VERSION 5.8 ;
BUSBITCHARS "[]" ;
DIVIDERCHAR "/" ;
UNITS
    DATABASE MICRONS 1000 ;
END UNITS

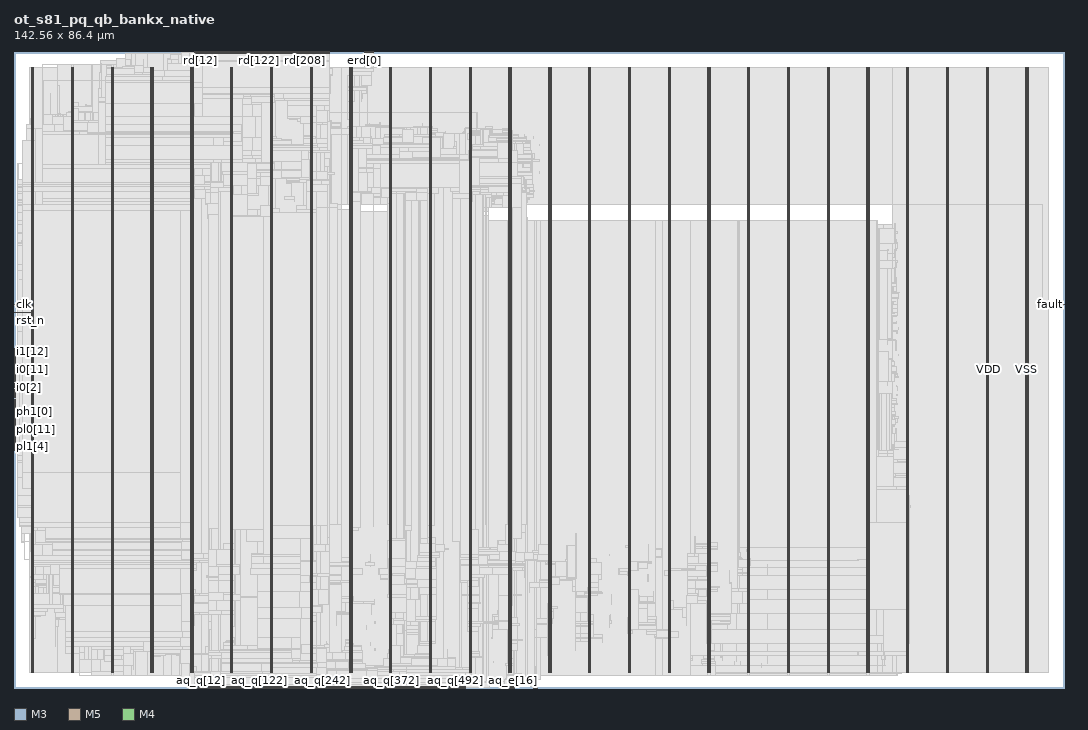
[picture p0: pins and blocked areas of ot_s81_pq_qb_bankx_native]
MACRO ot_s81_pq_qb_bankx_native
  FOREIGN ot_s81_pq_qb_bankx_native 0 0 ;
  CLASS BLOCK ;
  SIZE 142.56 BY 86.4 ;
  PIN aq_e[0]
    DIRECTION INPUT ;
    USE SIGNAL ;
    PORT
      LAYER M3 ;
        RECT  66.528 0 66.546 0.144 ;
    END
  END aq_e[0]
  PIN aq_e[10]
    DIRECTION INPUT ;
    USE SIGNAL ;
    PORT
      LAYER M3 ;
        RECT  67.248 0 67.266 0.144 ;
    END
  END aq_e[10]
  PIN aq_e[11]
    DIRECTION INPUT ;
    USE SIGNAL ;
    PORT
      LAYER M5 ;
        RECT  67.296 0 67.32 0.192 ;
    END
  END aq_e[11]
  PIN aq_e[12]
    DIRECTION INPUT ;
    USE SIGNAL ;
    PORT
      LAYER M3 ;
        RECT  67.392 0 67.41 0.144 ;
    END
  END aq_e[12]
  PIN aq_e[13]
    DIRECTION INPUT ;
    USE SIGNAL ;
    PORT
      LAYER M5 ;
        RECT  67.44 0 67.464 0.192 ;
    END
  END aq_e[13]
  PIN aq_e[14]
    DIRECTION INPUT ;
    USE SIGNAL ;
    PORT
      LAYER M3 ;
        RECT  67.536 0 67.554 0.144 ;
    END
  END aq_e[14]
  PIN aq_e[15]
    DIRECTION INPUT ;
    USE SIGNAL ;
    PORT
      LAYER M5 ;
        RECT  67.584 0 67.608 0.192 ;
    END
  END aq_e[15]
  PIN aq_e[16]
    DIRECTION INPUT ;
    USE SIGNAL ;
    PORT
      LAYER M3 ;
        RECT  67.68 0 67.698 0.144 ;
    END
  END aq_e[16]
  PIN aq_e[17]
    DIRECTION INPUT ;
    USE SIGNAL ;
    PORT
      LAYER M5 ;
        RECT  67.728 0 67.752 0.192 ;
    END
  END aq_e[17]
  PIN aq_e[18]
    DIRECTION INPUT ;
    USE SIGNAL ;
    PORT
      LAYER M3 ;
        RECT  67.824 0 67.842 0.144 ;
    END
  END aq_e[18]
  PIN aq_e[19]
    DIRECTION INPUT ;
    USE SIGNAL ;
    PORT
      LAYER M5 ;
        RECT  67.872 0 67.896 0.192 ;
    END
  END aq_e[19]
  PIN aq_e[1]
    DIRECTION INPUT ;
    USE SIGNAL ;
    PORT
      LAYER M5 ;
        RECT  66.576 0 66.6 0.192 ;
    END
  END aq_e[1]
  PIN aq_e[2]
    DIRECTION INPUT ;
    USE SIGNAL ;
    PORT
      LAYER M3 ;
        RECT  66.672 0 66.69 0.144 ;
    END
  END aq_e[2]
  PIN aq_e[3]
    DIRECTION INPUT ;
    USE SIGNAL ;
    PORT
      LAYER M5 ;
        RECT  66.72 0 66.744 0.192 ;
    END
  END aq_e[3]
  PIN aq_e[4]
    DIRECTION INPUT ;
    USE SIGNAL ;
    PORT
      LAYER M3 ;
        RECT  66.816 0 66.834 0.144 ;
    END
  END aq_e[4]
  PIN aq_e[5]
    DIRECTION INPUT ;
    USE SIGNAL ;
    PORT
      LAYER M5 ;
        RECT  66.864 0 66.888 0.192 ;
    END
  END aq_e[5]
  PIN aq_e[6]
    DIRECTION INPUT ;
    USE SIGNAL ;
    PORT
      LAYER M3 ;
        RECT  66.96 0 66.978 0.144 ;
    END
  END aq_e[6]
  PIN aq_e[7]
    DIRECTION INPUT ;
    USE SIGNAL ;
    PORT
      LAYER M5 ;
        RECT  67.008 0 67.032 0.192 ;
    END
  END aq_e[7]
  PIN aq_e[8]
    DIRECTION INPUT ;
    USE SIGNAL ;
    PORT
      LAYER M3 ;
        RECT  67.104 0 67.122 0.144 ;
    END
  END aq_e[8]
  PIN aq_e[9]
    DIRECTION INPUT ;
    USE SIGNAL ;
    PORT
      LAYER M5 ;
        RECT  67.152 0 67.176 0.192 ;
    END
  END aq_e[9]
  PIN aq_p[0]
    DIRECTION INPUT ;
    USE SIGNAL ;
    PORT
      LAYER M3 ;
        RECT  70.488 0 70.506 0.144 ;
    END
  END aq_p[0]
  PIN aq_p[1]
    DIRECTION INPUT ;
    USE SIGNAL ;
    PORT
      LAYER M5 ;
        RECT  70.512 0 70.536 0.192 ;
    END
  END aq_p[1]
  PIN aq_p[2]
    DIRECTION INPUT ;
    USE SIGNAL ;
    PORT
      LAYER M3 ;
        RECT  70.632 0 70.65 0.144 ;
    END
  END aq_p[2]
  PIN aq_p[3]
    DIRECTION INPUT ;
    USE SIGNAL ;
    PORT
      LAYER M5 ;
        RECT  70.656 0 70.68 0.192 ;
    END
  END aq_p[3]
  PIN aq_p[4]
    DIRECTION INPUT ;
    USE SIGNAL ;
    PORT
      LAYER M3 ;
        RECT  70.776 0 70.794 0.144 ;
    END
  END aq_p[4]
  PIN aq_p[5]
    DIRECTION INPUT ;
    USE SIGNAL ;
    PORT
      LAYER M5 ;
        RECT  70.8 0 70.824 0.192 ;
    END
  END aq_p[5]
  PIN aq_p[6]
    DIRECTION INPUT ;
    USE SIGNAL ;
    PORT
      LAYER M3 ;
        RECT  70.92 0 70.938 0.144 ;
    END
  END aq_p[6]
  PIN aq_p[7]
    DIRECTION INPUT ;
    USE SIGNAL ;
    PORT
      LAYER M5 ;
        RECT  70.944 0 70.968 0.192 ;
    END
  END aq_p[7]
  PIN aq_p[8]
    DIRECTION INPUT ;
    USE SIGNAL ;
    PORT
      LAYER M3 ;
        RECT  71.064 0 71.082 0.144 ;
    END
  END aq_p[8]
  PIN aq_p[9]
    DIRECTION INPUT ;
    USE SIGNAL ;
    PORT
      LAYER M5 ;
        RECT  71.088 0 71.112 0.192 ;
    END
  END aq_p[9]
  PIN aq_q[0]
    DIRECTION INPUT ;
    USE SIGNAL ;
    PORT
      LAYER M3 ;
        RECT  24.48 0 24.498 0.144 ;
    END
  END aq_q[0]
  PIN aq_q[100]
    DIRECTION INPUT ;
    USE SIGNAL ;
    PORT
      LAYER M3 ;
        RECT  31.68 0 31.698 0.144 ;
    END
  END aq_q[100]
  PIN aq_q[101]
    DIRECTION INPUT ;
    USE SIGNAL ;
    PORT
      LAYER M5 ;
        RECT  31.728 0 31.752 0.192 ;
    END
  END aq_q[101]
  PIN aq_q[102]
    DIRECTION INPUT ;
    USE SIGNAL ;
    PORT
      LAYER M3 ;
        RECT  31.824 0 31.842 0.144 ;
    END
  END aq_q[102]
  PIN aq_q[103]
    DIRECTION INPUT ;
    USE SIGNAL ;
    PORT
      LAYER M5 ;
        RECT  31.872 0 31.896 0.192 ;
    END
  END aq_q[103]
  PIN aq_q[104]
    DIRECTION INPUT ;
    USE SIGNAL ;
    PORT
      LAYER M3 ;
        RECT  31.968 0 31.986 0.144 ;
    END
  END aq_q[104]
  PIN aq_q[105]
    DIRECTION INPUT ;
    USE SIGNAL ;
    PORT
      LAYER M5 ;
        RECT  32.016 0 32.04 0.192 ;
    END
  END aq_q[105]
  PIN aq_q[106]
    DIRECTION INPUT ;
    USE SIGNAL ;
    PORT
      LAYER M3 ;
        RECT  32.112 0 32.13 0.144 ;
    END
  END aq_q[106]
  PIN aq_q[107]
    DIRECTION INPUT ;
    USE SIGNAL ;
    PORT
      LAYER M5 ;
        RECT  32.16 0 32.184 0.192 ;
    END
  END aq_q[107]
  PIN aq_q[108]
    DIRECTION INPUT ;
    USE SIGNAL ;
    PORT
      LAYER M3 ;
        RECT  32.256 0 32.274 0.144 ;
    END
  END aq_q[108]
  PIN aq_q[109]
    DIRECTION INPUT ;
    USE SIGNAL ;
    PORT
      LAYER M5 ;
        RECT  32.304 0 32.328 0.192 ;
    END
  END aq_q[109]
  PIN aq_q[10]
    DIRECTION INPUT ;
    USE SIGNAL ;
    PORT
      LAYER M3 ;
        RECT  25.2 0 25.218 0.144 ;
    END
  END aq_q[10]
  PIN aq_q[110]
    DIRECTION INPUT ;
    USE SIGNAL ;
    PORT
      LAYER M3 ;
        RECT  32.4 0 32.418 0.144 ;
    END
  END aq_q[110]
  PIN aq_q[111]
    DIRECTION INPUT ;
    USE SIGNAL ;
    PORT
      LAYER M5 ;
        RECT  32.448 0 32.472 0.192 ;
    END
  END aq_q[111]
  PIN aq_q[112]
    DIRECTION INPUT ;
    USE SIGNAL ;
    PORT
      LAYER M3 ;
        RECT  32.544 0 32.562 0.144 ;
    END
  END aq_q[112]
  PIN aq_q[113]
    DIRECTION INPUT ;
    USE SIGNAL ;
    PORT
      LAYER M5 ;
        RECT  32.592 0 32.616 0.192 ;
    END
  END aq_q[113]
  PIN aq_q[114]
    DIRECTION INPUT ;
    USE SIGNAL ;
    PORT
      LAYER M3 ;
        RECT  32.688 0 32.706 0.144 ;
    END
  END aq_q[114]
  PIN aq_q[115]
    DIRECTION INPUT ;
    USE SIGNAL ;
    PORT
      LAYER M5 ;
        RECT  32.736 0 32.76 0.192 ;
    END
  END aq_q[115]
  PIN aq_q[116]
    DIRECTION INPUT ;
    USE SIGNAL ;
    PORT
      LAYER M3 ;
        RECT  32.832 0 32.85 0.144 ;
    END
  END aq_q[116]
  PIN aq_q[117]
    DIRECTION INPUT ;
    USE SIGNAL ;
    PORT
      LAYER M5 ;
        RECT  32.88 0 32.904 0.192 ;
    END
  END aq_q[117]
  PIN aq_q[118]
    DIRECTION INPUT ;
    USE SIGNAL ;
    PORT
      LAYER M3 ;
        RECT  32.976 0 32.994 0.144 ;
    END
  END aq_q[118]
  PIN aq_q[119]
    DIRECTION INPUT ;
    USE SIGNAL ;
    PORT
      LAYER M5 ;
        RECT  33.024 0 33.048 0.192 ;
    END
  END aq_q[119]
  PIN aq_q[11]
    DIRECTION INPUT ;
    USE SIGNAL ;
    PORT
      LAYER M5 ;
        RECT  25.248 0 25.272 0.192 ;
    END
  END aq_q[11]
  PIN aq_q[120]
    DIRECTION INPUT ;
    USE SIGNAL ;
    PORT
      LAYER M3 ;
        RECT  33.12 0 33.138 0.144 ;
    END
  END aq_q[120]
  PIN aq_q[121]
    DIRECTION INPUT ;
    USE SIGNAL ;
    PORT
      LAYER M5 ;
        RECT  33.168 0 33.192 0.192 ;
    END
  END aq_q[121]
  PIN aq_q[122]
    DIRECTION INPUT ;
    USE SIGNAL ;
    PORT
      LAYER M3 ;
        RECT  33.264 0 33.282 0.144 ;
    END
  END aq_q[122]
  PIN aq_q[123]
    DIRECTION INPUT ;
    USE SIGNAL ;
    PORT
      LAYER M5 ;
        RECT  33.312 0 33.336 0.192 ;
    END
  END aq_q[123]
  PIN aq_q[124]
    DIRECTION INPUT ;
    USE SIGNAL ;
    PORT
      LAYER M3 ;
        RECT  33.408 0 33.426 0.144 ;
    END
  END aq_q[124]
  PIN aq_q[125]
    DIRECTION INPUT ;
    USE SIGNAL ;
    PORT
      LAYER M5 ;
        RECT  33.456 0 33.48 0.192 ;
    END
  END aq_q[125]
  PIN aq_q[126]
    DIRECTION INPUT ;
    USE SIGNAL ;
    PORT
      LAYER M3 ;
        RECT  33.552 0 33.57 0.144 ;
    END
  END aq_q[126]
  PIN aq_q[127]
    DIRECTION INPUT ;
    USE SIGNAL ;
    PORT
      LAYER M5 ;
        RECT  33.6 0 33.624 0.192 ;
    END
  END aq_q[127]
  PIN aq_q[128]
    DIRECTION INPUT ;
    USE SIGNAL ;
    PORT
      LAYER M3 ;
        RECT  33.696 0 33.714 0.144 ;
    END
  END aq_q[128]
  PIN aq_q[129]
    DIRECTION INPUT ;
    USE SIGNAL ;
    PORT
      LAYER M5 ;
        RECT  33.744 0 33.768 0.192 ;
    END
  END aq_q[129]
  PIN aq_q[12]
    DIRECTION INPUT ;
    USE SIGNAL ;
    PORT
      LAYER M3 ;
        RECT  25.344 0 25.362 0.144 ;
    END
  END aq_q[12]
  PIN aq_q[130]
    DIRECTION INPUT ;
    USE SIGNAL ;
    PORT
      LAYER M3 ;
        RECT  33.84 0 33.858 0.144 ;
    END
  END aq_q[130]
  PIN aq_q[131]
    DIRECTION INPUT ;
    USE SIGNAL ;
    PORT
      LAYER M5 ;
        RECT  33.888 0 33.912 0.192 ;
    END
  END aq_q[131]
  PIN aq_q[132]
    DIRECTION INPUT ;
    USE SIGNAL ;
    PORT
      LAYER M3 ;
        RECT  33.984 0 34.002 0.144 ;
    END
  END aq_q[132]
  PIN aq_q[133]
    DIRECTION INPUT ;
    USE SIGNAL ;
    PORT
      LAYER M5 ;
        RECT  34.032 0 34.056 0.192 ;
    END
  END aq_q[133]
  PIN aq_q[134]
    DIRECTION INPUT ;
    USE SIGNAL ;
    PORT
      LAYER M3 ;
        RECT  34.128 0 34.146 0.144 ;
    END
  END aq_q[134]
  PIN aq_q[135]
    DIRECTION INPUT ;
    USE SIGNAL ;
    PORT
      LAYER M5 ;
        RECT  34.176 0 34.2 0.192 ;
    END
  END aq_q[135]
  PIN aq_q[136]
    DIRECTION INPUT ;
    USE SIGNAL ;
    PORT
      LAYER M3 ;
        RECT  34.272 0 34.29 0.144 ;
    END
  END aq_q[136]
  PIN aq_q[137]
    DIRECTION INPUT ;
    USE SIGNAL ;
    PORT
      LAYER M5 ;
        RECT  34.32 0 34.344 0.192 ;
    END
  END aq_q[137]
  PIN aq_q[138]
    DIRECTION INPUT ;
    USE SIGNAL ;
    PORT
      LAYER M3 ;
        RECT  34.416 0 34.434 0.144 ;
    END
  END aq_q[138]
  PIN aq_q[139]
    DIRECTION INPUT ;
    USE SIGNAL ;
    PORT
      LAYER M5 ;
        RECT  34.464 0 34.488 0.192 ;
    END
  END aq_q[139]
  PIN aq_q[13]
    DIRECTION INPUT ;
    USE SIGNAL ;
    PORT
      LAYER M5 ;
        RECT  25.392 0 25.416 0.192 ;
    END
  END aq_q[13]
  PIN aq_q[140]
    DIRECTION INPUT ;
    USE SIGNAL ;
    PORT
      LAYER M3 ;
        RECT  34.56 0 34.578 0.144 ;
    END
  END aq_q[140]
  PIN aq_q[141]
    DIRECTION INPUT ;
    USE SIGNAL ;
    PORT
      LAYER M5 ;
        RECT  34.608 0 34.632 0.192 ;
    END
  END aq_q[141]
  PIN aq_q[142]
    DIRECTION INPUT ;
    USE SIGNAL ;
    PORT
      LAYER M3 ;
        RECT  34.704 0 34.722 0.144 ;
    END
  END aq_q[142]
  PIN aq_q[143]
    DIRECTION INPUT ;
    USE SIGNAL ;
    PORT
      LAYER M5 ;
        RECT  34.752 0 34.776 0.192 ;
    END
  END aq_q[143]
  PIN aq_q[144]
    DIRECTION INPUT ;
    USE SIGNAL ;
    PORT
      LAYER M3 ;
        RECT  34.848 0 34.866 0.144 ;
    END
  END aq_q[144]
  PIN aq_q[145]
    DIRECTION INPUT ;
    USE SIGNAL ;
    PORT
      LAYER M5 ;
        RECT  34.896 0 34.92 0.192 ;
    END
  END aq_q[145]
  PIN aq_q[146]
    DIRECTION INPUT ;
    USE SIGNAL ;
    PORT
      LAYER M3 ;
        RECT  34.992 0 35.01 0.144 ;
    END
  END aq_q[146]
  PIN aq_q[147]
    DIRECTION INPUT ;
    USE SIGNAL ;
    PORT
      LAYER M5 ;
        RECT  35.04 0 35.064 0.192 ;
    END
  END aq_q[147]
  PIN aq_q[148]
    DIRECTION INPUT ;
    USE SIGNAL ;
    PORT
      LAYER M3 ;
        RECT  35.136 0 35.154 0.144 ;
    END
  END aq_q[148]
  PIN aq_q[149]
    DIRECTION INPUT ;
    USE SIGNAL ;
    PORT
      LAYER M5 ;
        RECT  35.184 0 35.208 0.192 ;
    END
  END aq_q[149]
  PIN aq_q[14]
    DIRECTION INPUT ;
    USE SIGNAL ;
    PORT
      LAYER M3 ;
        RECT  25.488 0 25.506 0.144 ;
    END
  END aq_q[14]
  PIN aq_q[150]
    DIRECTION INPUT ;
    USE SIGNAL ;
    PORT
      LAYER M3 ;
        RECT  35.28 0 35.298 0.144 ;
    END
  END aq_q[150]
  PIN aq_q[151]
    DIRECTION INPUT ;
    USE SIGNAL ;
    PORT
      LAYER M5 ;
        RECT  35.328 0 35.352 0.192 ;
    END
  END aq_q[151]
  PIN aq_q[152]
    DIRECTION INPUT ;
    USE SIGNAL ;
    PORT
      LAYER M3 ;
        RECT  35.424 0 35.442 0.144 ;
    END
  END aq_q[152]
  PIN aq_q[153]
    DIRECTION INPUT ;
    USE SIGNAL ;
    PORT
      LAYER M5 ;
        RECT  35.472 0 35.496 0.192 ;
    END
  END aq_q[153]
  PIN aq_q[154]
    DIRECTION INPUT ;
    USE SIGNAL ;
    PORT
      LAYER M3 ;
        RECT  35.568 0 35.586 0.144 ;
    END
  END aq_q[154]
  PIN aq_q[155]
    DIRECTION INPUT ;
    USE SIGNAL ;
    PORT
      LAYER M5 ;
        RECT  35.616 0 35.64 0.192 ;
    END
  END aq_q[155]
  PIN aq_q[156]
    DIRECTION INPUT ;
    USE SIGNAL ;
    PORT
      LAYER M3 ;
        RECT  35.712 0 35.73 0.144 ;
    END
  END aq_q[156]
  PIN aq_q[157]
    DIRECTION INPUT ;
    USE SIGNAL ;
    PORT
      LAYER M5 ;
        RECT  35.76 0 35.784 0.192 ;
    END
  END aq_q[157]
  PIN aq_q[158]
    DIRECTION INPUT ;
    USE SIGNAL ;
    PORT
      LAYER M3 ;
        RECT  35.856 0 35.874 0.144 ;
    END
  END aq_q[158]
  PIN aq_q[159]
    DIRECTION INPUT ;
    USE SIGNAL ;
    PORT
      LAYER M5 ;
        RECT  35.904 0 35.928 0.192 ;
    END
  END aq_q[159]
  PIN aq_q[15]
    DIRECTION INPUT ;
    USE SIGNAL ;
    PORT
      LAYER M5 ;
        RECT  25.536 0 25.56 0.192 ;
    END
  END aq_q[15]
  PIN aq_q[160]
    DIRECTION INPUT ;
    USE SIGNAL ;
    PORT
      LAYER M3 ;
        RECT  36 0 36.018 0.144 ;
    END
  END aq_q[160]
  PIN aq_q[161]
    DIRECTION INPUT ;
    USE SIGNAL ;
    PORT
      LAYER M5 ;
        RECT  36.048 0 36.072 0.192 ;
    END
  END aq_q[161]
  PIN aq_q[162]
    DIRECTION INPUT ;
    USE SIGNAL ;
    PORT
      LAYER M3 ;
        RECT  36.144 0 36.162 0.144 ;
    END
  END aq_q[162]
  PIN aq_q[163]
    DIRECTION INPUT ;
    USE SIGNAL ;
    PORT
      LAYER M5 ;
        RECT  36.192 0 36.216 0.192 ;
    END
  END aq_q[163]
  PIN aq_q[164]
    DIRECTION INPUT ;
    USE SIGNAL ;
    PORT
      LAYER M3 ;
        RECT  36.288 0 36.306 0.144 ;
    END
  END aq_q[164]
  PIN aq_q[165]
    DIRECTION INPUT ;
    USE SIGNAL ;
    PORT
      LAYER M5 ;
        RECT  36.336 0 36.36 0.192 ;
    END
  END aq_q[165]
  PIN aq_q[166]
    DIRECTION INPUT ;
    USE SIGNAL ;
    PORT
      LAYER M3 ;
        RECT  36.432 0 36.45 0.144 ;
    END
  END aq_q[166]
  PIN aq_q[167]
    DIRECTION INPUT ;
    USE SIGNAL ;
    PORT
      LAYER M5 ;
        RECT  36.48 0 36.504 0.192 ;
    END
  END aq_q[167]
  PIN aq_q[168]
    DIRECTION INPUT ;
    USE SIGNAL ;
    PORT
      LAYER M3 ;
        RECT  36.576 0 36.594 0.144 ;
    END
  END aq_q[168]
  PIN aq_q[169]
    DIRECTION INPUT ;
    USE SIGNAL ;
    PORT
      LAYER M5 ;
        RECT  36.624 0 36.648 0.192 ;
    END
  END aq_q[169]
  PIN aq_q[16]
    DIRECTION INPUT ;
    USE SIGNAL ;
    PORT
      LAYER M3 ;
        RECT  25.632 0 25.65 0.144 ;
    END
  END aq_q[16]
  PIN aq_q[170]
    DIRECTION INPUT ;
    USE SIGNAL ;
    PORT
      LAYER M3 ;
        RECT  36.72 0 36.738 0.144 ;
    END
  END aq_q[170]
  PIN aq_q[171]
    DIRECTION INPUT ;
    USE SIGNAL ;
    PORT
      LAYER M5 ;
        RECT  36.768 0 36.792 0.192 ;
    END
  END aq_q[171]
  PIN aq_q[172]
    DIRECTION INPUT ;
    USE SIGNAL ;
    PORT
      LAYER M3 ;
        RECT  36.864 0 36.882 0.144 ;
    END
  END aq_q[172]
  PIN aq_q[173]
    DIRECTION INPUT ;
    USE SIGNAL ;
    PORT
      LAYER M5 ;
        RECT  36.912 0 36.936 0.192 ;
    END
  END aq_q[173]
  PIN aq_q[174]
    DIRECTION INPUT ;
    USE SIGNAL ;
    PORT
      LAYER M3 ;
        RECT  37.008 0 37.026 0.144 ;
    END
  END aq_q[174]
  PIN aq_q[175]
    DIRECTION INPUT ;
    USE SIGNAL ;
    PORT
      LAYER M5 ;
        RECT  37.056 0 37.08 0.192 ;
    END
  END aq_q[175]
  PIN aq_q[176]
    DIRECTION INPUT ;
    USE SIGNAL ;
    PORT
      LAYER M3 ;
        RECT  37.152 0 37.17 0.144 ;
    END
  END aq_q[176]
  PIN aq_q[177]
    DIRECTION INPUT ;
    USE SIGNAL ;
    PORT
      LAYER M5 ;
        RECT  37.2 0 37.224 0.192 ;
    END
  END aq_q[177]
  PIN aq_q[178]
    DIRECTION INPUT ;
    USE SIGNAL ;
    PORT
      LAYER M3 ;
        RECT  37.296 0 37.314 0.144 ;
    END
  END aq_q[178]
  PIN aq_q[179]
    DIRECTION INPUT ;
    USE SIGNAL ;
    PORT
      LAYER M5 ;
        RECT  37.344 0 37.368 0.192 ;
    END
  END aq_q[179]
  PIN aq_q[17]
    DIRECTION INPUT ;
    USE SIGNAL ;
    PORT
      LAYER M5 ;
        RECT  25.68 0 25.704 0.192 ;
    END
  END aq_q[17]
  PIN aq_q[180]
    DIRECTION INPUT ;
    USE SIGNAL ;
    PORT
      LAYER M3 ;
        RECT  37.44 0 37.458 0.144 ;
    END
  END aq_q[180]
  PIN aq_q[181]
    DIRECTION INPUT ;
    USE SIGNAL ;
    PORT
      LAYER M5 ;
        RECT  37.488 0 37.512 0.192 ;
    END
  END aq_q[181]
  PIN aq_q[182]
    DIRECTION INPUT ;
    USE SIGNAL ;
    PORT
      LAYER M3 ;
        RECT  37.584 0 37.602 0.144 ;
    END
  END aq_q[182]
  PIN aq_q[183]
    DIRECTION INPUT ;
    USE SIGNAL ;
    PORT
      LAYER M5 ;
        RECT  37.632 0 37.656 0.192 ;
    END
  END aq_q[183]
  PIN aq_q[184]
    DIRECTION INPUT ;
    USE SIGNAL ;
    PORT
      LAYER M3 ;
        RECT  37.728 0 37.746 0.144 ;
    END
  END aq_q[184]
  PIN aq_q[185]
    DIRECTION INPUT ;
    USE SIGNAL ;
    PORT
      LAYER M5 ;
        RECT  37.776 0 37.8 0.192 ;
    END
  END aq_q[185]
  PIN aq_q[186]
    DIRECTION INPUT ;
    USE SIGNAL ;
    PORT
      LAYER M3 ;
        RECT  37.872 0 37.89 0.144 ;
    END
  END aq_q[186]
  PIN aq_q[187]
    DIRECTION INPUT ;
    USE SIGNAL ;
    PORT
      LAYER M5 ;
        RECT  37.92 0 37.944 0.192 ;
    END
  END aq_q[187]
  PIN aq_q[188]
    DIRECTION INPUT ;
    USE SIGNAL ;
    PORT
      LAYER M3 ;
        RECT  38.016 0 38.034 0.144 ;
    END
  END aq_q[188]
  PIN aq_q[189]
    DIRECTION INPUT ;
    USE SIGNAL ;
    PORT
      LAYER M5 ;
        RECT  38.064 0 38.088 0.192 ;
    END
  END aq_q[189]
  PIN aq_q[18]
    DIRECTION INPUT ;
    USE SIGNAL ;
    PORT
      LAYER M3 ;
        RECT  25.776 0 25.794 0.144 ;
    END
  END aq_q[18]
  PIN aq_q[190]
    DIRECTION INPUT ;
    USE SIGNAL ;
    PORT
      LAYER M3 ;
        RECT  38.16 0 38.178 0.144 ;
    END
  END aq_q[190]
  PIN aq_q[191]
    DIRECTION INPUT ;
    USE SIGNAL ;
    PORT
      LAYER M5 ;
        RECT  38.208 0 38.232 0.192 ;
    END
  END aq_q[191]
  PIN aq_q[192]
    DIRECTION INPUT ;
    USE SIGNAL ;
    PORT
      LAYER M3 ;
        RECT  38.304 0 38.322 0.144 ;
    END
  END aq_q[192]
  PIN aq_q[193]
    DIRECTION INPUT ;
    USE SIGNAL ;
    PORT
      LAYER M5 ;
        RECT  38.352 0 38.376 0.192 ;
    END
  END aq_q[193]
  PIN aq_q[194]
    DIRECTION INPUT ;
    USE SIGNAL ;
    PORT
      LAYER M3 ;
        RECT  38.448 0 38.466 0.144 ;
    END
  END aq_q[194]
  PIN aq_q[195]
    DIRECTION INPUT ;
    USE SIGNAL ;
    PORT
      LAYER M5 ;
        RECT  38.496 0 38.52 0.192 ;
    END
  END aq_q[195]
  PIN aq_q[196]
    DIRECTION INPUT ;
    USE SIGNAL ;
    PORT
      LAYER M3 ;
        RECT  38.592 0 38.61 0.144 ;
    END
  END aq_q[196]
  PIN aq_q[197]
    DIRECTION INPUT ;
    USE SIGNAL ;
    PORT
      LAYER M5 ;
        RECT  38.64 0 38.664 0.192 ;
    END
  END aq_q[197]
  PIN aq_q[198]
    DIRECTION INPUT ;
    USE SIGNAL ;
    PORT
      LAYER M3 ;
        RECT  38.736 0 38.754 0.144 ;
    END
  END aq_q[198]
  PIN aq_q[199]
    DIRECTION INPUT ;
    USE SIGNAL ;
    PORT
      LAYER M5 ;
        RECT  38.784 0 38.808 0.192 ;
    END
  END aq_q[199]
  PIN aq_q[19]
    DIRECTION INPUT ;
    USE SIGNAL ;
    PORT
      LAYER M5 ;
        RECT  25.824 0 25.848 0.192 ;
    END
  END aq_q[19]
  PIN aq_q[1]
    DIRECTION INPUT ;
    USE SIGNAL ;
    PORT
      LAYER M5 ;
        RECT  24.528 0 24.552 0.192 ;
    END
  END aq_q[1]
  PIN aq_q[200]
    DIRECTION INPUT ;
    USE SIGNAL ;
    PORT
      LAYER M3 ;
        RECT  38.88 0 38.898 0.144 ;
    END
  END aq_q[200]
  PIN aq_q[201]
    DIRECTION INPUT ;
    USE SIGNAL ;
    PORT
      LAYER M5 ;
        RECT  38.928 0 38.952 0.192 ;
    END
  END aq_q[201]
  PIN aq_q[202]
    DIRECTION INPUT ;
    USE SIGNAL ;
    PORT
      LAYER M3 ;
        RECT  39.024 0 39.042 0.144 ;
    END
  END aq_q[202]
  PIN aq_q[203]
    DIRECTION INPUT ;
    USE SIGNAL ;
    PORT
      LAYER M5 ;
        RECT  39.072 0 39.096 0.192 ;
    END
  END aq_q[203]
  PIN aq_q[204]
    DIRECTION INPUT ;
    USE SIGNAL ;
    PORT
      LAYER M3 ;
        RECT  39.168 0 39.186 0.144 ;
    END
  END aq_q[204]
  PIN aq_q[205]
    DIRECTION INPUT ;
    USE SIGNAL ;
    PORT
      LAYER M5 ;
        RECT  39.216 0 39.24 0.192 ;
    END
  END aq_q[205]
  PIN aq_q[206]
    DIRECTION INPUT ;
    USE SIGNAL ;
    PORT
      LAYER M3 ;
        RECT  39.312 0 39.33 0.144 ;
    END
  END aq_q[206]
  PIN aq_q[207]
    DIRECTION INPUT ;
    USE SIGNAL ;
    PORT
      LAYER M5 ;
        RECT  39.36 0 39.384 0.192 ;
    END
  END aq_q[207]
  PIN aq_q[208]
    DIRECTION INPUT ;
    USE SIGNAL ;
    PORT
      LAYER M3 ;
        RECT  39.456 0 39.474 0.144 ;
    END
  END aq_q[208]
  PIN aq_q[209]
    DIRECTION INPUT ;
    USE SIGNAL ;
    PORT
      LAYER M5 ;
        RECT  39.504 0 39.528 0.192 ;
    END
  END aq_q[209]
  PIN aq_q[20]
    DIRECTION INPUT ;
    USE SIGNAL ;
    PORT
      LAYER M3 ;
        RECT  25.92 0 25.938 0.144 ;
    END
  END aq_q[20]
  PIN aq_q[210]
    DIRECTION INPUT ;
    USE SIGNAL ;
    PORT
      LAYER M3 ;
        RECT  39.6 0 39.618 0.144 ;
    END
  END aq_q[210]
  PIN aq_q[211]
    DIRECTION INPUT ;
    USE SIGNAL ;
    PORT
      LAYER M5 ;
        RECT  39.648 0 39.672 0.192 ;
    END
  END aq_q[211]
  PIN aq_q[212]
    DIRECTION INPUT ;
    USE SIGNAL ;
    PORT
      LAYER M3 ;
        RECT  39.744 0 39.762 0.144 ;
    END
  END aq_q[212]
  PIN aq_q[213]
    DIRECTION INPUT ;
    USE SIGNAL ;
    PORT
      LAYER M5 ;
        RECT  39.792 0 39.816 0.192 ;
    END
  END aq_q[213]
  PIN aq_q[214]
    DIRECTION INPUT ;
    USE SIGNAL ;
    PORT
      LAYER M3 ;
        RECT  39.888 0 39.906 0.144 ;
    END
  END aq_q[214]
  PIN aq_q[215]
    DIRECTION INPUT ;
    USE SIGNAL ;
    PORT
      LAYER M5 ;
        RECT  39.936 0 39.96 0.192 ;
    END
  END aq_q[215]
  PIN aq_q[216]
    DIRECTION INPUT ;
    USE SIGNAL ;
    PORT
      LAYER M3 ;
        RECT  40.032 0 40.05 0.144 ;
    END
  END aq_q[216]
  PIN aq_q[217]
    DIRECTION INPUT ;
    USE SIGNAL ;
    PORT
      LAYER M5 ;
        RECT  40.08 0 40.104 0.192 ;
    END
  END aq_q[217]
  PIN aq_q[218]
    DIRECTION INPUT ;
    USE SIGNAL ;
    PORT
      LAYER M3 ;
        RECT  40.176 0 40.194 0.144 ;
    END
  END aq_q[218]
  PIN aq_q[219]
    DIRECTION INPUT ;
    USE SIGNAL ;
    PORT
      LAYER M5 ;
        RECT  40.224 0 40.248 0.192 ;
    END
  END aq_q[219]
  PIN aq_q[21]
    DIRECTION INPUT ;
    USE SIGNAL ;
    PORT
      LAYER M5 ;
        RECT  25.968 0 25.992 0.192 ;
    END
  END aq_q[21]
  PIN aq_q[220]
    DIRECTION INPUT ;
    USE SIGNAL ;
    PORT
      LAYER M3 ;
        RECT  40.32 0 40.338 0.144 ;
    END
  END aq_q[220]
  PIN aq_q[221]
    DIRECTION INPUT ;
    USE SIGNAL ;
    PORT
      LAYER M5 ;
        RECT  40.368 0 40.392 0.192 ;
    END
  END aq_q[221]
  PIN aq_q[222]
    DIRECTION INPUT ;
    USE SIGNAL ;
    PORT
      LAYER M3 ;
        RECT  40.464 0 40.482 0.144 ;
    END
  END aq_q[222]
  PIN aq_q[223]
    DIRECTION INPUT ;
    USE SIGNAL ;
    PORT
      LAYER M5 ;
        RECT  40.512 0 40.536 0.192 ;
    END
  END aq_q[223]
  PIN aq_q[224]
    DIRECTION INPUT ;
    USE SIGNAL ;
    PORT
      LAYER M3 ;
        RECT  40.608 0 40.626 0.144 ;
    END
  END aq_q[224]
  PIN aq_q[225]
    DIRECTION INPUT ;
    USE SIGNAL ;
    PORT
      LAYER M5 ;
        RECT  40.656 0 40.68 0.192 ;
    END
  END aq_q[225]
  PIN aq_q[226]
    DIRECTION INPUT ;
    USE SIGNAL ;
    PORT
      LAYER M3 ;
        RECT  40.752 0 40.77 0.144 ;
    END
  END aq_q[226]
  PIN aq_q[227]
    DIRECTION INPUT ;
    USE SIGNAL ;
    PORT
      LAYER M5 ;
        RECT  40.8 0 40.824 0.192 ;
    END
  END aq_q[227]
  PIN aq_q[228]
    DIRECTION INPUT ;
    USE SIGNAL ;
    PORT
      LAYER M3 ;
        RECT  40.896 0 40.914 0.144 ;
    END
  END aq_q[228]
  PIN aq_q[229]
    DIRECTION INPUT ;
    USE SIGNAL ;
    PORT
      LAYER M5 ;
        RECT  40.944 0 40.968 0.192 ;
    END
  END aq_q[229]
  PIN aq_q[22]
    DIRECTION INPUT ;
    USE SIGNAL ;
    PORT
      LAYER M3 ;
        RECT  26.064 0 26.082 0.144 ;
    END
  END aq_q[22]
  PIN aq_q[230]
    DIRECTION INPUT ;
    USE SIGNAL ;
    PORT
      LAYER M3 ;
        RECT  41.04 0 41.058 0.144 ;
    END
  END aq_q[230]
  PIN aq_q[231]
    DIRECTION INPUT ;
    USE SIGNAL ;
    PORT
      LAYER M5 ;
        RECT  41.088 0 41.112 0.192 ;
    END
  END aq_q[231]
  PIN aq_q[232]
    DIRECTION INPUT ;
    USE SIGNAL ;
    PORT
      LAYER M3 ;
        RECT  41.184 0 41.202 0.144 ;
    END
  END aq_q[232]
  PIN aq_q[233]
    DIRECTION INPUT ;
    USE SIGNAL ;
    PORT
      LAYER M5 ;
        RECT  41.232 0 41.256 0.192 ;
    END
  END aq_q[233]
  PIN aq_q[234]
    DIRECTION INPUT ;
    USE SIGNAL ;
    PORT
      LAYER M3 ;
        RECT  41.328 0 41.346 0.144 ;
    END
  END aq_q[234]
  PIN aq_q[235]
    DIRECTION INPUT ;
    USE SIGNAL ;
    PORT
      LAYER M5 ;
        RECT  41.376 0 41.4 0.192 ;
    END
  END aq_q[235]
  PIN aq_q[236]
    DIRECTION INPUT ;
    USE SIGNAL ;
    PORT
      LAYER M3 ;
        RECT  41.472 0 41.49 0.144 ;
    END
  END aq_q[236]
  PIN aq_q[237]
    DIRECTION INPUT ;
    USE SIGNAL ;
    PORT
      LAYER M5 ;
        RECT  41.52 0 41.544 0.192 ;
    END
  END aq_q[237]
  PIN aq_q[238]
    DIRECTION INPUT ;
    USE SIGNAL ;
    PORT
      LAYER M3 ;
        RECT  41.616 0 41.634 0.144 ;
    END
  END aq_q[238]
  PIN aq_q[239]
    DIRECTION INPUT ;
    USE SIGNAL ;
    PORT
      LAYER M5 ;
        RECT  41.664 0 41.688 0.192 ;
    END
  END aq_q[239]
  PIN aq_q[23]
    DIRECTION INPUT ;
    USE SIGNAL ;
    PORT
      LAYER M5 ;
        RECT  26.112 0 26.136 0.192 ;
    END
  END aq_q[23]
  PIN aq_q[240]
    DIRECTION INPUT ;
    USE SIGNAL ;
    PORT
      LAYER M3 ;
        RECT  41.76 0 41.778 0.144 ;
    END
  END aq_q[240]
  PIN aq_q[241]
    DIRECTION INPUT ;
    USE SIGNAL ;
    PORT
      LAYER M5 ;
        RECT  41.808 0 41.832 0.192 ;
    END
  END aq_q[241]
  PIN aq_q[242]
    DIRECTION INPUT ;
    USE SIGNAL ;
    PORT
      LAYER M3 ;
        RECT  41.904 0 41.922 0.144 ;
    END
  END aq_q[242]
  PIN aq_q[243]
    DIRECTION INPUT ;
    USE SIGNAL ;
    PORT
      LAYER M5 ;
        RECT  41.952 0 41.976 0.192 ;
    END
  END aq_q[243]
  PIN aq_q[244]
    DIRECTION INPUT ;
    USE SIGNAL ;
    PORT
      LAYER M3 ;
        RECT  42.048 0 42.066 0.144 ;
    END
  END aq_q[244]
  PIN aq_q[245]
    DIRECTION INPUT ;
    USE SIGNAL ;
    PORT
      LAYER M5 ;
        RECT  42.096 0 42.12 0.192 ;
    END
  END aq_q[245]
  PIN aq_q[246]
    DIRECTION INPUT ;
    USE SIGNAL ;
    PORT
      LAYER M3 ;
        RECT  42.192 0 42.21 0.144 ;
    END
  END aq_q[246]
  PIN aq_q[247]
    DIRECTION INPUT ;
    USE SIGNAL ;
    PORT
      LAYER M5 ;
        RECT  42.24 0 42.264 0.192 ;
    END
  END aq_q[247]
  PIN aq_q[248]
    DIRECTION INPUT ;
    USE SIGNAL ;
    PORT
      LAYER M3 ;
        RECT  42.336 0 42.354 0.144 ;
    END
  END aq_q[248]
  PIN aq_q[249]
    DIRECTION INPUT ;
    USE SIGNAL ;
    PORT
      LAYER M5 ;
        RECT  42.384 0 42.408 0.192 ;
    END
  END aq_q[249]
  PIN aq_q[24]
    DIRECTION INPUT ;
    USE SIGNAL ;
    PORT
      LAYER M3 ;
        RECT  26.208 0 26.226 0.144 ;
    END
  END aq_q[24]
  PIN aq_q[250]
    DIRECTION INPUT ;
    USE SIGNAL ;
    PORT
      LAYER M3 ;
        RECT  42.48 0 42.498 0.144 ;
    END
  END aq_q[250]
  PIN aq_q[251]
    DIRECTION INPUT ;
    USE SIGNAL ;
    PORT
      LAYER M5 ;
        RECT  42.528 0 42.552 0.192 ;
    END
  END aq_q[251]
  PIN aq_q[252]
    DIRECTION INPUT ;
    USE SIGNAL ;
    PORT
      LAYER M3 ;
        RECT  42.624 0 42.642 0.144 ;
    END
    PORT
      LAYER M3 ;
        RECT  42.588 0.067 42.714 0.103 ;
    END
  END aq_q[252]
  PIN aq_q[253]
    DIRECTION INPUT ;
    USE SIGNAL ;
    PORT
      LAYER M5 ;
        RECT  42.672 0 42.696 0.192 ;
    END
  END aq_q[253]
  PIN aq_q[254]
    DIRECTION INPUT ;
    USE SIGNAL ;
    PORT
      LAYER M3 ;
        RECT  42.768 0 42.786 0.144 ;
    END
  END aq_q[254]
  PIN aq_q[255]
    DIRECTION INPUT ;
    USE SIGNAL ;
    PORT
      LAYER M5 ;
        RECT  42.816 0 42.84 0.192 ;
    END
  END aq_q[255]
  PIN aq_q[256]
    DIRECTION INPUT ;
    USE SIGNAL ;
    PORT
      LAYER M3 ;
        RECT  42.912 0 42.93 0.144 ;
    END
  END aq_q[256]
  PIN aq_q[257]
    DIRECTION INPUT ;
    USE SIGNAL ;
    PORT
      LAYER M5 ;
        RECT  42.96 0 42.984 0.192 ;
    END
  END aq_q[257]
  PIN aq_q[258]
    DIRECTION INPUT ;
    USE SIGNAL ;
    PORT
      LAYER M3 ;
        RECT  43.056 0 43.074 0.144 ;
    END
  END aq_q[258]
  PIN aq_q[259]
    DIRECTION INPUT ;
    USE SIGNAL ;
    PORT
      LAYER M5 ;
        RECT  43.104 0 43.128 0.192 ;
    END
  END aq_q[259]
  PIN aq_q[25]
    DIRECTION INPUT ;
    USE SIGNAL ;
    PORT
      LAYER M5 ;
        RECT  26.256 0 26.28 0.192 ;
    END
  END aq_q[25]
  PIN aq_q[260]
    DIRECTION INPUT ;
    USE SIGNAL ;
    PORT
      LAYER M3 ;
        RECT  43.2 0 43.218 0.144 ;
    END
  END aq_q[260]
  PIN aq_q[261]
    DIRECTION INPUT ;
    USE SIGNAL ;
    PORT
      LAYER M5 ;
        RECT  43.248 0 43.272 0.192 ;
    END
  END aq_q[261]
  PIN aq_q[262]
    DIRECTION INPUT ;
    USE SIGNAL ;
    PORT
      LAYER M3 ;
        RECT  43.344 0 43.362 0.144 ;
    END
  END aq_q[262]
  PIN aq_q[263]
    DIRECTION INPUT ;
    USE SIGNAL ;
    PORT
      LAYER M5 ;
        RECT  43.392 0 43.416 0.192 ;
    END
  END aq_q[263]
  PIN aq_q[264]
    DIRECTION INPUT ;
    USE SIGNAL ;
    PORT
      LAYER M3 ;
        RECT  43.488 0 43.506 0.144 ;
    END
  END aq_q[264]
  PIN aq_q[265]
    DIRECTION INPUT ;
    USE SIGNAL ;
    PORT
      LAYER M5 ;
        RECT  43.536 0 43.56 0.192 ;
    END
  END aq_q[265]
  PIN aq_q[266]
    DIRECTION INPUT ;
    USE SIGNAL ;
    PORT
      LAYER M3 ;
        RECT  43.632 0 43.65 0.144 ;
    END
  END aq_q[266]
  PIN aq_q[267]
    DIRECTION INPUT ;
    USE SIGNAL ;
    PORT
      LAYER M5 ;
        RECT  43.68 0 43.704 0.192 ;
    END
  END aq_q[267]
  PIN aq_q[268]
    DIRECTION INPUT ;
    USE SIGNAL ;
    PORT
      LAYER M3 ;
        RECT  43.776 0 43.794 0.144 ;
    END
  END aq_q[268]
  PIN aq_q[269]
    DIRECTION INPUT ;
    USE SIGNAL ;
    PORT
      LAYER M5 ;
        RECT  43.824 0 43.848 0.192 ;
    END
  END aq_q[269]
  PIN aq_q[26]
    DIRECTION INPUT ;
    USE SIGNAL ;
    PORT
      LAYER M3 ;
        RECT  26.352 0 26.37 0.144 ;
    END
  END aq_q[26]
  PIN aq_q[270]
    DIRECTION INPUT ;
    USE SIGNAL ;
    PORT
      LAYER M3 ;
        RECT  43.92 0 43.938 0.144 ;
    END
  END aq_q[270]
  PIN aq_q[271]
    DIRECTION INPUT ;
    USE SIGNAL ;
    PORT
      LAYER M5 ;
        RECT  43.968 0 43.992 0.192 ;
    END
  END aq_q[271]
  PIN aq_q[272]
    DIRECTION INPUT ;
    USE SIGNAL ;
    PORT
      LAYER M3 ;
        RECT  44.064 0 44.082 0.144 ;
    END
  END aq_q[272]
  PIN aq_q[273]
    DIRECTION INPUT ;
    USE SIGNAL ;
    PORT
      LAYER M5 ;
        RECT  44.112 0 44.136 0.192 ;
    END
  END aq_q[273]
  PIN aq_q[274]
    DIRECTION INPUT ;
    USE SIGNAL ;
    PORT
      LAYER M3 ;
        RECT  44.208 0 44.226 0.144 ;
    END
  END aq_q[274]
  PIN aq_q[275]
    DIRECTION INPUT ;
    USE SIGNAL ;
    PORT
      LAYER M5 ;
        RECT  44.256 0 44.28 0.192 ;
    END
  END aq_q[275]
  PIN aq_q[276]
    DIRECTION INPUT ;
    USE SIGNAL ;
    PORT
      LAYER M3 ;
        RECT  44.352 0 44.37 0.144 ;
    END
  END aq_q[276]
  PIN aq_q[277]
    DIRECTION INPUT ;
    USE SIGNAL ;
    PORT
      LAYER M5 ;
        RECT  44.4 0 44.424 0.192 ;
    END
  END aq_q[277]
  PIN aq_q[278]
    DIRECTION INPUT ;
    USE SIGNAL ;
    PORT
      LAYER M3 ;
        RECT  44.496 0 44.514 0.144 ;
    END
  END aq_q[278]
  PIN aq_q[279]
    DIRECTION INPUT ;
    USE SIGNAL ;
    PORT
      LAYER M5 ;
        RECT  44.544 0 44.568 0.192 ;
    END
  END aq_q[279]
  PIN aq_q[27]
    DIRECTION INPUT ;
    USE SIGNAL ;
    PORT
      LAYER M5 ;
        RECT  26.4 0 26.424 0.192 ;
    END
  END aq_q[27]
  PIN aq_q[280]
    DIRECTION INPUT ;
    USE SIGNAL ;
    PORT
      LAYER M3 ;
        RECT  44.64 0 44.658 0.144 ;
    END
  END aq_q[280]
  PIN aq_q[281]
    DIRECTION INPUT ;
    USE SIGNAL ;
    PORT
      LAYER M5 ;
        RECT  44.688 0 44.712 0.192 ;
    END
  END aq_q[281]
  PIN aq_q[282]
    DIRECTION INPUT ;
    USE SIGNAL ;
    PORT
      LAYER M3 ;
        RECT  44.784 0 44.802 0.144 ;
    END
  END aq_q[282]
  PIN aq_q[283]
    DIRECTION INPUT ;
    USE SIGNAL ;
    PORT
      LAYER M5 ;
        RECT  44.832 0 44.856 0.192 ;
    END
  END aq_q[283]
  PIN aq_q[284]
    DIRECTION INPUT ;
    USE SIGNAL ;
    PORT
      LAYER M3 ;
        RECT  44.928 0 44.946 0.144 ;
    END
  END aq_q[284]
  PIN aq_q[285]
    DIRECTION INPUT ;
    USE SIGNAL ;
    PORT
      LAYER M5 ;
        RECT  44.976 0 45 0.192 ;
    END
  END aq_q[285]
  PIN aq_q[286]
    DIRECTION INPUT ;
    USE SIGNAL ;
    PORT
      LAYER M3 ;
        RECT  45.072 0 45.09 0.144 ;
    END
  END aq_q[286]
  PIN aq_q[287]
    DIRECTION INPUT ;
    USE SIGNAL ;
    PORT
      LAYER M5 ;
        RECT  45.12 0 45.144 0.192 ;
    END
  END aq_q[287]
  PIN aq_q[288]
    DIRECTION INPUT ;
    USE SIGNAL ;
    PORT
      LAYER M3 ;
        RECT  45.216 0 45.234 0.144 ;
    END
  END aq_q[288]
  PIN aq_q[289]
    DIRECTION INPUT ;
    USE SIGNAL ;
    PORT
      LAYER M5 ;
        RECT  45.264 0 45.288 0.192 ;
    END
  END aq_q[289]
  PIN aq_q[28]
    DIRECTION INPUT ;
    USE SIGNAL ;
    PORT
      LAYER M3 ;
        RECT  26.496 0 26.514 0.144 ;
    END
  END aq_q[28]
  PIN aq_q[290]
    DIRECTION INPUT ;
    USE SIGNAL ;
    PORT
      LAYER M3 ;
        RECT  45.36 0 45.378 0.144 ;
    END
  END aq_q[290]
  PIN aq_q[291]
    DIRECTION INPUT ;
    USE SIGNAL ;
    PORT
      LAYER M5 ;
        RECT  45.408 0 45.432 0.192 ;
    END
  END aq_q[291]
  PIN aq_q[292]
    DIRECTION INPUT ;
    USE SIGNAL ;
    PORT
      LAYER M3 ;
        RECT  45.504 0 45.522 0.144 ;
    END
  END aq_q[292]
  PIN aq_q[293]
    DIRECTION INPUT ;
    USE SIGNAL ;
    PORT
      LAYER M5 ;
        RECT  45.552 0 45.576 0.192 ;
    END
  END aq_q[293]
  PIN aq_q[294]
    DIRECTION INPUT ;
    USE SIGNAL ;
    PORT
      LAYER M3 ;
        RECT  45.648 0 45.666 0.144 ;
    END
  END aq_q[294]
  PIN aq_q[295]
    DIRECTION INPUT ;
    USE SIGNAL ;
    PORT
      LAYER M5 ;
        RECT  45.696 0 45.72 0.192 ;
    END
  END aq_q[295]
  PIN aq_q[296]
    DIRECTION INPUT ;
    USE SIGNAL ;
    PORT
      LAYER M3 ;
        RECT  45.792 0 45.81 0.144 ;
    END
  END aq_q[296]
  PIN aq_q[297]
    DIRECTION INPUT ;
    USE SIGNAL ;
    PORT
      LAYER M5 ;
        RECT  45.84 0 45.864 0.192 ;
    END
  END aq_q[297]
  PIN aq_q[298]
    DIRECTION INPUT ;
    USE SIGNAL ;
    PORT
      LAYER M3 ;
        RECT  45.936 0 45.954 0.144 ;
    END
  END aq_q[298]
  PIN aq_q[299]
    DIRECTION INPUT ;
    USE SIGNAL ;
    PORT
      LAYER M5 ;
        RECT  45.984 0 46.008 0.192 ;
    END
  END aq_q[299]
  PIN aq_q[29]
    DIRECTION INPUT ;
    USE SIGNAL ;
    PORT
      LAYER M5 ;
        RECT  26.544 0 26.568 0.192 ;
    END
  END aq_q[29]
  PIN aq_q[2]
    DIRECTION INPUT ;
    USE SIGNAL ;
    PORT
      LAYER M3 ;
        RECT  24.624 0 24.642 0.144 ;
    END
  END aq_q[2]
  PIN aq_q[300]
    DIRECTION INPUT ;
    USE SIGNAL ;
    PORT
      LAYER M3 ;
        RECT  46.08 0 46.098 0.144 ;
    END
  END aq_q[300]
  PIN aq_q[301]
    DIRECTION INPUT ;
    USE SIGNAL ;
    PORT
      LAYER M5 ;
        RECT  46.128 0 46.152 0.192 ;
    END
  END aq_q[301]
  PIN aq_q[302]
    DIRECTION INPUT ;
    USE SIGNAL ;
    PORT
      LAYER M3 ;
        RECT  46.224 0 46.242 0.144 ;
    END
  END aq_q[302]
  PIN aq_q[303]
    DIRECTION INPUT ;
    USE SIGNAL ;
    PORT
      LAYER M5 ;
        RECT  46.272 0 46.296 0.192 ;
    END
  END aq_q[303]
  PIN aq_q[304]
    DIRECTION INPUT ;
    USE SIGNAL ;
    PORT
      LAYER M3 ;
        RECT  46.368 0 46.386 0.144 ;
    END
  END aq_q[304]
  PIN aq_q[305]
    DIRECTION INPUT ;
    USE SIGNAL ;
    PORT
      LAYER M5 ;
        RECT  46.416 0 46.44 0.192 ;
    END
  END aq_q[305]
  PIN aq_q[306]
    DIRECTION INPUT ;
    USE SIGNAL ;
    PORT
      LAYER M3 ;
        RECT  46.512 0 46.53 0.144 ;
    END
  END aq_q[306]
  PIN aq_q[307]
    DIRECTION INPUT ;
    USE SIGNAL ;
    PORT
      LAYER M5 ;
        RECT  46.56 0 46.584 0.192 ;
    END
  END aq_q[307]
  PIN aq_q[308]
    DIRECTION INPUT ;
    USE SIGNAL ;
    PORT
      LAYER M3 ;
        RECT  46.656 0 46.674 0.144 ;
    END
  END aq_q[308]
  PIN aq_q[309]
    DIRECTION INPUT ;
    USE SIGNAL ;
    PORT
      LAYER M5 ;
        RECT  46.704 0 46.728 0.192 ;
    END
  END aq_q[309]
  PIN aq_q[30]
    DIRECTION INPUT ;
    USE SIGNAL ;
    PORT
      LAYER M3 ;
        RECT  26.64 0 26.658 0.144 ;
    END
  END aq_q[30]
  PIN aq_q[310]
    DIRECTION INPUT ;
    USE SIGNAL ;
    PORT
      LAYER M3 ;
        RECT  46.8 0 46.818 0.144 ;
    END
  END aq_q[310]
  PIN aq_q[311]
    DIRECTION INPUT ;
    USE SIGNAL ;
    PORT
      LAYER M5 ;
        RECT  46.848 0 46.872 0.192 ;
    END
  END aq_q[311]
  PIN aq_q[312]
    DIRECTION INPUT ;
    USE SIGNAL ;
    PORT
      LAYER M3 ;
        RECT  46.944 0 46.962 0.144 ;
    END
  END aq_q[312]
  PIN aq_q[313]
    DIRECTION INPUT ;
    USE SIGNAL ;
    PORT
      LAYER M5 ;
        RECT  46.992 0 47.016 0.192 ;
    END
  END aq_q[313]
  PIN aq_q[314]
    DIRECTION INPUT ;
    USE SIGNAL ;
    PORT
      LAYER M3 ;
        RECT  47.088 0 47.106 0.144 ;
    END
  END aq_q[314]
  PIN aq_q[315]
    DIRECTION INPUT ;
    USE SIGNAL ;
    PORT
      LAYER M5 ;
        RECT  47.136 0 47.16 0.192 ;
    END
  END aq_q[315]
  PIN aq_q[316]
    DIRECTION INPUT ;
    USE SIGNAL ;
    PORT
      LAYER M3 ;
        RECT  47.232 0 47.25 0.144 ;
    END
  END aq_q[316]
  PIN aq_q[317]
    DIRECTION INPUT ;
    USE SIGNAL ;
    PORT
      LAYER M5 ;
        RECT  47.28 0 47.304 0.192 ;
    END
  END aq_q[317]
  PIN aq_q[318]
    DIRECTION INPUT ;
    USE SIGNAL ;
    PORT
      LAYER M3 ;
        RECT  47.376 0 47.394 0.144 ;
    END
  END aq_q[318]
  PIN aq_q[319]
    DIRECTION INPUT ;
    USE SIGNAL ;
    PORT
      LAYER M5 ;
        RECT  47.424 0 47.448 0.192 ;
    END
  END aq_q[319]
  PIN aq_q[31]
    DIRECTION INPUT ;
    USE SIGNAL ;
    PORT
      LAYER M5 ;
        RECT  26.688 0 26.712 0.192 ;
    END
  END aq_q[31]
  PIN aq_q[320]
    DIRECTION INPUT ;
    USE SIGNAL ;
    PORT
      LAYER M3 ;
        RECT  47.52 0 47.538 0.144 ;
    END
  END aq_q[320]
  PIN aq_q[321]
    DIRECTION INPUT ;
    USE SIGNAL ;
    PORT
      LAYER M5 ;
        RECT  47.568 0 47.592 0.192 ;
    END
  END aq_q[321]
  PIN aq_q[322]
    DIRECTION INPUT ;
    USE SIGNAL ;
    PORT
      LAYER M3 ;
        RECT  47.664 0 47.682 0.144 ;
    END
  END aq_q[322]
  PIN aq_q[323]
    DIRECTION INPUT ;
    USE SIGNAL ;
    PORT
      LAYER M5 ;
        RECT  47.712 0 47.736 0.192 ;
    END
  END aq_q[323]
  PIN aq_q[324]
    DIRECTION INPUT ;
    USE SIGNAL ;
    PORT
      LAYER M3 ;
        RECT  47.808 0 47.826 0.144 ;
    END
  END aq_q[324]
  PIN aq_q[325]
    DIRECTION INPUT ;
    USE SIGNAL ;
    PORT
      LAYER M5 ;
        RECT  47.856 0 47.88 0.192 ;
    END
  END aq_q[325]
  PIN aq_q[326]
    DIRECTION INPUT ;
    USE SIGNAL ;
    PORT
      LAYER M3 ;
        RECT  47.952 0 47.97 0.144 ;
    END
  END aq_q[326]
  PIN aq_q[327]
    DIRECTION INPUT ;
    USE SIGNAL ;
    PORT
      LAYER M5 ;
        RECT  48 0 48.024 0.192 ;
    END
  END aq_q[327]
  PIN aq_q[328]
    DIRECTION INPUT ;
    USE SIGNAL ;
    PORT
      LAYER M3 ;
        RECT  48.096 0 48.114 0.144 ;
    END
  END aq_q[328]
  PIN aq_q[329]
    DIRECTION INPUT ;
    USE SIGNAL ;
    PORT
      LAYER M5 ;
        RECT  48.144 0 48.168 0.192 ;
    END
  END aq_q[329]
  PIN aq_q[32]
    DIRECTION INPUT ;
    USE SIGNAL ;
    PORT
      LAYER M3 ;
        RECT  26.784 0 26.802 0.144 ;
    END
  END aq_q[32]
  PIN aq_q[330]
    DIRECTION INPUT ;
    USE SIGNAL ;
    PORT
      LAYER M3 ;
        RECT  48.24 0 48.258 0.144 ;
    END
  END aq_q[330]
  PIN aq_q[331]
    DIRECTION INPUT ;
    USE SIGNAL ;
    PORT
      LAYER M5 ;
        RECT  48.288 0 48.312 0.192 ;
    END
  END aq_q[331]
  PIN aq_q[332]
    DIRECTION INPUT ;
    USE SIGNAL ;
    PORT
      LAYER M3 ;
        RECT  48.384 0 48.402 0.144 ;
    END
  END aq_q[332]
  PIN aq_q[333]
    DIRECTION INPUT ;
    USE SIGNAL ;
    PORT
      LAYER M5 ;
        RECT  48.432 0 48.456 0.192 ;
    END
  END aq_q[333]
  PIN aq_q[334]
    DIRECTION INPUT ;
    USE SIGNAL ;
    PORT
      LAYER M3 ;
        RECT  48.528 0 48.546 0.144 ;
    END
  END aq_q[334]
  PIN aq_q[335]
    DIRECTION INPUT ;
    USE SIGNAL ;
    PORT
      LAYER M5 ;
        RECT  48.576 0 48.6 0.192 ;
    END
  END aq_q[335]
  PIN aq_q[336]
    DIRECTION INPUT ;
    USE SIGNAL ;
    PORT
      LAYER M3 ;
        RECT  48.672 0 48.69 0.144 ;
    END
  END aq_q[336]
  PIN aq_q[337]
    DIRECTION INPUT ;
    USE SIGNAL ;
    PORT
      LAYER M5 ;
        RECT  48.72 0 48.744 0.192 ;
    END
  END aq_q[337]
  PIN aq_q[338]
    DIRECTION INPUT ;
    USE SIGNAL ;
    PORT
      LAYER M3 ;
        RECT  48.816 0 48.834 0.144 ;
    END
  END aq_q[338]
  PIN aq_q[339]
    DIRECTION INPUT ;
    USE SIGNAL ;
    PORT
      LAYER M5 ;
        RECT  48.864 0 48.888 0.192 ;
    END
  END aq_q[339]
  PIN aq_q[33]
    DIRECTION INPUT ;
    USE SIGNAL ;
    PORT
      LAYER M5 ;
        RECT  26.832 0 26.856 0.192 ;
    END
  END aq_q[33]
  PIN aq_q[340]
    DIRECTION INPUT ;
    USE SIGNAL ;
    PORT
      LAYER M3 ;
        RECT  48.96 0 48.978 0.144 ;
    END
  END aq_q[340]
  PIN aq_q[341]
    DIRECTION INPUT ;
    USE SIGNAL ;
    PORT
      LAYER M5 ;
        RECT  49.008 0 49.032 0.192 ;
    END
  END aq_q[341]
  PIN aq_q[342]
    DIRECTION INPUT ;
    USE SIGNAL ;
    PORT
      LAYER M3 ;
        RECT  49.104 0 49.122 0.144 ;
    END
  END aq_q[342]
  PIN aq_q[343]
    DIRECTION INPUT ;
    USE SIGNAL ;
    PORT
      LAYER M5 ;
        RECT  49.152 0 49.176 0.192 ;
    END
  END aq_q[343]
  PIN aq_q[344]
    DIRECTION INPUT ;
    USE SIGNAL ;
    PORT
      LAYER M3 ;
        RECT  49.248 0 49.266 0.144 ;
    END
  END aq_q[344]
  PIN aq_q[345]
    DIRECTION INPUT ;
    USE SIGNAL ;
    PORT
      LAYER M5 ;
        RECT  49.296 0 49.32 0.192 ;
    END
  END aq_q[345]
  PIN aq_q[346]
    DIRECTION INPUT ;
    USE SIGNAL ;
    PORT
      LAYER M3 ;
        RECT  49.392 0 49.41 0.144 ;
    END
  END aq_q[346]
  PIN aq_q[347]
    DIRECTION INPUT ;
    USE SIGNAL ;
    PORT
      LAYER M5 ;
        RECT  49.44 0 49.464 0.192 ;
    END
  END aq_q[347]
  PIN aq_q[348]
    DIRECTION INPUT ;
    USE SIGNAL ;
    PORT
      LAYER M3 ;
        RECT  49.536 0 49.554 0.144 ;
    END
  END aq_q[348]
  PIN aq_q[349]
    DIRECTION INPUT ;
    USE SIGNAL ;
    PORT
      LAYER M5 ;
        RECT  49.584 0 49.608 0.192 ;
    END
  END aq_q[349]
  PIN aq_q[34]
    DIRECTION INPUT ;
    USE SIGNAL ;
    PORT
      LAYER M3 ;
        RECT  26.928 0 26.946 0.144 ;
    END
  END aq_q[34]
  PIN aq_q[350]
    DIRECTION INPUT ;
    USE SIGNAL ;
    PORT
      LAYER M3 ;
        RECT  49.68 0 49.698 0.144 ;
    END
  END aq_q[350]
  PIN aq_q[351]
    DIRECTION INPUT ;
    USE SIGNAL ;
    PORT
      LAYER M5 ;
        RECT  49.728 0 49.752 0.192 ;
    END
  END aq_q[351]
  PIN aq_q[352]
    DIRECTION INPUT ;
    USE SIGNAL ;
    PORT
      LAYER M3 ;
        RECT  49.824 0 49.842 0.144 ;
    END
  END aq_q[352]
  PIN aq_q[353]
    DIRECTION INPUT ;
    USE SIGNAL ;
    PORT
      LAYER M5 ;
        RECT  49.872 0 49.896 0.192 ;
    END
  END aq_q[353]
  PIN aq_q[354]
    DIRECTION INPUT ;
    USE SIGNAL ;
    PORT
      LAYER M3 ;
        RECT  49.968 0 49.986 0.144 ;
    END
  END aq_q[354]
  PIN aq_q[355]
    DIRECTION INPUT ;
    USE SIGNAL ;
    PORT
      LAYER M5 ;
        RECT  50.016 0 50.04 0.192 ;
    END
  END aq_q[355]
  PIN aq_q[356]
    DIRECTION INPUT ;
    USE SIGNAL ;
    PORT
      LAYER M3 ;
        RECT  50.112 0 50.13 0.144 ;
    END
  END aq_q[356]
  PIN aq_q[357]
    DIRECTION INPUT ;
    USE SIGNAL ;
    PORT
      LAYER M5 ;
        RECT  50.16 0 50.184 0.192 ;
    END
  END aq_q[357]
  PIN aq_q[358]
    DIRECTION INPUT ;
    USE SIGNAL ;
    PORT
      LAYER M3 ;
        RECT  50.256 0 50.274 0.144 ;
    END
  END aq_q[358]
  PIN aq_q[359]
    DIRECTION INPUT ;
    USE SIGNAL ;
    PORT
      LAYER M5 ;
        RECT  50.304 0 50.328 0.192 ;
    END
  END aq_q[359]
  PIN aq_q[35]
    DIRECTION INPUT ;
    USE SIGNAL ;
    PORT
      LAYER M5 ;
        RECT  26.976 0 27 0.192 ;
    END
  END aq_q[35]
  PIN aq_q[360]
    DIRECTION INPUT ;
    USE SIGNAL ;
    PORT
      LAYER M3 ;
        RECT  50.4 0 50.418 0.144 ;
    END
  END aq_q[360]
  PIN aq_q[361]
    DIRECTION INPUT ;
    USE SIGNAL ;
    PORT
      LAYER M5 ;
        RECT  50.448 0 50.472 0.192 ;
    END
  END aq_q[361]
  PIN aq_q[362]
    DIRECTION INPUT ;
    USE SIGNAL ;
    PORT
      LAYER M3 ;
        RECT  50.544 0 50.562 0.144 ;
    END
  END aq_q[362]
  PIN aq_q[363]
    DIRECTION INPUT ;
    USE SIGNAL ;
    PORT
      LAYER M5 ;
        RECT  50.592 0 50.616 0.192 ;
    END
  END aq_q[363]
  PIN aq_q[364]
    DIRECTION INPUT ;
    USE SIGNAL ;
    PORT
      LAYER M3 ;
        RECT  50.688 0 50.706 0.144 ;
    END
  END aq_q[364]
  PIN aq_q[365]
    DIRECTION INPUT ;
    USE SIGNAL ;
    PORT
      LAYER M5 ;
        RECT  50.736 0 50.76 0.192 ;
    END
  END aq_q[365]
  PIN aq_q[366]
    DIRECTION INPUT ;
    USE SIGNAL ;
    PORT
      LAYER M3 ;
        RECT  50.832 0 50.85 0.144 ;
    END
  END aq_q[366]
  PIN aq_q[367]
    DIRECTION INPUT ;
    USE SIGNAL ;
    PORT
      LAYER M5 ;
        RECT  50.88 0 50.904 0.192 ;
    END
  END aq_q[367]
  PIN aq_q[368]
    DIRECTION INPUT ;
    USE SIGNAL ;
    PORT
      LAYER M3 ;
        RECT  50.976 0 50.994 0.144 ;
    END
  END aq_q[368]
  PIN aq_q[369]
    DIRECTION INPUT ;
    USE SIGNAL ;
    PORT
      LAYER M5 ;
        RECT  51.024 0 51.048 0.192 ;
    END
  END aq_q[369]
  PIN aq_q[36]
    DIRECTION INPUT ;
    USE SIGNAL ;
    PORT
      LAYER M3 ;
        RECT  27.072 0 27.09 0.144 ;
    END
  END aq_q[36]
  PIN aq_q[370]
    DIRECTION INPUT ;
    USE SIGNAL ;
    PORT
      LAYER M3 ;
        RECT  51.12 0 51.138 0.144 ;
    END
  END aq_q[370]
  PIN aq_q[371]
    DIRECTION INPUT ;
    USE SIGNAL ;
    PORT
      LAYER M5 ;
        RECT  51.168 0 51.192 0.192 ;
    END
  END aq_q[371]
  PIN aq_q[372]
    DIRECTION INPUT ;
    USE SIGNAL ;
    PORT
      LAYER M3 ;
        RECT  51.264 0 51.282 0.144 ;
    END
  END aq_q[372]
  PIN aq_q[373]
    DIRECTION INPUT ;
    USE SIGNAL ;
    PORT
      LAYER M5 ;
        RECT  51.312 0 51.336 0.192 ;
    END
  END aq_q[373]
  PIN aq_q[374]
    DIRECTION INPUT ;
    USE SIGNAL ;
    PORT
      LAYER M3 ;
        RECT  51.408 0 51.426 0.144 ;
    END
  END aq_q[374]
  PIN aq_q[375]
    DIRECTION INPUT ;
    USE SIGNAL ;
    PORT
      LAYER M5 ;
        RECT  51.456 0 51.48 0.192 ;
    END
  END aq_q[375]
  PIN aq_q[376]
    DIRECTION INPUT ;
    USE SIGNAL ;
    PORT
      LAYER M3 ;
        RECT  51.552 0 51.57 0.144 ;
    END
  END aq_q[376]
  PIN aq_q[377]
    DIRECTION INPUT ;
    USE SIGNAL ;
    PORT
      LAYER M5 ;
        RECT  51.6 0 51.624 0.192 ;
    END
  END aq_q[377]
  PIN aq_q[378]
    DIRECTION INPUT ;
    USE SIGNAL ;
    PORT
      LAYER M3 ;
        RECT  51.696 0 51.714 0.144 ;
    END
  END aq_q[378]
  PIN aq_q[379]
    DIRECTION INPUT ;
    USE SIGNAL ;
    PORT
      LAYER M5 ;
        RECT  51.744 0 51.768 0.192 ;
    END
  END aq_q[379]
  PIN aq_q[37]
    DIRECTION INPUT ;
    USE SIGNAL ;
    PORT
      LAYER M5 ;
        RECT  27.12 0 27.144 0.192 ;
    END
  END aq_q[37]
  PIN aq_q[380]
    DIRECTION INPUT ;
    USE SIGNAL ;
    PORT
      LAYER M3 ;
        RECT  51.84 0 51.858 0.144 ;
    END
  END aq_q[380]
  PIN aq_q[381]
    DIRECTION INPUT ;
    USE SIGNAL ;
    PORT
      LAYER M5 ;
        RECT  51.888 0 51.912 0.192 ;
    END
  END aq_q[381]
  PIN aq_q[382]
    DIRECTION INPUT ;
    USE SIGNAL ;
    PORT
      LAYER M3 ;
        RECT  51.984 0 52.002 0.144 ;
    END
  END aq_q[382]
  PIN aq_q[383]
    DIRECTION INPUT ;
    USE SIGNAL ;
    PORT
      LAYER M5 ;
        RECT  52.032 0 52.056 0.192 ;
    END
  END aq_q[383]
  PIN aq_q[384]
    DIRECTION INPUT ;
    USE SIGNAL ;
    PORT
      LAYER M3 ;
        RECT  52.128 0 52.146 0.144 ;
    END
  END aq_q[384]
  PIN aq_q[385]
    DIRECTION INPUT ;
    USE SIGNAL ;
    PORT
      LAYER M5 ;
        RECT  52.176 0 52.2 0.192 ;
    END
  END aq_q[385]
  PIN aq_q[386]
    DIRECTION INPUT ;
    USE SIGNAL ;
    PORT
      LAYER M3 ;
        RECT  52.272 0 52.29 0.144 ;
    END
  END aq_q[386]
  PIN aq_q[387]
    DIRECTION INPUT ;
    USE SIGNAL ;
    PORT
      LAYER M5 ;
        RECT  52.32 0 52.344 0.192 ;
    END
  END aq_q[387]
  PIN aq_q[388]
    DIRECTION INPUT ;
    USE SIGNAL ;
    PORT
      LAYER M3 ;
        RECT  52.416 0 52.434 0.144 ;
    END
  END aq_q[388]
  PIN aq_q[389]
    DIRECTION INPUT ;
    USE SIGNAL ;
    PORT
      LAYER M5 ;
        RECT  52.464 0 52.488 0.192 ;
    END
  END aq_q[389]
  PIN aq_q[38]
    DIRECTION INPUT ;
    USE SIGNAL ;
    PORT
      LAYER M3 ;
        RECT  27.216 0 27.234 0.144 ;
    END
  END aq_q[38]
  PIN aq_q[390]
    DIRECTION INPUT ;
    USE SIGNAL ;
    PORT
      LAYER M3 ;
        RECT  52.56 0 52.578 0.144 ;
    END
  END aq_q[390]
  PIN aq_q[391]
    DIRECTION INPUT ;
    USE SIGNAL ;
    PORT
      LAYER M5 ;
        RECT  52.608 0 52.632 0.192 ;
    END
  END aq_q[391]
  PIN aq_q[392]
    DIRECTION INPUT ;
    USE SIGNAL ;
    PORT
      LAYER M3 ;
        RECT  52.704 0 52.722 0.144 ;
    END
  END aq_q[392]
  PIN aq_q[393]
    DIRECTION INPUT ;
    USE SIGNAL ;
    PORT
      LAYER M5 ;
        RECT  52.752 0 52.776 0.192 ;
    END
  END aq_q[393]
  PIN aq_q[394]
    DIRECTION INPUT ;
    USE SIGNAL ;
    PORT
      LAYER M3 ;
        RECT  52.848 0 52.866 0.144 ;
    END
  END aq_q[394]
  PIN aq_q[395]
    DIRECTION INPUT ;
    USE SIGNAL ;
    PORT
      LAYER M5 ;
        RECT  52.896 0 52.92 0.192 ;
    END
  END aq_q[395]
  PIN aq_q[396]
    DIRECTION INPUT ;
    USE SIGNAL ;
    PORT
      LAYER M3 ;
        RECT  52.992 0 53.01 0.144 ;
    END
  END aq_q[396]
  PIN aq_q[397]
    DIRECTION INPUT ;
    USE SIGNAL ;
    PORT
      LAYER M5 ;
        RECT  53.04 0 53.064 0.192 ;
    END
  END aq_q[397]
  PIN aq_q[398]
    DIRECTION INPUT ;
    USE SIGNAL ;
    PORT
      LAYER M3 ;
        RECT  53.136 0 53.154 0.144 ;
    END
  END aq_q[398]
  PIN aq_q[399]
    DIRECTION INPUT ;
    USE SIGNAL ;
    PORT
      LAYER M5 ;
        RECT  53.184 0 53.208 0.192 ;
    END
  END aq_q[399]
  PIN aq_q[39]
    DIRECTION INPUT ;
    USE SIGNAL ;
    PORT
      LAYER M5 ;
        RECT  27.264 0 27.288 0.192 ;
    END
  END aq_q[39]
  PIN aq_q[3]
    DIRECTION INPUT ;
    USE SIGNAL ;
    PORT
      LAYER M5 ;
        RECT  24.672 0 24.696 0.192 ;
    END
  END aq_q[3]
  PIN aq_q[400]
    DIRECTION INPUT ;
    USE SIGNAL ;
    PORT
      LAYER M3 ;
        RECT  53.28 0 53.298 0.144 ;
    END
  END aq_q[400]
  PIN aq_q[401]
    DIRECTION INPUT ;
    USE SIGNAL ;
    PORT
      LAYER M5 ;
        RECT  53.328 0 53.352 0.192 ;
    END
  END aq_q[401]
  PIN aq_q[402]
    DIRECTION INPUT ;
    USE SIGNAL ;
    PORT
      LAYER M3 ;
        RECT  53.424 0 53.442 0.144 ;
    END
  END aq_q[402]
  PIN aq_q[403]
    DIRECTION INPUT ;
    USE SIGNAL ;
    PORT
      LAYER M5 ;
        RECT  53.472 0 53.496 0.192 ;
    END
  END aq_q[403]
  PIN aq_q[404]
    DIRECTION INPUT ;
    USE SIGNAL ;
    PORT
      LAYER M3 ;
        RECT  53.568 0 53.586 0.144 ;
    END
  END aq_q[404]
  PIN aq_q[405]
    DIRECTION INPUT ;
    USE SIGNAL ;
    PORT
      LAYER M5 ;
        RECT  53.616 0 53.64 0.192 ;
    END
  END aq_q[405]
  PIN aq_q[406]
    DIRECTION INPUT ;
    USE SIGNAL ;
    PORT
      LAYER M3 ;
        RECT  53.712 0 53.73 0.144 ;
    END
  END aq_q[406]
  PIN aq_q[407]
    DIRECTION INPUT ;
    USE SIGNAL ;
    PORT
      LAYER M5 ;
        RECT  53.76 0 53.784 0.192 ;
    END
  END aq_q[407]
  PIN aq_q[408]
    DIRECTION INPUT ;
    USE SIGNAL ;
    PORT
      LAYER M3 ;
        RECT  53.856 0 53.874 0.144 ;
    END
  END aq_q[408]
  PIN aq_q[409]
    DIRECTION INPUT ;
    USE SIGNAL ;
    PORT
      LAYER M5 ;
        RECT  53.904 0 53.928 0.192 ;
    END
  END aq_q[409]
  PIN aq_q[40]
    DIRECTION INPUT ;
    USE SIGNAL ;
    PORT
      LAYER M3 ;
        RECT  27.36 0 27.378 0.144 ;
    END
  END aq_q[40]
  PIN aq_q[410]
    DIRECTION INPUT ;
    USE SIGNAL ;
    PORT
      LAYER M3 ;
        RECT  54 0 54.018 0.144 ;
    END
  END aq_q[410]
  PIN aq_q[411]
    DIRECTION INPUT ;
    USE SIGNAL ;
    PORT
      LAYER M5 ;
        RECT  54.048 0 54.072 0.192 ;
    END
  END aq_q[411]
  PIN aq_q[412]
    DIRECTION INPUT ;
    USE SIGNAL ;
    PORT
      LAYER M3 ;
        RECT  54.144 0 54.162 0.144 ;
    END
  END aq_q[412]
  PIN aq_q[413]
    DIRECTION INPUT ;
    USE SIGNAL ;
    PORT
      LAYER M5 ;
        RECT  54.192 0 54.216 0.192 ;
    END
  END aq_q[413]
  PIN aq_q[414]
    DIRECTION INPUT ;
    USE SIGNAL ;
    PORT
      LAYER M3 ;
        RECT  54.288 0 54.306 0.144 ;
    END
  END aq_q[414]
  PIN aq_q[415]
    DIRECTION INPUT ;
    USE SIGNAL ;
    PORT
      LAYER M5 ;
        RECT  54.336 0 54.36 0.192 ;
    END
  END aq_q[415]
  PIN aq_q[416]
    DIRECTION INPUT ;
    USE SIGNAL ;
    PORT
      LAYER M3 ;
        RECT  54.432 0 54.45 0.144 ;
    END
  END aq_q[416]
  PIN aq_q[417]
    DIRECTION INPUT ;
    USE SIGNAL ;
    PORT
      LAYER M5 ;
        RECT  54.48 0 54.504 0.192 ;
    END
  END aq_q[417]
  PIN aq_q[418]
    DIRECTION INPUT ;
    USE SIGNAL ;
    PORT
      LAYER M3 ;
        RECT  54.576 0 54.594 0.144 ;
    END
  END aq_q[418]
  PIN aq_q[419]
    DIRECTION INPUT ;
    USE SIGNAL ;
    PORT
      LAYER M5 ;
        RECT  54.624 0 54.648 0.192 ;
    END
  END aq_q[419]
  PIN aq_q[41]
    DIRECTION INPUT ;
    USE SIGNAL ;
    PORT
      LAYER M5 ;
        RECT  27.408 0 27.432 0.192 ;
    END
  END aq_q[41]
  PIN aq_q[420]
    DIRECTION INPUT ;
    USE SIGNAL ;
    PORT
      LAYER M3 ;
        RECT  54.72 0 54.738 0.144 ;
    END
  END aq_q[420]
  PIN aq_q[421]
    DIRECTION INPUT ;
    USE SIGNAL ;
    PORT
      LAYER M5 ;
        RECT  54.768 0 54.792 0.192 ;
    END
  END aq_q[421]
  PIN aq_q[422]
    DIRECTION INPUT ;
    USE SIGNAL ;
    PORT
      LAYER M3 ;
        RECT  54.864 0 54.882 0.144 ;
    END
  END aq_q[422]
  PIN aq_q[423]
    DIRECTION INPUT ;
    USE SIGNAL ;
    PORT
      LAYER M5 ;
        RECT  54.912 0 54.936 0.192 ;
    END
  END aq_q[423]
  PIN aq_q[424]
    DIRECTION INPUT ;
    USE SIGNAL ;
    PORT
      LAYER M3 ;
        RECT  55.008 0 55.026 0.144 ;
    END
  END aq_q[424]
  PIN aq_q[425]
    DIRECTION INPUT ;
    USE SIGNAL ;
    PORT
      LAYER M5 ;
        RECT  55.056 0 55.08 0.192 ;
    END
  END aq_q[425]
  PIN aq_q[426]
    DIRECTION INPUT ;
    USE SIGNAL ;
    PORT
      LAYER M3 ;
        RECT  55.152 0 55.17 0.144 ;
    END
  END aq_q[426]
  PIN aq_q[427]
    DIRECTION INPUT ;
    USE SIGNAL ;
    PORT
      LAYER M5 ;
        RECT  55.2 0 55.224 0.192 ;
    END
  END aq_q[427]
  PIN aq_q[428]
    DIRECTION INPUT ;
    USE SIGNAL ;
    PORT
      LAYER M3 ;
        RECT  55.296 0 55.314 0.144 ;
    END
  END aq_q[428]
  PIN aq_q[429]
    DIRECTION INPUT ;
    USE SIGNAL ;
    PORT
      LAYER M5 ;
        RECT  55.344 0 55.368 0.192 ;
    END
  END aq_q[429]
  PIN aq_q[42]
    DIRECTION INPUT ;
    USE SIGNAL ;
    PORT
      LAYER M3 ;
        RECT  27.504 0 27.522 0.144 ;
    END
  END aq_q[42]
  PIN aq_q[430]
    DIRECTION INPUT ;
    USE SIGNAL ;
    PORT
      LAYER M3 ;
        RECT  55.44 0 55.458 0.144 ;
    END
  END aq_q[430]
  PIN aq_q[431]
    DIRECTION INPUT ;
    USE SIGNAL ;
    PORT
      LAYER M5 ;
        RECT  55.488 0 55.512 0.192 ;
    END
  END aq_q[431]
  PIN aq_q[432]
    DIRECTION INPUT ;
    USE SIGNAL ;
    PORT
      LAYER M3 ;
        RECT  55.584 0 55.602 0.144 ;
    END
  END aq_q[432]
  PIN aq_q[433]
    DIRECTION INPUT ;
    USE SIGNAL ;
    PORT
      LAYER M5 ;
        RECT  55.632 0 55.656 0.192 ;
    END
  END aq_q[433]
  PIN aq_q[434]
    DIRECTION INPUT ;
    USE SIGNAL ;
    PORT
      LAYER M3 ;
        RECT  55.728 0 55.746 0.144 ;
    END
  END aq_q[434]
  PIN aq_q[435]
    DIRECTION INPUT ;
    USE SIGNAL ;
    PORT
      LAYER M5 ;
        RECT  55.776 0 55.8 0.192 ;
    END
  END aq_q[435]
  PIN aq_q[436]
    DIRECTION INPUT ;
    USE SIGNAL ;
    PORT
      LAYER M3 ;
        RECT  55.872 0 55.89 0.144 ;
    END
  END aq_q[436]
  PIN aq_q[437]
    DIRECTION INPUT ;
    USE SIGNAL ;
    PORT
      LAYER M5 ;
        RECT  55.92 0 55.944 0.192 ;
    END
  END aq_q[437]
  PIN aq_q[438]
    DIRECTION INPUT ;
    USE SIGNAL ;
    PORT
      LAYER M3 ;
        RECT  56.016 0 56.034 0.144 ;
    END
  END aq_q[438]
  PIN aq_q[439]
    DIRECTION INPUT ;
    USE SIGNAL ;
    PORT
      LAYER M5 ;
        RECT  56.064 0 56.088 0.192 ;
    END
  END aq_q[439]
  PIN aq_q[43]
    DIRECTION INPUT ;
    USE SIGNAL ;
    PORT
      LAYER M5 ;
        RECT  27.552 0 27.576 0.192 ;
    END
  END aq_q[43]
  PIN aq_q[440]
    DIRECTION INPUT ;
    USE SIGNAL ;
    PORT
      LAYER M3 ;
        RECT  56.16 0 56.178 0.144 ;
    END
  END aq_q[440]
  PIN aq_q[441]
    DIRECTION INPUT ;
    USE SIGNAL ;
    PORT
      LAYER M5 ;
        RECT  56.208 0 56.232 0.192 ;
    END
  END aq_q[441]
  PIN aq_q[442]
    DIRECTION INPUT ;
    USE SIGNAL ;
    PORT
      LAYER M3 ;
        RECT  56.304 0 56.322 0.144 ;
    END
  END aq_q[442]
  PIN aq_q[443]
    DIRECTION INPUT ;
    USE SIGNAL ;
    PORT
      LAYER M5 ;
        RECT  56.352 0 56.376 0.192 ;
    END
  END aq_q[443]
  PIN aq_q[444]
    DIRECTION INPUT ;
    USE SIGNAL ;
    PORT
      LAYER M3 ;
        RECT  56.448 0 56.466 0.144 ;
    END
  END aq_q[444]
  PIN aq_q[445]
    DIRECTION INPUT ;
    USE SIGNAL ;
    PORT
      LAYER M5 ;
        RECT  56.496 0 56.52 0.192 ;
    END
  END aq_q[445]
  PIN aq_q[446]
    DIRECTION INPUT ;
    USE SIGNAL ;
    PORT
      LAYER M3 ;
        RECT  56.592 0 56.61 0.144 ;
    END
  END aq_q[446]
  PIN aq_q[447]
    DIRECTION INPUT ;
    USE SIGNAL ;
    PORT
      LAYER M5 ;
        RECT  56.64 0 56.664 0.192 ;
    END
  END aq_q[447]
  PIN aq_q[448]
    DIRECTION INPUT ;
    USE SIGNAL ;
    PORT
      LAYER M3 ;
        RECT  56.736 0 56.754 0.144 ;
    END
  END aq_q[448]
  PIN aq_q[449]
    DIRECTION INPUT ;
    USE SIGNAL ;
    PORT
      LAYER M5 ;
        RECT  56.784 0 56.808 0.192 ;
    END
  END aq_q[449]
  PIN aq_q[44]
    DIRECTION INPUT ;
    USE SIGNAL ;
    PORT
      LAYER M3 ;
        RECT  27.648 0 27.666 0.144 ;
    END
  END aq_q[44]
  PIN aq_q[450]
    DIRECTION INPUT ;
    USE SIGNAL ;
    PORT
      LAYER M3 ;
        RECT  56.88 0 56.898 0.144 ;
    END
  END aq_q[450]
  PIN aq_q[451]
    DIRECTION INPUT ;
    USE SIGNAL ;
    PORT
      LAYER M5 ;
        RECT  56.928 0 56.952 0.192 ;
    END
  END aq_q[451]
  PIN aq_q[452]
    DIRECTION INPUT ;
    USE SIGNAL ;
    PORT
      LAYER M3 ;
        RECT  57.024 0 57.042 0.144 ;
    END
  END aq_q[452]
  PIN aq_q[453]
    DIRECTION INPUT ;
    USE SIGNAL ;
    PORT
      LAYER M5 ;
        RECT  57.072 0 57.096 0.192 ;
    END
  END aq_q[453]
  PIN aq_q[454]
    DIRECTION INPUT ;
    USE SIGNAL ;
    PORT
      LAYER M3 ;
        RECT  57.168 0 57.186 0.144 ;
    END
  END aq_q[454]
  PIN aq_q[455]
    DIRECTION INPUT ;
    USE SIGNAL ;
    PORT
      LAYER M5 ;
        RECT  57.216 0 57.24 0.192 ;
    END
  END aq_q[455]
  PIN aq_q[456]
    DIRECTION INPUT ;
    USE SIGNAL ;
    PORT
      LAYER M3 ;
        RECT  57.312 0 57.33 0.144 ;
    END
  END aq_q[456]
  PIN aq_q[457]
    DIRECTION INPUT ;
    USE SIGNAL ;
    PORT
      LAYER M5 ;
        RECT  57.36 0 57.384 0.192 ;
    END
  END aq_q[457]
  PIN aq_q[458]
    DIRECTION INPUT ;
    USE SIGNAL ;
    PORT
      LAYER M3 ;
        RECT  57.456 0 57.474 0.144 ;
    END
  END aq_q[458]
  PIN aq_q[459]
    DIRECTION INPUT ;
    USE SIGNAL ;
    PORT
      LAYER M5 ;
        RECT  57.504 0 57.528 0.192 ;
    END
  END aq_q[459]
  PIN aq_q[45]
    DIRECTION INPUT ;
    USE SIGNAL ;
    PORT
      LAYER M5 ;
        RECT  27.696 0 27.72 0.192 ;
    END
  END aq_q[45]
  PIN aq_q[460]
    DIRECTION INPUT ;
    USE SIGNAL ;
    PORT
      LAYER M3 ;
        RECT  57.6 0 57.618 0.144 ;
    END
  END aq_q[460]
  PIN aq_q[461]
    DIRECTION INPUT ;
    USE SIGNAL ;
    PORT
      LAYER M5 ;
        RECT  57.648 0 57.672 0.192 ;
    END
  END aq_q[461]
  PIN aq_q[462]
    DIRECTION INPUT ;
    USE SIGNAL ;
    PORT
      LAYER M3 ;
        RECT  57.744 0 57.762 0.144 ;
    END
  END aq_q[462]
  PIN aq_q[463]
    DIRECTION INPUT ;
    USE SIGNAL ;
    PORT
      LAYER M5 ;
        RECT  57.792 0 57.816 0.192 ;
    END
  END aq_q[463]
  PIN aq_q[464]
    DIRECTION INPUT ;
    USE SIGNAL ;
    PORT
      LAYER M3 ;
        RECT  57.888 0 57.906 0.144 ;
    END
  END aq_q[464]
  PIN aq_q[465]
    DIRECTION INPUT ;
    USE SIGNAL ;
    PORT
      LAYER M5 ;
        RECT  57.936 0 57.96 0.192 ;
    END
  END aq_q[465]
  PIN aq_q[466]
    DIRECTION INPUT ;
    USE SIGNAL ;
    PORT
      LAYER M3 ;
        RECT  58.032 0 58.05 0.144 ;
    END
  END aq_q[466]
  PIN aq_q[467]
    DIRECTION INPUT ;
    USE SIGNAL ;
    PORT
      LAYER M5 ;
        RECT  58.08 0 58.104 0.192 ;
    END
  END aq_q[467]
  PIN aq_q[468]
    DIRECTION INPUT ;
    USE SIGNAL ;
    PORT
      LAYER M3 ;
        RECT  58.176 0 58.194 0.144 ;
    END
  END aq_q[468]
  PIN aq_q[469]
    DIRECTION INPUT ;
    USE SIGNAL ;
    PORT
      LAYER M5 ;
        RECT  58.224 0 58.248 0.192 ;
    END
  END aq_q[469]
  PIN aq_q[46]
    DIRECTION INPUT ;
    USE SIGNAL ;
    PORT
      LAYER M3 ;
        RECT  27.792 0 27.81 0.144 ;
    END
  END aq_q[46]
  PIN aq_q[470]
    DIRECTION INPUT ;
    USE SIGNAL ;
    PORT
      LAYER M3 ;
        RECT  58.32 0 58.338 0.144 ;
    END
  END aq_q[470]
  PIN aq_q[471]
    DIRECTION INPUT ;
    USE SIGNAL ;
    PORT
      LAYER M5 ;
        RECT  58.368 0 58.392 0.192 ;
    END
  END aq_q[471]
  PIN aq_q[472]
    DIRECTION INPUT ;
    USE SIGNAL ;
    PORT
      LAYER M3 ;
        RECT  58.464 0 58.482 0.144 ;
    END
  END aq_q[472]
  PIN aq_q[473]
    DIRECTION INPUT ;
    USE SIGNAL ;
    PORT
      LAYER M5 ;
        RECT  58.512 0 58.536 0.192 ;
    END
  END aq_q[473]
  PIN aq_q[474]
    DIRECTION INPUT ;
    USE SIGNAL ;
    PORT
      LAYER M3 ;
        RECT  58.608 0 58.626 0.144 ;
    END
  END aq_q[474]
  PIN aq_q[475]
    DIRECTION INPUT ;
    USE SIGNAL ;
    PORT
      LAYER M5 ;
        RECT  58.656 0 58.68 0.192 ;
    END
  END aq_q[475]
  PIN aq_q[476]
    DIRECTION INPUT ;
    USE SIGNAL ;
    PORT
      LAYER M3 ;
        RECT  58.752 0 58.77 0.144 ;
    END
  END aq_q[476]
  PIN aq_q[477]
    DIRECTION INPUT ;
    USE SIGNAL ;
    PORT
      LAYER M5 ;
        RECT  58.8 0 58.824 0.192 ;
    END
  END aq_q[477]
  PIN aq_q[478]
    DIRECTION INPUT ;
    USE SIGNAL ;
    PORT
      LAYER M3 ;
        RECT  58.896 0 58.914 0.144 ;
    END
  END aq_q[478]
  PIN aq_q[479]
    DIRECTION INPUT ;
    USE SIGNAL ;
    PORT
      LAYER M5 ;
        RECT  58.944 0 58.968 0.192 ;
    END
  END aq_q[479]
  PIN aq_q[47]
    DIRECTION INPUT ;
    USE SIGNAL ;
    PORT
      LAYER M5 ;
        RECT  27.84 0 27.864 0.192 ;
    END
  END aq_q[47]
  PIN aq_q[480]
    DIRECTION INPUT ;
    USE SIGNAL ;
    PORT
      LAYER M3 ;
        RECT  59.04 0 59.058 0.144 ;
    END
  END aq_q[480]
  PIN aq_q[481]
    DIRECTION INPUT ;
    USE SIGNAL ;
    PORT
      LAYER M5 ;
        RECT  59.088 0 59.112 0.192 ;
    END
  END aq_q[481]
  PIN aq_q[482]
    DIRECTION INPUT ;
    USE SIGNAL ;
    PORT
      LAYER M3 ;
        RECT  59.184 0 59.202 0.144 ;
    END
  END aq_q[482]
  PIN aq_q[483]
    DIRECTION INPUT ;
    USE SIGNAL ;
    PORT
      LAYER M5 ;
        RECT  59.232 0 59.256 0.192 ;
    END
  END aq_q[483]
  PIN aq_q[484]
    DIRECTION INPUT ;
    USE SIGNAL ;
    PORT
      LAYER M3 ;
        RECT  59.328 0 59.346 0.144 ;
    END
  END aq_q[484]
  PIN aq_q[485]
    DIRECTION INPUT ;
    USE SIGNAL ;
    PORT
      LAYER M5 ;
        RECT  59.376 0 59.4 0.192 ;
    END
  END aq_q[485]
  PIN aq_q[486]
    DIRECTION INPUT ;
    USE SIGNAL ;
    PORT
      LAYER M3 ;
        RECT  59.472 0 59.49 0.144 ;
    END
  END aq_q[486]
  PIN aq_q[487]
    DIRECTION INPUT ;
    USE SIGNAL ;
    PORT
      LAYER M5 ;
        RECT  59.52 0 59.544 0.192 ;
    END
  END aq_q[487]
  PIN aq_q[488]
    DIRECTION INPUT ;
    USE SIGNAL ;
    PORT
      LAYER M3 ;
        RECT  59.616 0 59.634 0.144 ;
    END
  END aq_q[488]
  PIN aq_q[489]
    DIRECTION INPUT ;
    USE SIGNAL ;
    PORT
      LAYER M5 ;
        RECT  59.664 0 59.688 0.192 ;
    END
  END aq_q[489]
  PIN aq_q[48]
    DIRECTION INPUT ;
    USE SIGNAL ;
    PORT
      LAYER M3 ;
        RECT  27.936 0 27.954 0.144 ;
    END
  END aq_q[48]
  PIN aq_q[490]
    DIRECTION INPUT ;
    USE SIGNAL ;
    PORT
      LAYER M3 ;
        RECT  59.76 0 59.778 0.144 ;
    END
  END aq_q[490]
  PIN aq_q[491]
    DIRECTION INPUT ;
    USE SIGNAL ;
    PORT
      LAYER M5 ;
        RECT  59.808 0 59.832 0.192 ;
    END
  END aq_q[491]
  PIN aq_q[492]
    DIRECTION INPUT ;
    USE SIGNAL ;
    PORT
      LAYER M3 ;
        RECT  59.904 0 59.922 0.144 ;
    END
  END aq_q[492]
  PIN aq_q[493]
    DIRECTION INPUT ;
    USE SIGNAL ;
    PORT
      LAYER M5 ;
        RECT  59.952 0 59.976 0.192 ;
    END
  END aq_q[493]
  PIN aq_q[494]
    DIRECTION INPUT ;
    USE SIGNAL ;
    PORT
      LAYER M3 ;
        RECT  60.048 0 60.066 0.144 ;
    END
  END aq_q[494]
  PIN aq_q[495]
    DIRECTION INPUT ;
    USE SIGNAL ;
    PORT
      LAYER M5 ;
        RECT  60.096 0 60.12 0.192 ;
    END
  END aq_q[495]
  PIN aq_q[496]
    DIRECTION INPUT ;
    USE SIGNAL ;
    PORT
      LAYER M3 ;
        RECT  60.192 0 60.21 0.144 ;
    END
  END aq_q[496]
  PIN aq_q[497]
    DIRECTION INPUT ;
    USE SIGNAL ;
    PORT
      LAYER M5 ;
        RECT  60.24 0 60.264 0.192 ;
    END
  END aq_q[497]
  PIN aq_q[498]
    DIRECTION INPUT ;
    USE SIGNAL ;
    PORT
      LAYER M3 ;
        RECT  60.336 0 60.354 0.144 ;
    END
  END aq_q[498]
  PIN aq_q[499]
    DIRECTION INPUT ;
    USE SIGNAL ;
    PORT
      LAYER M5 ;
        RECT  60.384 0 60.408 0.192 ;
    END
  END aq_q[499]
  PIN aq_q[49]
    DIRECTION INPUT ;
    USE SIGNAL ;
    PORT
      LAYER M5 ;
        RECT  27.984 0 28.008 0.192 ;
    END
  END aq_q[49]
  PIN aq_q[4]
    DIRECTION INPUT ;
    USE SIGNAL ;
    PORT
      LAYER M3 ;
        RECT  24.768 0 24.786 0.144 ;
    END
  END aq_q[4]
  PIN aq_q[500]
    DIRECTION INPUT ;
    USE SIGNAL ;
    PORT
      LAYER M3 ;
        RECT  60.48 0 60.498 0.144 ;
    END
  END aq_q[500]
  PIN aq_q[501]
    DIRECTION INPUT ;
    USE SIGNAL ;
    PORT
      LAYER M5 ;
        RECT  60.528 0 60.552 0.192 ;
    END
  END aq_q[501]
  PIN aq_q[502]
    DIRECTION INPUT ;
    USE SIGNAL ;
    PORT
      LAYER M3 ;
        RECT  60.624 0 60.642 0.144 ;
    END
  END aq_q[502]
  PIN aq_q[503]
    DIRECTION INPUT ;
    USE SIGNAL ;
    PORT
      LAYER M5 ;
        RECT  60.672 0 60.696 0.192 ;
    END
  END aq_q[503]
  PIN aq_q[504]
    DIRECTION INPUT ;
    USE SIGNAL ;
    PORT
      LAYER M3 ;
        RECT  60.768 0 60.786 0.144 ;
    END
  END aq_q[504]
  PIN aq_q[505]
    DIRECTION INPUT ;
    USE SIGNAL ;
    PORT
      LAYER M5 ;
        RECT  60.816 0 60.84 0.192 ;
    END
  END aq_q[505]
  PIN aq_q[506]
    DIRECTION INPUT ;
    USE SIGNAL ;
    PORT
      LAYER M3 ;
        RECT  60.912 0 60.93 0.144 ;
    END
  END aq_q[506]
  PIN aq_q[507]
    DIRECTION INPUT ;
    USE SIGNAL ;
    PORT
      LAYER M5 ;
        RECT  60.96 0 60.984 0.192 ;
    END
  END aq_q[507]
  PIN aq_q[508]
    DIRECTION INPUT ;
    USE SIGNAL ;
    PORT
      LAYER M3 ;
        RECT  61.056 0 61.074 0.144 ;
    END
  END aq_q[508]
  PIN aq_q[509]
    DIRECTION INPUT ;
    USE SIGNAL ;
    PORT
      LAYER M5 ;
        RECT  61.104 0 61.128 0.192 ;
    END
  END aq_q[509]
  PIN aq_q[50]
    DIRECTION INPUT ;
    USE SIGNAL ;
    PORT
      LAYER M3 ;
        RECT  28.08 0 28.098 0.144 ;
    END
  END aq_q[50]
  PIN aq_q[510]
    DIRECTION INPUT ;
    USE SIGNAL ;
    PORT
      LAYER M3 ;
        RECT  61.2 0 61.218 0.144 ;
    END
  END aq_q[510]
  PIN aq_q[511]
    DIRECTION INPUT ;
    USE SIGNAL ;
    PORT
      LAYER M5 ;
        RECT  61.248 0 61.272 0.192 ;
    END
  END aq_q[511]
  PIN aq_q[51]
    DIRECTION INPUT ;
    USE SIGNAL ;
    PORT
      LAYER M5 ;
        RECT  28.128 0 28.152 0.192 ;
    END
  END aq_q[51]
  PIN aq_q[52]
    DIRECTION INPUT ;
    USE SIGNAL ;
    PORT
      LAYER M3 ;
        RECT  28.224 0 28.242 0.144 ;
    END
  END aq_q[52]
  PIN aq_q[53]
    DIRECTION INPUT ;
    USE SIGNAL ;
    PORT
      LAYER M5 ;
        RECT  28.272 0 28.296 0.192 ;
    END
  END aq_q[53]
  PIN aq_q[54]
    DIRECTION INPUT ;
    USE SIGNAL ;
    PORT
      LAYER M3 ;
        RECT  28.368 0 28.386 0.144 ;
    END
  END aq_q[54]
  PIN aq_q[55]
    DIRECTION INPUT ;
    USE SIGNAL ;
    PORT
      LAYER M5 ;
        RECT  28.416 0 28.44 0.192 ;
    END
  END aq_q[55]
  PIN aq_q[56]
    DIRECTION INPUT ;
    USE SIGNAL ;
    PORT
      LAYER M3 ;
        RECT  28.512 0 28.53 0.144 ;
    END
  END aq_q[56]
  PIN aq_q[57]
    DIRECTION INPUT ;
    USE SIGNAL ;
    PORT
      LAYER M5 ;
        RECT  28.56 0 28.584 0.192 ;
    END
  END aq_q[57]
  PIN aq_q[58]
    DIRECTION INPUT ;
    USE SIGNAL ;
    PORT
      LAYER M3 ;
        RECT  28.656 0 28.674 0.144 ;
    END
  END aq_q[58]
  PIN aq_q[59]
    DIRECTION INPUT ;
    USE SIGNAL ;
    PORT
      LAYER M5 ;
        RECT  28.704 0 28.728 0.192 ;
    END
  END aq_q[59]
  PIN aq_q[5]
    DIRECTION INPUT ;
    USE SIGNAL ;
    PORT
      LAYER M5 ;
        RECT  24.816 0 24.84 0.192 ;
    END
  END aq_q[5]
  PIN aq_q[60]
    DIRECTION INPUT ;
    USE SIGNAL ;
    PORT
      LAYER M3 ;
        RECT  28.8 0 28.818 0.144 ;
    END
  END aq_q[60]
  PIN aq_q[61]
    DIRECTION INPUT ;
    USE SIGNAL ;
    PORT
      LAYER M5 ;
        RECT  28.848 0 28.872 0.192 ;
    END
  END aq_q[61]
  PIN aq_q[62]
    DIRECTION INPUT ;
    USE SIGNAL ;
    PORT
      LAYER M3 ;
        RECT  28.944 0 28.962 0.144 ;
    END
  END aq_q[62]
  PIN aq_q[63]
    DIRECTION INPUT ;
    USE SIGNAL ;
    PORT
      LAYER M5 ;
        RECT  28.992 0 29.016 0.192 ;
    END
  END aq_q[63]
  PIN aq_q[64]
    DIRECTION INPUT ;
    USE SIGNAL ;
    PORT
      LAYER M3 ;
        RECT  29.088 0 29.106 0.144 ;
    END
  END aq_q[64]
  PIN aq_q[65]
    DIRECTION INPUT ;
    USE SIGNAL ;
    PORT
      LAYER M5 ;
        RECT  29.136 0 29.16 0.192 ;
    END
  END aq_q[65]
  PIN aq_q[66]
    DIRECTION INPUT ;
    USE SIGNAL ;
    PORT
      LAYER M3 ;
        RECT  29.232 0 29.25 0.144 ;
    END
  END aq_q[66]
  PIN aq_q[67]
    DIRECTION INPUT ;
    USE SIGNAL ;
    PORT
      LAYER M5 ;
        RECT  29.28 0 29.304 0.192 ;
    END
  END aq_q[67]
  PIN aq_q[68]
    DIRECTION INPUT ;
    USE SIGNAL ;
    PORT
      LAYER M3 ;
        RECT  29.376 0 29.394 0.144 ;
    END
  END aq_q[68]
  PIN aq_q[69]
    DIRECTION INPUT ;
    USE SIGNAL ;
    PORT
      LAYER M5 ;
        RECT  29.424 0 29.448 0.192 ;
    END
  END aq_q[69]
  PIN aq_q[6]
    DIRECTION INPUT ;
    USE SIGNAL ;
    PORT
      LAYER M3 ;
        RECT  24.912 0 24.93 0.144 ;
    END
  END aq_q[6]
  PIN aq_q[70]
    DIRECTION INPUT ;
    USE SIGNAL ;
    PORT
      LAYER M3 ;
        RECT  29.52 0 29.538 0.144 ;
    END
  END aq_q[70]
  PIN aq_q[71]
    DIRECTION INPUT ;
    USE SIGNAL ;
    PORT
      LAYER M5 ;
        RECT  29.568 0 29.592 0.192 ;
    END
  END aq_q[71]
  PIN aq_q[72]
    DIRECTION INPUT ;
    USE SIGNAL ;
    PORT
      LAYER M3 ;
        RECT  29.664 0 29.682 0.144 ;
    END
  END aq_q[72]
  PIN aq_q[73]
    DIRECTION INPUT ;
    USE SIGNAL ;
    PORT
      LAYER M5 ;
        RECT  29.712 0 29.736 0.192 ;
    END
  END aq_q[73]
  PIN aq_q[74]
    DIRECTION INPUT ;
    USE SIGNAL ;
    PORT
      LAYER M3 ;
        RECT  29.808 0 29.826 0.144 ;
    END
  END aq_q[74]
  PIN aq_q[75]
    DIRECTION INPUT ;
    USE SIGNAL ;
    PORT
      LAYER M5 ;
        RECT  29.856 0 29.88 0.192 ;
    END
  END aq_q[75]
  PIN aq_q[76]
    DIRECTION INPUT ;
    USE SIGNAL ;
    PORT
      LAYER M3 ;
        RECT  29.952 0 29.97 0.144 ;
    END
  END aq_q[76]
  PIN aq_q[77]
    DIRECTION INPUT ;
    USE SIGNAL ;
    PORT
      LAYER M5 ;
        RECT  30 0 30.024 0.192 ;
    END
  END aq_q[77]
  PIN aq_q[78]
    DIRECTION INPUT ;
    USE SIGNAL ;
    PORT
      LAYER M3 ;
        RECT  30.096 0 30.114 0.144 ;
    END
  END aq_q[78]
  PIN aq_q[79]
    DIRECTION INPUT ;
    USE SIGNAL ;
    PORT
      LAYER M5 ;
        RECT  30.144 0 30.168 0.192 ;
    END
  END aq_q[79]
  PIN aq_q[7]
    DIRECTION INPUT ;
    USE SIGNAL ;
    PORT
      LAYER M5 ;
        RECT  24.96 0 24.984 0.192 ;
    END
  END aq_q[7]
  PIN aq_q[80]
    DIRECTION INPUT ;
    USE SIGNAL ;
    PORT
      LAYER M3 ;
        RECT  30.24 0 30.258 0.144 ;
    END
  END aq_q[80]
  PIN aq_q[81]
    DIRECTION INPUT ;
    USE SIGNAL ;
    PORT
      LAYER M5 ;
        RECT  30.288 0 30.312 0.192 ;
    END
  END aq_q[81]
  PIN aq_q[82]
    DIRECTION INPUT ;
    USE SIGNAL ;
    PORT
      LAYER M3 ;
        RECT  30.384 0 30.402 0.144 ;
    END
  END aq_q[82]
  PIN aq_q[83]
    DIRECTION INPUT ;
    USE SIGNAL ;
    PORT
      LAYER M5 ;
        RECT  30.432 0 30.456 0.192 ;
    END
  END aq_q[83]
  PIN aq_q[84]
    DIRECTION INPUT ;
    USE SIGNAL ;
    PORT
      LAYER M3 ;
        RECT  30.528 0 30.546 0.144 ;
    END
  END aq_q[84]
  PIN aq_q[85]
    DIRECTION INPUT ;
    USE SIGNAL ;
    PORT
      LAYER M5 ;
        RECT  30.576 0 30.6 0.192 ;
    END
  END aq_q[85]
  PIN aq_q[86]
    DIRECTION INPUT ;
    USE SIGNAL ;
    PORT
      LAYER M3 ;
        RECT  30.672 0 30.69 0.144 ;
    END
  END aq_q[86]
  PIN aq_q[87]
    DIRECTION INPUT ;
    USE SIGNAL ;
    PORT
      LAYER M5 ;
        RECT  30.72 0 30.744 0.192 ;
    END
  END aq_q[87]
  PIN aq_q[88]
    DIRECTION INPUT ;
    USE SIGNAL ;
    PORT
      LAYER M3 ;
        RECT  30.816 0 30.834 0.144 ;
    END
  END aq_q[88]
  PIN aq_q[89]
    DIRECTION INPUT ;
    USE SIGNAL ;
    PORT
      LAYER M5 ;
        RECT  30.864 0 30.888 0.192 ;
    END
  END aq_q[89]
  PIN aq_q[8]
    DIRECTION INPUT ;
    USE SIGNAL ;
    PORT
      LAYER M3 ;
        RECT  25.056 0 25.074 0.144 ;
    END
  END aq_q[8]
  PIN aq_q[90]
    DIRECTION INPUT ;
    USE SIGNAL ;
    PORT
      LAYER M3 ;
        RECT  30.96 0 30.978 0.144 ;
    END
  END aq_q[90]
  PIN aq_q[91]
    DIRECTION INPUT ;
    USE SIGNAL ;
    PORT
      LAYER M5 ;
        RECT  31.008 0 31.032 0.192 ;
    END
  END aq_q[91]
  PIN aq_q[92]
    DIRECTION INPUT ;
    USE SIGNAL ;
    PORT
      LAYER M3 ;
        RECT  31.104 0 31.122 0.144 ;
    END
  END aq_q[92]
  PIN aq_q[93]
    DIRECTION INPUT ;
    USE SIGNAL ;
    PORT
      LAYER M5 ;
        RECT  31.152 0 31.176 0.192 ;
    END
  END aq_q[93]
  PIN aq_q[94]
    DIRECTION INPUT ;
    USE SIGNAL ;
    PORT
      LAYER M3 ;
        RECT  31.248 0 31.266 0.144 ;
    END
  END aq_q[94]
  PIN aq_q[95]
    DIRECTION INPUT ;
    USE SIGNAL ;
    PORT
      LAYER M5 ;
        RECT  31.296 0 31.32 0.192 ;
    END
  END aq_q[95]
  PIN aq_q[96]
    DIRECTION INPUT ;
    USE SIGNAL ;
    PORT
      LAYER M3 ;
        RECT  31.392 0 31.41 0.144 ;
    END
  END aq_q[96]
  PIN aq_q[97]
    DIRECTION INPUT ;
    USE SIGNAL ;
    PORT
      LAYER M5 ;
        RECT  31.44 0 31.464 0.192 ;
    END
  END aq_q[97]
  PIN aq_q[98]
    DIRECTION INPUT ;
    USE SIGNAL ;
    PORT
      LAYER M3 ;
        RECT  31.536 0 31.554 0.144 ;
    END
  END aq_q[98]
  PIN aq_q[99]
    DIRECTION INPUT ;
    USE SIGNAL ;
    PORT
      LAYER M5 ;
        RECT  31.584 0 31.608 0.192 ;
    END
  END aq_q[99]
  PIN aq_q[9]
    DIRECTION INPUT ;
    USE SIGNAL ;
    PORT
      LAYER M5 ;
        RECT  25.104 0 25.128 0.192 ;
    END
  END aq_q[9]
  PIN clk
    DIRECTION INPUT ;
    USE SIGNAL ;
    PORT
      LAYER M4 ;
        RECT  0 52.032 0.192 52.056 ;
    END
    PORT
      LAYER M4 ;
        RECT  0.156 52.032 0.817 52.056 ;
    END
  END clk
  PIN erd[0]
    DIRECTION OUTPUT ;
    USE SIGNAL ;
    PORT
      LAYER M3 ;
        RECT  47.52 86.256 47.538 86.4 ;
    END
  END erd[0]
  PIN erd[1]
    DIRECTION OUTPUT ;
    USE SIGNAL ;
    PORT
      LAYER M3 ;
        RECT  47.664 86.256 47.682 86.4 ;
    END
  END erd[1]
  PIN erd[2]
    DIRECTION OUTPUT ;
    USE SIGNAL ;
    PORT
      LAYER M3 ;
        RECT  47.808 86.256 47.826 86.4 ;
    END
  END erd[2]
  PIN erd[3]
    DIRECTION OUTPUT ;
    USE SIGNAL ;
    PORT
      LAYER M3 ;
        RECT  47.952 86.256 47.97 86.4 ;
    END
  END erd[3]
  PIN erd[4]
    DIRECTION OUTPUT ;
    USE SIGNAL ;
    PORT
      LAYER M3 ;
        RECT  48.096 86.256 48.114 86.4 ;
    END
  END erd[4]
  PIN erd[5]
    DIRECTION OUTPUT ;
    USE SIGNAL ;
    PORT
      LAYER M3 ;
        RECT  48.24 86.256 48.258 86.4 ;
    END
  END erd[5]
  PIN erd[6]
    DIRECTION OUTPUT ;
    USE SIGNAL ;
    PORT
      LAYER M3 ;
        RECT  48.384 86.256 48.402 86.4 ;
    END
  END erd[6]
  PIN erd[7]
    DIRECTION OUTPUT ;
    USE SIGNAL ;
    PORT
      LAYER M3 ;
        RECT  48.528 86.256 48.546 86.4 ;
    END
  END erd[7]
  PIN erd[8]
    DIRECTION OUTPUT ;
    USE SIGNAL ;
    PORT
      LAYER M3 ;
        RECT  48.672 86.256 48.69 86.4 ;
    END
  END erd[8]
  PIN erd[9]
    DIRECTION OUTPUT ;
    USE SIGNAL ;
    PORT
      LAYER M3 ;
        RECT  48.816 86.256 48.834 86.4 ;
    END
  END erd[9]
  PIN fault
    DIRECTION OUTPUT ;
    USE SIGNAL ;
    PORT
      LAYER M4 ;
        RECT  142.368 52.032 142.56 52.056 ;
    END
    PORT
      LAYER M4 ;
        RECT  141.325 52.032 142.38 52.056 ;
    END
  END fault
  PIN i0[0]
    DIRECTION INPUT ;
    USE SIGNAL ;
    PORT
      LAYER M4 ;
        RECT  0 41.616 0.192 41.64 ;
    END
  END i0[0]
  PIN i0[10]
    DIRECTION INPUT ;
    USE SIGNAL ;
    PORT
      LAYER M4 ;
        RECT  0 43.056 0.192 43.08 ;
    END
  END i0[10]
  PIN i0[11]
    DIRECTION INPUT ;
    USE SIGNAL ;
    PORT
      LAYER M4 ;
        RECT  0 43.2 0.192 43.224 ;
    END
  END i0[11]
  PIN i0[12]
    DIRECTION INPUT ;
    USE SIGNAL ;
    PORT
      LAYER M4 ;
        RECT  0 43.344 0.192 43.368 ;
    END
  END i0[12]
  PIN i0[13]
    DIRECTION INPUT ;
    USE SIGNAL ;
    PORT
      LAYER M4 ;
        RECT  0 43.488 0.192 43.512 ;
    END
  END i0[13]
  PIN i0[14]
    DIRECTION INPUT ;
    USE SIGNAL ;
    PORT
      LAYER M4 ;
        RECT  0 43.632 0.192 43.656 ;
    END
  END i0[14]
  PIN i0[15]
    DIRECTION INPUT ;
    USE SIGNAL ;
    PORT
      LAYER M4 ;
        RECT  0 43.776 0.192 43.8 ;
    END
  END i0[15]
  PIN i0[1]
    DIRECTION INPUT ;
    USE SIGNAL ;
    PORT
      LAYER M4 ;
        RECT  0 41.76 0.192 41.784 ;
    END
  END i0[1]
  PIN i0[2]
    DIRECTION INPUT ;
    USE SIGNAL ;
    PORT
      LAYER M4 ;
        RECT  0 41.904 0.192 41.928 ;
    END
  END i0[2]
  PIN i0[3]
    DIRECTION INPUT ;
    USE SIGNAL ;
    PORT
      LAYER M4 ;
        RECT  0 42.048 0.192 42.072 ;
    END
  END i0[3]
  PIN i0[4]
    DIRECTION INPUT ;
    USE SIGNAL ;
    PORT
      LAYER M4 ;
        RECT  0 42.192 0.192 42.216 ;
    END
  END i0[4]
  PIN i0[5]
    DIRECTION INPUT ;
    USE SIGNAL ;
    PORT
      LAYER M4 ;
        RECT  0 42.336 0.192 42.36 ;
    END
  END i0[5]
  PIN i0[6]
    DIRECTION INPUT ;
    USE SIGNAL ;
    PORT
      LAYER M4 ;
        RECT  0 42.48 0.192 42.504 ;
    END
  END i0[6]
  PIN i0[7]
    DIRECTION INPUT ;
    USE SIGNAL ;
    PORT
      LAYER M4 ;
        RECT  0 42.624 0.192 42.648 ;
    END
  END i0[7]
  PIN i0[8]
    DIRECTION INPUT ;
    USE SIGNAL ;
    PORT
      LAYER M4 ;
        RECT  0 42.768 0.192 42.792 ;
    END
  END i0[8]
  PIN i0[9]
    DIRECTION INPUT ;
    USE SIGNAL ;
    PORT
      LAYER M4 ;
        RECT  0 42.912 0.192 42.936 ;
    END
  END i0[9]
  PIN i1[0]
    DIRECTION INPUT ;
    USE SIGNAL ;
    PORT
      LAYER M4 ;
        RECT  0 43.92 0.192 43.944 ;
    END
  END i1[0]
  PIN i1[10]
    DIRECTION INPUT ;
    USE SIGNAL ;
    PORT
      LAYER M4 ;
        RECT  0 45.36 0.192 45.384 ;
    END
  END i1[10]
  PIN i1[11]
    DIRECTION INPUT ;
    USE SIGNAL ;
    PORT
      LAYER M4 ;
        RECT  0 45.504 0.192 45.528 ;
    END
  END i1[11]
  PIN i1[12]
    DIRECTION INPUT ;
    USE SIGNAL ;
    PORT
      LAYER M4 ;
        RECT  0 45.648 0.192 45.672 ;
    END
  END i1[12]
  PIN i1[13]
    DIRECTION INPUT ;
    USE SIGNAL ;
    PORT
      LAYER M4 ;
        RECT  0 45.792 0.192 45.816 ;
    END
  END i1[13]
  PIN i1[14]
    DIRECTION INPUT ;
    USE SIGNAL ;
    PORT
      LAYER M4 ;
        RECT  0 45.936 0.192 45.96 ;
    END
  END i1[14]
  PIN i1[15]
    DIRECTION INPUT ;
    USE SIGNAL ;
    PORT
      LAYER M4 ;
        RECT  0 46.08 0.192 46.104 ;
    END
  END i1[15]
  PIN i1[1]
    DIRECTION INPUT ;
    USE SIGNAL ;
    PORT
      LAYER M4 ;
        RECT  0 44.064 0.192 44.088 ;
    END
  END i1[1]
  PIN i1[2]
    DIRECTION INPUT ;
    USE SIGNAL ;
    PORT
      LAYER M4 ;
        RECT  0 44.208 0.192 44.232 ;
    END
  END i1[2]
  PIN i1[3]
    DIRECTION INPUT ;
    USE SIGNAL ;
    PORT
      LAYER M4 ;
        RECT  0 44.352 0.192 44.376 ;
    END
  END i1[3]
  PIN i1[4]
    DIRECTION INPUT ;
    USE SIGNAL ;
    PORT
      LAYER M4 ;
        RECT  0 44.496 0.192 44.52 ;
    END
  END i1[4]
  PIN i1[5]
    DIRECTION INPUT ;
    USE SIGNAL ;
    PORT
      LAYER M4 ;
        RECT  0 44.64 0.192 44.664 ;
    END
  END i1[5]
  PIN i1[6]
    DIRECTION INPUT ;
    USE SIGNAL ;
    PORT
      LAYER M4 ;
        RECT  0 44.784 0.192 44.808 ;
    END
  END i1[6]
  PIN i1[7]
    DIRECTION INPUT ;
    USE SIGNAL ;
    PORT
      LAYER M4 ;
        RECT  0 44.928 0.192 44.952 ;
    END
  END i1[7]
  PIN i1[8]
    DIRECTION INPUT ;
    USE SIGNAL ;
    PORT
      LAYER M4 ;
        RECT  0 45.072 0.192 45.096 ;
    END
  END i1[8]
  PIN i1[9]
    DIRECTION INPUT ;
    USE SIGNAL ;
    PORT
      LAYER M4 ;
        RECT  0 45.216 0.192 45.24 ;
    END
  END i1[9]
  PIN ph0[0]
    DIRECTION INPUT ;
    USE SIGNAL ;
    PORT
      LAYER M4 ;
        RECT  0 38.448 0.192 38.472 ;
    END
  END ph0[0]
  PIN ph0[1]
    DIRECTION INPUT ;
    USE SIGNAL ;
    PORT
      LAYER M4 ;
        RECT  0 38.304 0.192 38.328 ;
    END
  END ph0[1]
  PIN ph0[2]
    DIRECTION INPUT ;
    USE SIGNAL ;
    PORT
      LAYER M4 ;
        RECT  0 38.16 0.192 38.184 ;
    END
  END ph0[2]
  PIN ph0[3]
    DIRECTION INPUT ;
    USE SIGNAL ;
    PORT
      LAYER M4 ;
        RECT  0 38.016 0.192 38.04 ;
    END
  END ph0[3]
  PIN ph0[4]
    DIRECTION INPUT ;
    USE SIGNAL ;
    PORT
      LAYER M4 ;
        RECT  0 37.872 0.192 37.896 ;
    END
  END ph0[4]
  PIN ph0[5]
    DIRECTION INPUT ;
    USE SIGNAL ;
    PORT
      LAYER M4 ;
        RECT  0 37.728 0.192 37.752 ;
    END
  END ph0[5]
  PIN ph1[0]
    DIRECTION INPUT ;
    USE SIGNAL ;
    PORT
      LAYER M4 ;
        RECT  0 37.584 0.192 37.608 ;
    END
  END ph1[0]
  PIN ph1[1]
    DIRECTION INPUT ;
    USE SIGNAL ;
    PORT
      LAYER M4 ;
        RECT  0 37.44 0.192 37.464 ;
    END
  END ph1[1]
  PIN ph1[2]
    DIRECTION INPUT ;
    USE SIGNAL ;
    PORT
      LAYER M4 ;
        RECT  0 37.296 0.192 37.32 ;
    END
  END ph1[2]
  PIN ph1[3]
    DIRECTION INPUT ;
    USE SIGNAL ;
    PORT
      LAYER M4 ;
        RECT  0 37.152 0.192 37.176 ;
    END
  END ph1[3]
  PIN ph1[4]
    DIRECTION INPUT ;
    USE SIGNAL ;
    PORT
      LAYER M4 ;
        RECT  0 37.008 0.192 37.032 ;
    END
  END ph1[4]
  PIN ph1[5]
    DIRECTION INPUT ;
    USE SIGNAL ;
    PORT
      LAYER M4 ;
        RECT  0 36.864 0.192 36.888 ;
    END
  END ph1[5]
  PIN pl0[0]
    DIRECTION INPUT ;
    USE SIGNAL ;
    PORT
      LAYER M4 ;
        RECT  0 36.72 0.192 36.744 ;
    END
  END pl0[0]
  PIN pl0[10]
    DIRECTION INPUT ;
    USE SIGNAL ;
    PORT
      LAYER M4 ;
        RECT  0 35.28 0.192 35.304 ;
    END
  END pl0[10]
  PIN pl0[11]
    DIRECTION INPUT ;
    USE SIGNAL ;
    PORT
      LAYER M4 ;
        RECT  0 35.136 0.192 35.16 ;
    END
  END pl0[11]
  PIN pl0[12]
    DIRECTION INPUT ;
    USE SIGNAL ;
    PORT
      LAYER M4 ;
        RECT  0 34.992 0.192 35.016 ;
    END
  END pl0[12]
  PIN pl0[13]
    DIRECTION INPUT ;
    USE SIGNAL ;
    PORT
      LAYER M4 ;
        RECT  0 34.848 0.192 34.872 ;
    END
  END pl0[13]
  PIN pl0[14]
    DIRECTION INPUT ;
    USE SIGNAL ;
    PORT
      LAYER M4 ;
        RECT  0 34.704 0.192 34.728 ;
    END
  END pl0[14]
  PIN pl0[15]
    DIRECTION INPUT ;
    USE SIGNAL ;
    PORT
      LAYER M4 ;
        RECT  0 34.56 0.192 34.584 ;
    END
  END pl0[15]
  PIN pl0[1]
    DIRECTION INPUT ;
    USE SIGNAL ;
    PORT
      LAYER M4 ;
        RECT  0 36.576 0.192 36.6 ;
    END
  END pl0[1]
  PIN pl0[2]
    DIRECTION INPUT ;
    USE SIGNAL ;
    PORT
      LAYER M4 ;
        RECT  0 36.432 0.192 36.456 ;
    END
  END pl0[2]
  PIN pl0[3]
    DIRECTION INPUT ;
    USE SIGNAL ;
    PORT
      LAYER M4 ;
        RECT  0 36.288 0.192 36.312 ;
    END
  END pl0[3]
  PIN pl0[4]
    DIRECTION INPUT ;
    USE SIGNAL ;
    PORT
      LAYER M4 ;
        RECT  0 36.144 0.192 36.168 ;
    END
  END pl0[4]
  PIN pl0[5]
    DIRECTION INPUT ;
    USE SIGNAL ;
    PORT
      LAYER M4 ;
        RECT  0 36 0.192 36.024 ;
    END
  END pl0[5]
  PIN pl0[6]
    DIRECTION INPUT ;
    USE SIGNAL ;
    PORT
      LAYER M4 ;
        RECT  0 35.856 0.192 35.88 ;
    END
  END pl0[6]
  PIN pl0[7]
    DIRECTION INPUT ;
    USE SIGNAL ;
    PORT
      LAYER M4 ;
        RECT  0 35.712 0.192 35.736 ;
    END
  END pl0[7]
  PIN pl0[8]
    DIRECTION INPUT ;
    USE SIGNAL ;
    PORT
      LAYER M4 ;
        RECT  0 35.568 0.192 35.592 ;
    END
  END pl0[8]
  PIN pl0[9]
    DIRECTION INPUT ;
    USE SIGNAL ;
    PORT
      LAYER M4 ;
        RECT  0 35.424 0.192 35.448 ;
    END
  END pl0[9]
  PIN pl1[0]
    DIRECTION INPUT ;
    USE SIGNAL ;
    PORT
      LAYER M4 ;
        RECT  0 34.416 0.192 34.44 ;
    END
  END pl1[0]
  PIN pl1[10]
    DIRECTION INPUT ;
    USE SIGNAL ;
    PORT
      LAYER M4 ;
        RECT  0 32.976 0.192 33 ;
    END
  END pl1[10]
  PIN pl1[11]
    DIRECTION INPUT ;
    USE SIGNAL ;
    PORT
      LAYER M4 ;
        RECT  0 32.832 0.192 32.856 ;
    END
  END pl1[11]
  PIN pl1[12]
    DIRECTION INPUT ;
    USE SIGNAL ;
    PORT
      LAYER M4 ;
        RECT  0 32.688 0.192 32.712 ;
    END
  END pl1[12]
  PIN pl1[13]
    DIRECTION INPUT ;
    USE SIGNAL ;
    PORT
      LAYER M4 ;
        RECT  0 32.544 0.192 32.568 ;
    END
  END pl1[13]
  PIN pl1[14]
    DIRECTION INPUT ;
    USE SIGNAL ;
    PORT
      LAYER M4 ;
        RECT  0 32.4 0.192 32.424 ;
    END
  END pl1[14]
  PIN pl1[15]
    DIRECTION INPUT ;
    USE SIGNAL ;
    PORT
      LAYER M4 ;
        RECT  0 32.256 0.192 32.28 ;
    END
  END pl1[15]
  PIN pl1[1]
    DIRECTION INPUT ;
    USE SIGNAL ;
    PORT
      LAYER M4 ;
        RECT  0 34.272 0.192 34.296 ;
    END
  END pl1[1]
  PIN pl1[2]
    DIRECTION INPUT ;
    USE SIGNAL ;
    PORT
      LAYER M4 ;
        RECT  0 34.128 0.192 34.152 ;
    END
  END pl1[2]
  PIN pl1[3]
    DIRECTION INPUT ;
    USE SIGNAL ;
    PORT
      LAYER M4 ;
        RECT  0 33.984 0.192 34.008 ;
    END
  END pl1[3]
  PIN pl1[4]
    DIRECTION INPUT ;
    USE SIGNAL ;
    PORT
      LAYER M4 ;
        RECT  0 33.84 0.192 33.864 ;
    END
  END pl1[4]
  PIN pl1[5]
    DIRECTION INPUT ;
    USE SIGNAL ;
    PORT
      LAYER M4 ;
        RECT  0 33.696 0.192 33.72 ;
    END
  END pl1[5]
  PIN pl1[6]
    DIRECTION INPUT ;
    USE SIGNAL ;
    PORT
      LAYER M4 ;
        RECT  0 33.552 0.192 33.576 ;
    END
  END pl1[6]
  PIN pl1[7]
    DIRECTION INPUT ;
    USE SIGNAL ;
    PORT
      LAYER M4 ;
        RECT  0 33.408 0.192 33.432 ;
    END
  END pl1[7]
  PIN pl1[8]
    DIRECTION INPUT ;
    USE SIGNAL ;
    PORT
      LAYER M4 ;
        RECT  0 33.264 0.192 33.288 ;
    END
  END pl1[8]
  PIN pl1[9]
    DIRECTION INPUT ;
    USE SIGNAL ;
    PORT
      LAYER M4 ;
        RECT  0 33.12 0.192 33.144 ;
    END
  END pl1[9]
  PIN rd[0]
    DIRECTION OUTPUT ;
    USE SIGNAL ;
    PORT
      LAYER M3 ;
        RECT  24.48 86.256 24.498 86.4 ;
    END
  END rd[0]
  PIN rd[100]
    DIRECTION OUTPUT ;
    USE SIGNAL ;
    PORT
      LAYER M3 ;
        RECT  31.68 86.256 31.698 86.4 ;
    END
  END rd[100]
  PIN rd[101]
    DIRECTION OUTPUT ;
    USE SIGNAL ;
    PORT
      LAYER M5 ;
        RECT  31.728 86.208 31.752 86.4 ;
    END
  END rd[101]
  PIN rd[102]
    DIRECTION OUTPUT ;
    USE SIGNAL ;
    PORT
      LAYER M3 ;
        RECT  31.824 86.256 31.842 86.4 ;
    END
  END rd[102]
  PIN rd[103]
    DIRECTION OUTPUT ;
    USE SIGNAL ;
    PORT
      LAYER M5 ;
        RECT  31.872 86.208 31.896 86.4 ;
    END
  END rd[103]
  PIN rd[104]
    DIRECTION OUTPUT ;
    USE SIGNAL ;
    PORT
      LAYER M3 ;
        RECT  31.968 86.256 31.986 86.4 ;
    END
  END rd[104]
  PIN rd[105]
    DIRECTION OUTPUT ;
    USE SIGNAL ;
    PORT
      LAYER M5 ;
        RECT  32.016 86.208 32.04 86.4 ;
    END
  END rd[105]
  PIN rd[106]
    DIRECTION OUTPUT ;
    USE SIGNAL ;
    PORT
      LAYER M3 ;
        RECT  32.112 86.256 32.13 86.4 ;
    END
  END rd[106]
  PIN rd[107]
    DIRECTION OUTPUT ;
    USE SIGNAL ;
    PORT
      LAYER M5 ;
        RECT  32.16 86.208 32.184 86.4 ;
    END
  END rd[107]
  PIN rd[108]
    DIRECTION OUTPUT ;
    USE SIGNAL ;
    PORT
      LAYER M3 ;
        RECT  32.256 86.256 32.274 86.4 ;
    END
  END rd[108]
  PIN rd[109]
    DIRECTION OUTPUT ;
    USE SIGNAL ;
    PORT
      LAYER M5 ;
        RECT  32.304 86.208 32.328 86.4 ;
    END
  END rd[109]
  PIN rd[10]
    DIRECTION OUTPUT ;
    USE SIGNAL ;
    PORT
      LAYER M3 ;
        RECT  25.2 86.256 25.218 86.4 ;
    END
  END rd[10]
  PIN rd[110]
    DIRECTION OUTPUT ;
    USE SIGNAL ;
    PORT
      LAYER M3 ;
        RECT  32.4 86.256 32.418 86.4 ;
    END
  END rd[110]
  PIN rd[111]
    DIRECTION OUTPUT ;
    USE SIGNAL ;
    PORT
      LAYER M5 ;
        RECT  32.448 86.208 32.472 86.4 ;
    END
  END rd[111]
  PIN rd[112]
    DIRECTION OUTPUT ;
    USE SIGNAL ;
    PORT
      LAYER M3 ;
        RECT  32.544 86.256 32.562 86.4 ;
    END
  END rd[112]
  PIN rd[113]
    DIRECTION OUTPUT ;
    USE SIGNAL ;
    PORT
      LAYER M5 ;
        RECT  32.592 86.208 32.616 86.4 ;
    END
  END rd[113]
  PIN rd[114]
    DIRECTION OUTPUT ;
    USE SIGNAL ;
    PORT
      LAYER M3 ;
        RECT  32.688 86.256 32.706 86.4 ;
    END
  END rd[114]
  PIN rd[115]
    DIRECTION OUTPUT ;
    USE SIGNAL ;
    PORT
      LAYER M5 ;
        RECT  32.736 86.208 32.76 86.4 ;
    END
  END rd[115]
  PIN rd[116]
    DIRECTION OUTPUT ;
    USE SIGNAL ;
    PORT
      LAYER M3 ;
        RECT  32.832 86.256 32.85 86.4 ;
    END
  END rd[116]
  PIN rd[117]
    DIRECTION OUTPUT ;
    USE SIGNAL ;
    PORT
      LAYER M5 ;
        RECT  32.88 86.208 32.904 86.4 ;
    END
  END rd[117]
  PIN rd[118]
    DIRECTION OUTPUT ;
    USE SIGNAL ;
    PORT
      LAYER M3 ;
        RECT  32.976 86.256 32.994 86.4 ;
    END
  END rd[118]
  PIN rd[119]
    DIRECTION OUTPUT ;
    USE SIGNAL ;
    PORT
      LAYER M5 ;
        RECT  33.024 86.208 33.048 86.4 ;
    END
  END rd[119]
  PIN rd[11]
    DIRECTION OUTPUT ;
    USE SIGNAL ;
    PORT
      LAYER M5 ;
        RECT  25.248 86.208 25.272 86.4 ;
    END
  END rd[11]
  PIN rd[120]
    DIRECTION OUTPUT ;
    USE SIGNAL ;
    PORT
      LAYER M3 ;
        RECT  33.12 86.256 33.138 86.4 ;
    END
  END rd[120]
  PIN rd[121]
    DIRECTION OUTPUT ;
    USE SIGNAL ;
    PORT
      LAYER M5 ;
        RECT  33.168 86.208 33.192 86.4 ;
    END
  END rd[121]
  PIN rd[122]
    DIRECTION OUTPUT ;
    USE SIGNAL ;
    PORT
      LAYER M3 ;
        RECT  33.264 86.256 33.282 86.4 ;
    END
  END rd[122]
  PIN rd[123]
    DIRECTION OUTPUT ;
    USE SIGNAL ;
    PORT
      LAYER M5 ;
        RECT  33.312 86.208 33.336 86.4 ;
    END
  END rd[123]
  PIN rd[124]
    DIRECTION OUTPUT ;
    USE SIGNAL ;
    PORT
      LAYER M3 ;
        RECT  33.408 86.256 33.426 86.4 ;
    END
  END rd[124]
  PIN rd[125]
    DIRECTION OUTPUT ;
    USE SIGNAL ;
    PORT
      LAYER M5 ;
        RECT  33.456 86.208 33.48 86.4 ;
    END
  END rd[125]
  PIN rd[126]
    DIRECTION OUTPUT ;
    USE SIGNAL ;
    PORT
      LAYER M3 ;
        RECT  33.552 86.256 33.57 86.4 ;
    END
  END rd[126]
  PIN rd[127]
    DIRECTION OUTPUT ;
    USE SIGNAL ;
    PORT
      LAYER M5 ;
        RECT  33.6 86.208 33.624 86.4 ;
    END
  END rd[127]
  PIN rd[128]
    DIRECTION OUTPUT ;
    USE SIGNAL ;
    PORT
      LAYER M3 ;
        RECT  33.696 86.256 33.714 86.4 ;
    END
  END rd[128]
  PIN rd[129]
    DIRECTION OUTPUT ;
    USE SIGNAL ;
    PORT
      LAYER M5 ;
        RECT  33.744 86.208 33.768 86.4 ;
    END
  END rd[129]
  PIN rd[12]
    DIRECTION OUTPUT ;
    USE SIGNAL ;
    PORT
      LAYER M3 ;
        RECT  25.344 86.256 25.362 86.4 ;
    END
  END rd[12]
  PIN rd[130]
    DIRECTION OUTPUT ;
    USE SIGNAL ;
    PORT
      LAYER M3 ;
        RECT  33.84 86.256 33.858 86.4 ;
    END
  END rd[130]
  PIN rd[131]
    DIRECTION OUTPUT ;
    USE SIGNAL ;
    PORT
      LAYER M5 ;
        RECT  33.888 86.208 33.912 86.4 ;
    END
  END rd[131]
  PIN rd[132]
    DIRECTION OUTPUT ;
    USE SIGNAL ;
    PORT
      LAYER M3 ;
        RECT  33.984 86.256 34.002 86.4 ;
    END
  END rd[132]
  PIN rd[133]
    DIRECTION OUTPUT ;
    USE SIGNAL ;
    PORT
      LAYER M5 ;
        RECT  34.032 86.208 34.056 86.4 ;
    END
  END rd[133]
  PIN rd[134]
    DIRECTION OUTPUT ;
    USE SIGNAL ;
    PORT
      LAYER M3 ;
        RECT  34.128 86.256 34.146 86.4 ;
    END
  END rd[134]
  PIN rd[135]
    DIRECTION OUTPUT ;
    USE SIGNAL ;
    PORT
      LAYER M5 ;
        RECT  34.176 86.208 34.2 86.4 ;
    END
  END rd[135]
  PIN rd[136]
    DIRECTION OUTPUT ;
    USE SIGNAL ;
    PORT
      LAYER M3 ;
        RECT  34.272 86.256 34.29 86.4 ;
    END
  END rd[136]
  PIN rd[137]
    DIRECTION OUTPUT ;
    USE SIGNAL ;
    PORT
      LAYER M5 ;
        RECT  34.32 86.208 34.344 86.4 ;
    END
  END rd[137]
  PIN rd[138]
    DIRECTION OUTPUT ;
    USE SIGNAL ;
    PORT
      LAYER M3 ;
        RECT  34.416 86.256 34.434 86.4 ;
    END
  END rd[138]
  PIN rd[139]
    DIRECTION OUTPUT ;
    USE SIGNAL ;
    PORT
      LAYER M5 ;
        RECT  34.464 86.208 34.488 86.4 ;
    END
  END rd[139]
  PIN rd[13]
    DIRECTION OUTPUT ;
    USE SIGNAL ;
    PORT
      LAYER M5 ;
        RECT  25.392 86.208 25.416 86.4 ;
    END
  END rd[13]
  PIN rd[140]
    DIRECTION OUTPUT ;
    USE SIGNAL ;
    PORT
      LAYER M3 ;
        RECT  34.56 86.256 34.578 86.4 ;
    END
  END rd[140]
  PIN rd[141]
    DIRECTION OUTPUT ;
    USE SIGNAL ;
    PORT
      LAYER M5 ;
        RECT  34.608 86.208 34.632 86.4 ;
    END
  END rd[141]
  PIN rd[142]
    DIRECTION OUTPUT ;
    USE SIGNAL ;
    PORT
      LAYER M3 ;
        RECT  34.704 86.256 34.722 86.4 ;
    END
  END rd[142]
  PIN rd[143]
    DIRECTION OUTPUT ;
    USE SIGNAL ;
    PORT
      LAYER M5 ;
        RECT  34.752 86.208 34.776 86.4 ;
    END
  END rd[143]
  PIN rd[144]
    DIRECTION OUTPUT ;
    USE SIGNAL ;
    PORT
      LAYER M3 ;
        RECT  34.848 86.256 34.866 86.4 ;
    END
  END rd[144]
  PIN rd[145]
    DIRECTION OUTPUT ;
    USE SIGNAL ;
    PORT
      LAYER M5 ;
        RECT  34.896 86.208 34.92 86.4 ;
    END
  END rd[145]
  PIN rd[146]
    DIRECTION OUTPUT ;
    USE SIGNAL ;
    PORT
      LAYER M3 ;
        RECT  34.992 86.256 35.01 86.4 ;
    END
  END rd[146]
  PIN rd[147]
    DIRECTION OUTPUT ;
    USE SIGNAL ;
    PORT
      LAYER M5 ;
        RECT  35.04 86.208 35.064 86.4 ;
    END
  END rd[147]
  PIN rd[148]
    DIRECTION OUTPUT ;
    USE SIGNAL ;
    PORT
      LAYER M3 ;
        RECT  35.136 86.256 35.154 86.4 ;
    END
  END rd[148]
  PIN rd[149]
    DIRECTION OUTPUT ;
    USE SIGNAL ;
    PORT
      LAYER M5 ;
        RECT  35.184 86.208 35.208 86.4 ;
    END
  END rd[149]
  PIN rd[14]
    DIRECTION OUTPUT ;
    USE SIGNAL ;
    PORT
      LAYER M3 ;
        RECT  25.488 86.256 25.506 86.4 ;
    END
  END rd[14]
  PIN rd[150]
    DIRECTION OUTPUT ;
    USE SIGNAL ;
    PORT
      LAYER M3 ;
        RECT  35.28 86.256 35.298 86.4 ;
    END
  END rd[150]
  PIN rd[151]
    DIRECTION OUTPUT ;
    USE SIGNAL ;
    PORT
      LAYER M5 ;
        RECT  35.328 86.208 35.352 86.4 ;
    END
  END rd[151]
  PIN rd[152]
    DIRECTION OUTPUT ;
    USE SIGNAL ;
    PORT
      LAYER M3 ;
        RECT  35.424 86.256 35.442 86.4 ;
    END
  END rd[152]
  PIN rd[153]
    DIRECTION OUTPUT ;
    USE SIGNAL ;
    PORT
      LAYER M5 ;
        RECT  35.472 86.208 35.496 86.4 ;
    END
  END rd[153]
  PIN rd[154]
    DIRECTION OUTPUT ;
    USE SIGNAL ;
    PORT
      LAYER M3 ;
        RECT  35.568 86.256 35.586 86.4 ;
    END
  END rd[154]
  PIN rd[155]
    DIRECTION OUTPUT ;
    USE SIGNAL ;
    PORT
      LAYER M5 ;
        RECT  35.616 86.208 35.64 86.4 ;
    END
  END rd[155]
  PIN rd[156]
    DIRECTION OUTPUT ;
    USE SIGNAL ;
    PORT
      LAYER M3 ;
        RECT  35.712 86.256 35.73 86.4 ;
    END
  END rd[156]
  PIN rd[157]
    DIRECTION OUTPUT ;
    USE SIGNAL ;
    PORT
      LAYER M5 ;
        RECT  35.76 86.208 35.784 86.4 ;
    END
  END rd[157]
  PIN rd[158]
    DIRECTION OUTPUT ;
    USE SIGNAL ;
    PORT
      LAYER M3 ;
        RECT  35.856 86.256 35.874 86.4 ;
    END
  END rd[158]
  PIN rd[159]
    DIRECTION OUTPUT ;
    USE SIGNAL ;
    PORT
      LAYER M5 ;
        RECT  35.904 86.208 35.928 86.4 ;
    END
  END rd[159]
  PIN rd[15]
    DIRECTION OUTPUT ;
    USE SIGNAL ;
    PORT
      LAYER M5 ;
        RECT  25.536 86.208 25.56 86.4 ;
    END
  END rd[15]
  PIN rd[160]
    DIRECTION OUTPUT ;
    USE SIGNAL ;
    PORT
      LAYER M3 ;
        RECT  36 86.256 36.018 86.4 ;
    END
  END rd[160]
  PIN rd[161]
    DIRECTION OUTPUT ;
    USE SIGNAL ;
    PORT
      LAYER M5 ;
        RECT  36.048 86.208 36.072 86.4 ;
    END
  END rd[161]
  PIN rd[162]
    DIRECTION OUTPUT ;
    USE SIGNAL ;
    PORT
      LAYER M3 ;
        RECT  36.144 86.256 36.162 86.4 ;
    END
  END rd[162]
  PIN rd[163]
    DIRECTION OUTPUT ;
    USE SIGNAL ;
    PORT
      LAYER M5 ;
        RECT  36.192 86.208 36.216 86.4 ;
    END
  END rd[163]
  PIN rd[164]
    DIRECTION OUTPUT ;
    USE SIGNAL ;
    PORT
      LAYER M3 ;
        RECT  36.288 86.256 36.306 86.4 ;
    END
  END rd[164]
  PIN rd[165]
    DIRECTION OUTPUT ;
    USE SIGNAL ;
    PORT
      LAYER M5 ;
        RECT  36.336 86.208 36.36 86.4 ;
    END
  END rd[165]
  PIN rd[166]
    DIRECTION OUTPUT ;
    USE SIGNAL ;
    PORT
      LAYER M3 ;
        RECT  36.432 86.256 36.45 86.4 ;
    END
  END rd[166]
  PIN rd[167]
    DIRECTION OUTPUT ;
    USE SIGNAL ;
    PORT
      LAYER M5 ;
        RECT  36.48 86.208 36.504 86.4 ;
    END
  END rd[167]
  PIN rd[168]
    DIRECTION OUTPUT ;
    USE SIGNAL ;
    PORT
      LAYER M3 ;
        RECT  36.576 86.256 36.594 86.4 ;
    END
  END rd[168]
  PIN rd[169]
    DIRECTION OUTPUT ;
    USE SIGNAL ;
    PORT
      LAYER M5 ;
        RECT  36.624 86.208 36.648 86.4 ;
    END
  END rd[169]
  PIN rd[16]
    DIRECTION OUTPUT ;
    USE SIGNAL ;
    PORT
      LAYER M3 ;
        RECT  25.632 86.256 25.65 86.4 ;
    END
  END rd[16]
  PIN rd[170]
    DIRECTION OUTPUT ;
    USE SIGNAL ;
    PORT
      LAYER M3 ;
        RECT  36.72 86.256 36.738 86.4 ;
    END
  END rd[170]
  PIN rd[171]
    DIRECTION OUTPUT ;
    USE SIGNAL ;
    PORT
      LAYER M5 ;
        RECT  36.768 86.208 36.792 86.4 ;
    END
  END rd[171]
  PIN rd[172]
    DIRECTION OUTPUT ;
    USE SIGNAL ;
    PORT
      LAYER M3 ;
        RECT  36.864 86.256 36.882 86.4 ;
    END
  END rd[172]
  PIN rd[173]
    DIRECTION OUTPUT ;
    USE SIGNAL ;
    PORT
      LAYER M5 ;
        RECT  36.912 86.208 36.936 86.4 ;
    END
  END rd[173]
  PIN rd[174]
    DIRECTION OUTPUT ;
    USE SIGNAL ;
    PORT
      LAYER M3 ;
        RECT  37.008 86.256 37.026 86.4 ;
    END
  END rd[174]
  PIN rd[175]
    DIRECTION OUTPUT ;
    USE SIGNAL ;
    PORT
      LAYER M5 ;
        RECT  37.056 86.208 37.08 86.4 ;
    END
  END rd[175]
  PIN rd[176]
    DIRECTION OUTPUT ;
    USE SIGNAL ;
    PORT
      LAYER M3 ;
        RECT  37.152 86.256 37.17 86.4 ;
    END
  END rd[176]
  PIN rd[177]
    DIRECTION OUTPUT ;
    USE SIGNAL ;
    PORT
      LAYER M5 ;
        RECT  37.2 86.208 37.224 86.4 ;
    END
  END rd[177]
  PIN rd[178]
    DIRECTION OUTPUT ;
    USE SIGNAL ;
    PORT
      LAYER M3 ;
        RECT  37.296 86.256 37.314 86.4 ;
    END
  END rd[178]
  PIN rd[179]
    DIRECTION OUTPUT ;
    USE SIGNAL ;
    PORT
      LAYER M5 ;
        RECT  37.344 86.208 37.368 86.4 ;
    END
  END rd[179]
  PIN rd[17]
    DIRECTION OUTPUT ;
    USE SIGNAL ;
    PORT
      LAYER M5 ;
        RECT  25.68 86.208 25.704 86.4 ;
    END
  END rd[17]
  PIN rd[180]
    DIRECTION OUTPUT ;
    USE SIGNAL ;
    PORT
      LAYER M3 ;
        RECT  37.44 86.256 37.458 86.4 ;
    END
  END rd[180]
  PIN rd[181]
    DIRECTION OUTPUT ;
    USE SIGNAL ;
    PORT
      LAYER M5 ;
        RECT  37.488 86.208 37.512 86.4 ;
    END
  END rd[181]
  PIN rd[182]
    DIRECTION OUTPUT ;
    USE SIGNAL ;
    PORT
      LAYER M3 ;
        RECT  37.584 86.256 37.602 86.4 ;
    END
  END rd[182]
  PIN rd[183]
    DIRECTION OUTPUT ;
    USE SIGNAL ;
    PORT
      LAYER M5 ;
        RECT  37.632 86.208 37.656 86.4 ;
    END
  END rd[183]
  PIN rd[184]
    DIRECTION OUTPUT ;
    USE SIGNAL ;
    PORT
      LAYER M3 ;
        RECT  37.728 86.256 37.746 86.4 ;
    END
  END rd[184]
  PIN rd[185]
    DIRECTION OUTPUT ;
    USE SIGNAL ;
    PORT
      LAYER M5 ;
        RECT  37.776 86.208 37.8 86.4 ;
    END
  END rd[185]
  PIN rd[186]
    DIRECTION OUTPUT ;
    USE SIGNAL ;
    PORT
      LAYER M3 ;
        RECT  37.872 86.256 37.89 86.4 ;
    END
  END rd[186]
  PIN rd[187]
    DIRECTION OUTPUT ;
    USE SIGNAL ;
    PORT
      LAYER M5 ;
        RECT  37.92 86.208 37.944 86.4 ;
    END
  END rd[187]
  PIN rd[188]
    DIRECTION OUTPUT ;
    USE SIGNAL ;
    PORT
      LAYER M3 ;
        RECT  38.016 86.256 38.034 86.4 ;
    END
  END rd[188]
  PIN rd[189]
    DIRECTION OUTPUT ;
    USE SIGNAL ;
    PORT
      LAYER M5 ;
        RECT  38.064 86.208 38.088 86.4 ;
    END
  END rd[189]
  PIN rd[18]
    DIRECTION OUTPUT ;
    USE SIGNAL ;
    PORT
      LAYER M3 ;
        RECT  25.776 86.256 25.794 86.4 ;
    END
  END rd[18]
  PIN rd[190]
    DIRECTION OUTPUT ;
    USE SIGNAL ;
    PORT
      LAYER M3 ;
        RECT  38.16 86.256 38.178 86.4 ;
    END
  END rd[190]
  PIN rd[191]
    DIRECTION OUTPUT ;
    USE SIGNAL ;
    PORT
      LAYER M5 ;
        RECT  38.208 86.208 38.232 86.4 ;
    END
  END rd[191]
  PIN rd[192]
    DIRECTION OUTPUT ;
    USE SIGNAL ;
    PORT
      LAYER M3 ;
        RECT  38.304 86.256 38.322 86.4 ;
    END
  END rd[192]
  PIN rd[193]
    DIRECTION OUTPUT ;
    USE SIGNAL ;
    PORT
      LAYER M5 ;
        RECT  38.352 86.208 38.376 86.4 ;
    END
  END rd[193]
  PIN rd[194]
    DIRECTION OUTPUT ;
    USE SIGNAL ;
    PORT
      LAYER M3 ;
        RECT  38.448 86.256 38.466 86.4 ;
    END
  END rd[194]
  PIN rd[195]
    DIRECTION OUTPUT ;
    USE SIGNAL ;
    PORT
      LAYER M5 ;
        RECT  38.496 86.208 38.52 86.4 ;
    END
  END rd[195]
  PIN rd[196]
    DIRECTION OUTPUT ;
    USE SIGNAL ;
    PORT
      LAYER M3 ;
        RECT  38.592 86.256 38.61 86.4 ;
    END
  END rd[196]
  PIN rd[197]
    DIRECTION OUTPUT ;
    USE SIGNAL ;
    PORT
      LAYER M5 ;
        RECT  38.64 86.208 38.664 86.4 ;
    END
  END rd[197]
  PIN rd[198]
    DIRECTION OUTPUT ;
    USE SIGNAL ;
    PORT
      LAYER M3 ;
        RECT  38.736 86.256 38.754 86.4 ;
    END
  END rd[198]
  PIN rd[199]
    DIRECTION OUTPUT ;
    USE SIGNAL ;
    PORT
      LAYER M5 ;
        RECT  38.784 86.208 38.808 86.4 ;
    END
  END rd[199]
  PIN rd[19]
    DIRECTION OUTPUT ;
    USE SIGNAL ;
    PORT
      LAYER M5 ;
        RECT  25.824 86.208 25.848 86.4 ;
    END
  END rd[19]
  PIN rd[1]
    DIRECTION OUTPUT ;
    USE SIGNAL ;
    PORT
      LAYER M5 ;
        RECT  24.528 86.208 24.552 86.4 ;
    END
  END rd[1]
  PIN rd[200]
    DIRECTION OUTPUT ;
    USE SIGNAL ;
    PORT
      LAYER M3 ;
        RECT  38.88 86.256 38.898 86.4 ;
    END
  END rd[200]
  PIN rd[201]
    DIRECTION OUTPUT ;
    USE SIGNAL ;
    PORT
      LAYER M5 ;
        RECT  38.928 86.208 38.952 86.4 ;
    END
  END rd[201]
  PIN rd[202]
    DIRECTION OUTPUT ;
    USE SIGNAL ;
    PORT
      LAYER M3 ;
        RECT  39.024 86.256 39.042 86.4 ;
    END
  END rd[202]
  PIN rd[203]
    DIRECTION OUTPUT ;
    USE SIGNAL ;
    PORT
      LAYER M5 ;
        RECT  39.072 86.208 39.096 86.4 ;
    END
  END rd[203]
  PIN rd[204]
    DIRECTION OUTPUT ;
    USE SIGNAL ;
    PORT
      LAYER M3 ;
        RECT  39.168 86.256 39.186 86.4 ;
    END
  END rd[204]
  PIN rd[205]
    DIRECTION OUTPUT ;
    USE SIGNAL ;
    PORT
      LAYER M5 ;
        RECT  39.216 86.208 39.24 86.4 ;
    END
  END rd[205]
  PIN rd[206]
    DIRECTION OUTPUT ;
    USE SIGNAL ;
    PORT
      LAYER M3 ;
        RECT  39.312 86.256 39.33 86.4 ;
    END
  END rd[206]
  PIN rd[207]
    DIRECTION OUTPUT ;
    USE SIGNAL ;
    PORT
      LAYER M5 ;
        RECT  39.36 86.208 39.384 86.4 ;
    END
  END rd[207]
  PIN rd[208]
    DIRECTION OUTPUT ;
    USE SIGNAL ;
    PORT
      LAYER M3 ;
        RECT  39.456 86.256 39.474 86.4 ;
    END
  END rd[208]
  PIN rd[209]
    DIRECTION OUTPUT ;
    USE SIGNAL ;
    PORT
      LAYER M5 ;
        RECT  39.504 86.208 39.528 86.4 ;
    END
  END rd[209]
  PIN rd[20]
    DIRECTION OUTPUT ;
    USE SIGNAL ;
    PORT
      LAYER M3 ;
        RECT  25.92 86.256 25.938 86.4 ;
    END
  END rd[20]
  PIN rd[210]
    DIRECTION OUTPUT ;
    USE SIGNAL ;
    PORT
      LAYER M3 ;
        RECT  39.6 86.256 39.618 86.4 ;
    END
  END rd[210]
  PIN rd[211]
    DIRECTION OUTPUT ;
    USE SIGNAL ;
    PORT
      LAYER M5 ;
        RECT  39.648 86.208 39.672 86.4 ;
    END
  END rd[211]
  PIN rd[212]
    DIRECTION OUTPUT ;
    USE SIGNAL ;
    PORT
      LAYER M3 ;
        RECT  39.744 86.256 39.762 86.4 ;
    END
  END rd[212]
  PIN rd[213]
    DIRECTION OUTPUT ;
    USE SIGNAL ;
    PORT
      LAYER M5 ;
        RECT  39.792 86.208 39.816 86.4 ;
    END
  END rd[213]
  PIN rd[214]
    DIRECTION OUTPUT ;
    USE SIGNAL ;
    PORT
      LAYER M3 ;
        RECT  39.888 86.256 39.906 86.4 ;
    END
  END rd[214]
  PIN rd[215]
    DIRECTION OUTPUT ;
    USE SIGNAL ;
    PORT
      LAYER M5 ;
        RECT  39.936 86.208 39.96 86.4 ;
    END
  END rd[215]
  PIN rd[216]
    DIRECTION OUTPUT ;
    USE SIGNAL ;
    PORT
      LAYER M3 ;
        RECT  40.032 86.256 40.05 86.4 ;
    END
  END rd[216]
  PIN rd[217]
    DIRECTION OUTPUT ;
    USE SIGNAL ;
    PORT
      LAYER M5 ;
        RECT  40.08 86.208 40.104 86.4 ;
    END
  END rd[217]
  PIN rd[218]
    DIRECTION OUTPUT ;
    USE SIGNAL ;
    PORT
      LAYER M3 ;
        RECT  40.176 86.256 40.194 86.4 ;
    END
  END rd[218]
  PIN rd[219]
    DIRECTION OUTPUT ;
    USE SIGNAL ;
    PORT
      LAYER M5 ;
        RECT  40.224 86.208 40.248 86.4 ;
    END
  END rd[219]
  PIN rd[21]
    DIRECTION OUTPUT ;
    USE SIGNAL ;
    PORT
      LAYER M5 ;
        RECT  25.968 86.208 25.992 86.4 ;
    END
  END rd[21]
  PIN rd[220]
    DIRECTION OUTPUT ;
    USE SIGNAL ;
    PORT
      LAYER M3 ;
        RECT  40.32 86.256 40.338 86.4 ;
    END
  END rd[220]
  PIN rd[221]
    DIRECTION OUTPUT ;
    USE SIGNAL ;
    PORT
      LAYER M5 ;
        RECT  40.368 86.208 40.392 86.4 ;
    END
  END rd[221]
  PIN rd[222]
    DIRECTION OUTPUT ;
    USE SIGNAL ;
    PORT
      LAYER M3 ;
        RECT  40.464 86.256 40.482 86.4 ;
    END
  END rd[222]
  PIN rd[223]
    DIRECTION OUTPUT ;
    USE SIGNAL ;
    PORT
      LAYER M5 ;
        RECT  40.512 86.208 40.536 86.4 ;
    END
  END rd[223]
  PIN rd[224]
    DIRECTION OUTPUT ;
    USE SIGNAL ;
    PORT
      LAYER M3 ;
        RECT  40.608 86.256 40.626 86.4 ;
    END
  END rd[224]
  PIN rd[225]
    DIRECTION OUTPUT ;
    USE SIGNAL ;
    PORT
      LAYER M5 ;
        RECT  40.656 86.208 40.68 86.4 ;
    END
  END rd[225]
  PIN rd[226]
    DIRECTION OUTPUT ;
    USE SIGNAL ;
    PORT
      LAYER M3 ;
        RECT  40.752 86.256 40.77 86.4 ;
    END
  END rd[226]
  PIN rd[227]
    DIRECTION OUTPUT ;
    USE SIGNAL ;
    PORT
      LAYER M5 ;
        RECT  40.8 86.208 40.824 86.4 ;
    END
  END rd[227]
  PIN rd[228]
    DIRECTION OUTPUT ;
    USE SIGNAL ;
    PORT
      LAYER M3 ;
        RECT  40.896 86.256 40.914 86.4 ;
    END
  END rd[228]
  PIN rd[229]
    DIRECTION OUTPUT ;
    USE SIGNAL ;
    PORT
      LAYER M5 ;
        RECT  40.944 86.208 40.968 86.4 ;
    END
  END rd[229]
  PIN rd[22]
    DIRECTION OUTPUT ;
    USE SIGNAL ;
    PORT
      LAYER M3 ;
        RECT  26.064 86.256 26.082 86.4 ;
    END
  END rd[22]
  PIN rd[230]
    DIRECTION OUTPUT ;
    USE SIGNAL ;
    PORT
      LAYER M3 ;
        RECT  41.04 86.256 41.058 86.4 ;
    END
  END rd[230]
  PIN rd[231]
    DIRECTION OUTPUT ;
    USE SIGNAL ;
    PORT
      LAYER M5 ;
        RECT  41.088 86.208 41.112 86.4 ;
    END
  END rd[231]
  PIN rd[232]
    DIRECTION OUTPUT ;
    USE SIGNAL ;
    PORT
      LAYER M3 ;
        RECT  41.184 86.256 41.202 86.4 ;
    END
  END rd[232]
  PIN rd[233]
    DIRECTION OUTPUT ;
    USE SIGNAL ;
    PORT
      LAYER M5 ;
        RECT  41.232 86.208 41.256 86.4 ;
    END
  END rd[233]
  PIN rd[234]
    DIRECTION OUTPUT ;
    USE SIGNAL ;
    PORT
      LAYER M3 ;
        RECT  41.328 86.256 41.346 86.4 ;
    END
  END rd[234]
  PIN rd[235]
    DIRECTION OUTPUT ;
    USE SIGNAL ;
    PORT
      LAYER M5 ;
        RECT  41.376 86.208 41.4 86.4 ;
    END
  END rd[235]
  PIN rd[236]
    DIRECTION OUTPUT ;
    USE SIGNAL ;
    PORT
      LAYER M3 ;
        RECT  41.472 86.256 41.49 86.4 ;
    END
  END rd[236]
  PIN rd[237]
    DIRECTION OUTPUT ;
    USE SIGNAL ;
    PORT
      LAYER M5 ;
        RECT  41.52 86.208 41.544 86.4 ;
    END
  END rd[237]
  PIN rd[238]
    DIRECTION OUTPUT ;
    USE SIGNAL ;
    PORT
      LAYER M3 ;
        RECT  41.616 86.256 41.634 86.4 ;
    END
  END rd[238]
  PIN rd[239]
    DIRECTION OUTPUT ;
    USE SIGNAL ;
    PORT
      LAYER M5 ;
        RECT  41.664 86.208 41.688 86.4 ;
    END
  END rd[239]
  PIN rd[23]
    DIRECTION OUTPUT ;
    USE SIGNAL ;
    PORT
      LAYER M5 ;
        RECT  26.112 86.208 26.136 86.4 ;
    END
  END rd[23]
  PIN rd[240]
    DIRECTION OUTPUT ;
    USE SIGNAL ;
    PORT
      LAYER M3 ;
        RECT  41.76 86.256 41.778 86.4 ;
    END
  END rd[240]
  PIN rd[241]
    DIRECTION OUTPUT ;
    USE SIGNAL ;
    PORT
      LAYER M5 ;
        RECT  41.808 86.208 41.832 86.4 ;
    END
  END rd[241]
  PIN rd[242]
    DIRECTION OUTPUT ;
    USE SIGNAL ;
    PORT
      LAYER M3 ;
        RECT  41.904 86.256 41.922 86.4 ;
    END
  END rd[242]
  PIN rd[243]
    DIRECTION OUTPUT ;
    USE SIGNAL ;
    PORT
      LAYER M5 ;
        RECT  41.952 86.208 41.976 86.4 ;
    END
  END rd[243]
  PIN rd[244]
    DIRECTION OUTPUT ;
    USE SIGNAL ;
    PORT
      LAYER M3 ;
        RECT  42.048 86.256 42.066 86.4 ;
    END
  END rd[244]
  PIN rd[245]
    DIRECTION OUTPUT ;
    USE SIGNAL ;
    PORT
      LAYER M5 ;
        RECT  42.096 86.208 42.12 86.4 ;
    END
  END rd[245]
  PIN rd[246]
    DIRECTION OUTPUT ;
    USE SIGNAL ;
    PORT
      LAYER M3 ;
        RECT  42.192 86.256 42.21 86.4 ;
    END
  END rd[246]
  PIN rd[247]
    DIRECTION OUTPUT ;
    USE SIGNAL ;
    PORT
      LAYER M5 ;
        RECT  42.24 86.208 42.264 86.4 ;
    END
  END rd[247]
  PIN rd[248]
    DIRECTION OUTPUT ;
    USE SIGNAL ;
    PORT
      LAYER M3 ;
        RECT  42.336 86.256 42.354 86.4 ;
    END
  END rd[248]
  PIN rd[249]
    DIRECTION OUTPUT ;
    USE SIGNAL ;
    PORT
      LAYER M5 ;
        RECT  42.384 86.208 42.408 86.4 ;
    END
  END rd[249]
  PIN rd[24]
    DIRECTION OUTPUT ;
    USE SIGNAL ;
    PORT
      LAYER M3 ;
        RECT  26.208 86.256 26.226 86.4 ;
    END
  END rd[24]
  PIN rd[250]
    DIRECTION OUTPUT ;
    USE SIGNAL ;
    PORT
      LAYER M3 ;
        RECT  42.48 86.256 42.498 86.4 ;
    END
  END rd[250]
  PIN rd[251]
    DIRECTION OUTPUT ;
    USE SIGNAL ;
    PORT
      LAYER M5 ;
        RECT  42.528 86.208 42.552 86.4 ;
    END
  END rd[251]
  PIN rd[252]
    DIRECTION OUTPUT ;
    USE SIGNAL ;
    PORT
      LAYER M3 ;
        RECT  42.624 86.256 42.642 86.4 ;
    END
  END rd[252]
  PIN rd[253]
    DIRECTION OUTPUT ;
    USE SIGNAL ;
    PORT
      LAYER M5 ;
        RECT  42.672 86.208 42.696 86.4 ;
    END
  END rd[253]
  PIN rd[254]
    DIRECTION OUTPUT ;
    USE SIGNAL ;
    PORT
      LAYER M3 ;
        RECT  42.768 86.256 42.786 86.4 ;
    END
  END rd[254]
  PIN rd[255]
    DIRECTION OUTPUT ;
    USE SIGNAL ;
    PORT
      LAYER M5 ;
        RECT  42.816 86.208 42.84 86.4 ;
    END
  END rd[255]
  PIN rd[25]
    DIRECTION OUTPUT ;
    USE SIGNAL ;
    PORT
      LAYER M5 ;
        RECT  26.256 86.208 26.28 86.4 ;
    END
  END rd[25]
  PIN rd[26]
    DIRECTION OUTPUT ;
    USE SIGNAL ;
    PORT
      LAYER M3 ;
        RECT  26.352 86.256 26.37 86.4 ;
    END
  END rd[26]
  PIN rd[27]
    DIRECTION OUTPUT ;
    USE SIGNAL ;
    PORT
      LAYER M5 ;
        RECT  26.4 86.208 26.424 86.4 ;
    END
  END rd[27]
  PIN rd[28]
    DIRECTION OUTPUT ;
    USE SIGNAL ;
    PORT
      LAYER M3 ;
        RECT  26.496 86.256 26.514 86.4 ;
    END
  END rd[28]
  PIN rd[29]
    DIRECTION OUTPUT ;
    USE SIGNAL ;
    PORT
      LAYER M5 ;
        RECT  26.544 86.208 26.568 86.4 ;
    END
  END rd[29]
  PIN rd[2]
    DIRECTION OUTPUT ;
    USE SIGNAL ;
    PORT
      LAYER M3 ;
        RECT  24.624 86.256 24.642 86.4 ;
    END
  END rd[2]
  PIN rd[30]
    DIRECTION OUTPUT ;
    USE SIGNAL ;
    PORT
      LAYER M3 ;
        RECT  26.64 86.256 26.658 86.4 ;
    END
  END rd[30]
  PIN rd[31]
    DIRECTION OUTPUT ;
    USE SIGNAL ;
    PORT
      LAYER M5 ;
        RECT  26.688 86.208 26.712 86.4 ;
    END
  END rd[31]
  PIN rd[32]
    DIRECTION OUTPUT ;
    USE SIGNAL ;
    PORT
      LAYER M3 ;
        RECT  26.784 86.256 26.802 86.4 ;
    END
  END rd[32]
  PIN rd[33]
    DIRECTION OUTPUT ;
    USE SIGNAL ;
    PORT
      LAYER M5 ;
        RECT  26.832 86.208 26.856 86.4 ;
    END
  END rd[33]
  PIN rd[34]
    DIRECTION OUTPUT ;
    USE SIGNAL ;
    PORT
      LAYER M3 ;
        RECT  26.928 86.256 26.946 86.4 ;
    END
  END rd[34]
  PIN rd[35]
    DIRECTION OUTPUT ;
    USE SIGNAL ;
    PORT
      LAYER M5 ;
        RECT  26.976 86.208 27 86.4 ;
    END
  END rd[35]
  PIN rd[36]
    DIRECTION OUTPUT ;
    USE SIGNAL ;
    PORT
      LAYER M3 ;
        RECT  27.072 86.256 27.09 86.4 ;
    END
  END rd[36]
  PIN rd[37]
    DIRECTION OUTPUT ;
    USE SIGNAL ;
    PORT
      LAYER M5 ;
        RECT  27.12 86.208 27.144 86.4 ;
    END
  END rd[37]
  PIN rd[38]
    DIRECTION OUTPUT ;
    USE SIGNAL ;
    PORT
      LAYER M3 ;
        RECT  27.216 86.256 27.234 86.4 ;
    END
  END rd[38]
  PIN rd[39]
    DIRECTION OUTPUT ;
    USE SIGNAL ;
    PORT
      LAYER M5 ;
        RECT  27.264 86.208 27.288 86.4 ;
    END
  END rd[39]
  PIN rd[3]
    DIRECTION OUTPUT ;
    USE SIGNAL ;
    PORT
      LAYER M5 ;
        RECT  24.672 86.208 24.696 86.4 ;
    END
  END rd[3]
  PIN rd[40]
    DIRECTION OUTPUT ;
    USE SIGNAL ;
    PORT
      LAYER M3 ;
        RECT  27.36 86.256 27.378 86.4 ;
    END
  END rd[40]
  PIN rd[41]
    DIRECTION OUTPUT ;
    USE SIGNAL ;
    PORT
      LAYER M5 ;
        RECT  27.408 86.208 27.432 86.4 ;
    END
  END rd[41]
  PIN rd[42]
    DIRECTION OUTPUT ;
    USE SIGNAL ;
    PORT
      LAYER M3 ;
        RECT  27.504 86.256 27.522 86.4 ;
    END
  END rd[42]
  PIN rd[43]
    DIRECTION OUTPUT ;
    USE SIGNAL ;
    PORT
      LAYER M5 ;
        RECT  27.552 86.208 27.576 86.4 ;
    END
  END rd[43]
  PIN rd[44]
    DIRECTION OUTPUT ;
    USE SIGNAL ;
    PORT
      LAYER M3 ;
        RECT  27.648 86.256 27.666 86.4 ;
    END
  END rd[44]
  PIN rd[45]
    DIRECTION OUTPUT ;
    USE SIGNAL ;
    PORT
      LAYER M5 ;
        RECT  27.696 86.208 27.72 86.4 ;
    END
  END rd[45]
  PIN rd[46]
    DIRECTION OUTPUT ;
    USE SIGNAL ;
    PORT
      LAYER M3 ;
        RECT  27.792 86.256 27.81 86.4 ;
    END
  END rd[46]
  PIN rd[47]
    DIRECTION OUTPUT ;
    USE SIGNAL ;
    PORT
      LAYER M5 ;
        RECT  27.84 86.208 27.864 86.4 ;
    END
  END rd[47]
  PIN rd[48]
    DIRECTION OUTPUT ;
    USE SIGNAL ;
    PORT
      LAYER M3 ;
        RECT  27.936 86.256 27.954 86.4 ;
    END
  END rd[48]
  PIN rd[49]
    DIRECTION OUTPUT ;
    USE SIGNAL ;
    PORT
      LAYER M5 ;
        RECT  27.984 86.208 28.008 86.4 ;
    END
  END rd[49]
  PIN rd[4]
    DIRECTION OUTPUT ;
    USE SIGNAL ;
    PORT
      LAYER M3 ;
        RECT  24.768 86.256 24.786 86.4 ;
    END
  END rd[4]
  PIN rd[50]
    DIRECTION OUTPUT ;
    USE SIGNAL ;
    PORT
      LAYER M3 ;
        RECT  28.08 86.256 28.098 86.4 ;
    END
  END rd[50]
  PIN rd[51]
    DIRECTION OUTPUT ;
    USE SIGNAL ;
    PORT
      LAYER M5 ;
        RECT  28.128 86.208 28.152 86.4 ;
    END
  END rd[51]
  PIN rd[52]
    DIRECTION OUTPUT ;
    USE SIGNAL ;
    PORT
      LAYER M3 ;
        RECT  28.224 86.256 28.242 86.4 ;
    END
  END rd[52]
  PIN rd[53]
    DIRECTION OUTPUT ;
    USE SIGNAL ;
    PORT
      LAYER M5 ;
        RECT  28.272 86.208 28.296 86.4 ;
    END
  END rd[53]
  PIN rd[54]
    DIRECTION OUTPUT ;
    USE SIGNAL ;
    PORT
      LAYER M3 ;
        RECT  28.368 86.256 28.386 86.4 ;
    END
  END rd[54]
  PIN rd[55]
    DIRECTION OUTPUT ;
    USE SIGNAL ;
    PORT
      LAYER M5 ;
        RECT  28.416 86.208 28.44 86.4 ;
    END
  END rd[55]
  PIN rd[56]
    DIRECTION OUTPUT ;
    USE SIGNAL ;
    PORT
      LAYER M3 ;
        RECT  28.512 86.256 28.53 86.4 ;
    END
  END rd[56]
  PIN rd[57]
    DIRECTION OUTPUT ;
    USE SIGNAL ;
    PORT
      LAYER M5 ;
        RECT  28.56 86.208 28.584 86.4 ;
    END
  END rd[57]
  PIN rd[58]
    DIRECTION OUTPUT ;
    USE SIGNAL ;
    PORT
      LAYER M3 ;
        RECT  28.656 86.256 28.674 86.4 ;
    END
  END rd[58]
  PIN rd[59]
    DIRECTION OUTPUT ;
    USE SIGNAL ;
    PORT
      LAYER M5 ;
        RECT  28.704 86.208 28.728 86.4 ;
    END
  END rd[59]
  PIN rd[5]
    DIRECTION OUTPUT ;
    USE SIGNAL ;
    PORT
      LAYER M5 ;
        RECT  24.816 86.208 24.84 86.4 ;
    END
  END rd[5]
  PIN rd[60]
    DIRECTION OUTPUT ;
    USE SIGNAL ;
    PORT
      LAYER M3 ;
        RECT  28.8 86.256 28.818 86.4 ;
    END
  END rd[60]
  PIN rd[61]
    DIRECTION OUTPUT ;
    USE SIGNAL ;
    PORT
      LAYER M5 ;
        RECT  28.848 86.208 28.872 86.4 ;
    END
  END rd[61]
  PIN rd[62]
    DIRECTION OUTPUT ;
    USE SIGNAL ;
    PORT
      LAYER M3 ;
        RECT  28.944 86.256 28.962 86.4 ;
    END
  END rd[62]
  PIN rd[63]
    DIRECTION OUTPUT ;
    USE SIGNAL ;
    PORT
      LAYER M5 ;
        RECT  28.992 86.208 29.016 86.4 ;
    END
  END rd[63]
  PIN rd[64]
    DIRECTION OUTPUT ;
    USE SIGNAL ;
    PORT
      LAYER M3 ;
        RECT  29.088 86.256 29.106 86.4 ;
    END
  END rd[64]
  PIN rd[65]
    DIRECTION OUTPUT ;
    USE SIGNAL ;
    PORT
      LAYER M5 ;
        RECT  29.136 86.208 29.16 86.4 ;
    END
  END rd[65]
  PIN rd[66]
    DIRECTION OUTPUT ;
    USE SIGNAL ;
    PORT
      LAYER M3 ;
        RECT  29.232 86.256 29.25 86.4 ;
    END
  END rd[66]
  PIN rd[67]
    DIRECTION OUTPUT ;
    USE SIGNAL ;
    PORT
      LAYER M5 ;
        RECT  29.28 86.208 29.304 86.4 ;
    END
  END rd[67]
  PIN rd[68]
    DIRECTION OUTPUT ;
    USE SIGNAL ;
    PORT
      LAYER M3 ;
        RECT  29.376 86.256 29.394 86.4 ;
    END
  END rd[68]
  PIN rd[69]
    DIRECTION OUTPUT ;
    USE SIGNAL ;
    PORT
      LAYER M5 ;
        RECT  29.424 86.208 29.448 86.4 ;
    END
  END rd[69]
  PIN rd[6]
    DIRECTION OUTPUT ;
    USE SIGNAL ;
    PORT
      LAYER M3 ;
        RECT  24.912 86.256 24.93 86.4 ;
    END
  END rd[6]
  PIN rd[70]
    DIRECTION OUTPUT ;
    USE SIGNAL ;
    PORT
      LAYER M3 ;
        RECT  29.52 86.256 29.538 86.4 ;
    END
  END rd[70]
  PIN rd[71]
    DIRECTION OUTPUT ;
    USE SIGNAL ;
    PORT
      LAYER M5 ;
        RECT  29.568 86.208 29.592 86.4 ;
    END
  END rd[71]
  PIN rd[72]
    DIRECTION OUTPUT ;
    USE SIGNAL ;
    PORT
      LAYER M3 ;
        RECT  29.664 86.256 29.682 86.4 ;
    END
  END rd[72]
  PIN rd[73]
    DIRECTION OUTPUT ;
    USE SIGNAL ;
    PORT
      LAYER M5 ;
        RECT  29.712 86.208 29.736 86.4 ;
    END
  END rd[73]
  PIN rd[74]
    DIRECTION OUTPUT ;
    USE SIGNAL ;
    PORT
      LAYER M3 ;
        RECT  29.808 86.256 29.826 86.4 ;
    END
  END rd[74]
  PIN rd[75]
    DIRECTION OUTPUT ;
    USE SIGNAL ;
    PORT
      LAYER M5 ;
        RECT  29.856 86.208 29.88 86.4 ;
    END
  END rd[75]
  PIN rd[76]
    DIRECTION OUTPUT ;
    USE SIGNAL ;
    PORT
      LAYER M3 ;
        RECT  29.952 86.256 29.97 86.4 ;
    END
  END rd[76]
  PIN rd[77]
    DIRECTION OUTPUT ;
    USE SIGNAL ;
    PORT
      LAYER M5 ;
        RECT  30 86.208 30.024 86.4 ;
    END
  END rd[77]
  PIN rd[78]
    DIRECTION OUTPUT ;
    USE SIGNAL ;
    PORT
      LAYER M3 ;
        RECT  30.096 86.256 30.114 86.4 ;
    END
  END rd[78]
  PIN rd[79]
    DIRECTION OUTPUT ;
    USE SIGNAL ;
    PORT
      LAYER M5 ;
        RECT  30.144 86.208 30.168 86.4 ;
    END
  END rd[79]
  PIN rd[7]
    DIRECTION OUTPUT ;
    USE SIGNAL ;
    PORT
      LAYER M5 ;
        RECT  24.96 86.208 24.984 86.4 ;
    END
  END rd[7]
  PIN rd[80]
    DIRECTION OUTPUT ;
    USE SIGNAL ;
    PORT
      LAYER M3 ;
        RECT  30.24 86.256 30.258 86.4 ;
    END
  END rd[80]
  PIN rd[81]
    DIRECTION OUTPUT ;
    USE SIGNAL ;
    PORT
      LAYER M5 ;
        RECT  30.288 86.208 30.312 86.4 ;
    END
  END rd[81]
  PIN rd[82]
    DIRECTION OUTPUT ;
    USE SIGNAL ;
    PORT
      LAYER M3 ;
        RECT  30.384 86.256 30.402 86.4 ;
    END
  END rd[82]
  PIN rd[83]
    DIRECTION OUTPUT ;
    USE SIGNAL ;
    PORT
      LAYER M5 ;
        RECT  30.432 86.208 30.456 86.4 ;
    END
  END rd[83]
  PIN rd[84]
    DIRECTION OUTPUT ;
    USE SIGNAL ;
    PORT
      LAYER M3 ;
        RECT  30.528 86.256 30.546 86.4 ;
    END
  END rd[84]
  PIN rd[85]
    DIRECTION OUTPUT ;
    USE SIGNAL ;
    PORT
      LAYER M5 ;
        RECT  30.576 86.208 30.6 86.4 ;
    END
  END rd[85]
  PIN rd[86]
    DIRECTION OUTPUT ;
    USE SIGNAL ;
    PORT
      LAYER M3 ;
        RECT  30.672 86.256 30.69 86.4 ;
    END
  END rd[86]
  PIN rd[87]
    DIRECTION OUTPUT ;
    USE SIGNAL ;
    PORT
      LAYER M5 ;
        RECT  30.72 86.208 30.744 86.4 ;
    END
  END rd[87]
  PIN rd[88]
    DIRECTION OUTPUT ;
    USE SIGNAL ;
    PORT
      LAYER M3 ;
        RECT  30.816 86.256 30.834 86.4 ;
    END
  END rd[88]
  PIN rd[89]
    DIRECTION OUTPUT ;
    USE SIGNAL ;
    PORT
      LAYER M5 ;
        RECT  30.864 86.208 30.888 86.4 ;
    END
  END rd[89]
  PIN rd[8]
    DIRECTION OUTPUT ;
    USE SIGNAL ;
    PORT
      LAYER M3 ;
        RECT  25.056 86.256 25.074 86.4 ;
    END
  END rd[8]
  PIN rd[90]
    DIRECTION OUTPUT ;
    USE SIGNAL ;
    PORT
      LAYER M3 ;
        RECT  30.96 86.256 30.978 86.4 ;
    END
  END rd[90]
  PIN rd[91]
    DIRECTION OUTPUT ;
    USE SIGNAL ;
    PORT
      LAYER M5 ;
        RECT  31.008 86.208 31.032 86.4 ;
    END
  END rd[91]
  PIN rd[92]
    DIRECTION OUTPUT ;
    USE SIGNAL ;
    PORT
      LAYER M3 ;
        RECT  31.104 86.256 31.122 86.4 ;
    END
  END rd[92]
  PIN rd[93]
    DIRECTION OUTPUT ;
    USE SIGNAL ;
    PORT
      LAYER M5 ;
        RECT  31.152 86.208 31.176 86.4 ;
    END
  END rd[93]
  PIN rd[94]
    DIRECTION OUTPUT ;
    USE SIGNAL ;
    PORT
      LAYER M3 ;
        RECT  31.248 86.256 31.266 86.4 ;
    END
  END rd[94]
  PIN rd[95]
    DIRECTION OUTPUT ;
    USE SIGNAL ;
    PORT
      LAYER M5 ;
        RECT  31.296 86.208 31.32 86.4 ;
    END
  END rd[95]
  PIN rd[96]
    DIRECTION OUTPUT ;
    USE SIGNAL ;
    PORT
      LAYER M3 ;
        RECT  31.392 86.256 31.41 86.4 ;
    END
  END rd[96]
  PIN rd[97]
    DIRECTION OUTPUT ;
    USE SIGNAL ;
    PORT
      LAYER M5 ;
        RECT  31.44 86.208 31.464 86.4 ;
    END
  END rd[97]
  PIN rd[98]
    DIRECTION OUTPUT ;
    USE SIGNAL ;
    PORT
      LAYER M3 ;
        RECT  31.536 86.256 31.554 86.4 ;
    END
  END rd[98]
  PIN rd[99]
    DIRECTION OUTPUT ;
    USE SIGNAL ;
    PORT
      LAYER M5 ;
        RECT  31.584 86.208 31.608 86.4 ;
    END
  END rd[99]
  PIN rd[9]
    DIRECTION OUTPUT ;
    USE SIGNAL ;
    PORT
      LAYER M5 ;
        RECT  25.104 86.208 25.128 86.4 ;
    END
  END rd[9]
  PIN rq0
    DIRECTION INPUT ;
    USE SIGNAL ;
    PORT
      LAYER M4 ;
        RECT  0 38.736 0.192 38.76 ;
    END
  END rq0
  PIN rq1
    DIRECTION INPUT ;
    USE SIGNAL ;
    PORT
      LAYER M4 ;
        RECT  0 38.592 0.192 38.616 ;
    END
  END rq1
  PIN rst_n
    DIRECTION INPUT ;
    USE SIGNAL ;
    PORT
      LAYER M4 ;
        RECT  0 51.024 0.192 51.048 ;
    END
    PORT
      LAYER M4 ;
        RECT  0.156 51.024 2.401 51.048 ;
    END
  END rst_n
  PIN wq0
    DIRECTION INPUT ;
    USE SIGNAL ;
    PORT
      LAYER M4 ;
        RECT  0 38.88 0.192 38.904 ;
    END
  END wq0
  PIN wq1
    DIRECTION INPUT ;
    USE SIGNAL ;
    PORT
      LAYER M4 ;
        RECT  0 40.176 0.192 40.2 ;
    END
  END wq1
  PIN wr0[0]
    DIRECTION INPUT ;
    USE SIGNAL ;
    PORT
      LAYER M4 ;
        RECT  0 39.024 0.192 39.048 ;
    END
  END wr0[0]
  PIN wr0[1]
    DIRECTION INPUT ;
    USE SIGNAL ;
    PORT
      LAYER M4 ;
        RECT  0 39.168 0.192 39.192 ;
    END
  END wr0[1]
  PIN wr0[2]
    DIRECTION INPUT ;
    USE SIGNAL ;
    PORT
      LAYER M4 ;
        RECT  0 39.456 0.192 39.48 ;
    END
  END wr0[2]
  PIN wr0[3]
    DIRECTION INPUT ;
    USE SIGNAL ;
    PORT
      LAYER M4 ;
        RECT  0 39.6 0.192 39.624 ;
    END
  END wr0[3]
  PIN wr0[4]
    DIRECTION INPUT ;
    USE SIGNAL ;
    PORT
      LAYER M4 ;
        RECT  0 39.744 0.192 39.768 ;
    END
  END wr0[4]
  PIN wr0[5]
    DIRECTION INPUT ;
    USE SIGNAL ;
    PORT
      LAYER M4 ;
        RECT  0 39.888 0.192 39.912 ;
    END
  END wr0[5]
  PIN wr0[6]
    DIRECTION INPUT ;
    USE SIGNAL ;
    PORT
      LAYER M4 ;
        RECT  0 40.032 0.192 40.056 ;
    END
  END wr0[6]
  PIN wr1[0]
    DIRECTION INPUT ;
    USE SIGNAL ;
    PORT
      LAYER M4 ;
        RECT  0 40.32 0.192 40.344 ;
    END
  END wr1[0]
  PIN wr1[1]
    DIRECTION INPUT ;
    USE SIGNAL ;
    PORT
      LAYER M4 ;
        RECT  0 40.464 0.192 40.488 ;
    END
  END wr1[1]
  PIN wr1[2]
    DIRECTION INPUT ;
    USE SIGNAL ;
    PORT
      LAYER M4 ;
        RECT  0 40.752 0.192 40.776 ;
    END
  END wr1[2]
  PIN wr1[3]
    DIRECTION INPUT ;
    USE SIGNAL ;
    PORT
      LAYER M4 ;
        RECT  0 40.896 0.192 40.92 ;
    END
  END wr1[3]
  PIN wr1[4]
    DIRECTION INPUT ;
    USE SIGNAL ;
    PORT
      LAYER M4 ;
        RECT  0 41.04 0.192 41.064 ;
    END
  END wr1[4]
  PIN wr1[5]
    DIRECTION INPUT ;
    USE SIGNAL ;
    PORT
      LAYER M4 ;
        RECT  0 41.184 0.192 41.208 ;
    END
  END wr1[5]
  PIN wr1[6]
    DIRECTION INPUT ;
    USE SIGNAL ;
    PORT
      LAYER M4 ;
        RECT  0 41.328 0.192 41.352 ;
    END
  END wr1[6]
  PIN VDD
    DIRECTION INOUT ;
    USE POWER ;
    PORT
      LAYER M5 ;
        RECT  137.592 2.151 137.712 84.249 ;
        RECT  132.192 2.151 132.312 84.249 ;
        RECT  126.792 2.151 126.912 84.249 ;
        RECT  121.392 2.151 121.512 84.249 ;
        RECT  115.992 2.151 116.112 84.249 ;
        RECT  110.592 2.151 110.712 84.249 ;
        RECT  105.192 2.151 105.312 84.249 ;
        RECT  99.792 2.151 99.912 84.249 ;
        RECT  94.392 2.151 94.512 84.249 ;
        RECT  88.992 2.151 89.112 84.249 ;
        RECT  83.592 2.151 83.712 84.249 ;
        RECT  78.192 2.151 78.312 84.249 ;
        RECT  72.792 2.151 72.912 84.249 ;
        RECT  67.392 2.151 67.512 84.249 ;
        RECT  61.992 2.151 62.112 84.249 ;
        RECT  56.592 2.151 56.712 84.249 ;
        RECT  51.192 2.151 51.312 84.249 ;
        RECT  45.792 2.151 45.912 84.249 ;
        RECT  40.392 2.151 40.512 84.249 ;
        RECT  34.992 2.151 35.112 84.249 ;
        RECT  29.592 2.151 29.712 84.249 ;
        RECT  24.192 2.151 24.312 84.249 ;
        RECT  18.792 2.151 18.912 84.249 ;
        RECT  13.392 2.151 13.512 84.249 ;
        RECT  7.992 2.151 8.112 84.249 ;
        RECT  2.592 2.151 2.712 84.249 ;
    END
  END VDD
  PIN VSS
    DIRECTION INOUT ;
    USE GROUND ;
    PORT
      LAYER M5 ;
        RECT  137.4 2.137 137.52 84.263 ;
        RECT  132 2.137 132.12 84.263 ;
        RECT  126.6 2.137 126.72 84.263 ;
        RECT  121.2 2.137 121.32 84.263 ;
        RECT  115.8 2.137 115.92 84.263 ;
        RECT  110.4 2.137 110.52 84.263 ;
        RECT  105 2.137 105.12 84.263 ;
        RECT  99.6 2.137 99.72 84.263 ;
        RECT  94.2 2.137 94.32 84.263 ;
        RECT  88.8 2.137 88.92 84.263 ;
        RECT  83.4 2.137 83.52 84.263 ;
        RECT  78 2.137 78.12 84.263 ;
        RECT  72.6 2.137 72.72 84.263 ;
        RECT  67.2 2.137 67.32 84.263 ;
        RECT  61.8 2.137 61.92 84.263 ;
        RECT  56.4 2.137 56.52 84.263 ;
        RECT  51 2.137 51.12 84.263 ;
        RECT  45.6 2.137 45.72 84.263 ;
        RECT  40.2 2.137 40.32 84.263 ;
        RECT  34.8 2.137 34.92 84.263 ;
        RECT  29.4 2.137 29.52 84.263 ;
        RECT  24 2.137 24.12 84.263 ;
        RECT  18.6 2.137 18.72 84.263 ;
        RECT  13.2 2.137 13.32 84.263 ;
        RECT  7.8 2.137 7.92 84.263 ;
        RECT  2.4 2.137 2.52 84.263 ;
    END
  END VSS
  # OT_OBS_CLOSED layer=M5 d_um=1.536 added=458
  OBS
    LAYER RVTN ;
     RECT  2.16 2.16 140.4 2.295 ;
     RECT  2.16 2.565 140.4 2.835 ;
     RECT  2.16 3.105 140.4 3.375 ;
     RECT  2.16 3.645 140.4 3.915 ;
     RECT  2.16 4.185 140.4 4.455 ;
     RECT  2.16 4.725 140.4 4.995 ;
     RECT  2.16 5.265 140.4 5.535 ;
     RECT  2.16 5.805 140.4 6.075 ;
     RECT  2.16 6.345 140.4 6.615 ;
     RECT  2.16 6.885 140.4 7.155 ;
     RECT  2.16 7.425 140.4 7.695 ;
     RECT  2.16 7.965 140.4 8.235 ;
     RECT  2.16 8.505 140.4 8.775 ;
     RECT  2.16 9.045 140.4 9.315 ;
     RECT  2.16 9.585 140.4 9.855 ;
     RECT  2.16 10.125 140.4 10.395 ;
     RECT  2.16 10.665 140.4 10.935 ;
     RECT  2.16 11.205 140.4 11.475 ;
     RECT  2.16 11.745 140.4 12.015 ;
     RECT  2.16 12.285 140.4 12.555 ;
     RECT  2.16 12.825 140.4 13.095 ;
     RECT  2.16 13.365 140.4 13.635 ;
     RECT  2.16 13.905 140.4 14.175 ;
     RECT  2.16 14.445 140.4 14.715 ;
     RECT  2.16 14.985 140.4 15.255 ;
     RECT  2.16 15.525 140.4 15.795 ;
     RECT  2.16 16.065 140.4 16.335 ;
     RECT  2.16 16.605 140.4 16.875 ;
     RECT  2.16 17.145 140.4 17.415 ;
     RECT  2.16 17.685 140.4 17.955 ;
     RECT  2.16 18.225 140.4 18.495 ;
     RECT  2.16 18.765 140.4 19.035 ;
     RECT  2.16 19.305 140.4 19.575 ;
     RECT  2.16 19.845 140.4 20.115 ;
     RECT  2.16 20.385 20.412 20.655 ;
     RECT  119.34 20.385 140.4 20.655 ;
     RECT  2.16 20.925 20.412 21.195 ;
     RECT  119.34 20.925 140.4 21.195 ;
     RECT  2.16 21.465 20.412 21.735 ;
     RECT  119.34 21.465 140.4 21.735 ;
     RECT  2.16 22.005 20.412 22.275 ;
     RECT  119.34 22.005 140.4 22.275 ;
     RECT  2.16 22.545 20.412 22.815 ;
     RECT  119.34 22.545 140.4 22.815 ;
     RECT  2.16 23.085 20.412 23.355 ;
     RECT  119.34 23.085 140.4 23.355 ;
     RECT  2.16 23.625 20.412 23.895 ;
     RECT  119.34 23.625 140.4 23.895 ;
     RECT  2.16 24.165 20.412 24.435 ;
     RECT  119.34 24.165 140.4 24.435 ;
     RECT  2.16 24.705 20.412 24.975 ;
     RECT  119.34 24.705 140.4 24.975 ;
     RECT  2.16 25.245 20.412 25.515 ;
     RECT  119.34 25.245 140.4 25.515 ;
     RECT  2.16 25.785 20.412 26.055 ;
     RECT  119.34 25.785 140.4 26.055 ;
     RECT  2.16 26.325 20.412 26.595 ;
     RECT  119.34 26.325 140.4 26.595 ;
     RECT  2.16 26.865 20.412 27.135 ;
     RECT  119.34 26.865 140.4 27.135 ;
     RECT  2.16 27.405 20.412 27.675 ;
     RECT  119.34 27.405 140.4 27.675 ;
     RECT  2.16 27.945 20.412 28.215 ;
     RECT  119.34 27.945 140.4 28.215 ;
     RECT  2.16 28.485 20.412 28.755 ;
     RECT  119.34 28.485 140.4 28.755 ;
     RECT  2.16 29.025 20.412 29.295 ;
     RECT  119.34 29.025 140.4 29.295 ;
     RECT  2.16 29.565 20.412 29.835 ;
     RECT  119.34 29.565 140.4 29.835 ;
     RECT  2.16 30.105 20.412 30.375 ;
     RECT  119.34 30.105 140.4 30.375 ;
     RECT  2.16 30.645 20.412 30.915 ;
     RECT  119.34 30.645 140.4 30.915 ;
     RECT  2.16 31.185 20.412 31.455 ;
     RECT  119.34 31.185 140.4 31.455 ;
     RECT  2.16 31.725 20.412 31.995 ;
     RECT  119.34 31.725 140.4 31.995 ;
     RECT  2.16 32.265 20.412 32.535 ;
     RECT  119.34 32.265 140.4 32.535 ;
     RECT  2.16 32.805 20.412 33.075 ;
     RECT  119.34 32.805 140.4 33.075 ;
     RECT  2.16 33.345 20.412 33.615 ;
     RECT  119.34 33.345 140.4 33.615 ;
     RECT  2.16 33.885 20.412 34.155 ;
     RECT  119.34 33.885 140.4 34.155 ;
     RECT  2.16 34.425 20.412 34.695 ;
     RECT  119.34 34.425 140.4 34.695 ;
     RECT  2.16 34.965 20.412 35.235 ;
     RECT  119.34 34.965 140.4 35.235 ;
     RECT  2.16 35.505 20.412 35.775 ;
     RECT  119.34 35.505 140.4 35.775 ;
     RECT  2.16 36.045 20.412 36.315 ;
     RECT  119.34 36.045 140.4 36.315 ;
     RECT  2.16 36.585 20.412 36.855 ;
     RECT  119.34 36.585 140.4 36.855 ;
     RECT  2.16 37.125 20.412 37.395 ;
     RECT  119.34 37.125 140.4 37.395 ;
     RECT  2.16 37.665 20.412 37.935 ;
     RECT  119.34 37.665 140.4 37.935 ;
     RECT  2.16 38.205 20.412 38.475 ;
     RECT  119.34 38.205 140.4 38.475 ;
     RECT  2.16 38.745 20.412 39.015 ;
     RECT  119.34 38.745 140.4 39.015 ;
     RECT  2.16 39.285 20.412 39.555 ;
     RECT  119.34 39.285 140.4 39.555 ;
     RECT  2.16 39.825 20.412 40.095 ;
     RECT  119.34 39.825 140.4 40.095 ;
     RECT  2.16 40.365 20.412 40.635 ;
     RECT  119.34 40.365 140.4 40.635 ;
     RECT  2.16 40.905 20.412 41.175 ;
     RECT  119.34 40.905 140.4 41.175 ;
     RECT  2.16 41.445 20.412 41.715 ;
     RECT  119.34 41.445 140.4 41.715 ;
     RECT  2.16 41.985 20.412 42.255 ;
     RECT  119.34 41.985 140.4 42.255 ;
     RECT  2.16 42.525 20.412 42.795 ;
     RECT  119.34 42.525 140.4 42.795 ;
     RECT  2.16 43.065 20.412 43.335 ;
     RECT  119.34 43.065 140.4 43.335 ;
     RECT  2.16 43.605 20.412 43.875 ;
     RECT  119.34 43.605 140.4 43.875 ;
     RECT  2.16 44.145 20.412 44.415 ;
     RECT  119.34 44.145 140.4 44.415 ;
     RECT  2.16 44.685 20.412 44.955 ;
     RECT  119.34 44.685 140.4 44.955 ;
     RECT  2.16 45.225 20.412 45.495 ;
     RECT  119.34 45.225 140.4 45.495 ;
     RECT  2.16 45.765 20.412 46.035 ;
     RECT  119.34 45.765 140.4 46.035 ;
     RECT  2.16 46.305 20.412 46.575 ;
     RECT  119.34 46.305 140.4 46.575 ;
     RECT  2.16 46.845 20.412 47.115 ;
     RECT  119.34 46.845 140.4 47.115 ;
     RECT  2.16 47.385 20.412 47.655 ;
     RECT  119.34 47.385 140.4 47.655 ;
     RECT  2.16 47.925 20.412 48.195 ;
     RECT  119.34 47.925 140.4 48.195 ;
     RECT  2.16 48.465 20.412 48.735 ;
     RECT  119.34 48.465 140.4 48.735 ;
     RECT  2.16 49.005 20.412 49.275 ;
     RECT  119.34 49.005 140.4 49.275 ;
     RECT  2.16 49.545 20.412 49.815 ;
     RECT  119.34 49.545 140.4 49.815 ;
     RECT  2.16 50.085 20.412 50.355 ;
     RECT  119.34 50.085 140.4 50.355 ;
     RECT  2.16 50.625 20.412 50.895 ;
     RECT  119.34 50.625 140.4 50.895 ;
     RECT  2.16 51.165 20.412 51.435 ;
     RECT  119.34 51.165 140.4 51.435 ;
     RECT  2.16 51.705 20.412 51.975 ;
     RECT  119.34 51.705 140.4 51.975 ;
     RECT  2.16 52.245 20.412 52.515 ;
     RECT  119.34 52.245 140.4 52.515 ;
     RECT  2.16 52.785 20.412 53.055 ;
     RECT  119.34 52.785 140.4 53.055 ;
     RECT  2.16 53.325 20.412 53.595 ;
     RECT  119.34 53.325 140.4 53.595 ;
     RECT  2.16 53.865 20.412 54.135 ;
     RECT  119.34 53.865 140.4 54.135 ;
     RECT  2.16 54.405 20.412 54.675 ;
     RECT  119.34 54.405 140.4 54.675 ;
     RECT  2.16 54.945 20.412 55.215 ;
     RECT  119.34 54.945 140.4 55.215 ;
     RECT  2.16 55.485 20.412 55.755 ;
     RECT  119.34 55.485 140.4 55.755 ;
     RECT  2.16 56.025 20.412 56.295 ;
     RECT  119.34 56.025 140.4 56.295 ;
     RECT  2.16 56.565 20.412 56.835 ;
     RECT  119.34 56.565 140.4 56.835 ;
     RECT  2.16 57.105 20.412 57.375 ;
     RECT  119.34 57.105 140.4 57.375 ;
     RECT  2.16 57.645 20.412 57.915 ;
     RECT  119.34 57.645 140.4 57.915 ;
     RECT  2.16 58.185 20.412 58.455 ;
     RECT  119.34 58.185 140.4 58.455 ;
     RECT  2.16 58.725 20.412 58.995 ;
     RECT  119.34 58.725 140.4 58.995 ;
     RECT  2.16 59.265 20.412 59.535 ;
     RECT  119.34 59.265 140.4 59.535 ;
     RECT  2.16 59.805 20.412 60.075 ;
     RECT  119.34 59.805 140.4 60.075 ;
     RECT  2.16 60.345 20.412 60.615 ;
     RECT  119.34 60.345 140.4 60.615 ;
     RECT  2.16 60.885 20.412 61.155 ;
     RECT  119.34 60.885 140.4 61.155 ;
     RECT  2.16 61.425 20.412 61.695 ;
     RECT  119.34 61.425 140.4 61.695 ;
     RECT  2.16 61.965 20.412 62.235 ;
     RECT  119.34 61.965 140.4 62.235 ;
     RECT  2.16 62.505 20.412 62.775 ;
     RECT  119.34 62.505 140.4 62.775 ;
     RECT  2.16 63.045 20.412 63.315 ;
     RECT  119.34 63.045 140.4 63.315 ;
     RECT  2.16 63.585 20.412 63.855 ;
     RECT  119.34 63.585 140.4 63.855 ;
     RECT  2.16 64.125 20.412 64.395 ;
     RECT  119.34 64.125 140.4 64.395 ;
     RECT  2.16 64.665 20.412 64.935 ;
     RECT  119.34 64.665 140.4 64.935 ;
     RECT  2.16 65.205 20.412 65.475 ;
     RECT  119.34 65.205 140.4 65.475 ;
     RECT  2.16 65.745 140.4 66.015 ;
     RECT  2.16 66.285 140.4 66.555 ;
     RECT  2.16 66.825 140.4 67.095 ;
     RECT  2.16 67.365 140.4 67.635 ;
     RECT  2.16 67.905 140.4 68.175 ;
     RECT  2.16 68.445 140.4 68.715 ;
     RECT  2.16 68.985 140.4 69.255 ;
     RECT  2.16 69.525 140.4 69.795 ;
     RECT  2.16 70.065 140.4 70.335 ;
     RECT  2.16 70.605 140.4 70.875 ;
     RECT  2.16 71.145 140.4 71.415 ;
     RECT  2.16 71.685 140.4 71.955 ;
     RECT  2.16 72.225 140.4 72.495 ;
     RECT  2.16 72.765 140.4 73.035 ;
     RECT  2.16 73.305 140.4 73.575 ;
     RECT  2.16 73.845 140.4 74.115 ;
     RECT  2.16 74.385 140.4 74.655 ;
     RECT  2.16 74.925 140.4 75.195 ;
     RECT  2.16 75.465 140.4 75.735 ;
     RECT  2.16 76.005 140.4 76.275 ;
     RECT  2.16 76.545 140.4 76.815 ;
     RECT  2.16 77.085 140.4 77.355 ;
     RECT  2.16 77.625 140.4 77.895 ;
     RECT  2.16 78.165 140.4 78.435 ;
     RECT  2.16 78.705 140.4 78.975 ;
     RECT  2.16 79.245 140.4 79.515 ;
     RECT  2.16 79.785 140.4 80.055 ;
     RECT  2.16 80.325 140.4 80.595 ;
     RECT  2.16 80.865 140.4 81.135 ;
     RECT  2.16 81.405 140.4 81.675 ;
     RECT  2.16 81.945 140.4 82.215 ;
     RECT  2.16 82.485 140.4 82.755 ;
     RECT  2.16 83.025 140.4 83.295 ;
     RECT  2.16 83.565 140.4 83.835 ;
     RECT  2.16 84.105 140.4 84.24 ;
    LAYER RVTP ;
     RECT  2.16 2.295 140.4 2.565 ;
     RECT  2.16 2.835 140.4 3.105 ;
     RECT  2.16 3.375 140.4 3.645 ;
     RECT  2.16 3.915 140.4 4.185 ;
     RECT  2.16 4.455 140.4 4.725 ;
     RECT  2.16 4.995 140.4 5.265 ;
     RECT  2.16 5.535 140.4 5.805 ;
     RECT  2.16 6.075 140.4 6.345 ;
     RECT  2.16 6.615 140.4 6.885 ;
     RECT  2.16 7.155 140.4 7.425 ;
     RECT  2.16 7.695 140.4 7.965 ;
     RECT  2.16 8.235 140.4 8.505 ;
     RECT  2.16 8.775 140.4 9.045 ;
     RECT  2.16 9.315 140.4 9.585 ;
     RECT  2.16 9.855 140.4 10.125 ;
     RECT  2.16 10.395 140.4 10.665 ;
     RECT  2.16 10.935 140.4 11.205 ;
     RECT  2.16 11.475 140.4 11.745 ;
     RECT  2.16 12.015 140.4 12.285 ;
     RECT  2.16 12.555 140.4 12.825 ;
     RECT  2.16 13.095 140.4 13.365 ;
     RECT  2.16 13.635 140.4 13.905 ;
     RECT  2.16 14.175 140.4 14.445 ;
     RECT  2.16 14.715 140.4 14.985 ;
     RECT  2.16 15.255 140.4 15.525 ;
     RECT  2.16 15.795 140.4 16.065 ;
     RECT  2.16 16.335 140.4 16.605 ;
     RECT  2.16 16.875 140.4 17.145 ;
     RECT  2.16 17.415 140.4 17.685 ;
     RECT  2.16 17.955 140.4 18.225 ;
     RECT  2.16 18.495 140.4 18.765 ;
     RECT  2.16 19.035 140.4 19.305 ;
     RECT  2.16 19.575 140.4 19.845 ;
     RECT  2.16 20.115 140.4 20.25 ;
     RECT  2.16 20.25 20.412 20.385 ;
     RECT  119.34 20.25 140.4 20.385 ;
     RECT  2.16 20.655 20.412 20.925 ;
     RECT  119.34 20.655 140.4 20.925 ;
     RECT  2.16 21.195 20.412 21.465 ;
     RECT  119.34 21.195 140.4 21.465 ;
     RECT  2.16 21.735 20.412 22.005 ;
     RECT  119.34 21.735 140.4 22.005 ;
     RECT  2.16 22.275 20.412 22.545 ;
     RECT  119.34 22.275 140.4 22.545 ;
     RECT  2.16 22.815 20.412 23.085 ;
     RECT  119.34 22.815 140.4 23.085 ;
     RECT  2.16 23.355 20.412 23.625 ;
     RECT  119.34 23.355 140.4 23.625 ;
     RECT  2.16 23.895 20.412 24.165 ;
     RECT  119.34 23.895 140.4 24.165 ;
     RECT  2.16 24.435 20.412 24.705 ;
     RECT  119.34 24.435 140.4 24.705 ;
     RECT  2.16 24.975 20.412 25.245 ;
     RECT  119.34 24.975 140.4 25.245 ;
     RECT  2.16 25.515 20.412 25.785 ;
     RECT  119.34 25.515 140.4 25.785 ;
     RECT  2.16 26.055 20.412 26.325 ;
     RECT  119.34 26.055 140.4 26.325 ;
     RECT  2.16 26.595 20.412 26.865 ;
     RECT  119.34 26.595 140.4 26.865 ;
     RECT  2.16 27.135 20.412 27.405 ;
     RECT  119.34 27.135 140.4 27.405 ;
     RECT  2.16 27.675 20.412 27.945 ;
     RECT  119.34 27.675 140.4 27.945 ;
     RECT  2.16 28.215 20.412 28.485 ;
     RECT  119.34 28.215 140.4 28.485 ;
     RECT  2.16 28.755 20.412 29.025 ;
     RECT  119.34 28.755 140.4 29.025 ;
     RECT  2.16 29.295 20.412 29.565 ;
     RECT  119.34 29.295 140.4 29.565 ;
     RECT  2.16 29.835 20.412 30.105 ;
     RECT  119.34 29.835 140.4 30.105 ;
     RECT  2.16 30.375 20.412 30.645 ;
     RECT  119.34 30.375 140.4 30.645 ;
     RECT  2.16 30.915 20.412 31.185 ;
     RECT  119.34 30.915 140.4 31.185 ;
     RECT  2.16 31.455 20.412 31.725 ;
     RECT  119.34 31.455 140.4 31.725 ;
     RECT  2.16 31.995 20.412 32.265 ;
     RECT  119.34 31.995 140.4 32.265 ;
     RECT  2.16 32.535 20.412 32.805 ;
     RECT  119.34 32.535 140.4 32.805 ;
     RECT  2.16 33.075 20.412 33.345 ;
     RECT  119.34 33.075 140.4 33.345 ;
     RECT  2.16 33.615 20.412 33.885 ;
     RECT  119.34 33.615 140.4 33.885 ;
     RECT  2.16 34.155 20.412 34.425 ;
     RECT  119.34 34.155 140.4 34.425 ;
     RECT  2.16 34.695 20.412 34.965 ;
     RECT  119.34 34.695 140.4 34.965 ;
     RECT  2.16 35.235 20.412 35.505 ;
     RECT  119.34 35.235 140.4 35.505 ;
     RECT  2.16 35.775 20.412 36.045 ;
     RECT  119.34 35.775 140.4 36.045 ;
     RECT  2.16 36.315 20.412 36.585 ;
     RECT  119.34 36.315 140.4 36.585 ;
     RECT  2.16 36.855 20.412 37.125 ;
     RECT  119.34 36.855 140.4 37.125 ;
     RECT  2.16 37.395 20.412 37.665 ;
     RECT  119.34 37.395 140.4 37.665 ;
     RECT  2.16 37.935 20.412 38.205 ;
     RECT  119.34 37.935 140.4 38.205 ;
     RECT  2.16 38.475 20.412 38.745 ;
     RECT  119.34 38.475 140.4 38.745 ;
     RECT  2.16 39.015 20.412 39.285 ;
     RECT  119.34 39.015 140.4 39.285 ;
     RECT  2.16 39.555 20.412 39.825 ;
     RECT  119.34 39.555 140.4 39.825 ;
     RECT  2.16 40.095 20.412 40.365 ;
     RECT  119.34 40.095 140.4 40.365 ;
     RECT  2.16 40.635 20.412 40.905 ;
     RECT  119.34 40.635 140.4 40.905 ;
     RECT  2.16 41.175 20.412 41.445 ;
     RECT  119.34 41.175 140.4 41.445 ;
     RECT  2.16 41.715 20.412 41.985 ;
     RECT  119.34 41.715 140.4 41.985 ;
     RECT  2.16 42.255 20.412 42.525 ;
     RECT  119.34 42.255 140.4 42.525 ;
     RECT  2.16 42.795 20.412 43.065 ;
     RECT  119.34 42.795 140.4 43.065 ;
     RECT  2.16 43.335 20.412 43.605 ;
     RECT  119.34 43.335 140.4 43.605 ;
     RECT  2.16 43.875 20.412 44.145 ;
     RECT  119.34 43.875 140.4 44.145 ;
     RECT  2.16 44.415 20.412 44.685 ;
     RECT  119.34 44.415 140.4 44.685 ;
     RECT  2.16 44.955 20.412 45.225 ;
     RECT  119.34 44.955 140.4 45.225 ;
     RECT  2.16 45.495 20.412 45.765 ;
     RECT  119.34 45.495 140.4 45.765 ;
     RECT  2.16 46.035 20.412 46.305 ;
     RECT  119.34 46.035 140.4 46.305 ;
     RECT  2.16 46.575 20.412 46.845 ;
     RECT  119.34 46.575 140.4 46.845 ;
     RECT  2.16 47.115 20.412 47.385 ;
     RECT  119.34 47.115 140.4 47.385 ;
     RECT  2.16 47.655 20.412 47.925 ;
     RECT  119.34 47.655 140.4 47.925 ;
     RECT  2.16 48.195 20.412 48.465 ;
     RECT  119.34 48.195 140.4 48.465 ;
     RECT  2.16 48.735 20.412 49.005 ;
     RECT  119.34 48.735 140.4 49.005 ;
     RECT  2.16 49.275 20.412 49.545 ;
     RECT  119.34 49.275 140.4 49.545 ;
     RECT  2.16 49.815 20.412 50.085 ;
     RECT  119.34 49.815 140.4 50.085 ;
     RECT  2.16 50.355 20.412 50.625 ;
     RECT  119.34 50.355 140.4 50.625 ;
     RECT  2.16 50.895 20.412 51.165 ;
     RECT  119.34 50.895 140.4 51.165 ;
     RECT  2.16 51.435 20.412 51.705 ;
     RECT  119.34 51.435 140.4 51.705 ;
     RECT  2.16 51.975 20.412 52.245 ;
     RECT  119.34 51.975 140.4 52.245 ;
     RECT  2.16 52.515 20.412 52.785 ;
     RECT  119.34 52.515 140.4 52.785 ;
     RECT  2.16 53.055 20.412 53.325 ;
     RECT  119.34 53.055 140.4 53.325 ;
     RECT  2.16 53.595 20.412 53.865 ;
     RECT  119.34 53.595 140.4 53.865 ;
     RECT  2.16 54.135 20.412 54.405 ;
     RECT  119.34 54.135 140.4 54.405 ;
     RECT  2.16 54.675 20.412 54.945 ;
     RECT  119.34 54.675 140.4 54.945 ;
     RECT  2.16 55.215 20.412 55.485 ;
     RECT  119.34 55.215 140.4 55.485 ;
     RECT  2.16 55.755 20.412 56.025 ;
     RECT  119.34 55.755 140.4 56.025 ;
     RECT  2.16 56.295 20.412 56.565 ;
     RECT  119.34 56.295 140.4 56.565 ;
     RECT  2.16 56.835 20.412 57.105 ;
     RECT  119.34 56.835 140.4 57.105 ;
     RECT  2.16 57.375 20.412 57.645 ;
     RECT  119.34 57.375 140.4 57.645 ;
     RECT  2.16 57.915 20.412 58.185 ;
     RECT  119.34 57.915 140.4 58.185 ;
     RECT  2.16 58.455 20.412 58.725 ;
     RECT  119.34 58.455 140.4 58.725 ;
     RECT  2.16 58.995 20.412 59.265 ;
     RECT  119.34 58.995 140.4 59.265 ;
     RECT  2.16 59.535 20.412 59.805 ;
     RECT  119.34 59.535 140.4 59.805 ;
     RECT  2.16 60.075 20.412 60.345 ;
     RECT  119.34 60.075 140.4 60.345 ;
     RECT  2.16 60.615 20.412 60.885 ;
     RECT  119.34 60.615 140.4 60.885 ;
     RECT  2.16 61.155 20.412 61.425 ;
     RECT  119.34 61.155 140.4 61.425 ;
     RECT  2.16 61.695 20.412 61.965 ;
     RECT  119.34 61.695 140.4 61.965 ;
     RECT  2.16 62.235 20.412 62.505 ;
     RECT  119.34 62.235 140.4 62.505 ;
     RECT  2.16 62.775 20.412 63.045 ;
     RECT  119.34 62.775 140.4 63.045 ;
     RECT  2.16 63.315 20.412 63.585 ;
     RECT  119.34 63.315 140.4 63.585 ;
     RECT  2.16 63.855 20.412 64.125 ;
     RECT  119.34 63.855 140.4 64.125 ;
     RECT  2.16 64.395 20.412 64.665 ;
     RECT  119.34 64.395 140.4 64.665 ;
     RECT  2.16 64.935 20.412 65.205 ;
     RECT  119.34 64.935 140.4 65.205 ;
     RECT  2.16 65.475 20.412 65.61 ;
     RECT  119.34 65.475 140.4 65.61 ;
     RECT  2.16 65.61 140.4 65.745 ;
     RECT  2.16 66.015 140.4 66.285 ;
     RECT  2.16 66.555 140.4 66.825 ;
     RECT  2.16 67.095 140.4 67.365 ;
     RECT  2.16 67.635 140.4 67.905 ;
     RECT  2.16 68.175 140.4 68.445 ;
     RECT  2.16 68.715 140.4 68.985 ;
     RECT  2.16 69.255 140.4 69.525 ;
     RECT  2.16 69.795 140.4 70.065 ;
     RECT  2.16 70.335 140.4 70.605 ;
     RECT  2.16 70.875 140.4 71.145 ;
     RECT  2.16 71.415 140.4 71.685 ;
     RECT  2.16 71.955 140.4 72.225 ;
     RECT  2.16 72.495 140.4 72.765 ;
     RECT  2.16 73.035 140.4 73.305 ;
     RECT  2.16 73.575 140.4 73.845 ;
     RECT  2.16 74.115 140.4 74.385 ;
     RECT  2.16 74.655 140.4 74.925 ;
     RECT  2.16 75.195 140.4 75.465 ;
     RECT  2.16 75.735 140.4 76.005 ;
     RECT  2.16 76.275 140.4 76.545 ;
     RECT  2.16 76.815 140.4 77.085 ;
     RECT  2.16 77.355 140.4 77.625 ;
     RECT  2.16 77.895 140.4 78.165 ;
     RECT  2.16 78.435 140.4 78.705 ;
     RECT  2.16 78.975 140.4 79.245 ;
     RECT  2.16 79.515 140.4 79.785 ;
     RECT  2.16 80.055 140.4 80.325 ;
     RECT  2.16 80.595 140.4 80.865 ;
     RECT  2.16 81.135 140.4 81.405 ;
     RECT  2.16 81.675 140.4 81.945 ;
     RECT  2.16 82.215 140.4 82.485 ;
     RECT  2.16 82.755 140.4 83.025 ;
     RECT  2.16 83.295 140.4 83.565 ;
     RECT  2.16 83.835 140.4 84.105 ;
    LAYER M1 ;
     RECT  2.16 2.151 140.4 20.259 ;
     RECT  22.464 22.464 117.288 63.528 ;
     RECT  2.16 20.259 20.412 65.601 ;
     RECT  119.34 20.259 140.4 65.601 ;
     RECT  2.16 65.601 140.4 84.249 ;
    LAYER M2 ;
     RECT  0.031 45.432 0.103 45.45 ;
     RECT  0.103 40.104 0.211 40.122 ;
     RECT  0.031 41.688 0.211 41.706 ;
     RECT  0.103 44.892 0.211 45.45 ;
     RECT  0.211 36.288 0.239 40.122 ;
     RECT  0.211 41.688 0.247 42.21 ;
     RECT  0.211 44.73 0.247 45.45 ;
     RECT  0.211 35.01 0.427 35.46 ;
     RECT  0.239 36.288 0.427 40.05 ;
     RECT  0.859 64.566 0.895 64.584 ;
     RECT  0.427 35.01 1.183 40.05 ;
     RECT  0.247 40.914 1.183 42.21 ;
     RECT  0.427 51.372 1.435 51.39 ;
     RECT  0.211 33.426 1.543 34.146 ;
     RECT  0.247 44.694 1.615 45.45 ;
     RECT  1.543 32.886 1.723 34.146 ;
     RECT  1.183 35.01 1.723 42.21 ;
     RECT  1.723 32.886 2.119 42.21 ;
     RECT  1.615 43.956 2.119 45.45 ;
     RECT  0.571 31.266 2.155 31.284 ;
     RECT  1.363 17.496 2.16 17.514 ;
     RECT  1.579 20.97 2.16 20.988 ;
     RECT  0.535 23.13 2.16 23.148 ;
     RECT  1.687 27.486 2.16 27.504 ;
     RECT  0.499 28.53 2.16 28.548 ;
     RECT  2.155 31.266 2.16 31.554 ;
     RECT  2.119 32.472 2.16 42.21 ;
     RECT  2.119 43.578 2.16 45.45 ;
     RECT  1.003 46.926 2.16 46.944 ;
     RECT  1.435 51.372 2.16 51.894 ;
     RECT  1.543 55.026 2.16 55.044 ;
     RECT  1.111 57.276 2.16 57.294 ;
     RECT  2.155 58.464 2.16 58.482 ;
     RECT  1.615 59.274 2.16 59.292 ;
     RECT  0.463 60.426 2.16 60.444 ;
     RECT  0.931 63.594 2.16 63.612 ;
     RECT  0.895 64.566 2.16 64.728 ;
     RECT  0.751 66.906 2.16 66.924 ;
     RECT  1.039 68.148 2.16 68.166 ;
     RECT  1.075 69.066 2.16 69.084 ;
     RECT  2.16 2.151 5.863 84.249 ;
     RECT  5.863 2.151 10.579 84.636 ;
     RECT  10.579 2.151 11.767 84.672 ;
     RECT  11.767 2.151 17.779 85.212 ;
     RECT  17.779 2.151 20.299 85.284 ;
     RECT  20.299 2.151 20.412 85.41 ;
     RECT  20.412 29.196 20.435 33.102 ;
     RECT  20.412 36.936 20.471 53.244 ;
     RECT  20.412 57.69 20.471 59.094 ;
     RECT  20.412 54.378 20.507 56.934 ;
     RECT  20.471 36.936 20.543 42.786 ;
     RECT  20.471 43.578 20.543 53.244 ;
     RECT  20.507 54.378 20.615 56.556 ;
     RECT  20.615 54.378 20.651 55.314 ;
     RECT  20.471 57.69 20.651 58.824 ;
     RECT  20.435 29.646 20.723 33.102 ;
     RECT  20.543 43.578 20.723 47.988 ;
     RECT  20.543 49.014 20.723 53.244 ;
     RECT  20.723 43.578 20.759 47.88 ;
     RECT  20.412 60.39 20.759 85.41 ;
     RECT  20.723 29.646 20.831 32.904 ;
     RECT  20.651 54.378 20.831 54.396 ;
     RECT  20.651 55.296 20.831 55.314 ;
     RECT  20.412 24.066 20.867 25.812 ;
     RECT  20.412 2.151 20.875 23.184 ;
     RECT  20.831 31.428 20.939 32.904 ;
     RECT  20.759 43.848 20.939 47.88 ;
     RECT  20.543 36.936 20.975 42.174 ;
     RECT  20.723 49.014 20.975 53.046 ;
     RECT  20.867 25.254 21.011 25.812 ;
     RECT  20.412 26.568 21.119 28.044 ;
     RECT  20.975 37.566 21.119 42.174 ;
     RECT  20.975 49.014 21.119 52.884 ;
     RECT  20.939 44.928 21.191 47.88 ;
     RECT  21.119 37.566 21.227 40.05 ;
     RECT  20.412 33.894 21.263 34.344 ;
     RECT  21.119 40.806 21.271 42.174 ;
     RECT  21.119 51.174 21.299 52.884 ;
     RECT  21.119 27.756 21.335 28.044 ;
     RECT  20.939 43.848 21.335 43.866 ;
     RECT  21.011 25.254 21.371 25.308 ;
     RECT  21.119 26.568 21.379 26.892 ;
     RECT  21.263 34.326 21.379 34.344 ;
     RECT  20.412 35.316 21.379 36.144 ;
     RECT  20.867 24.066 21.407 24.192 ;
     RECT  20.651 57.852 21.407 58.824 ;
     RECT  21.407 24.174 21.479 24.192 ;
     RECT  21.379 26.064 21.479 26.892 ;
     RECT  20.759 60.966 21.479 85.41 ;
     RECT  21.271 40.806 21.487 42.624 ;
     RECT  21.479 26.064 21.515 26.154 ;
     RECT  20.939 31.428 21.515 32.364 ;
     RECT  21.191 44.928 21.515 46.134 ;
     RECT  21.379 34.326 21.523 36.144 ;
     RECT  21.515 31.536 21.551 32.364 ;
     RECT  21.119 49.014 21.551 50.184 ;
     RECT  20.615 56.421 21.551 56.439 ;
     RECT  21.271 59.778 21.551 59.796 ;
     RECT  21.515 26.136 21.587 26.154 ;
     RECT  21.191 47.124 21.587 47.88 ;
     RECT  21.371 25.254 21.623 25.272 ;
     RECT  20.831 29.646 21.623 30.474 ;
     RECT  21.487 40.806 21.623 42.714 ;
     RECT  21.515 45 21.623 46.134 ;
     RECT  21.623 29.646 21.659 30.438 ;
     RECT  21.623 45.162 21.659 46.134 ;
     RECT  21.479 62.136 21.695 85.41 ;
     RECT  21.523 34.326 21.731 36.459 ;
     RECT  21.407 57.852 21.731 57.87 ;
     RECT  20.875 1.881 21.739 23.184 ;
     RECT  21.739 1.881 21.775 23.274 ;
     RECT  21.227 37.566 21.955 39.204 ;
     RECT  21.335 27.756 22.027 27.774 ;
     RECT  21.775 25.056 22.099 25.074 ;
     RECT  22.099 24.984 22.243 25.074 ;
     RECT  21.407 58.806 22.279 58.824 ;
     RECT  21.775 1.692 22.464 23.274 ;
     RECT  22.243 24.714 22.464 25.074 ;
     RECT  22.027 27.144 22.464 27.774 ;
     RECT  21.659 29.808 22.464 30.438 ;
     RECT  21.551 31.698 22.464 32.364 ;
     RECT  21.731 34.326 22.464 36.144 ;
     RECT  21.955 37.062 22.464 39.204 ;
     RECT  21.227 40.032 22.464 40.05 ;
     RECT  21.623 40.806 22.464 42.174 ;
     RECT  22.279 44.352 22.464 44.37 ;
     RECT  21.659 45.198 22.464 46.134 ;
     RECT  21.587 47.862 22.464 47.88 ;
     RECT  21.551 49.014 22.464 49.806 ;
     RECT  21.299 51.174 22.464 51.624 ;
     RECT  21.299 52.488 22.464 52.884 ;
     RECT  22.171 55.764 22.464 55.782 ;
     RECT  22.279 58.536 22.464 58.824 ;
     RECT  21.479 60.966 22.464 61.074 ;
     RECT  21.695 62.136 22.464 62.154 ;
     RECT  21.695 63.252 22.464 85.41 ;
     RECT  23.467 0.882 24.619 0.9 ;
     RECT  24.619 0.144 25.015 0.9 ;
     RECT  25.015 0.036 25.043 0.9 ;
     RECT  22.464 1.692 25.663 85.41 ;
     RECT  25.663 1.656 26.231 85.41 ;
     RECT  25.043 0.036 26.275 0.054 ;
     RECT  25.043 0.882 26.275 0.9 ;
     RECT  26.275 0.036 26.519 0.9 ;
     RECT  26.519 0.036 27.427 0.054 ;
     RECT  26.519 0.882 27.427 0.9 ;
     RECT  27.427 0.036 27.499 0.9 ;
     RECT  26.231 1.656 27.499 85.374 ;
     RECT  27.499 0.036 28.319 85.374 ;
     RECT  28.363 86.238 28.399 86.256 ;
     RECT  28.399 86.238 28.499 86.328 ;
     RECT  28.319 0.882 29.155 85.374 ;
     RECT  28.319 0.036 29.191 0.054 ;
     RECT  29.155 0.882 29.191 85.41 ;
     RECT  29.191 0.036 29.543 85.41 ;
     RECT  29.543 0.036 30.703 0.054 ;
     RECT  29.543 0.882 30.703 85.41 ;
     RECT  31.207 86.31 31.243 86.328 ;
     RECT  31.243 86.238 32.207 86.328 ;
     RECT  30.703 0.036 34.439 85.41 ;
     RECT  34.439 0.036 34.619 84.294 ;
     RECT  34.619 0.216 34.799 84.294 ;
     RECT  34.799 0.306 35.015 84.294 ;
     RECT  34.439 85.194 35.015 85.41 ;
     RECT  35.015 0.306 35.707 84.249 ;
     RECT  35.707 0.144 35.887 84.249 ;
     RECT  35.887 0.036 36.823 84.249 ;
     RECT  35.015 85.194 36.887 85.329 ;
     RECT  36.823 0.036 38.047 84.402 ;
     RECT  36.887 85.194 38.047 85.284 ;
     RECT  38.047 0.036 38.471 85.284 ;
     RECT  38.471 0.036 38.507 84.402 ;
     RECT  38.507 64.98 39.047 84.402 ;
     RECT  38.507 0.036 39.407 64.116 ;
     RECT  38.471 85.194 39.479 85.284 ;
     RECT  39.479 85.194 39.623 85.212 ;
     RECT  39.047 64.98 40.135 84.249 ;
     RECT  39.407 0.108 40.199 64.116 ;
     RECT  40.135 64.98 40.343 84.33 ;
     RECT  40.199 0.108 41.099 63.528 ;
     RECT  41.099 0.144 42.151 63.528 ;
     RECT  42.151 0.108 42.583 63.528 ;
     RECT  42.583 0.072 42.691 63.528 ;
     RECT  40.343 64.98 42.763 84.249 ;
     RECT  42.763 64.98 42.863 84.294 ;
     RECT  42.863 64.98 44.483 84.249 ;
     RECT  44.483 65.601 46.975 84.249 ;
     RECT  46.975 65.601 47.975 84.294 ;
     RECT  42.691 0.036 64.571 63.528 ;
     RECT  64.571 0.531 65.003 63.528 ;
     RECT  65.003 1.422 65.039 63.528 ;
     RECT  65.003 0.531 66.191 0.549 ;
     RECT  66.595 0.144 67.271 0.162 ;
     RECT  65.039 1.692 68.971 63.528 ;
     RECT  70.843 0.144 70.943 0.162 ;
     RECT  68.971 1.611 71.303 63.528 ;
     RECT  71.303 1.692 90.635 63.528 ;
     RECT  90.635 1.692 94.559 21.114 ;
     RECT  94.559 2.151 94.999 21.114 ;
     RECT  90.635 21.978 94.999 63.528 ;
     RECT  94.999 2.151 117.288 63.528 ;
     RECT  117.288 24.48 117.419 25.74 ;
     RECT  117.288 2.151 117.887 22.419 ;
     RECT  117.288 23.634 117.887 23.652 ;
     RECT  117.887 2.151 117.923 22.302 ;
     RECT  117.419 24.561 117.923 25.002 ;
     RECT  117.923 24.984 117.995 25.002 ;
     RECT  117.288 27.306 118.139 27.36 ;
     RECT  118.139 27.342 118.247 27.36 ;
     RECT  117.923 2.151 119.34 21.996 ;
     RECT  117.288 34.092 119.34 62.874 ;
     RECT  47.975 65.601 119.34 84.249 ;
     RECT  119.34 2.151 140.4 84.249 ;
     RECT  140.4 52.146 141.359 52.164 ;
    LAYER M3 ;
     RECT  42.696 0.031 42.714 0.067 ;
     RECT  25.02 0.031 25.038 0.108 ;
     RECT  34.596 0.031 34.614 0.108 ;
     RECT  35.892 0.031 35.91 0.108 ;
     RECT  37.512 0.103 37.53 0.108 ;
     RECT  39.384 0.031 39.402 0.108 ;
     RECT  41.076 0.103 41.094 0.108 ;
     RECT  42.156 0.103 42.714 0.108 ;
     RECT  61.092 0.103 61.11 0.108 ;
     RECT  24.48 0.108 61.218 0.139 ;
     RECT  24.48 0.139 61.326 0.187 ;
     RECT  70.488 0.108 71.082 0.187 ;
     RECT  66.528 0.108 67.842 0.526 ;
     RECT  64.548 0.031 64.566 0.796 ;
     RECT  63.756 0.067 63.774 0.811 ;
     RECT  64.548 0.796 64.998 0.811 ;
     RECT  63.756 0.811 64.998 0.841 ;
     RECT  22.716 0.811 22.734 0.859 ;
     RECT  63.36 0.841 64.998 0.859 ;
     RECT  22.716 0.859 22.806 0.877 ;
     RECT  23.904 0.187 61.326 0.877 ;
     RECT  63.252 0.859 64.998 0.913 ;
     RECT  63 0.913 64.998 1.147 ;
     RECT  66.168 0.526 67.842 1.147 ;
     RECT  66.168 1.147 67.878 1.195 ;
     RECT  70.128 0.187 71.082 1.195 ;
     RECT  62.46 1.147 64.998 1.417 ;
     RECT  22.716 0.877 61.326 1.435 ;
     RECT  62.46 1.417 65.034 1.435 ;
     RECT  22.716 1.435 65.034 1.627 ;
     RECT  22.536 1.627 65.034 1.723 ;
     RECT  66.168 1.195 68.238 1.723 ;
     RECT  22.536 1.723 68.238 1.771 ;
     RECT  68.976 1.606 68.994 1.771 ;
     RECT  70.128 1.195 71.478 1.819 ;
     RECT  70.128 1.819 72.018 1.876 ;
     RECT  22.536 1.771 68.994 1.915 ;
     RECT  20.88 1.876 20.898 1.921 ;
     RECT  21.78 1.687 21.798 1.921 ;
     RECT  20.88 1.921 21.798 1.993 ;
     RECT  22.536 1.915 69.066 1.993 ;
     RECT  70.128 1.876 72.09 2.065 ;
     RECT  69.804 2.065 72.09 2.143 ;
     RECT  83.088 2.029 83.106 2.143 ;
     RECT  94.536 1.687 94.554 2.143 ;
     RECT  13.215 2.143 13.305 2.191 ;
     RECT  10.548 2.191 10.566 2.203 ;
     RECT  10.548 2.203 10.71 2.237 ;
     RECT  13.104 2.191 13.41 2.237 ;
     RECT  20.88 1.993 69.066 2.255 ;
     RECT  10.692 2.237 10.71 2.291 ;
     RECT  20.952 2.255 69.066 2.299 ;
     RECT  69.804 2.143 72.705 2.299 ;
     RECT  74.052 1.957 74.07 2.299 ;
     RECT  20.952 2.299 73.206 2.335 ;
     RECT  2.415 2.143 2.505 2.413 ;
     RECT  7.815 2.143 7.905 2.413 ;
     RECT  13.215 2.237 13.41 2.413 ;
     RECT  18.615 2.143 18.705 2.413 ;
     RECT  78.015 2.143 78.105 2.413 ;
     RECT  83.088 2.143 83.505 2.413 ;
     RECT  88.815 2.143 88.905 2.413 ;
     RECT  99.615 2.143 99.705 2.413 ;
     RECT  105.015 2.143 105.105 2.413 ;
     RECT  110.415 2.143 110.505 2.413 ;
     RECT  115.815 2.143 115.905 2.413 ;
     RECT  121.215 2.143 121.305 2.413 ;
     RECT  126.615 2.143 126.705 2.413 ;
     RECT  132.015 2.143 132.105 2.413 ;
     RECT  137.415 2.143 137.505 2.413 ;
     RECT  20.952 2.335 73.278 2.597 ;
     RECT  83.088 2.413 83.697 2.641 ;
     RECT  78.015 2.413 78.297 2.731 ;
     RECT  86.688 2.263 86.706 2.731 ;
     RECT  86.652 2.731 86.706 2.759 ;
     RECT  94.215 2.143 94.554 2.779 ;
     RECT  94.215 2.779 95.202 2.803 ;
     RECT  86.652 2.759 86.67 2.861 ;
     RECT  79.236 2.605 79.254 3.019 ;
     RECT  90.648 2.731 90.666 3.115 ;
     RECT  83.088 2.641 83.754 3.163 ;
     RECT  79.128 3.019 79.254 3.181 ;
     RECT  77.904 2.731 78.297 3.197 ;
     RECT  74.052 2.299 74.754 3.271 ;
     RECT  79.128 3.181 79.83 3.271 ;
     RECT  101.484 2.767 101.502 3.299 ;
     RECT  93.492 2.803 95.202 3.307 ;
     RECT  82.656 3.163 83.754 3.341 ;
     RECT  120.384 2.731 120.402 3.379 ;
     RECT  20.952 2.597 73.206 3.407 ;
     RECT  77.94 3.197 78.297 3.415 ;
     RECT  79.056 3.271 79.83 3.415 ;
     RECT  81.18 2.335 81.198 3.451 ;
     RECT  21.276 3.407 73.206 3.541 ;
     RECT  74.052 3.271 75.258 3.541 ;
     RECT  90.648 3.115 91.242 3.541 ;
     RECT  13.215 2.413 13.497 3.547 ;
     RECT  77.94 3.415 79.83 3.569 ;
     RECT  93.276 3.307 95.202 3.569 ;
     RECT  97.812 3.067 97.83 3.569 ;
     RECT  98.604 3.109 98.622 3.569 ;
     RECT  119.988 3.379 120.402 3.613 ;
     RECT  121.215 2.413 121.497 3.613 ;
     RECT  81.18 3.451 81.594 3.641 ;
     RECT  90.648 3.541 91.89 3.641 ;
     RECT  13.215 3.547 13.59 3.677 ;
     RECT  98.028 3.613 98.118 3.713 ;
     RECT  78.015 3.569 79.83 3.721 ;
     RECT  81.18 3.641 81.558 3.721 ;
     RECT  86.58 3.307 86.598 3.721 ;
     RECT  90.684 3.641 91.89 3.721 ;
     RECT  93.276 3.569 95.094 3.839 ;
     RECT  86.58 3.721 86.85 3.847 ;
     RECT  78.015 3.721 79.902 3.875 ;
     RECT  118.368 3.847 118.386 3.919 ;
     RECT  86.544 3.847 86.85 3.983 ;
     RECT  90.684 3.721 92.106 3.983 ;
     RECT  93.564 3.839 95.094 3.983 ;
     RECT  82.728 3.341 83.754 3.991 ;
     RECT  79.272 3.875 79.902 4.019 ;
     RECT  85.176 1.759 85.194 4.081 ;
     RECT  21.276 3.541 75.258 4.109 ;
     RECT  85.176 4.081 85.374 4.109 ;
     RECT  82.728 3.991 84.294 4.117 ;
     RECT  85.356 4.109 85.374 4.117 ;
     RECT  96.228 3.721 96.246 4.117 ;
     RECT  82.656 4.117 84.294 4.217 ;
     RECT  85.356 4.117 85.482 4.217 ;
     RECT  95.94 4.117 96.246 4.261 ;
     RECT  78.015 3.875 78.426 4.351 ;
     RECT  88.815 2.413 89.097 4.351 ;
     RECT  99.615 2.413 99.897 4.351 ;
     RECT  110.415 2.413 110.697 4.351 ;
     RECT  21.492 4.109 75.258 4.379 ;
     RECT  76.032 3.991 76.05 4.423 ;
     RECT  73.98 4.379 75.258 4.445 ;
     RECT  80.748 3.721 81.558 4.459 ;
     RECT  86.652 3.983 86.85 4.487 ;
     RECT  82.908 4.217 84.294 4.507 ;
     RECT  74.052 4.445 75.258 4.621 ;
     RECT  76.032 4.423 76.302 4.621 ;
     RECT  119.988 3.613 121.497 4.693 ;
     RECT  21.564 4.379 73.134 4.733 ;
     RECT  77.904 4.351 78.426 4.801 ;
     RECT  79.884 4.019 79.902 4.801 ;
     RECT  80.748 4.459 82.098 4.801 ;
     RECT  91.188 3.983 92.106 4.801 ;
     RECT  82.908 4.507 84.438 4.829 ;
     RECT  79.884 4.801 82.098 4.891 ;
     RECT  74.052 4.621 76.302 4.919 ;
     RECT  110.304 4.351 110.697 4.925 ;
     RECT  77.22 4.801 78.426 4.927 ;
     RECT  117.72 3.919 118.386 4.927 ;
     RECT  88.704 4.351 89.097 4.928 ;
     RECT  99.504 4.351 99.897 4.928 ;
     RECT  77.22 4.927 78.75 4.963 ;
     RECT  79.776 4.891 82.098 4.963 ;
     RECT  77.22 4.963 82.098 4.973 ;
     RECT  18.615 2.413 18.897 4.999 ;
     RECT  90.756 4.801 92.106 4.999 ;
     RECT  93.636 3.983 95.094 4.999 ;
     RECT  117.72 4.927 118.422 4.999 ;
     RECT  114.588 4.363 114.606 5.021 ;
     RECT  93.312 4.999 95.094 5.026 ;
     RECT  85.356 4.217 85.446 5.071 ;
     RECT  90.648 4.999 92.106 5.099 ;
     RECT  76.212 4.919 76.302 5.117 ;
     RECT  86.832 4.487 86.85 5.161 ;
     RECT  86.832 5.161 87.066 5.189 ;
     RECT  77.22 4.973 79.938 5.197 ;
     RECT  91.188 5.099 92.106 5.227 ;
     RECT  83.016 4.829 84.438 5.275 ;
     RECT  85.32 5.071 85.446 5.275 ;
     RECT  80.748 4.973 82.098 5.297 ;
     RECT  21.852 4.733 73.134 5.305 ;
     RECT  21.852 5.305 73.242 5.341 ;
     RECT  74.052 4.919 75.366 5.341 ;
     RECT  88.815 4.928 89.097 5.515 ;
     RECT  10.26 5.071 10.278 5.563 ;
     RECT  13.215 3.677 13.497 5.563 ;
     RECT  21.852 5.341 75.366 5.567 ;
     RECT  13.215 5.563 13.59 5.575 ;
     RECT  18.615 4.999 18.954 5.639 ;
     RECT  21.852 5.567 59.382 5.639 ;
     RECT  10.26 5.563 10.854 5.693 ;
     RECT  12.744 5.575 13.59 5.693 ;
     RECT  14.832 5.563 14.85 5.693 ;
     RECT  83.016 5.275 85.446 5.737 ;
     RECT  57.816 5.639 59.382 5.765 ;
     RECT  80.748 5.297 81.882 5.773 ;
     RECT  57.888 5.765 59.382 5.801 ;
     RECT  60.12 5.567 75.366 5.845 ;
     RECT  83.016 5.737 85.59 5.845 ;
     RECT  60.12 5.845 75.438 5.881 ;
     RECT  76.428 5.197 79.938 5.881 ;
     RECT  80.676 5.773 81.882 5.881 ;
     RECT  58.032 5.801 59.382 5.999 ;
     RECT  82.944 5.845 85.59 6.007 ;
     RECT  87.048 5.189 87.066 6.079 ;
     RECT  119.808 4.693 121.497 6.091 ;
     RECT  82.836 6.007 85.59 6.115 ;
     RECT  93.204 5.026 95.094 6.151 ;
     RECT  95.868 4.261 96.246 6.151 ;
     RECT  114.588 6.043 114.606 6.173 ;
     RECT  60.12 5.881 81.882 6.232 ;
     RECT  82.764 6.115 85.59 6.232 ;
     RECT  88.815 5.515 89.514 6.277 ;
     RECT  21.852 5.639 57.078 6.341 ;
     RECT  58.284 5.999 59.382 6.385 ;
     RECT  60.12 6.232 85.59 6.385 ;
     RECT  86.724 6.079 87.498 6.421 ;
     RECT  88.272 6.277 89.514 6.421 ;
     RECT  58.284 6.385 85.626 6.475 ;
     RECT  86.724 6.421 89.514 6.475 ;
     RECT  91.188 5.227 92.358 6.511 ;
     RECT  93.204 6.151 96.246 6.511 ;
     RECT  91.188 6.511 96.246 6.539 ;
     RECT  10.26 5.693 10.278 6.583 ;
     RECT  21.852 6.341 57.042 6.691 ;
     RECT  2.415 2.413 2.697 6.781 ;
     RECT  58.284 6.475 89.514 6.811 ;
     RECT  11.664 6.241 11.682 6.817 ;
     RECT  21.492 6.691 57.042 6.881 ;
     RECT  92.88 6.539 96.246 6.881 ;
     RECT  58.284 6.811 90.234 6.889 ;
     RECT  91.188 6.539 92.142 6.889 ;
     RECT  14.58 6.619 14.598 6.907 ;
     RECT  18.615 5.639 18.897 6.907 ;
     RECT  21.564 6.881 57.042 6.941 ;
     RECT  99.615 4.928 99.897 6.952 ;
     RECT  110.415 4.925 110.697 6.952 ;
     RECT  18.615 6.907 19.026 6.961 ;
     RECT  18.504 6.961 19.026 6.989 ;
     RECT  21.564 6.941 46.998 6.989 ;
     RECT  14.58 6.907 14.85 7.037 ;
     RECT  40.176 6.989 46.998 7.079 ;
     RECT  40.176 7.079 41.382 7.133 ;
     RECT  119.808 6.091 121.554 7.147 ;
     RECT  12.744 5.693 13.497 7.195 ;
     RECT  47.88 6.941 57.042 7.229 ;
     RECT  58.284 6.889 92.142 7.321 ;
     RECT  12.744 7.195 13.77 7.393 ;
     RECT  14.58 7.037 14.598 7.393 ;
     RECT  57.852 7.321 92.142 7.393 ;
     RECT  92.88 6.881 96.174 7.393 ;
     RECT  20.412 6.961 20.43 7.429 ;
     RECT  40.176 7.133 40.806 7.457 ;
     RECT  57.852 7.393 96.174 7.483 ;
     RECT  99.504 6.952 99.897 7.529 ;
     RECT  110.304 6.952 110.697 7.529 ;
     RECT  52.74 7.229 57.042 7.591 ;
     RECT  57.78 7.483 96.174 7.591 ;
     RECT  117.72 4.999 118.962 7.627 ;
     RECT  47.88 7.229 51.678 7.661 ;
     RECT  114.588 6.955 114.606 7.661 ;
     RECT  18.504 6.989 18.99 7.663 ;
     RECT  11.664 6.817 11.934 7.699 ;
     RECT  21.564 6.989 39.33 7.757 ;
     RECT  117.324 7.627 118.962 7.771 ;
     RECT  119.808 7.147 121.59 7.771 ;
     RECT  42.408 7.079 46.998 7.799 ;
     RECT  52.74 7.591 96.174 7.889 ;
     RECT  16.884 7.159 16.902 7.897 ;
     RECT  19.908 7.429 20.43 7.897 ;
     RECT  21.564 7.757 36.738 7.897 ;
     RECT  17.964 7.663 18.99 7.933 ;
     RECT  19.908 7.897 36.738 7.933 ;
     RECT  12.744 7.393 14.598 7.969 ;
     RECT  16.884 7.897 17.226 7.969 ;
     RECT  17.964 7.933 36.738 7.969 ;
     RECT  40.215 7.457 40.806 8.005 ;
     RECT  52.812 7.889 96.174 8.005 ;
     RECT  96.912 7.663 96.93 8.005 ;
     RECT  47.916 7.661 51.678 8.041 ;
     RECT  38.016 7.757 39.33 8.131 ;
     RECT  42.804 7.799 46.998 8.267 ;
     RECT  5.616 5.611 5.634 8.311 ;
     RECT  12.744 7.969 15.282 8.311 ;
     RECT  16.884 7.969 36.738 8.311 ;
     RECT  12.744 8.311 15.462 8.437 ;
     RECT  12.744 8.437 15.714 8.443 ;
     RECT  16.812 8.311 36.738 8.443 ;
     RECT  47.916 8.041 51.858 8.491 ;
     RECT  12.744 8.443 36.738 8.545 ;
     RECT  38.016 8.131 39.366 8.545 ;
     RECT  42.804 8.267 42.822 8.581 ;
     RECT  52.812 8.005 96.93 8.581 ;
     RECT  41.976 8.581 42.822 8.671 ;
     RECT  40.215 8.005 41.13 8.707 ;
     RECT  41.94 8.671 42.822 8.707 ;
     RECT  47.772 8.491 51.858 8.707 ;
     RECT  52.812 8.581 97.146 8.707 ;
     RECT  47.772 8.707 97.146 8.731 ;
     RECT  47.736 8.731 97.146 8.743 ;
     RECT  43.704 8.267 46.998 8.779 ;
     RECT  47.736 8.743 97.29 8.779 ;
     RECT  10.26 6.583 10.35 8.851 ;
     RECT  11.088 7.699 11.934 8.851 ;
     RECT  9.072 7.735 9.09 9.013 ;
     RECT  10.26 8.851 11.934 9.013 ;
     RECT  10.224 9.013 11.934 9.041 ;
     RECT  12.744 8.545 39.366 9.211 ;
     RECT  40.215 8.707 42.822 9.211 ;
     RECT  43.704 8.779 97.29 9.211 ;
     RECT  5.616 8.311 6.066 9.247 ;
     RECT  9.072 9.013 9.162 9.247 ;
     RECT  5.616 9.247 6.174 9.391 ;
     RECT  8.892 9.247 9.162 9.391 ;
     RECT  10.224 9.041 10.746 9.391 ;
     RECT  5.616 9.391 6.966 9.661 ;
     RECT  7.815 2.413 8.097 9.661 ;
     RECT  8.892 9.391 10.746 9.661 ;
     RECT  2.415 6.781 2.97 9.751 ;
     RECT  11.664 9.041 11.934 9.751 ;
     RECT  12.744 9.211 97.29 9.751 ;
     RECT  2.415 9.751 3.654 9.895 ;
     RECT  5.616 9.661 10.746 9.931 ;
     RECT  11.664 9.751 97.29 9.931 ;
     RECT  5.616 9.931 97.29 10.201 ;
     RECT  98.028 3.713 98.046 10.201 ;
     RECT  5.616 10.201 98.046 10.267 ;
     RECT  5.508 10.267 98.046 10.291 ;
     RECT  2.415 9.895 4.338 10.327 ;
     RECT  2.415 10.327 4.59 10.741 ;
     RECT  5.508 10.291 98.442 10.741 ;
     RECT  2.415 10.741 98.442 11.371 ;
     RECT  99.615 7.529 99.897 11.371 ;
     RECT  2.415 11.371 99.897 12.941 ;
     RECT  117.324 7.771 121.59 13.387 ;
     RECT  2.415 12.941 24.75 13.675 ;
     RECT  25.488 12.941 99.897 13.675 ;
     RECT  110.415 7.529 110.697 13.963 ;
     RECT  2.415 13.675 99.897 13.981 ;
     RECT  110.304 13.963 110.697 14.009 ;
     RECT  2.415 13.981 99.99 14.099 ;
     RECT  114.588 13.963 114.606 14.141 ;
     RECT  2.415 14.099 98.874 14.243 ;
     RECT  99.615 14.099 99.99 14.377 ;
     RECT  99.615 14.377 100.062 14.549 ;
     RECT  99.615 14.549 99.99 14.639 ;
     RECT  2.415 14.243 37.242 15.019 ;
     RECT  2.304 15.019 37.242 15.179 ;
     RECT  2.415 15.179 37.242 15.259 ;
     RECT  37.98 14.243 98.874 15.259 ;
     RECT  2.415 15.259 98.874 15.601 ;
     RECT  99.615 14.639 99.897 15.601 ;
     RECT  2.415 15.601 99.897 15.719 ;
     RECT  2.415 15.719 98.874 16.133 ;
     RECT  99.615 15.719 99.897 16.645 ;
     RECT  99.615 16.645 100.026 16.799 ;
     RECT  102.348 3.343 102.366 16.835 ;
     RECT  38.016 16.133 98.874 16.951 ;
     RECT  99.615 16.799 99.99 16.951 ;
     RECT  2.415 16.133 37.242 16.973 ;
     RECT  3.852 16.973 37.206 17.069 ;
     RECT  110.415 14.009 110.697 17.311 ;
     RECT  38.016 16.951 99.99 17.339 ;
     RECT  110.304 17.311 110.697 17.357 ;
     RECT  114.588 17.323 114.606 17.453 ;
     RECT  38.016 17.339 98.874 17.609 ;
     RECT  99.615 17.339 99.99 17.609 ;
     RECT  38.016 17.609 98.766 17.681 ;
     RECT  38.016 17.681 98.586 17.689 ;
     RECT  37.944 17.689 98.586 17.789 ;
     RECT  84.996 17.789 98.586 17.879 ;
     RECT  37.944 17.789 84.222 18.221 ;
     RECT  2.415 16.973 3.042 18.235 ;
     RECT  3.888 17.069 37.206 18.235 ;
     RECT  87.912 17.879 98.586 18.419 ;
     RECT  87.912 18.419 98.442 18.461 ;
     RECT  38.196 18.221 84.222 18.509 ;
     RECT  2.415 18.235 37.206 18.571 ;
     RECT  38.484 18.509 84.222 18.571 ;
     RECT  99.615 17.609 99.897 18.571 ;
     RECT  87.912 18.461 98.154 18.599 ;
     RECT  97.02 18.599 97.542 18.689 ;
     RECT  97.128 18.689 97.506 18.761 ;
     RECT  99.432 18.571 99.897 18.761 ;
     RECT  97.2 18.761 97.506 18.797 ;
     RECT  38.484 18.571 84.258 18.805 ;
     RECT  84.996 17.879 87.102 18.805 ;
     RECT  38.484 18.805 87.102 18.841 ;
     RECT  87.912 18.599 96.246 18.841 ;
     RECT  2.196 18.571 37.422 19.099 ;
     RECT  38.484 18.841 96.246 19.229 ;
     RECT  80.064 19.229 96.246 19.301 ;
     RECT  84.564 19.301 96.246 19.337 ;
     RECT  46.692 19.229 79.326 19.373 ;
     RECT  84.564 19.337 86.454 19.373 ;
     RECT  57.672 19.373 64.602 19.379 ;
     RECT  2.196 19.099 37.674 19.381 ;
     RECT  38.484 19.229 45.897 19.381 ;
     RECT  65.7 19.373 79.254 19.409 ;
     RECT  80.064 19.301 83.826 19.409 ;
     RECT  65.7 19.409 75.798 19.499 ;
     RECT  80.064 19.409 83.754 19.499 ;
     RECT  84.564 19.373 86.382 19.499 ;
     RECT  57.852 19.379 64.602 19.517 ;
     RECT  46.692 19.373 56.934 19.535 ;
     RECT  80.1 19.499 83.754 19.535 ;
     RECT  57.852 19.517 59.706 19.571 ;
     RECT  60.624 19.517 64.602 19.571 ;
     RECT  87.192 19.337 96.246 19.571 ;
     RECT  58.176 19.571 59.706 19.607 ;
     RECT  76.716 19.409 79.254 19.607 ;
     RECT  84.564 19.499 86.238 19.607 ;
     RECT  48.852 19.535 56.934 19.643 ;
     RECT  46.692 19.535 48.042 19.679 ;
     RECT  49.032 19.643 56.934 19.679 ;
     RECT  2.196 19.381 45.897 19.769 ;
     RECT  46.692 19.679 47.106 19.769 ;
     RECT  65.7 19.499 69.426 19.769 ;
     RECT  76.716 19.607 78.606 19.769 ;
     RECT  87.192 19.571 92.034 19.769 ;
     RECT  92.808 19.571 96.246 19.769 ;
     RECT  2.196 19.769 33.75 19.805 ;
     RECT  34.668 19.769 39.438 19.805 ;
     RECT  65.7 19.769 69.354 19.805 ;
     RECT  71.64 19.499 75.618 19.805 ;
     RECT  87.192 19.769 91.998 19.805 ;
     RECT  1.368 17.491 1.386 19.819 ;
     RECT  34.668 19.805 39.366 19.841 ;
     RECT  46.764 19.769 47.106 19.841 ;
     RECT  74.484 19.805 75.618 19.841 ;
     RECT  80.208 19.535 83.754 19.841 ;
     RECT  91.908 19.805 91.998 19.841 ;
     RECT  96.228 19.769 96.246 19.849 ;
     RECT  23.976 19.805 33.75 19.877 ;
     RECT  49.032 19.679 56.697 19.877 ;
     RECT  25.164 19.877 33.75 19.901 ;
     RECT  87.444 19.805 90.738 19.901 ;
     RECT  99.615 18.761 99.897 19.912 ;
     RECT  110.415 17.357 110.697 19.912 ;
     RECT  34.668 19.841 35.694 19.913 ;
     RECT  40.215 19.769 41.31 19.913 ;
     RECT  47.916 19.679 48.042 19.913 ;
     RECT  66.636 19.805 69.354 19.913 ;
     RECT  80.208 19.841 83.697 19.913 ;
     RECT  84.564 19.607 86.166 19.913 ;
     RECT  87.624 19.901 90.738 19.913 ;
     RECT  92.808 19.769 95.022 19.913 ;
     RECT  36.468 19.841 39.366 19.949 ;
     RECT  71.64 19.805 73.638 19.949 ;
     RECT  77.292 19.769 78.606 19.949 ;
     RECT  80.784 19.913 83.697 19.949 ;
     RECT  85.788 19.913 86.166 19.949 ;
     RECT  87.624 19.913 89.097 19.949 ;
     RECT  90.576 19.913 90.738 19.949 ;
     RECT  96.228 19.849 96.462 19.949 ;
     RECT  99.504 19.912 99.897 19.949 ;
     RECT  110.304 19.912 110.697 19.949 ;
     RECT  114.588 19.819 114.606 19.949 ;
     RECT  40.215 19.913 41.13 19.997 ;
     RECT  42.084 19.769 45.897 19.997 ;
     RECT  60.624 19.571 63.162 19.997 ;
     RECT  77.292 19.949 78.297 19.997 ;
     RECT  94.215 19.913 95.022 19.997 ;
     RECT  99.615 19.949 99.897 19.997 ;
     RECT  105.015 2.413 105.297 19.997 ;
     RECT  110.415 19.949 110.697 19.997 ;
     RECT  115.815 2.413 116.097 19.997 ;
     RECT  36.468 19.949 37.638 20.039 ;
     RECT  38.484 19.949 39.366 20.039 ;
     RECT  43.452 19.997 43.47 20.039 ;
     RECT  49.824 19.877 56.697 20.039 ;
     RECT  65.7 19.805 65.718 20.039 ;
     RECT  80.784 19.949 81.018 20.039 ;
     RECT  82.332 19.949 83.697 20.039 ;
     RECT  84.564 19.913 84.978 20.039 ;
     RECT  25.272 19.901 33.75 20.075 ;
     RECT  36.468 20.039 37.458 20.075 ;
     RECT  47.916 19.913 47.934 20.075 ;
     RECT  117.324 13.387 121.626 20.083 ;
     RECT  25.272 20.075 31.95 20.093 ;
     RECT  66.636 19.913 67.986 20.093 ;
     RECT  58.284 19.607 59.706 20.111 ;
     RECT  90.576 19.949 90.666 20.111 ;
     RECT  87.804 19.949 89.097 20.141 ;
     RECT  116.856 20.083 121.626 20.141 ;
     RECT  25.272 20.093 30.078 20.147 ;
     RECT  49.824 20.039 52.11 20.147 ;
     RECT  34.776 19.913 35.55 20.183 ;
     RECT  36.468 20.075 37.026 20.183 ;
     RECT  84.924 20.039 84.942 20.183 ;
     RECT  90.612 20.111 90.666 20.183 ;
     RECT  72.504 19.949 73.638 20.189 ;
     RECT  44.208 19.997 44.946 20.219 ;
     RECT  49.032 19.877 49.05 20.219 ;
     RECT  59.04 20.111 59.706 20.219 ;
     RECT  66.636 20.093 67.497 20.219 ;
     RECT  50.868 20.147 51.39 20.237 ;
     RECT  25.272 20.147 29.697 20.267 ;
     RECT  40.407 19.997 41.13 20.267 ;
     RECT  45.807 19.997 45.897 20.267 ;
     RECT  50.868 20.237 51.297 20.267 ;
     RECT  52.992 20.039 56.697 20.267 ;
     RECT  62.007 19.997 63.162 20.267 ;
     RECT  67.407 20.219 67.497 20.267 ;
     RECT  72.807 20.189 73.638 20.267 ;
     RECT  78.207 19.997 78.297 20.267 ;
     RECT  83.124 20.039 83.697 20.267 ;
     RECT  89.007 20.141 89.097 20.267 ;
     RECT  94.407 19.997 95.022 20.267 ;
     RECT  99.807 19.997 99.897 20.267 ;
     RECT  105.207 19.997 105.297 20.267 ;
     RECT  110.607 19.997 110.697 20.267 ;
     RECT  116.007 19.997 116.097 20.267 ;
     RECT  2.196 19.805 23.13 20.285 ;
     RECT  68.868 19.913 69.354 20.285 ;
     RECT  62.388 20.267 63.162 20.309 ;
     RECT  71.64 19.949 71.658 20.309 ;
     RECT  52.992 20.267 56.574 20.381 ;
     RECT  96.228 19.949 96.246 20.381 ;
     RECT  23.976 19.877 24.354 20.417 ;
     RECT  32.94 20.075 33.75 20.417 ;
     RECT  31.104 20.093 31.95 20.453 ;
     RECT  2.196 20.285 23.058 20.477 ;
     RECT  42.084 19.997 42.606 20.477 ;
     RECT  25.272 20.267 29.142 20.489 ;
     RECT  33.66 20.417 33.75 20.489 ;
     RECT  74.484 19.841 75.222 20.525 ;
     RECT  25.272 20.489 27.522 20.534 ;
     RECT  93.096 19.913 93.114 20.534 ;
     RECT  41.112 20.267 41.13 20.573 ;
     RECT  46.764 19.841 46.782 20.579 ;
     RECT  85.788 19.949 85.806 20.579 ;
     RECT  25.272 20.534 27.342 20.615 ;
     RECT  80.784 20.039 80.802 20.615 ;
     RECT  39.348 20.039 39.366 20.687 ;
     RECT  25.272 20.615 26.874 20.723 ;
     RECT  42.084 20.477 42.102 20.804 ;
     RECT  68.976 20.285 69.354 20.804 ;
     RECT  33.732 20.489 33.75 20.813 ;
     RECT  58.284 20.111 58.302 20.813 ;
     RECT  25.272 20.723 26.802 20.849 ;
     RECT  59.04 20.219 59.058 20.861 ;
     RECT  62.388 20.309 63.09 20.885 ;
     RECT  68.976 20.804 69.21 20.885 ;
     RECT  82.332 20.039 82.35 20.909 ;
     RECT  83.124 20.267 83.142 20.921 ;
     RECT  25.74 20.849 26.802 20.957 ;
     RECT  1.008 19.819 1.386 20.965 ;
     RECT  2.196 20.477 22.986 20.965 ;
     RECT  34.776 20.183 35.406 20.993 ;
     RECT  36.468 20.183 36.486 21.029 ;
     RECT  38.484 20.039 38.502 21.046 ;
     RECT  25.74 20.957 26.658 21.074 ;
     RECT  38.268 21.046 38.502 21.074 ;
     RECT  60.624 19.997 61.11 21.074 ;
     RECT  53.028 20.381 56.574 21.119 ;
     RECT  117.324 20.141 121.626 21.127 ;
     RECT  68.976 20.885 69.03 21.149 ;
     RECT  53.388 21.119 56.574 21.197 ;
     RECT  73.296 20.267 73.638 21.293 ;
     RECT  26.64 21.074 26.658 21.299 ;
     RECT  62.388 20.885 62.406 21.341 ;
     RECT  31.104 20.453 31.122 21.389 ;
     RECT  38.268 21.074 38.286 21.389 ;
     RECT  90.612 20.183 90.63 21.389 ;
     RECT  95.004 20.267 95.022 21.389 ;
     RECT  77.292 19.997 77.31 21.425 ;
     RECT  73.296 21.293 73.314 21.461 ;
     RECT  44.208 20.219 44.91 21.485 ;
     RECT  53.388 21.197 55.314 21.485 ;
     RECT  64.404 19.571 64.602 21.497 ;
     RECT  53.496 21.485 55.314 21.533 ;
     RECT  49.824 20.147 49.842 21.569 ;
     RECT  34.776 20.993 34.794 21.614 ;
     RECT  60.624 21.074 61.038 21.629 ;
     RECT  50.868 20.267 50.886 21.659 ;
     RECT  56.232 21.197 56.574 21.677 ;
     RECT  87.804 20.141 87.822 21.695 ;
     RECT  1.008 20.965 22.986 21.979 ;
     RECT  0.792 21.979 22.986 22.464 ;
     RECT  25.74 21.074 25.758 22.464 ;
     RECT  28.26 20.489 28.818 22.464 ;
     RECT  31.932 20.453 31.95 22.464 ;
     RECT  43.344 22.165 43.362 22.464 ;
     RECT  44.208 21.485 44.226 22.464 ;
     RECT  50.184 22.171 50.202 22.464 ;
     RECT  53.496 21.533 54.162 22.464 ;
     RECT  55.044 21.533 55.314 22.464 ;
     RECT  56.232 21.677 56.25 22.464 ;
     RECT  60.624 21.629 60.642 22.464 ;
     RECT  64.584 21.497 64.602 22.464 ;
     RECT  66.636 20.219 66.654 22.464 ;
     RECT  68.976 21.149 68.994 22.464 ;
     RECT  70.308 19.499 70.83 22.464 ;
     RECT  74.484 20.525 74.502 22.464 ;
     RECT  117.288 21.127 121.626 22.464 ;
     RECT  0.792 22.464 121.626 23.125 ;
     RECT  0.54 23.125 121.626 24.571 ;
     RECT  0.54 24.571 121.698 24.749 ;
     RECT  0.54 24.749 121.554 26.141 ;
     RECT  0.54 26.141 121.497 28.525 ;
     RECT  0.504 28.525 121.497 30.557 ;
     RECT  0.504 30.557 117.774 30.941 ;
     RECT  0.504 30.941 117.486 31.517 ;
     RECT  118.584 30.557 121.497 32.669 ;
     RECT  0.504 31.517 117.288 32.779 ;
     RECT  0.252 32.779 117.288 33.403 ;
     RECT  118.764 32.669 121.497 33.533 ;
     RECT  118.764 33.533 119.862 33.629 ;
     RECT  0.216 33.403 117.288 34.087 ;
     RECT  0.216 34.087 117.414 34.16 ;
     RECT  119.16 33.629 119.862 34.205 ;
     RECT  119.196 34.205 119.862 34.301 ;
     RECT  119.52 34.301 119.862 34.493 ;
     RECT  119.736 34.493 119.862 34.589 ;
     RECT  0.288 34.16 117.414 34.987 ;
     RECT  119.736 34.589 119.79 34.997 ;
     RECT  119.736 34.997 119.754 35.267 ;
     RECT  0.216 34.987 117.414 35.465 ;
     RECT  118.584 35.473 118.602 35.515 ;
     RECT  118.584 35.515 119.61 35.573 ;
     RECT  119.124 35.573 119.61 35.969 ;
     RECT  0.252 35.465 117.414 35.995 ;
     RECT  119.592 35.969 119.61 36.085 ;
     RECT  0.252 35.995 117.486 36.239 ;
     RECT  0.252 36.239 117.45 36.283 ;
     RECT  0.216 36.283 117.45 36.311 ;
     RECT  119.592 36.085 119.934 36.589 ;
     RECT  119.592 36.589 120.078 36.815 ;
     RECT  118.584 36.553 118.674 36.895 ;
     RECT  119.592 36.815 119.682 36.895 ;
     RECT  118.584 36.895 119.682 37.049 ;
     RECT  118.584 37.049 119.646 37.181 ;
     RECT  119.052 37.181 119.646 37.589 ;
     RECT  119.052 37.589 119.61 38.101 ;
     RECT  0.216 36.311 117.414 38.407 ;
     RECT  118.584 38.101 119.61 38.551 ;
     RECT  0.216 38.407 117.45 38.621 ;
     RECT  118.584 38.551 119.898 38.669 ;
     RECT  118.584 38.669 119.79 39.005 ;
     RECT  119.016 39.005 119.79 39.317 ;
     RECT  119.016 39.317 119.106 39.485 ;
     RECT  0.216 38.621 117.378 39.631 ;
     RECT  119.88 39.721 119.898 39.857 ;
     RECT  119.088 39.485 119.106 39.965 ;
     RECT  0.216 39.631 117.414 40.099 ;
     RECT  119.952 40.369 119.97 40.801 ;
     RECT  119.952 40.801 120.006 40.873 ;
     RECT  119.844 40.873 120.006 40.937 ;
     RECT  119.844 40.937 119.862 41.009 ;
     RECT  118.62 41.107 118.638 41.251 ;
     RECT  119.52 41.563 119.538 41.675 ;
     RECT  0.108 40.099 117.414 41.683 ;
     RECT  118.584 41.251 118.638 41.783 ;
     RECT  0.036 41.683 117.414 42.043 ;
     RECT  0.036 42.043 117.45 42.089 ;
     RECT  119.628 42.139 119.646 42.187 ;
     RECT  119.628 42.187 120.078 42.287 ;
     RECT  119.628 42.287 119.97 42.629 ;
     RECT  118.584 41.783 118.602 42.715 ;
     RECT  119.628 42.629 119.934 42.715 ;
     RECT  118.584 42.715 119.934 42.755 ;
     RECT  118.584 42.755 119.862 42.791 ;
     RECT  118.584 42.791 119.79 42.941 ;
     RECT  118.62 42.941 119.79 43.637 ;
     RECT  118.62 43.637 119.61 43.807 ;
     RECT  118.584 43.807 119.61 44.375 ;
     RECT  118.584 44.375 119.466 44.519 ;
     RECT  118.584 44.519 119.106 44.669 ;
     RECT  118.584 44.669 118.674 45.053 ;
     RECT  120.096 45.121 120.114 45.329 ;
     RECT  118.62 45.053 118.674 45.427 ;
     RECT  0.036 42.089 117.414 45.455 ;
     RECT  118.62 45.427 118.71 45.599 ;
     RECT  118.692 45.599 118.71 45.629 ;
     RECT  119.736 45.769 119.754 46.273 ;
     RECT  119.736 46.273 119.862 46.373 ;
     RECT  119.736 46.373 119.79 46.949 ;
     RECT  118.584 46.579 118.602 47.119 ;
     RECT  119.736 46.949 119.754 47.119 ;
     RECT  118.584 47.119 119.754 47.183 ;
     RECT  118.584 47.183 119.718 47.309 ;
     RECT  118.584 47.309 119.106 48.299 ;
     RECT  0.432 45.455 117.414 48.379 ;
     RECT  118.62 48.299 119.106 48.397 ;
     RECT  119.88 48.091 119.898 48.397 ;
     RECT  0.432 48.379 117.45 48.425 ;
     RECT  118.62 48.397 119.898 48.533 ;
     RECT  120.06 48.667 120.078 48.929 ;
     RECT  118.62 48.533 119.106 49.307 ;
     RECT  119.052 49.307 119.106 49.441 ;
     RECT  119.052 49.441 119.862 49.469 ;
     RECT  119.088 49.469 119.862 49.577 ;
     RECT  119.844 49.577 119.862 49.775 ;
     RECT  119.088 49.577 119.106 50.431 ;
     RECT  119.088 50.431 119.79 50.629 ;
     RECT  119.088 50.629 119.97 50.935 ;
     RECT  0.432 48.425 117.414 51.395 ;
     RECT  118.584 50.935 119.97 51.467 ;
     RECT  118.584 51.467 119.898 52.079 ;
     RECT  0.468 51.395 117.414 52.123 ;
     RECT  141.336 52.027 141.354 52.169 ;
     RECT  0.468 52.123 117.45 52.205 ;
     RECT  118.62 52.079 119.898 52.825 ;
     RECT  118.62 52.825 120.15 52.987 ;
     RECT  118.584 52.987 120.15 53.597 ;
     RECT  119.448 53.597 120.15 53.693 ;
     RECT  119.448 53.693 119.79 53.897 ;
     RECT  118.584 53.597 118.674 54.523 ;
     RECT  119.448 53.897 119.754 54.523 ;
     RECT  118.584 54.523 119.754 54.941 ;
     RECT  118.584 54.941 118.602 55.013 ;
     RECT  119.592 54.941 119.754 55.291 ;
     RECT  119.592 55.291 119.79 55.409 ;
     RECT  119.592 55.409 119.754 55.715 ;
     RECT  119.592 55.715 119.682 55.867 ;
     RECT  119.304 55.867 119.682 56.191 ;
     RECT  118.584 56.191 119.682 56.255 ;
     RECT  118.584 56.255 119.646 56.399 ;
     RECT  0.468 52.205 117.414 56.725 ;
     RECT  118.62 56.399 119.646 56.867 ;
     RECT  119.304 56.867 119.646 56.903 ;
     RECT  119.556 56.903 119.646 57.029 ;
     RECT  119.736 57.145 119.754 57.307 ;
     RECT  0.468 56.725 117.45 57.533 ;
     RECT  119.736 57.307 119.862 57.721 ;
     RECT  119.736 57.721 119.934 57.811 ;
     RECT  119.628 57.811 119.934 57.991 ;
     RECT  119.628 57.991 119.97 58.075 ;
     RECT  119.268 58.075 119.97 58.081 ;
     RECT  118.584 58.081 119.97 58.109 ;
     RECT  118.584 58.109 119.718 58.487 ;
     RECT  118.584 58.487 118.602 59.233 ;
     RECT  119.52 58.487 119.718 59.341 ;
     RECT  118.584 59.233 118.638 59.431 ;
     RECT  119.52 59.341 119.754 59.495 ;
     RECT  118.584 59.431 118.674 59.567 ;
     RECT  119.736 59.495 119.754 59.611 ;
     RECT  0.468 57.533 117.414 60.115 ;
     RECT  0.468 60.115 117.45 60.317 ;
     RECT  119.736 59.611 119.934 60.379 ;
     RECT  119.628 60.379 119.934 60.421 ;
     RECT  0.468 60.317 117.414 60.449 ;
     RECT  119.628 60.421 119.97 60.539 ;
     RECT  119.628 60.539 119.754 60.845 ;
     RECT  119.628 60.845 119.646 60.955 ;
     RECT  119.16 60.955 119.646 61.223 ;
     RECT  118.62 61.357 118.638 61.529 ;
     RECT  119.556 61.223 119.646 61.619 ;
     RECT  119.592 61.619 119.646 61.735 ;
     RECT  0.504 60.449 117.414 61.757 ;
     RECT  0.54 61.757 117.414 61.819 ;
     RECT  119.592 61.735 119.934 61.925 ;
     RECT  119.592 61.925 119.646 62.395 ;
     RECT  119.52 62.395 119.646 62.851 ;
     RECT  0.54 61.819 118.026 62.879 ;
     RECT  119.52 62.851 119.718 63.005 ;
     RECT  0.54 62.879 117.288 63.528 ;
     RECT  0.54 63.528 23.598 64.597 ;
     RECT  24.336 63.528 25.362 64.597 ;
     RECT  64.404 63.528 64.422 64.651 ;
     RECT  35.676 63.528 35.694 64.741 ;
     RECT  35.676 64.741 35.91 64.843 ;
     RECT  27.792 64.471 27.81 64.939 ;
     RECT  28.584 63.528 29.358 64.939 ;
     RECT  38.484 64.669 38.502 64.987 ;
     RECT  44.46 64.975 44.478 65.021 ;
     RECT  38.484 64.987 38.79 65.039 ;
     RECT  27.792 64.939 29.358 65.101 ;
     RECT  33.012 64.987 33.03 65.165 ;
     RECT  27.792 65.101 29.574 65.179 ;
     RECT  0.54 64.597 25.362 65.443 ;
     RECT  26.496 64.363 26.514 65.443 ;
     RECT  27.792 65.179 29.79 65.551 ;
     RECT  31.932 64.561 31.95 65.551 ;
     RECT  0.54 65.443 26.514 65.563 ;
     RECT  35.676 64.843 36.018 65.593 ;
     RECT  40.176 63.528 40.194 65.593 ;
     RECT  51.876 65.515 51.894 65.593 ;
     RECT  55.872 64.363 55.89 65.593 ;
     RECT  35.007 65.593 36.018 65.677 ;
     RECT  139.608 52.285 139.626 65.693 ;
     RECT  0.54 65.563 26.694 65.713 ;
     RECT  27.576 65.551 29.79 65.713 ;
     RECT  31.284 65.551 31.95 65.713 ;
     RECT  34.74 65.677 36.018 65.749 ;
     RECT  63.72 64.651 64.422 65.755 ;
     RECT  40.176 65.593 40.497 65.785 ;
     RECT  57.996 65.641 58.014 65.785 ;
     RECT  63.72 65.755 64.818 65.785 ;
     RECT  34.668 65.749 36.018 65.821 ;
     RECT  37.008 64.399 37.026 65.821 ;
     RECT  51.207 65.593 51.894 65.821 ;
     RECT  53.172 65.227 53.19 65.821 ;
     RECT  45.807 65.593 45.897 65.863 ;
     RECT  51.207 65.821 53.19 65.863 ;
     RECT  62.007 65.593 62.097 65.863 ;
     RECT  67.407 65.593 67.497 65.863 ;
     RECT  72.807 65.593 72.897 65.863 ;
     RECT  78.207 65.593 78.297 65.863 ;
     RECT  83.607 65.593 83.697 65.863 ;
     RECT  89.007 65.593 89.097 65.863 ;
     RECT  94.407 65.593 94.497 65.863 ;
     RECT  99.807 65.593 99.897 65.863 ;
     RECT  105.207 65.593 105.297 65.863 ;
     RECT  110.607 65.593 110.697 65.863 ;
     RECT  116.007 65.593 116.097 65.863 ;
     RECT  0.54 65.713 29.79 65.899 ;
     RECT  30.852 65.713 31.95 65.899 ;
     RECT  41.652 65.755 41.67 65.941 ;
     RECT  49.14 65.911 49.158 65.941 ;
     RECT  34.596 65.821 36.018 65.947 ;
     RECT  37.008 65.821 37.602 65.947 ;
     RECT  40.176 65.785 40.59 65.947 ;
     RECT  41.616 65.941 41.67 65.947 ;
     RECT  61.815 65.863 62.097 65.947 ;
     RECT  69.624 63.528 69.642 65.947 ;
     RECT  69.372 65.947 69.642 65.983 ;
     RECT  61.56 65.947 62.097 66.019 ;
     RECT  34.596 65.947 37.602 66.055 ;
     RECT  38.484 65.039 38.502 66.055 ;
     RECT  61.56 66.019 62.334 66.055 ;
     RECT  69.372 65.983 69.678 66.055 ;
     RECT  34.596 66.055 38.502 66.091 ;
     RECT  45.615 65.863 45.897 66.091 ;
     RECT  47.808 65.947 47.826 66.091 ;
     RECT  48.888 65.941 49.158 66.091 ;
     RECT  55.872 65.593 56.697 66.091 ;
     RECT  57.852 65.785 58.014 66.091 ;
     RECT  61.56 66.055 62.73 66.091 ;
     RECT  63.72 65.785 65.178 66.091 ;
     RECT  69.084 66.055 69.678 66.091 ;
     RECT  32.796 66.055 32.814 66.181 ;
     RECT  42.552 66.091 42.57 66.181 ;
     RECT  45.615 66.091 46.134 66.181 ;
     RECT  51.015 65.863 53.19 66.181 ;
     RECT  53.928 66.139 53.946 66.181 ;
     RECT  55.224 66.091 58.014 66.181 ;
     RECT  61.56 66.091 62.91 66.181 ;
     RECT  63.684 66.091 65.178 66.181 ;
     RECT  34.596 66.091 39.006 66.187 ;
     RECT  40.176 65.947 41.67 66.187 ;
     RECT  0.54 65.899 31.95 66.217 ;
     RECT  32.796 66.181 32.886 66.217 ;
     RECT  42.552 66.181 43.146 66.217 ;
     RECT  48.888 66.091 49.734 66.217 ;
     RECT  50.508 66.181 53.946 66.217 ;
     RECT  54.72 66.181 58.014 66.217 ;
     RECT  67.215 65.863 67.497 66.217 ;
     RECT  48.888 66.217 53.946 66.235 ;
     RECT  54.72 66.217 58.662 66.235 ;
     RECT  66.564 66.217 67.497 66.235 ;
     RECT  68.256 66.181 68.274 66.235 ;
     RECT  42.552 66.217 44.01 66.289 ;
     RECT  44.784 66.181 44.802 66.289 ;
     RECT  59.652 66.253 59.67 66.289 ;
     RECT  69.084 66.091 69.714 66.289 ;
     RECT  0.54 66.217 32.886 66.317 ;
     RECT  42.552 66.289 44.802 66.325 ;
     RECT  45.615 66.181 46.53 66.325 ;
     RECT  47.484 66.091 47.826 66.325 ;
     RECT  59.544 66.289 59.67 66.325 ;
     RECT  34.596 66.187 41.67 66.361 ;
     RECT  42.552 66.325 48.078 66.361 ;
     RECT  48.888 66.235 58.662 66.361 ;
     RECT  59.544 66.325 60.102 66.361 ;
     RECT  61.056 66.181 65.178 66.361 ;
     RECT  66.564 66.235 68.274 66.361 ;
     RECT  69.084 66.289 70.002 66.361 ;
     RECT  42.552 66.361 60.102 66.427 ;
     RECT  60.876 66.361 65.322 66.427 ;
     RECT  42.552 66.427 65.322 66.451 ;
     RECT  66.456 66.361 70.002 66.451 ;
     RECT  32.472 66.317 32.886 66.479 ;
     RECT  32.796 66.479 32.886 66.487 ;
     RECT  33.66 66.361 41.67 66.487 ;
     RECT  42.552 66.451 70.002 66.523 ;
     RECT  32.796 66.487 41.67 66.595 ;
     RECT  42.552 66.523 70.038 66.595 ;
     RECT  32.796 66.595 70.038 66.623 ;
     RECT  43.164 66.623 70.038 66.631 ;
     RECT  32.796 66.623 42.318 66.659 ;
     RECT  32.796 66.659 41.166 66.893 ;
     RECT  43.164 66.631 70.506 67.019 ;
     RECT  43.344 67.019 70.506 67.055 ;
     RECT  43.416 67.055 70.506 67.163 ;
     RECT  0.54 66.317 31.662 67.171 ;
     RECT  43.812 67.163 68.346 67.229 ;
     RECT  0.54 67.171 31.842 67.369 ;
     RECT  32.796 66.893 35.946 67.369 ;
     RECT  42.012 66.659 42.318 67.441 ;
     RECT  69.084 67.163 70.506 67.441 ;
     RECT  69.084 67.441 70.614 67.559 ;
     RECT  36.756 66.893 41.166 67.567 ;
     RECT  42.012 67.441 42.606 67.567 ;
     RECT  36.756 67.567 42.606 67.639 ;
     RECT  60.84 67.229 68.346 67.945 ;
     RECT  69.084 67.559 70.542 67.945 ;
     RECT  0.54 67.369 35.946 67.981 ;
     RECT  36.72 67.639 42.606 67.981 ;
     RECT  0.54 67.981 42.606 68.107 ;
     RECT  0.54 68.107 42.822 68.155 ;
     RECT  43.812 67.229 60.03 68.155 ;
     RECT  60.84 67.945 70.542 68.369 ;
     RECT  0.54 68.155 60.03 68.413 ;
     RECT  60.84 68.369 70.362 68.413 ;
     RECT  0.54 68.413 70.362 69.089 ;
     RECT  1.656 69.089 70.362 69.601 ;
     RECT  1.656 69.601 70.398 69.989 ;
     RECT  71.28 69.871 71.298 70.061 ;
     RECT  1.656 69.989 70.362 70.109 ;
     RECT  0.54 69.089 0.558 71.213 ;
     RECT  1.656 70.109 70.146 71.221 ;
     RECT  1.656 71.221 70.182 71.323 ;
     RECT  1.656 71.323 70.362 71.491 ;
     RECT  1.656 71.491 71.298 71.501 ;
     RECT  2.232 71.501 71.298 71.789 ;
     RECT  2.232 71.789 70.65 71.879 ;
     RECT  2.268 71.879 70.65 72.599 ;
     RECT  2.268 72.599 70.254 72.959 ;
     RECT  2.268 72.959 70.146 73.373 ;
     RECT  71.28 73.651 71.298 73.769 ;
     RECT  2.268 73.373 68.13 73.877 ;
     RECT  69.048 73.373 70.146 73.921 ;
     RECT  2.268 73.877 57.618 74.039 ;
     RECT  58.536 73.877 68.13 74.155 ;
     RECT  69.048 73.921 70.182 74.155 ;
     RECT  58.536 74.155 70.182 74.381 ;
     RECT  58.536 74.381 69.606 74.579 ;
     RECT  2.268 74.039 57.474 74.615 ;
     RECT  32.436 74.615 57.474 74.621 ;
     RECT  2.268 74.615 10.638 74.687 ;
     RECT  60.336 74.579 69.606 74.687 ;
     RECT  58.536 74.579 59.562 74.759 ;
     RECT  69.336 74.687 69.606 74.849 ;
     RECT  70.524 74.551 70.542 74.849 ;
     RECT  33.84 74.621 57.474 74.929 ;
     RECT  58.536 74.759 58.662 74.929 ;
     RECT  60.336 74.687 68.454 74.957 ;
     RECT  59.544 74.759 59.562 74.993 ;
     RECT  32.436 74.621 33.102 75.119 ;
     RECT  33.84 74.929 58.662 75.119 ;
     RECT  60.876 74.957 68.454 75.119 ;
     RECT  69.336 74.849 69.354 75.119 ;
     RECT  32.652 75.119 33.102 75.149 ;
     RECT  58.284 75.119 58.662 75.155 ;
     RECT  60.876 75.119 68.238 75.197 ;
     RECT  60.876 75.197 67.734 75.299 ;
     RECT  66.276 75.299 67.734 75.389 ;
     RECT  60.876 75.299 64.998 75.425 ;
     RECT  66.312 75.389 67.734 75.461 ;
     RECT  58.284 75.155 58.554 75.485 ;
     RECT  58.536 75.485 58.554 75.497 ;
     RECT  2.268 74.687 10.602 75.499 ;
     RECT  11.376 74.615 31.698 75.499 ;
     RECT  61.092 75.425 64.998 75.533 ;
     RECT  33.84 75.119 57.51 75.659 ;
     RECT  61.164 75.533 64.998 75.659 ;
     RECT  66.348 75.461 67.734 75.659 ;
     RECT  33.84 75.659 51.75 75.739 ;
     RECT  61.164 75.659 62.097 75.839 ;
     RECT  33.624 75.739 51.75 75.929 ;
     RECT  52.668 75.659 57.51 75.929 ;
     RECT  61.2 75.839 62.097 75.929 ;
     RECT  62.856 75.659 64.998 75.929 ;
     RECT  66.348 75.659 67.497 75.929 ;
     RECT  62.856 75.929 62.946 75.965 ;
     RECT  66.348 75.929 66.366 75.965 ;
     RECT  52.668 75.929 53.298 76.001 ;
     RECT  32.652 75.149 32.778 76.009 ;
     RECT  52.668 76.001 53.226 76.073 ;
     RECT  61.272 75.929 62.097 76.073 ;
     RECT  33.624 75.929 44.478 76.109 ;
     RECT  53.208 76.073 53.226 76.109 ;
     RECT  2.268 75.499 31.698 76.171 ;
     RECT  32.436 76.009 32.778 76.171 ;
     RECT  33.624 76.109 41.85 76.199 ;
     RECT  45.324 75.929 51.297 76.199 ;
     RECT  54.216 75.929 56.826 76.199 ;
     RECT  64.044 75.929 64.998 76.199 ;
     RECT  42.768 76.109 44.478 76.235 ;
     RECT  45.324 76.199 46.638 76.235 ;
     RECT  45.324 76.235 46.53 76.253 ;
     RECT  55.512 76.199 56.697 76.271 ;
     RECT  47.7 76.199 51.297 76.307 ;
     RECT  50.688 76.307 51.297 76.343 ;
     RECT  2.268 76.171 32.778 76.363 ;
     RECT  33.624 76.199 38.07 76.363 ;
     RECT  39.132 76.199 41.85 76.469 ;
     RECT  47.7 76.307 49.698 76.469 ;
     RECT  2.268 76.363 38.07 76.505 ;
     RECT  39.132 76.469 39.15 76.505 ;
     RECT  47.7 76.469 48.33 76.505 ;
     RECT  47.772 76.505 48.33 76.541 ;
     RECT  48.312 76.541 48.33 76.577 ;
     RECT  55.512 76.271 55.53 76.577 ;
     RECT  49.608 76.469 49.698 76.613 ;
     RECT  42.768 76.235 44.262 76.649 ;
     RECT  40.104 76.469 41.85 76.739 ;
     RECT  42.912 76.649 44.262 76.739 ;
     RECT  2.268 76.505 35.946 76.775 ;
     RECT  40.104 76.739 40.806 76.775 ;
     RECT  44.1 76.739 44.118 76.811 ;
     RECT  49.68 76.613 49.698 76.811 ;
     RECT  42.912 76.739 43.146 77.009 ;
     RECT  36.828 76.505 38.07 77.161 ;
     RECT  45.615 76.253 45.897 77.251 ;
     RECT  2.268 76.775 35.874 77.279 ;
     RECT  4.104 77.279 35.874 77.315 ;
     RECT  36.828 77.161 38.106 77.315 ;
     RECT  40.104 76.775 40.497 77.323 ;
     RECT  4.356 77.315 33.102 77.585 ;
     RECT  4.356 77.585 4.986 77.621 ;
     RECT  4.356 77.621 4.914 77.729 ;
     RECT  5.796 77.585 33.102 77.819 ;
     RECT  5.796 77.819 6.282 77.855 ;
     RECT  5.868 77.855 6.282 77.963 ;
     RECT  7.2 77.819 33.102 78.125 ;
     RECT  62.856 75.965 62.874 78.125 ;
     RECT  7.38 78.125 33.102 78.173 ;
     RECT  7.38 78.173 10.602 78.269 ;
     RECT  11.412 78.173 33.102 78.395 ;
     RECT  41.472 78.061 41.49 78.439 ;
     RECT  36.828 77.315 38.07 78.475 ;
     RECT  38.88 78.331 38.898 78.475 ;
     RECT  39.888 77.323 40.497 78.475 ;
     RECT  41.472 78.439 41.778 78.475 ;
     RECT  36.828 78.475 38.898 78.509 ;
     RECT  39.888 78.475 41.778 78.619 ;
     RECT  42.624 77.431 42.642 78.619 ;
     RECT  36.828 78.509 38.79 78.653 ;
     RECT  2.415 77.279 3.114 78.665 ;
     RECT  7.74 78.269 10.602 78.899 ;
     RECT  7.74 78.899 8.802 78.935 ;
     RECT  9.684 78.899 10.602 79.079 ;
     RECT  9.684 79.079 9.81 79.169 ;
     RECT  9.684 79.169 9.702 79.205 ;
     RECT  2.415 78.665 3.006 79.511 ;
     RECT  7.74 78.935 8.766 79.547 ;
     RECT  36.828 78.653 38.07 79.579 ;
     RECT  38.88 79.519 38.898 79.579 ;
     RECT  11.52 78.395 33.102 79.583 ;
     RECT  45.288 77.251 45.897 79.681 ;
     RECT  33.84 77.315 35.874 79.723 ;
     RECT  19.656 79.583 33.102 79.819 ;
     RECT  33.84 79.723 36.018 79.819 ;
     RECT  39.888 78.619 42.642 80.059 ;
     RECT  47.124 79.591 47.142 80.095 ;
     RECT  11.52 79.583 18.897 80.123 ;
     RECT  36.828 79.579 38.898 80.221 ;
     RECT  39.744 80.059 42.642 80.221 ;
     RECT  13.215 80.123 18.897 80.587 ;
     RECT  19.656 79.819 36.018 80.587 ;
     RECT  4.896 77.729 4.914 80.663 ;
     RECT  13.215 80.587 36.018 80.671 ;
     RECT  36.828 80.221 42.642 80.671 ;
     RECT  47.124 80.095 47.358 80.671 ;
     RECT  13.215 80.671 42.642 80.761 ;
     RECT  45.288 79.681 46.206 81.175 ;
     RECT  47.124 80.671 47.826 81.175 ;
     RECT  11.52 80.123 11.898 81.329 ;
     RECT  13.215 80.761 42.966 81.341 ;
     RECT  45.288 81.175 47.826 81.481 ;
     RECT  45.288 81.481 48.042 81.635 ;
     RECT  47.124 81.635 48.042 81.751 ;
     RECT  5.868 77.963 6.174 81.779 ;
     RECT  13.215 81.341 18.897 82.409 ;
     RECT  17.532 82.409 18.897 82.541 ;
     RECT  19.656 81.341 42.966 82.829 ;
     RECT  7.74 79.547 8.097 82.949 ;
     RECT  19.764 82.829 42.966 83.101 ;
     RECT  45.288 81.635 46.206 83.101 ;
     RECT  45.288 83.101 46.314 83.191 ;
     RECT  47.124 81.751 48.546 83.191 ;
     RECT  45.288 83.191 48.546 83.219 ;
     RECT  19.764 83.101 43.29 83.261 ;
     RECT  17.568 82.541 18.897 83.525 ;
     RECT  13.215 82.409 16.47 83.549 ;
     RECT  14.904 83.549 16.47 83.561 ;
     RECT  11.556 81.329 11.898 83.597 ;
     RECT  19.764 83.261 23.058 83.633 ;
     RECT  45.615 83.219 48.546 83.641 ;
     RECT  19.836 83.633 23.058 83.645 ;
     RECT  2.415 79.511 2.697 83.987 ;
     RECT  7.815 82.949 8.097 83.987 ;
     RECT  17.784 83.525 18.897 83.987 ;
     RECT  51.015 76.343 51.297 83.987 ;
     RECT  56.415 76.271 56.697 83.987 ;
     RECT  61.815 76.073 62.097 83.987 ;
     RECT  67.215 75.929 67.497 83.987 ;
     RECT  72.615 65.863 72.897 83.987 ;
     RECT  78.015 65.863 78.297 83.987 ;
     RECT  83.415 65.863 83.697 83.987 ;
     RECT  88.815 65.863 89.097 83.987 ;
     RECT  94.215 65.863 94.497 83.987 ;
     RECT  99.615 65.863 99.897 83.987 ;
     RECT  105.015 65.863 105.297 83.987 ;
     RECT  110.415 65.863 110.697 83.987 ;
     RECT  115.815 65.863 116.097 83.987 ;
     RECT  121.215 33.533 121.497 83.987 ;
     RECT  126.615 2.413 126.897 83.987 ;
     RECT  132.015 2.413 132.297 83.987 ;
     RECT  137.415 2.413 137.697 83.987 ;
     RECT  23.796 83.261 43.29 84.065 ;
     RECT  45.615 83.641 48.834 84.065 ;
     RECT  20.232 83.645 23.058 84.137 ;
     RECT  20.304 84.137 23.058 84.173 ;
     RECT  2.415 83.987 2.505 84.257 ;
     RECT  7.815 83.987 7.905 84.257 ;
     RECT  13.215 83.549 13.914 84.257 ;
     RECT  17.784 83.987 18.705 84.257 ;
     RECT  45.615 84.065 45.705 84.257 ;
     RECT  51.015 83.987 51.105 84.257 ;
     RECT  56.415 83.987 56.505 84.257 ;
     RECT  61.815 83.987 61.905 84.257 ;
     RECT  67.215 83.987 67.305 84.257 ;
     RECT  72.615 83.987 72.705 84.257 ;
     RECT  78.015 83.987 78.105 84.257 ;
     RECT  83.415 83.987 83.505 84.257 ;
     RECT  88.815 83.987 88.905 84.257 ;
     RECT  94.215 83.987 94.305 84.257 ;
     RECT  99.615 83.987 99.705 84.257 ;
     RECT  105.015 83.987 105.105 84.257 ;
     RECT  110.415 83.987 110.505 84.257 ;
     RECT  115.815 83.987 115.905 84.257 ;
     RECT  121.215 83.987 121.305 84.257 ;
     RECT  126.615 83.987 126.705 84.257 ;
     RECT  132.015 83.987 132.105 84.257 ;
     RECT  137.415 83.987 137.505 84.257 ;
     RECT  23.904 84.065 42.858 84.299 ;
     RECT  46.98 84.065 48.834 84.299 ;
     RECT  23.904 84.299 42.786 84.317 ;
     RECT  5.868 81.779 5.886 84.641 ;
     RECT  10.584 79.079 10.602 84.677 ;
     RECT  17.784 84.257 18.09 84.701 ;
     RECT  14.904 83.561 15.462 84.713 ;
     RECT  11.772 83.597 11.898 84.749 ;
     RECT  20.304 84.173 21.51 84.839 ;
     RECT  22.716 84.173 23.058 84.893 ;
     RECT  17.784 84.701 17.982 84.941 ;
     RECT  16.452 83.561 16.47 85.181 ;
     RECT  11.772 84.749 11.79 85.217 ;
     RECT  20.304 84.839 20.898 85.253 ;
     RECT  17.784 84.941 17.802 85.289 ;
     RECT  22.896 84.893 23.058 85.334 ;
     RECT  23.04 85.334 23.058 85.379 ;
     RECT  20.304 85.253 20.322 85.415 ;
     RECT  13.896 84.257 13.914 85.469 ;
     RECT  15.444 84.713 15.462 86.093 ;
     RECT  24.48 84.317 42.786 86.268 ;
     RECT  47.52 84.299 48.834 86.268 ;
     RECT  28.404 86.268 28.494 86.333 ;
     RECT  31.212 86.268 32.202 86.333 ;
    LAYER M4 ;
     RECT  0.133 41.52 0.156 41.544 ;
     RECT  0.156 32.256 0.745 42.792 ;
     RECT  0.745 32.256 1.105 42.84 ;
     RECT  0.156 44.064 1.105 45.096 ;
     RECT  1.105 32.256 1.181 45.096 ;
     RECT  1.465 63.504 1.501 63.528 ;
     RECT  1.357 48.768 1.573 48.792 ;
     RECT  0.529 71.184 1.645 71.208 ;
     RECT  1.573 48.144 1.957 48.792 ;
     RECT  1.181 39.024 2.113 45.096 ;
     RECT  1.645 71.184 2.293 71.496 ;
     RECT  1.669 29.28 2.365 29.304 ;
     RECT  2.113 39.024 2.365 45.192 ;
     RECT  0.817 52.032 2.401 52.776 ;
     RECT  1.681 68.736 2.401 68.76 ;
     RECT  2.293 15.024 2.408 15.048 ;
     RECT  0.997 19.824 2.408 19.848 ;
     RECT  0.781 21.984 2.408 22.008 ;
     RECT  1.093 27.072 2.408 27.096 ;
     RECT  2.365 29.28 2.408 29.352 ;
     RECT  1.181 32.256 2.408 37.944 ;
     RECT  2.365 39.024 2.408 45.48 ;
     RECT  1.957 47.856 2.408 48.792 ;
     RECT  2.401 51.024 2.408 52.776 ;
     RECT  0.781 55.44 2.408 55.464 ;
     RECT  2.401 57.6 2.408 57.624 ;
     RECT  0.961 60.672 2.408 60.696 ;
     RECT  0.493 61.728 2.408 61.752 ;
     RECT  1.501 63.504 2.408 63.624 ;
     RECT  2.401 68.64 2.408 68.76 ;
     RECT  2.293 70.32 2.408 71.496 ;
     RECT  1.093 74.304 2.408 74.328 ;
     RECT  1.669 76.464 2.408 76.488 ;
     RECT  2.408 2.148 2.512 84.252 ;
     RECT  2.512 2.418 2.704 83.982 ;
     RECT  2.704 73.776 2.801 76.488 ;
     RECT  2.704 26.736 2.819 29.352 ;
     RECT  2.704 56.784 2.867 59.352 ;
     RECT  2.704 12.864 2.963 15.384 ;
     RECT  2.819 26.736 3.017 29.208 ;
     RECT  2.704 70.32 3.053 72.36 ;
     RECT  2.704 66.672 3.059 67.512 ;
     RECT  2.704 63.6 3.161 65.592 ;
     RECT  2.704 21.408 3.203 25.272 ;
     RECT  2.963 12.864 3.305 13.848 ;
     RECT  3.203 21.408 3.413 22.776 ;
     RECT  3.413 21.408 3.485 22.728 ;
     RECT  2.801 73.776 3.485 76.392 ;
     RECT  2.963 15.024 3.697 15.384 ;
     RECT  2.704 16.512 3.697 16.968 ;
     RECT  3.053 70.32 3.697 72.024 ;
     RECT  2.704 19.92 3.733 19.944 ;
     RECT  3.485 21.408 3.733 22.68 ;
     RECT  3.733 19.92 3.769 22.68 ;
     RECT  3.059 66.672 3.769 66.984 ;
     RECT  2.704 18.24 3.781 18.264 ;
     RECT  3.017 29.184 3.781 29.208 ;
     RECT  2.704 30.384 3.781 54.12 ;
     RECT  3.769 19.392 3.845 22.68 ;
     RECT  2.704 55.152 3.913 55.56 ;
     RECT  2.867 56.88 3.913 59.352 ;
     RECT  3.203 23.856 3.925 25.272 ;
     RECT  3.017 26.736 3.925 27.864 ;
     RECT  3.697 15.024 4.021 16.968 ;
     RECT  3.697 70.272 4.021 72.024 ;
     RECT  4.021 70.272 4.025 72.936 ;
     RECT  3.305 12.864 4.057 13.656 ;
     RECT  3.781 29.184 4.057 54.12 ;
     RECT  3.913 55.152 4.057 59.352 ;
     RECT  3.769 65.856 4.117 66.984 ;
     RECT  2.704 60.672 4.129 61.896 ;
     RECT  4.129 60.672 4.165 62.568 ;
     RECT  3.161 63.6 4.165 64.872 ;
     RECT  2.704 68.64 4.165 68.808 ;
     RECT  3.925 23.856 4.201 27.864 ;
     RECT  3.781 18 4.237 18.264 ;
     RECT  3.845 19.392 4.237 22.104 ;
     RECT  4.057 12.768 4.381 13.656 ;
     RECT  4.021 14.784 4.381 16.968 ;
     RECT  4.025 70.272 4.412 71.496 ;
     RECT  4.237 18 4.457 22.104 ;
     RECT  4.057 29.184 4.525 59.352 ;
     RECT  4.117 65.856 4.525 67.56 ;
     RECT  4.165 68.64 4.525 68.904 ;
     RECT  4.525 65.856 4.549 68.904 ;
     RECT  4.412 70.032 4.549 71.496 ;
     RECT  4.381 12.768 4.633 16.968 ;
     RECT  4.457 18 4.633 18.504 ;
     RECT  4.201 23.76 4.777 27.864 ;
     RECT  4.525 29.184 4.777 59.544 ;
     RECT  4.165 60.672 4.777 64.872 ;
     RECT  3.485 74.304 4.777 76.392 ;
     RECT  2.704 11.376 4.813 11.4 ;
     RECT  4.633 12.768 4.813 18.504 ;
     RECT  4.025 72.912 4.835 72.936 ;
     RECT  4.777 23.76 4.933 28.152 ;
     RECT  4.777 29.184 4.933 64.872 ;
     RECT  4.933 23.76 4.993 64.872 ;
     RECT  4.457 19.728 5.173 22.104 ;
     RECT  4.993 23.28 5.173 64.872 ;
     RECT  4.885 77.52 5.173 77.544 ;
     RECT  4.549 65.856 5.177 71.496 ;
     RECT  5.173 19.728 5.209 64.872 ;
     RECT  5.177 65.856 5.209 66.072 ;
     RECT  5.209 19.728 5.212 66.072 ;
     RECT  5.212 19.728 5.213 49.032 ;
     RECT  4.813 11.376 5.249 18.504 ;
     RECT  5.249 13.92 5.321 18.504 ;
     RECT  4.777 74.304 5.413 76.44 ;
     RECT  5.177 67.056 5.509 71.496 ;
     RECT  5.413 74.304 5.569 76.488 ;
     RECT  5.173 77.52 5.569 77.88 ;
     RECT  5.509 67.056 5.605 71.784 ;
     RECT  5.497 10.272 5.653 10.296 ;
     RECT  5.653 9.648 5.699 10.296 ;
     RECT  5.213 19.728 5.713 48.696 ;
     RECT  5.321 18.48 5.749 18.504 ;
     RECT  5.713 19.536 5.749 48.696 ;
     RECT  5.569 74.304 5.893 77.88 ;
     RECT  5.893 74.256 6.109 77.88 ;
     RECT  5.699 9.648 6.145 9.96 ;
     RECT  5.249 11.376 6.253 12.84 ;
     RECT  5.321 13.92 6.253 17.4 ;
     RECT  5.749 18.48 6.253 48.696 ;
     RECT  5.212 50.256 6.253 66.072 ;
     RECT  5.605 67.056 6.253 72.6 ;
     RECT  6.109 73.584 6.253 77.88 ;
     RECT  6.253 11.376 6.325 17.4 ;
     RECT  6.253 18.48 6.325 66.072 ;
     RECT  6.325 11.376 6.649 66.072 ;
     RECT  6.253 67.056 6.649 77.88 ;
     RECT  6.649 11.376 6.757 77.88 ;
     RECT  6.757 11.28 7.189 77.88 ;
     RECT  6.949 4.752 7.808 4.776 ;
     RECT  6.145 9.264 7.808 9.96 ;
     RECT  7.189 11.28 7.808 78.12 ;
     RECT  3.925 82.464 7.808 82.488 ;
     RECT  3.829 84.624 7.808 84.648 ;
     RECT  7.808 2.148 8.104 84.648 ;
     RECT  8.104 9.648 8.819 78.648 ;
     RECT  8.104 8.496 9.541 8.52 ;
     RECT  8.819 9.648 9.541 78.168 ;
     RECT  8.104 3.84 9.589 4.776 ;
     RECT  8.104 6.288 9.589 6.312 ;
     RECT  9.541 8.496 9.713 78.168 ;
     RECT  9.589 3.84 10.069 6.312 ;
     RECT  9.713 8.496 10.357 78.072 ;
     RECT  8.869 1.68 10.537 1.704 ;
     RECT  10.357 7.872 10.717 78.072 ;
     RECT  10.069 3.84 11.317 6.6 ;
     RECT  10.717 7.872 11.317 78.168 ;
     RECT  11.317 3.84 12.085 78.168 ;
     RECT  12.085 3.84 12.277 78.408 ;
     RECT  8.104 82.464 12.421 82.488 ;
     RECT  8.104 84.624 12.517 84.648 ;
     RECT  10.537 1.68 13.208 2.232 ;
     RECT  12.277 3.648 13.208 78.408 ;
     RECT  11.413 79.488 13.208 79.512 ;
     RECT  12.421 82.464 13.208 82.968 ;
     RECT  12.517 84.576 13.208 84.648 ;
     RECT  13.208 1.68 13.504 84.648 ;
     RECT  13.504 3.552 13.565 78.408 ;
     RECT  13.504 81.696 13.885 84.648 ;
     RECT  13.565 3.552 14.581 78.264 ;
     RECT  13.504 79.488 14.581 79.512 ;
     RECT  13.504 80.544 14.581 80.568 ;
     RECT  14.581 3.552 14.723 80.568 ;
     RECT  13.504 1.68 14.821 2.232 ;
     RECT  14.723 3.552 14.821 78.12 ;
     RECT  13.885 81.696 15.157 85.464 ;
     RECT  14.723 79.488 15.205 80.568 ;
     RECT  15.157 81.696 15.205 86.184 ;
     RECT  14.821 1.68 15.973 78.12 ;
     RECT  15.205 79.488 15.973 86.184 ;
     RECT  15.973 1.68 16.481 86.184 ;
     RECT  16.481 1.68 18.169 78.12 ;
     RECT  16.481 79.2 18.169 86.184 ;
     RECT  18.169 1.68 20.339 86.184 ;
     RECT  20.339 1.68 21.373 22.584 ;
     RECT  20.339 23.568 21.373 86.184 ;
     RECT  21.373 1.68 22.525 86.184 ;
     RECT  22.525 1.632 22.693 86.184 ;
     RECT  22.693 1.632 22.705 86.232 ;
     RECT  22.705 0.816 23.893 86.232 ;
     RECT  23.893 0.192 25.427 86.232 ;
     RECT  25.427 0.192 26.461 0.6 ;
     RECT  26.461 0.528 26.593 0.6 ;
     RECT  25.427 1.584 26.593 86.232 ;
     RECT  26.593 0.528 26.867 86.232 ;
     RECT  26.867 0.528 27.011 0.6 ;
     RECT  27.011 0.576 27.443 0.6 ;
     RECT  26.867 1.584 27.829 86.232 ;
     RECT  27.829 1.152 28.073 86.232 ;
     RECT  28.073 1.632 29.413 86.232 ;
     RECT  29.413 1.152 29.701 86.232 ;
     RECT  29.701 0.288 30.133 86.232 ;
     RECT  30.133 0.24 30.809 86.232 ;
     RECT  30.809 0.24 31.309 0.312 ;
     RECT  31.309 0.144 34.549 0.312 ;
     RECT  30.809 1.632 34.549 86.232 ;
     RECT  34.549 0.144 35.525 86.232 ;
     RECT  35.525 0.192 39.251 86.232 ;
     RECT  39.251 0.192 40.504 85.224 ;
     RECT  40.504 0.192 40.565 76.824 ;
     RECT  40.504 80.832 40.637 85.224 ;
     RECT  40.504 77.904 40.691 79.752 ;
     RECT  40.637 80.832 40.781 84.744 ;
     RECT  40.781 82.416 40.979 84.744 ;
     RECT  40.565 0.24 41.123 76.824 ;
     RECT  39.251 86.208 41.213 86.232 ;
     RECT  40.691 78.096 41.267 79.752 ;
     RECT  40.979 82.416 41.357 82.44 ;
     RECT  41.267 78.096 41.411 79.56 ;
     RECT  41.411 78.096 41.555 79.176 ;
     RECT  41.123 0.24 41.605 76.44 ;
     RECT  40.781 80.832 41.699 81.192 ;
     RECT  40.979 83.568 42.221 84.744 ;
     RECT  42.221 83.856 42.275 84.744 ;
     RECT  41.555 78.096 42.365 79.032 ;
     RECT  42.275 83.856 42.419 83.88 ;
     RECT  42.365 78.096 42.509 78.984 ;
     RECT  42.509 78.096 42.707 78.936 ;
     RECT  41.699 81.168 42.797 81.192 ;
     RECT  41.605 0.144 42.851 76.44 ;
     RECT  42.851 65.664 42.901 76.44 ;
     RECT  42.901 65.664 42.985 76.968 ;
     RECT  42.985 65.664 43.157 76.44 ;
     RECT  42.851 0.144 44.405 64.68 ;
     RECT  43.157 65.664 44.405 76.008 ;
     RECT  44.405 0.144 44.489 76.008 ;
     RECT  44.489 65.664 45.313 76.008 ;
     RECT  45.313 65.664 45.608 76.248 ;
     RECT  42.707 78.096 45.608 78.12 ;
     RECT  45.608 65.664 45.712 84.252 ;
     RECT  44.489 0.144 45.8 64.68 ;
     RECT  45.712 65.664 45.8 83.982 ;
     RECT  45.8 0.144 45.904 83.982 ;
     RECT  45.904 65.664 46.541 76.248 ;
     RECT  46.541 65.664 47.225 76.2 ;
     RECT  47.225 69.696 49.061 76.2 ;
     RECT  47.225 65.664 49.705 68.52 ;
     RECT  49.061 69.696 49.705 76.104 ;
     RECT  49.705 65.664 51.008 76.104 ;
     RECT  45.904 78.096 51.008 78.12 ;
     RECT  51.008 65.664 51.112 84.252 ;
     RECT  45.904 0.144 51.2 64.68 ;
     RECT  51.112 65.664 51.2 83.982 ;
     RECT  51.2 0.144 51.304 83.982 ;
     RECT  51.304 0.144 51.869 76.104 ;
     RECT  51.869 0.144 52.885 7.464 ;
     RECT  51.869 8.736 52.909 76.104 ;
     RECT  52.885 0.144 53.017 7.56 ;
     RECT  52.909 8.544 53.017 76.104 ;
     RECT  53.017 0.144 53.353 76.104 ;
     RECT  53.353 8.496 53.885 76.104 ;
     RECT  53.885 70.608 54.731 76.104 ;
     RECT  53.353 0.144 54.961 7.224 ;
     RECT  53.885 8.496 54.961 69.576 ;
     RECT  54.961 0.144 55.043 69.576 ;
     RECT  55.043 8.784 55.249 69.576 ;
     RECT  54.731 70.608 55.249 76.152 ;
     RECT  55.043 0.144 56.113 7.752 ;
     RECT  55.249 8.784 56.113 76.152 ;
     RECT  56.113 0.144 56.408 76.152 ;
     RECT  51.304 78.096 56.408 78.12 ;
     RECT  56.408 0.144 56.512 84.252 ;
     RECT  56.512 0.144 56.704 83.982 ;
     RECT  56.704 0.144 58.313 75.48 ;
     RECT  58.313 0.144 60.515 75.288 ;
     RECT  60.515 0.144 60.761 66.792 ;
     RECT  60.515 67.92 61.261 75.288 ;
     RECT  60.761 0.816 61.801 66.792 ;
     RECT  61.261 67.92 61.801 75.96 ;
     RECT  61.801 0.816 61.808 75.96 ;
     RECT  56.704 78.096 61.808 78.12 ;
     RECT  61.808 0.816 61.912 84.252 ;
     RECT  61.912 0.816 62.104 83.982 ;
     RECT  62.104 0.816 62.675 74.952 ;
     RECT  62.104 78.096 62.885 78.12 ;
     RECT  62.104 75.936 62.957 75.96 ;
     RECT  62.675 73.536 63.313 74.952 ;
     RECT  62.675 0.816 63.637 72.456 ;
     RECT  63.313 73.536 63.637 75.864 ;
     RECT  63.637 0.816 63.749 75.864 ;
     RECT  63.749 0.816 64.109 64.104 ;
     RECT  64.109 0.912 64.433 64.104 ;
     RECT  63.749 65.232 64.533 75.864 ;
     RECT  64.533 65.232 64.829 74.76 ;
     RECT  64.829 66.672 65.369 74.76 ;
     RECT  65.369 66.672 65.485 74.664 ;
     RECT  65.485 66.672 65.747 74.328 ;
     RECT  65.747 71.28 65.765 74.328 ;
     RECT  65.747 66.672 65.837 69.912 ;
     RECT  65.765 71.28 65.945 74.28 ;
     RECT  65.945 71.28 65.981 74.184 ;
     RECT  64.829 65.232 66.301 65.688 ;
     RECT  65.837 66.672 66.301 69.288 ;
     RECT  65.981 71.28 66.949 73.896 ;
     RECT  64.433 0.912 66.985 63.528 ;
     RECT  64.533 75.84 67.129 75.864 ;
     RECT  66.301 65.232 67.208 69.288 ;
     RECT  66.949 71.088 67.208 73.896 ;
     RECT  67.129 75.168 67.208 75.864 ;
     RECT  67.208 65.232 67.312 84.252 ;
     RECT  67.312 65.232 67.504 83.982 ;
     RECT  66.985 0.576 67.565 63.528 ;
     RECT  67.504 65.232 67.667 66.6 ;
     RECT  67.504 71.088 67.708 75.192 ;
     RECT  67.565 1.152 67.889 63.528 ;
     RECT  67.708 71.088 67.925 73.896 ;
     RECT  67.925 71.472 68.213 73.896 ;
     RECT  67.889 1.2 68.249 63.528 ;
     RECT  67.708 75.168 68.249 75.192 ;
     RECT  67.504 68.448 68.501 69.624 ;
     RECT  68.501 68.448 68.914 69.384 ;
     RECT  68.893 71.232 69.037 71.256 ;
     RECT  68.914 68.4 69.185 69.384 ;
     RECT  69.037 70.704 69.185 71.256 ;
     RECT  68.213 72.432 69.185 73.896 ;
     RECT  69.185 68.4 69.257 69.288 ;
     RECT  69.257 68.4 69.361 69 ;
     RECT  69.185 73.872 69.437 73.896 ;
     RECT  68.249 1.68 69.445 63.528 ;
     RECT  67.667 65.664 69.493 66.6 ;
     RECT  69.361 67.776 69.493 69 ;
     RECT  69.493 65.664 69.581 69 ;
     RECT  69.581 67.248 69.617 69 ;
     RECT  69.445 1.68 69.653 63.864 ;
     RECT  69.617 67.248 70.013 67.8 ;
     RECT  70.013 67.776 70.049 67.8 ;
     RECT  69.469 74.016 70.157 74.04 ;
     RECT  69.185 70.704 70.289 70.728 ;
     RECT  70.289 70.08 70.309 70.728 ;
     RECT  70.309 70.08 70.355 71.352 ;
     RECT  69.217 72.384 70.355 72.408 ;
     RECT  69.617 68.976 70.373 69 ;
     RECT  70.355 70.08 70.373 70.104 ;
     RECT  70.355 71.328 70.396 71.352 ;
     RECT  70.117 0.192 70.645 0.216 ;
     RECT  69.653 1.68 70.645 63.528 ;
     RECT  70.645 0.192 70.949 63.528 ;
     RECT  70.949 0.192 71.123 0.216 ;
     RECT  70.949 1.2 71.489 63.528 ;
     RECT  69.581 65.664 72.608 65.688 ;
     RECT  72.608 65.664 72.712 84.252 ;
     RECT  72.712 65.664 72.8 83.982 ;
     RECT  72.8 65.598 72.904 83.982 ;
     RECT  72.904 65.664 78.008 65.688 ;
     RECT  78.008 65.664 78.112 84.252 ;
     RECT  78.112 65.664 78.2 83.982 ;
     RECT  78.2 65.598 78.304 83.982 ;
     RECT  78.304 65.664 83.408 65.688 ;
     RECT  83.408 65.664 83.512 84.252 ;
     RECT  83.512 65.664 83.6 83.982 ;
     RECT  83.6 65.598 83.704 83.982 ;
     RECT  71.489 1.68 87.113 63.528 ;
     RECT  87.113 1.68 88.081 17.784 ;
     RECT  87.113 18.96 88.081 63.528 ;
     RECT  83.704 65.664 88.808 65.688 ;
     RECT  88.808 65.664 88.912 84.252 ;
     RECT  88.912 65.664 89 83.982 ;
     RECT  89 65.598 89.104 83.982 ;
     RECT  88.081 1.68 91.901 63.528 ;
     RECT  91.901 1.68 94.208 3.096 ;
     RECT  91.901 4.368 94.208 63.528 ;
     RECT  89.104 65.664 94.208 65.688 ;
     RECT  94.208 65.664 94.312 84.252 ;
     RECT  94.312 65.664 94.4 83.982 ;
     RECT  94.208 1.68 94.504 63.528 ;
     RECT  94.4 65.598 94.504 83.982 ;
     RECT  94.504 6 94.673 9.096 ;
     RECT  94.504 1.68 95.213 3.096 ;
     RECT  95.893 9.024 95.965 9.048 ;
     RECT  95.965 9.024 96.433 9.096 ;
     RECT  96.433 9.024 96.581 9.144 ;
     RECT  96.581 9.024 96.653 9.096 ;
     RECT  96.653 9.072 97.085 9.096 ;
     RECT  95.213 3.024 97.841 3.096 ;
     RECT  94.504 10.128 98.201 63.528 ;
     RECT  98.201 16.32 98.345 63.528 ;
     RECT  98.345 18.432 98.453 63.528 ;
     RECT  98.201 10.128 98.525 15.288 ;
     RECT  95.213 1.68 99.608 1.944 ;
     RECT  97.841 3.024 99.608 3.048 ;
     RECT  94.504 4.368 99.608 4.92 ;
     RECT  94.673 6 99.608 7.944 ;
     RECT  98.525 10.128 99.608 12.024 ;
     RECT  98.525 13.008 99.608 15.288 ;
     RECT  98.345 16.32 99.608 17.448 ;
     RECT  98.453 19.056 99.608 63.528 ;
     RECT  94.504 65.664 99.608 65.688 ;
     RECT  99.608 65.664 99.712 84.252 ;
     RECT  99.712 65.664 99.8 83.982 ;
     RECT  99.608 1.68 99.904 63.528 ;
     RECT  99.8 65.598 99.904 83.982 ;
     RECT  99.904 1.68 105.008 1.944 ;
     RECT  99.904 3.024 105.008 3.048 ;
     RECT  99.904 4.368 105.008 4.92 ;
     RECT  99.904 6 105.008 7.944 ;
     RECT  99.904 10.128 105.008 12.024 ;
     RECT  99.904 13.392 105.008 15.288 ;
     RECT  99.904 16.32 105.008 16.344 ;
     RECT  99.904 17.328 105.008 17.352 ;
     RECT  99.904 19.056 105.008 63.528 ;
     RECT  99.904 65.664 105.008 65.688 ;
     RECT  105.008 65.664 105.112 84.252 ;
     RECT  105.112 65.664 105.2 83.982 ;
     RECT  105.008 1.68 105.304 63.528 ;
     RECT  105.2 65.598 105.304 83.982 ;
     RECT  105.304 1.68 110.408 1.944 ;
     RECT  105.304 3.024 110.408 3.048 ;
     RECT  105.304 4.368 110.408 4.92 ;
     RECT  105.304 6 110.408 7.944 ;
     RECT  105.304 10.128 110.408 12.024 ;
     RECT  105.304 13.392 110.408 15.288 ;
     RECT  105.304 16.32 110.408 16.344 ;
     RECT  105.304 17.328 110.408 17.352 ;
     RECT  105.304 19.056 110.408 63.528 ;
     RECT  105.304 65.664 110.408 65.688 ;
     RECT  110.408 65.664 110.512 84.252 ;
     RECT  110.512 65.664 110.6 83.982 ;
     RECT  110.408 1.68 110.704 63.528 ;
     RECT  110.6 65.598 110.704 83.982 ;
     RECT  110.704 4.368 114.577 4.92 ;
     RECT  110.704 17.328 114.577 17.352 ;
     RECT  114.577 4.368 114.617 5.016 ;
     RECT  114.577 17.328 114.617 17.448 ;
     RECT  110.704 1.68 115.808 1.944 ;
     RECT  110.704 3.024 115.808 3.048 ;
     RECT  114.617 4.416 115.808 5.016 ;
     RECT  110.704 6 115.808 7.944 ;
     RECT  110.704 10.128 115.808 12.024 ;
     RECT  110.704 13.392 115.808 15.288 ;
     RECT  110.704 16.32 115.808 16.344 ;
     RECT  114.617 17.424 115.808 17.448 ;
     RECT  110.704 19.056 115.808 63.528 ;
     RECT  110.704 65.664 115.808 65.688 ;
     RECT  115.808 65.664 115.912 84.252 ;
     RECT  115.912 65.664 116 83.982 ;
     RECT  115.808 1.68 116.104 63.528 ;
     RECT  116 65.598 116.104 83.982 ;
     RECT  116.104 13.392 117.011 15.288 ;
     RECT  116.104 19.056 117.216 63.528 ;
     RECT  117.216 19.056 117.425 62.424 ;
     RECT  117.425 47.328 117.461 62.424 ;
     RECT  117.425 19.056 117.491 39.96 ;
     RECT  117.491 19.824 117.539 39.96 ;
     RECT  116.104 10.128 117.605 12.024 ;
     RECT  117.605 10.128 117.635 11.544 ;
     RECT  117.539 20.064 117.749 39.96 ;
     RECT  117.749 20.064 117.779 27.384 ;
     RECT  116.104 4.416 118.067 5.016 ;
     RECT  117.011 13.392 118.115 15.24 ;
     RECT  116.104 3.024 118.259 3.048 ;
     RECT  117.749 28.704 118.469 39.96 ;
     RECT  117.461 47.328 118.613 56.952 ;
     RECT  117.779 20.064 118.643 22.2 ;
     RECT  117.461 58.08 118.649 59.352 ;
     RECT  117.635 11.136 118.691 11.544 ;
     RECT  117.425 41.568 118.721 45.624 ;
     RECT  118.643 20.064 118.739 22.152 ;
     RECT  118.739 20.304 118.787 22.152 ;
     RECT  118.067 4.416 118.835 4.488 ;
     RECT  118.469 30.624 118.835 39.96 ;
     RECT  118.835 30.624 118.865 31.32 ;
     RECT  118.835 4.464 118.931 4.488 ;
     RECT  116.104 17.424 118.937 17.448 ;
     RECT  118.835 32.352 119.117 39.96 ;
     RECT  118.721 41.568 119.117 44.664 ;
     RECT  118.613 47.424 119.117 56.952 ;
     RECT  119.117 32.352 119.153 36.408 ;
     RECT  119.117 50.592 119.153 52.44 ;
     RECT  119.117 53.664 119.153 56.952 ;
     RECT  118.787 20.304 119.171 21.576 ;
     RECT  118.115 14.496 119.267 15.24 ;
     RECT  119.153 50.88 119.297 52.44 ;
     RECT  118.649 58.08 119.297 58.968 ;
     RECT  118.691 11.52 119.315 11.544 ;
     RECT  116.104 6 119.363 7.944 ;
     RECT  119.297 52.224 119.405 52.44 ;
     RECT  119.153 32.352 119.513 34.584 ;
     RECT  119.117 41.568 119.549 42.744 ;
     RECT  119.297 50.88 119.549 50.904 ;
     RECT  119.297 58.944 119.549 58.968 ;
     RECT  117.461 60.384 119.549 62.424 ;
     RECT  119.153 55.104 119.585 56.952 ;
     RECT  119.153 35.712 119.621 36.408 ;
     RECT  119.585 55.104 119.621 55.704 ;
     RECT  119.549 60.384 119.621 62.136 ;
     RECT  119.621 36.384 119.657 36.408 ;
     RECT  119.549 42.144 119.657 42.744 ;
     RECT  119.405 52.416 119.657 52.44 ;
     RECT  119.621 55.488 119.657 55.704 ;
     RECT  119.585 56.928 119.657 56.952 ;
     RECT  119.621 60.384 119.657 62.04 ;
     RECT  119.657 55.68 119.693 55.704 ;
     RECT  118.469 28.704 119.729 29.112 ;
     RECT  117.779 23.232 119.765 27.384 ;
     RECT  119.171 20.784 119.795 21.576 ;
     RECT  119.765 23.328 119.795 27.384 ;
     RECT  119.513 33.504 119.801 34.584 ;
     RECT  119.801 34.56 119.873 34.584 ;
     RECT  116.104 1.68 119.891 1.944 ;
     RECT  117.635 10.128 119.909 10.152 ;
     RECT  119.657 42.72 119.945 42.744 ;
     RECT  119.267 14.496 119.981 14.52 ;
     RECT  118.865 30.624 119.981 31.032 ;
     RECT  119.795 23.328 120.053 27.288 ;
     RECT  119.513 32.352 120.125 32.376 ;
     RECT  119.153 53.664 120.161 53.688 ;
     RECT  119.891 1.92 120.467 1.944 ;
     RECT  119.363 6.096 121.208 7.944 ;
     RECT  118.115 13.392 121.208 13.416 ;
     RECT  116.104 16.32 121.208 16.344 ;
     RECT  119.795 20.832 121.208 21.576 ;
     RECT  120.053 23.328 121.208 27.192 ;
     RECT  119.729 28.8 121.208 29.112 ;
     RECT  119.981 30.72 121.208 31.032 ;
     RECT  119.801 33.504 121.208 33.528 ;
     RECT  116.104 65.664 121.208 65.688 ;
     RECT  121.208 2.148 121.312 84.252 ;
     RECT  121.312 2.418 121.504 83.982 ;
     RECT  121.504 6.096 121.565 6.12 ;
     RECT  121.504 26.112 121.565 26.136 ;
     RECT  121.504 7.152 121.601 7.176 ;
     RECT  121.504 13.392 121.637 13.416 ;
     RECT  121.504 24.576 121.709 24.744 ;
     RECT  121.504 65.664 126.608 65.688 ;
     RECT  126.608 2.148 126.712 84.252 ;
     RECT  126.712 2.418 126.904 83.982 ;
     RECT  126.904 65.664 132.008 65.688 ;
     RECT  132.008 2.148 132.112 84.252 ;
     RECT  132.112 2.418 132.304 83.982 ;
     RECT  132.304 65.664 137.408 65.688 ;
     RECT  137.408 2.148 137.512 84.252 ;
     RECT  137.512 2.418 137.704 83.982 ;
     RECT  137.704 65.664 139.637 65.688 ;
    LAYER M5 ;
     RECT  70.512 0.144 71.112 0.227 ;
     RECT  24.528 0.144 61.272 0.467 ;
     RECT  42.24 0.467 61.272 0.803 ;
     RECT  66.576 0.144 67.896 1.187 ;
     RECT  43.824 0.803 61.272 1.235 ;
     RECT  66.72 1.187 67.896 1.235 ;
     RECT  70.512 0.227 70.968 1.235 ;
     RECT  49.152 1.235 61.272 1.331 ;
     RECT  24.528 0.467 41.256 1.427 ;
     RECT  24.528 1.427 41.112 1.763 ;
     RECT  49.296 1.331 61.272 1.763 ;
     RECT  66.864 1.235 67.896 1.763 ;
     RECT  70.512 1.235 70.824 1.763 ;
     RECT  66.864 1.763 67.752 1.811 ;
     RECT  42.24 0.803 42.552 1.859 ;
     RECT  67.152 1.811 67.752 1.859 ;
     RECT  27.984 1.763 41.112 1.907 ;
     RECT  119.856 1.669 119.88 1.909 ;
     RECT  68.928 1.813 68.952 1.955 ;
     RECT  8.88 1.669 8.904 2.137 ;
     RECT  24.528 1.763 26.712 2.137 ;
     RECT  53.328 1.763 61.272 2.137 ;
     RECT  119.856 1.909 120.456 2.137 ;
     RECT  2.4 2.137 2.52 2.151 ;
     RECT  13.2 2.137 13.32 2.151 ;
     RECT  18.6 2.137 18.72 2.151 ;
     RECT  53.328 2.137 61.92 2.151 ;
     RECT  72.6 2.137 72.72 2.151 ;
     RECT  78 2.137 78.12 2.151 ;
     RECT  83.4 2.137 83.52 2.151 ;
     RECT  88.8 2.137 88.92 2.151 ;
     RECT  94.2 2.137 94.32 2.151 ;
     RECT  99.6 2.137 99.72 2.151 ;
     RECT  105 2.137 105.12 2.151 ;
     RECT  110.4 2.137 110.52 2.151 ;
     RECT  115.8 2.137 115.92 2.151 ;
     RECT  119.856 2.137 121.32 2.151 ;
     RECT  126.6 2.137 126.72 2.151 ;
     RECT  132 2.137 132.12 2.151 ;
     RECT  137.4 2.137 137.52 2.151 ;
     RECT  24 2.137 26.712 2.243 ;
     RECT  24 2.243 26.568 2.291 ;
     RECT  27.984 1.907 33.768 2.291 ;
     RECT  49.296 1.763 52.344 2.291 ;
     RECT  43.824 1.235 47.88 2.339 ;
     RECT  45.024 2.339 47.88 2.437 ;
     RECT  45.024 2.437 47.976 2.483 ;
     RECT  53.328 2.151 62.112 2.531 ;
     RECT  49.296 2.291 51.48 2.579 ;
     RECT  45.408 2.483 47.976 2.675 ;
     RECT  42.384 1.859 42.552 2.677 ;
     RECT  43.68 2.629 43.704 2.677 ;
     RECT  34.8 1.907 41.112 2.725 ;
     RECT  49.296 2.579 51.312 2.725 ;
     RECT  48.912 2.725 51.312 2.819 ;
     RECT  60.96 2.531 62.112 2.819 ;
     RECT  48.912 2.819 49.032 2.867 ;
     RECT  50.016 2.819 51.312 2.867 ;
     RECT  24 2.291 24.84 2.915 ;
     RECT  70.8 1.763 70.824 2.915 ;
     RECT  53.328 2.531 59.976 2.963 ;
     RECT  48.912 2.867 48.936 3.011 ;
     RECT  67.2 1.859 67.752 3.061 ;
     RECT  53.856 2.963 57.528 3.107 ;
     RECT  45.408 2.675 47.736 3.347 ;
     RECT  66.72 3.061 67.752 3.347 ;
     RECT  28.128 2.291 33.576 3.349 ;
     RECT  34.8 2.725 41.256 3.349 ;
     RECT  28.128 3.349 41.256 3.395 ;
     RECT  38.784 3.395 41.256 3.491 ;
     RECT  45.408 3.347 47.304 3.541 ;
     RECT  65.04 3.397 65.064 3.587 ;
     RECT  42.384 2.677 43.704 3.589 ;
     RECT  44.736 3.541 47.304 3.589 ;
     RECT  13.2 2.151 13.512 3.637 ;
     RECT  38.784 3.491 41.064 3.731 ;
     RECT  42.384 3.589 47.304 3.731 ;
     RECT  42.384 3.731 43.464 3.875 ;
     RECT  14.832 3.013 14.856 3.877 ;
     RECT  44.736 3.731 47.304 3.923 ;
     RECT  28.128 3.395 37.8 4.019 ;
     RECT  50.16 2.867 51.312 4.019 ;
     RECT  58.8 2.963 59.976 4.019 ;
     RECT  67.2 3.347 67.752 4.019 ;
     RECT  53.904 3.107 57.528 4.067 ;
     RECT  59.808 4.019 59.976 4.067 ;
     RECT  26.448 3.253 26.472 4.069 ;
     RECT  59.952 4.067 59.976 4.115 ;
     RECT  53.904 4.067 56.712 4.117 ;
     RECT  53.664 4.117 56.712 4.259 ;
     RECT  18.6 2.151 18.912 4.261 ;
     RECT  52.512 3.301 52.536 4.261 ;
     RECT  63.456 4.117 63.48 4.307 ;
     RECT  12.288 3.637 13.512 4.357 ;
     RECT  14.592 3.877 14.856 4.357 ;
     RECT  18.6 4.261 19.896 4.405 ;
     RECT  22.56 3.349 22.584 4.405 ;
     RECT  72.6 2.151 72.912 4.405 ;
     RECT  118.224 3.013 118.248 4.405 ;
     RECT  26.448 4.069 26.808 4.451 ;
     RECT  118.224 4.405 118.824 4.453 ;
     RECT  119.856 2.151 121.512 4.453 ;
     RECT  22.08 4.405 22.584 4.501 ;
     RECT  26.448 4.451 26.472 4.549 ;
     RECT  54.336 4.259 56.712 4.595 ;
     RECT  54.48 4.595 56.712 4.643 ;
     RECT  18.6 4.405 20.52 4.645 ;
     RECT  21.936 4.501 22.584 4.645 ;
     RECT  61.8 2.819 62.112 4.645 ;
     RECT  38.88 3.731 41.064 4.691 ;
     RECT  50.736 4.019 51.312 4.691 ;
     RECT  16.224 2.485 16.248 4.693 ;
     RECT  25.536 4.549 26.472 4.739 ;
     RECT  7.8 2.137 8.904 4.741 ;
     RECT  28.128 4.019 37.656 4.789 ;
     RECT  42.384 3.875 43.176 4.835 ;
     RECT  45.024 3.923 47.304 4.885 ;
     RECT  61.8 4.645 63.144 4.979 ;
     RECT  118.224 4.453 121.512 4.981 ;
     RECT  27.888 4.789 37.656 5.027 ;
     RECT  44.64 4.885 47.304 5.027 ;
     RECT  67.2 4.019 67.512 5.077 ;
     RECT  44.928 5.027 47.304 5.123 ;
     RECT  28.128 5.027 37.656 5.171 ;
     RECT  58.8 4.019 58.824 5.171 ;
     RECT  10.56 2.197 10.584 5.173 ;
     RECT  12.288 4.357 14.856 5.173 ;
     RECT  50.784 4.691 51.312 5.219 ;
     RECT  15.84 4.693 16.248 5.221 ;
     RECT  17.568 4.981 17.592 5.221 ;
     RECT  33.024 5.171 37.656 5.221 ;
     RECT  18.6 4.645 22.584 5.269 ;
     RECT  49.008 5.125 49.032 5.315 ;
     RECT  40.2 4.691 41.064 5.317 ;
     RECT  33.024 5.221 37.8 5.363 ;
     RECT  40.2 5.317 41.304 5.459 ;
     RECT  42.384 4.835 42.888 5.509 ;
     RECT  18.6 5.269 22.824 5.603 ;
     RECT  26.016 4.739 26.472 5.603 ;
     RECT  44.928 5.123 47.16 5.651 ;
     RECT  6.96 4.741 8.904 5.653 ;
     RECT  10.56 5.173 14.856 5.653 ;
     RECT  44.976 5.651 47.16 5.699 ;
     RECT  6.96 5.653 14.856 5.701 ;
     RECT  15.84 5.221 17.592 5.701 ;
     RECT  28.416 5.171 31.752 5.747 ;
     RECT  40.2 5.459 41.064 5.747 ;
     RECT  47.136 5.699 47.16 5.747 ;
     RECT  54.768 4.643 56.712 5.747 ;
     RECT  28.416 5.747 30.888 5.795 ;
     RECT  52.512 4.261 52.92 5.795 ;
     RECT  38.88 4.691 39.096 5.843 ;
     RECT  42.096 5.509 42.888 5.939 ;
     RECT  44.976 5.699 46.104 5.987 ;
     RECT  67.2 5.077 68.328 5.989 ;
     RECT  42.384 5.939 42.552 6.035 ;
     RECT  55.104 5.747 56.712 6.037 ;
     RECT  94.2 2.151 94.512 6.085 ;
     RECT  28.416 5.795 29.928 6.131 ;
     RECT  52.896 5.795 52.92 6.133 ;
     RECT  44.976 5.987 46.008 6.227 ;
     RECT  48.384 5.749 48.408 6.227 ;
     RECT  28.704 6.131 29.928 6.323 ;
     RECT  55.104 6.037 57.288 6.323 ;
     RECT  6.96 5.701 17.592 6.325 ;
     RECT  18.6 5.603 22.632 6.325 ;
     RECT  42.384 6.035 42.408 6.371 ;
     RECT  76.224 5.077 76.248 6.373 ;
     RECT  28.848 6.323 29.928 6.419 ;
     RECT  67.2 5.989 68.376 6.421 ;
     RECT  45.024 6.227 46.008 6.467 ;
     RECT  45.024 6.467 45.912 6.611 ;
     RECT  67.2 6.421 69 6.611 ;
     RECT  76.224 6.373 76.968 6.709 ;
     RECT  78 2.151 78.312 6.709 ;
     RECT  87.216 6.661 87.672 6.803 ;
     RECT  33.024 5.363 37.656 6.805 ;
     RECT  38.88 5.843 38.904 6.805 ;
     RECT  70.608 6.229 70.632 6.805 ;
     RECT  6.96 6.325 22.632 6.853 ;
     RECT  64.896 6.661 64.92 6.853 ;
     RECT  87.216 6.803 87.24 6.853 ;
     RECT  64.896 6.853 65.016 6.899 ;
     RECT  76.224 6.709 78.888 6.899 ;
     RECT  29.4 6.419 29.928 6.901 ;
     RECT  86.928 6.853 87.24 6.995 ;
     RECT  115.8 2.151 116.112 7.093 ;
     RECT  79.92 6.133 79.944 7.235 ;
     RECT  76.224 6.899 76.968 7.379 ;
     RECT  72.432 4.405 72.912 7.381 ;
     RECT  83.4 2.151 83.712 7.381 ;
     RECT  83.28 7.381 83.712 7.429 ;
     RECT  52.896 6.133 53.016 7.571 ;
     RECT  64.992 6.899 65.016 7.571 ;
     RECT  6.96 6.853 22.824 7.667 ;
     RECT  45.504 6.611 45.912 7.667 ;
     RECT  85.872 7.237 85.896 7.667 ;
     RECT  90.192 6.805 90.216 7.667 ;
     RECT  61.8 4.979 63.096 7.717 ;
     RECT  87.216 6.995 87.24 7.813 ;
     RECT  83.28 7.429 83.928 7.859 ;
     RECT  52.992 7.571 53.016 7.861 ;
     RECT  70.608 6.805 70.968 7.907 ;
     RECT  87.216 7.813 87.384 7.955 ;
     RECT  26.448 5.603 26.472 7.957 ;
     RECT  45.6 7.667 45.912 8.197 ;
     RECT  76.224 7.379 76.872 8.341 ;
     RECT  29.4 6.901 30.024 8.387 ;
     RECT  61.536 7.717 63.096 8.389 ;
     RECT  24 2.915 24.312 8.437 ;
     RECT  76.224 8.341 76.92 8.437 ;
     RECT  47.856 7.909 47.88 8.531 ;
     RECT  67.2 6.611 68.328 8.533 ;
     RECT  87.216 7.955 87.24 8.533 ;
     RECT  55.104 6.323 55.128 8.629 ;
     RECT  70.944 7.907 70.968 8.629 ;
     RECT  72.432 7.381 73.032 8.629 ;
     RECT  78 6.899 78.744 8.675 ;
     RECT  86.448 8.533 87.24 8.675 ;
     RECT  51 5.219 51.312 8.677 ;
     RECT  65.808 7.957 65.832 8.677 ;
     RECT  70.944 8.629 73.032 8.771 ;
     RECT  61.536 8.389 63.288 8.773 ;
     RECT  67.2 8.533 68.568 8.819 ;
     RECT  72.384 8.771 73.032 8.821 ;
     RECT  76.224 8.437 76.968 8.821 ;
     RECT  78 8.675 78.696 8.821 ;
     RECT  80.832 8.245 80.856 8.821 ;
     RECT  65.712 8.677 65.832 8.917 ;
     RECT  61.536 8.773 63.768 8.963 ;
     RECT  55.008 8.629 55.128 8.965 ;
     RECT  65.232 8.917 65.832 8.965 ;
     RECT  94.08 6.085 94.512 8.965 ;
     RECT  76.224 8.821 78.696 9.011 ;
     RECT  24 8.437 24.552 9.013 ;
     RECT  26.448 7.957 26.808 9.059 ;
     RECT  49.008 8.773 49.032 9.059 ;
     RECT  61.536 8.963 63.624 9.059 ;
     RECT  40.2 5.747 40.512 9.061 ;
     RECT  54.576 8.965 55.128 9.061 ;
     RECT  56.208 6.323 57.288 9.061 ;
     RECT  94.08 8.965 94.632 9.107 ;
     RECT  80.832 8.821 81.144 9.155 ;
     RECT  52.992 7.861 53.304 9.157 ;
     RECT  65.232 8.965 65.928 9.203 ;
     RECT  87.072 8.675 87.24 9.347 ;
     RECT  54.576 9.061 57.288 9.349 ;
     RECT  70.944 8.771 70.968 9.395 ;
     RECT  33.024 6.805 38.904 9.397 ;
     RECT  51 8.677 51.48 9.397 ;
     RECT  72.384 8.821 73.08 9.397 ;
     RECT  45.6 8.197 46.008 9.539 ;
     RECT  67.2 8.819 68.328 9.539 ;
     RECT  83.28 7.859 83.712 9.635 ;
     RECT  91.296 8.485 91.32 9.637 ;
     RECT  54.576 9.349 57.384 9.731 ;
     RECT  87.216 9.347 87.24 9.731 ;
     RECT  65.232 9.203 65.832 9.733 ;
     RECT  40.2 9.061 41.064 9.827 ;
     RECT  80.832 9.155 80.952 9.827 ;
     RECT  64.944 9.733 65.832 9.923 ;
     RECT  77.904 9.011 78.696 9.923 ;
     RECT  23.904 9.013 24.552 9.925 ;
     RECT  80.928 9.827 80.952 9.971 ;
     RECT  28.224 9.925 28.248 9.973 ;
     RECT  29.4 8.387 29.928 9.973 ;
     RECT  43.776 8.485 43.8 9.973 ;
     RECT  43.776 9.973 44.136 10.117 ;
     RECT  45.6 9.539 45.912 10.117 ;
     RECT  51 9.397 51.864 10.213 ;
     RECT  52.896 9.157 53.304 10.213 ;
     RECT  23.904 9.925 25.128 10.259 ;
     RECT  43.776 10.117 45.912 10.259 ;
     RECT  5.664 9.637 5.688 10.307 ;
     RECT  76.224 9.011 76.92 10.307 ;
     RECT  43.776 10.259 43.8 10.355 ;
     RECT  72.384 9.397 73.224 10.451 ;
     RECT  28.224 9.973 29.928 10.501 ;
     RECT  65.712 9.923 65.832 10.547 ;
     RECT  48.48 9.925 48.504 10.595 ;
     RECT  88.8 2.151 89.112 10.597 ;
     RECT  115.8 7.093 117.048 10.693 ;
     RECT  118.032 4.981 121.512 10.693 ;
     RECT  61.536 9.059 63.096 10.739 ;
     RECT  72.432 10.451 73.224 10.789 ;
     RECT  84.768 7.957 84.792 10.789 ;
     RECT  85.968 8.869 85.992 10.789 ;
     RECT  33.024 9.397 39 10.883 ;
     RECT  90.72 9.637 91.32 10.883 ;
     RECT  72.432 10.789 73.752 11.075 ;
     RECT  40.2 9.827 40.512 11.125 ;
     RECT  41.808 10.309 41.832 11.125 ;
     RECT  40.2 11.125 41.832 11.171 ;
     RECT  6.96 7.667 22.728 11.269 ;
     RECT  67.2 9.539 67.512 11.269 ;
     RECT  23.904 10.259 24.312 11.413 ;
     RECT  99.6 2.151 99.912 11.413 ;
     RECT  72.432 11.075 72.912 11.459 ;
     RECT  61.632 10.739 63.096 11.509 ;
     RECT  84.768 10.789 85.992 11.509 ;
     RECT  23.904 11.413 25.128 11.555 ;
     RECT  61.632 11.509 63.336 11.651 ;
     RECT  84.768 11.509 86.952 11.651 ;
     RECT  44.976 10.259 45.912 11.653 ;
     RECT  47.424 11.413 47.448 11.699 ;
     RECT  84.768 11.651 86.856 11.795 ;
     RECT  27.552 10.501 29.928 11.893 ;
     RECT  92.736 11.461 92.76 11.893 ;
     RECT  94.08 9.107 94.512 11.893 ;
     RECT  27.552 11.893 30.792 11.939 ;
     RECT  88.8 10.597 89.544 11.939 ;
     RECT  48.96 11.317 48.984 12.035 ;
     RECT  54.576 9.731 55.128 12.035 ;
     RECT  44.448 11.653 45.912 12.133 ;
     RECT  67.2 11.269 67.704 12.227 ;
     RECT  51 10.213 53.304 12.229 ;
     RECT  76.224 10.307 76.248 12.229 ;
     RECT  85.968 11.795 86.856 12.371 ;
     RECT  31.776 12.277 31.8 12.419 ;
     RECT  76.224 12.229 76.536 12.419 ;
     RECT  92.736 11.893 94.512 12.419 ;
     RECT  44.448 12.133 46.056 12.467 ;
     RECT  61.632 11.651 63.24 12.517 ;
     RECT  65.808 10.547 65.832 12.517 ;
     RECT  67.2 12.227 67.656 12.517 ;
     RECT  77.904 9.923 78.312 12.517 ;
     RECT  91.296 10.883 91.32 12.517 ;
     RECT  91.296 12.517 91.464 12.563 ;
     RECT  84.768 11.795 84.984 12.611 ;
     RECT  23.904 11.555 24.552 12.613 ;
     RECT  50.736 12.229 53.304 12.707 ;
     RECT  60.864 12.517 63.24 12.707 ;
     RECT  68.928 12.565 68.952 12.707 ;
     RECT  55.104 12.035 55.128 12.709 ;
     RECT  56.208 9.731 57.384 12.709 ;
     RECT  28.416 11.939 30.792 12.755 ;
     RECT  81.12 11.365 81.144 12.755 ;
     RECT  6.768 11.269 22.728 12.757 ;
     RECT  23.904 12.613 25.224 12.803 ;
     RECT  77.472 12.517 79.272 12.805 ;
     RECT  6.144 12.757 22.728 12.851 ;
     RECT  92.736 12.419 92.952 12.853 ;
     RECT  28.416 12.755 29.928 12.901 ;
     RECT  77.472 12.805 79.848 12.947 ;
     RECT  28.272 12.901 29.928 12.949 ;
     RECT  76.224 12.419 76.344 13.043 ;
     RECT  98.88 11.413 99.912 13.043 ;
     RECT  76.224 13.043 76.248 13.045 ;
     RECT  77.472 12.947 79.752 13.091 ;
     RECT  33.024 10.883 38.808 13.093 ;
     RECT  86.832 12.371 86.856 13.139 ;
     RECT  94.08 12.419 94.512 13.141 ;
     RECT  40.2 11.171 41.304 13.331 ;
     RECT  94.08 13.141 95.496 13.331 ;
     RECT  84.768 12.611 84.792 13.379 ;
     RECT  23.904 12.803 24.6 13.427 ;
     RECT  92.544 12.853 92.952 13.429 ;
     RECT  94.08 13.331 94.512 13.429 ;
     RECT  98.4 13.141 98.424 13.523 ;
     RECT  92.544 13.429 94.512 13.525 ;
     RECT  55.104 12.709 57.384 13.621 ;
     RECT  77.904 13.091 79.32 13.667 ;
     RECT  61.632 12.707 63.24 13.715 ;
     RECT  75.792 13.045 76.248 13.715 ;
     RECT  95.712 13.621 95.736 13.763 ;
     RECT  2.4 2.151 2.712 13.813 ;
     RECT  50.88 12.707 53.304 14.099 ;
     RECT  42.72 11.317 42.792 14.101 ;
     RECT  52.992 14.099 53.304 14.101 ;
     RECT  42.72 14.101 43.032 14.147 ;
     RECT  42.768 14.147 43.032 14.243 ;
     RECT  52.992 14.101 53.688 14.243 ;
     RECT  97.392 10.213 97.416 14.245 ;
     RECT  69.936 12.997 69.96 14.291 ;
     RECT  78 13.667 79.32 14.291 ;
     RECT  97.152 14.245 97.416 14.291 ;
     RECT  2.4 13.813 2.952 14.339 ;
     RECT  71.28 13.621 71.304 14.339 ;
     RECT  40.2 13.331 41.016 14.389 ;
     RECT  44.448 12.467 45.912 14.389 ;
     RECT  44.304 14.389 45.912 14.531 ;
     RECT  61.632 13.715 63.096 14.531 ;
     RECT  74.064 14.101 74.088 14.533 ;
     RECT  91.44 12.563 91.464 14.533 ;
     RECT  92.496 13.525 94.512 14.533 ;
     RECT  27.744 12.949 29.928 14.579 ;
     RECT  71.376 14.533 71.4 14.675 ;
     RECT  74.064 14.533 74.76 14.675 ;
     RECT  75.84 13.715 76.248 14.677 ;
     RECT  91.44 14.533 94.512 14.723 ;
     RECT  54.768 13.621 57.384 14.773 ;
     RECT  79.296 14.291 79.32 14.773 ;
     RECT  49.728 14.677 49.752 14.819 ;
     RECT  52.992 14.243 53.304 14.867 ;
     RECT  50.88 14.099 51.312 14.869 ;
     RECT  75.072 14.677 76.296 14.917 ;
     RECT  61.8 14.531 63.096 14.965 ;
     RECT  26.448 9.059 26.472 15.013 ;
     RECT  75.072 14.917 76.344 15.059 ;
     RECT  72.6 11.459 72.912 15.061 ;
     RECT  74.064 14.675 74.088 15.061 ;
     RECT  72.6 15.061 74.088 15.107 ;
     RECT  26.112 15.013 26.808 15.155 ;
     RECT  40.08 14.389 41.016 15.157 ;
     RECT  92.736 14.723 94.512 15.203 ;
     RECT  26.112 15.155 26.472 15.251 ;
     RECT  40.08 15.157 41.256 15.251 ;
     RECT  42.768 14.243 42.84 15.253 ;
     RECT  83.4 9.635 83.712 15.253 ;
     RECT  50.832 14.869 51.312 15.301 ;
     RECT  88.8 11.939 89.112 15.301 ;
     RECT  86.064 14.485 86.088 15.347 ;
     RECT  2.4 14.339 2.712 15.349 ;
     RECT  4.032 14.773 4.056 15.349 ;
     RECT  78 14.291 78.312 15.349 ;
     RECT  79.296 14.773 79.704 15.349 ;
     RECT  42.768 15.253 43.272 15.395 ;
     RECT  65.808 12.517 67.656 15.397 ;
     RECT  61.8 14.965 63.816 15.443 ;
     RECT  27.792 14.579 29.928 15.445 ;
     RECT  33.024 13.093 38.904 15.445 ;
     RECT  40.2 15.251 41.256 15.491 ;
     RECT  50.832 15.301 51.432 15.493 ;
     RECT  52.992 14.867 53.16 15.493 ;
     RECT  26.352 15.251 26.472 15.635 ;
     RECT  94.08 15.203 94.512 15.781 ;
     RECT  83.28 15.253 83.712 15.827 ;
     RECT  69.312 15.061 69.336 15.925 ;
     RECT  91.44 14.723 91.464 15.925 ;
     RECT  88.32 15.301 89.112 15.971 ;
     RECT  97.152 14.291 97.176 16.019 ;
     RECT  23.904 13.427 24.312 16.021 ;
     RECT  90.624 15.925 91.464 16.069 ;
     RECT  92.448 15.925 92.472 16.069 ;
     RECT  32.16 15.445 38.904 16.259 ;
     RECT  47.328 15.397 47.352 16.259 ;
     RECT  49.536 15.349 49.56 16.259 ;
     RECT  54.48 14.773 57.384 16.259 ;
     RECT  82.128 15.349 82.152 16.259 ;
     RECT  90.624 16.069 92.472 16.259 ;
     RECT  6.144 12.851 22.632 16.261 ;
     RECT  23.904 16.021 24.744 16.261 ;
     RECT  64.944 15.397 67.656 16.405 ;
     RECT  68.976 15.925 69.336 16.405 ;
     RECT  50.832 15.493 53.16 16.453 ;
     RECT  2.4 15.349 2.856 16.501 ;
     RECT  4.032 15.349 5.016 16.501 ;
     RECT  27.792 15.445 30.6 16.501 ;
     RECT  54.672 16.259 57.384 16.547 ;
     RECT  44.448 14.531 45.912 16.549 ;
     RECT  48.432 16.501 48.456 16.597 ;
     RECT  61.8 15.443 63.24 16.597 ;
     RECT  64.416 16.405 69.336 16.597 ;
     RECT  47.76 16.597 48.456 16.645 ;
     RECT  60.576 14.389 60.6 16.645 ;
     RECT  61.8 16.597 69.336 16.645 ;
     RECT  42.768 15.395 42.84 16.693 ;
     RECT  43.824 16.549 45.912 16.693 ;
     RECT  91.44 16.259 92.472 16.693 ;
     RECT  94.08 15.781 95.448 16.693 ;
     RECT  72.6 15.107 73.56 16.741 ;
     RECT  27.504 16.501 30.6 16.787 ;
     RECT  60.576 16.645 69.336 16.787 ;
     RECT  2.4 16.501 5.016 16.789 ;
     RECT  6.144 16.261 24.744 16.789 ;
     RECT  32.304 16.259 38.904 16.883 ;
     RECT  64.272 16.787 69.336 16.883 ;
     RECT  72.096 16.741 73.56 16.883 ;
     RECT  91.44 16.693 95.448 16.883 ;
     RECT  94.08 16.883 95.448 16.931 ;
     RECT  69.072 16.883 69.336 16.933 ;
     RECT  85.968 16.165 85.992 16.933 ;
     RECT  85.968 16.933 86.616 16.979 ;
     RECT  42.768 16.693 45.912 16.981 ;
     RECT  42.768 16.981 46.008 17.027 ;
     RECT  47.76 16.645 48.936 17.027 ;
     RECT  78 15.349 79.704 17.027 ;
     RECT  94.2 16.931 95.448 17.075 ;
     RECT  2.4 16.789 24.744 17.077 ;
     RECT  44.448 17.027 46.008 17.123 ;
     RECT  69.072 16.933 69.48 17.123 ;
     RECT  40.2 15.491 41.016 17.125 ;
     RECT  54.672 16.547 57.288 17.171 ;
     RECT  86.112 16.979 86.616 17.171 ;
     RECT  75.072 15.059 75.096 17.173 ;
     RECT  48.192 17.027 48.456 17.219 ;
     RECT  72.48 16.883 73.56 17.219 ;
     RECT  84.72 15.925 84.744 17.219 ;
     RECT  2.4 17.077 25.128 17.267 ;
     RECT  39.984 17.125 41.016 17.267 ;
     RECT  72.48 17.219 72.912 17.267 ;
     RECT  69.312 17.123 69.48 17.269 ;
     RECT  71.04 17.221 71.064 17.269 ;
     RECT  2.4 17.267 24.312 17.315 ;
     RECT  64.272 16.883 68.04 17.315 ;
     RECT  2.4 17.315 22.824 17.363 ;
     RECT  64.272 17.315 64.968 17.411 ;
     RECT  69.312 17.269 71.064 17.411 ;
     RECT  74.88 17.173 75.096 17.411 ;
     RECT  60.576 16.787 63.096 17.413 ;
     RECT  23.904 17.315 24.312 17.459 ;
     RECT  78 17.027 79.08 17.555 ;
     RECT  26.448 15.635 26.472 17.605 ;
     RECT  50.784 16.453 53.16 17.605 ;
     RECT  60.432 17.413 63.096 17.651 ;
     RECT  44.448 17.123 45.912 17.699 ;
     RECT  54.72 17.171 57.288 17.701 ;
     RECT  91.44 16.883 92.904 17.891 ;
     RECT  32.304 16.883 33.816 17.893 ;
     RECT  34.8 16.883 38.904 17.893 ;
     RECT  54.72 17.701 57.816 17.987 ;
     RECT  64.272 17.411 64.584 17.987 ;
     RECT  2.4 17.363 22.728 18.035 ;
     RECT  64.368 17.987 64.584 18.083 ;
     RECT  80.784 17.941 80.808 18.083 ;
     RECT  32.304 17.893 38.904 18.179 ;
     RECT  48.432 17.219 48.456 18.179 ;
     RECT  60.576 17.651 63.096 18.179 ;
     RECT  70.56 17.411 71.064 18.181 ;
     RECT  25.728 17.605 26.472 18.275 ;
     RECT  32.304 18.179 33.816 18.275 ;
     RECT  91.44 17.891 91.464 18.275 ;
     RECT  92.448 17.891 92.904 18.323 ;
     RECT  55.104 17.987 57.816 18.371 ;
     RECT  69.312 17.411 69.336 18.419 ;
     RECT  70.56 18.181 71.208 18.421 ;
     RECT  65.952 17.315 68.04 18.469 ;
     RECT  65.712 18.469 68.04 18.515 ;
     RECT  42.768 17.027 42.792 18.565 ;
     RECT  70.416 18.421 71.208 18.611 ;
     RECT  5.232 18.035 22.728 18.661 ;
     RECT  94.2 17.075 94.512 18.757 ;
     RECT  5.232 18.661 22.824 18.803 ;
     RECT  27.504 16.787 29.928 18.851 ;
     RECT  58.464 18.565 58.488 18.853 ;
     RECT  94.2 18.757 95.496 18.949 ;
     RECT  58.464 18.853 59.016 18.995 ;
     RECT  64.608 18.805 64.632 19.091 ;
     RECT  83.4 15.827 83.712 19.141 ;
     RECT  93.504 18.949 95.496 19.187 ;
     RECT  75.072 17.411 75.096 19.283 ;
     RECT  83.04 19.141 83.712 19.331 ;
     RECT  2.4 18.035 3.816 19.427 ;
     RECT  42.24 18.565 42.792 19.427 ;
     RECT  65.712 18.515 67.656 19.427 ;
     RECT  71.184 18.611 71.208 19.427 ;
     RECT  86.112 17.171 86.136 19.427 ;
     RECT  58.464 18.995 58.488 19.523 ;
     RECT  92.448 18.323 92.472 19.525 ;
     RECT  28.416 18.851 29.928 19.571 ;
     RECT  55.104 18.371 57.288 19.667 ;
     RECT  92.448 19.525 93.144 19.667 ;
     RECT  5.232 18.803 22.776 19.717 ;
     RECT  94.2 19.187 95.496 19.763 ;
     RECT  31.584 19.861 31.608 19.909 ;
     RECT  33.024 18.275 33.816 19.909 ;
     RECT  4.272 19.717 22.776 19.957 ;
     RECT  65.712 19.427 65.736 20.003 ;
     RECT  50.688 17.605 53.16 20.051 ;
     RECT  4.272 19.957 22.92 20.147 ;
     RECT  51 20.051 53.16 20.243 ;
     RECT  4.272 20.147 22.824 20.291 ;
     RECT  55.104 19.667 55.128 20.339 ;
     RECT  34.8 18.179 38.904 20.341 ;
     RECT  40.2 17.267 40.728 20.341 ;
     RECT  42.768 19.427 42.792 20.437 ;
     RECT  56.16 19.667 57.288 20.483 ;
     RECT  92.448 19.667 92.472 20.579 ;
     RECT  76.224 15.059 76.344 20.963 ;
     RECT  76.224 20.963 76.248 21.011 ;
     RECT  68.88 20.245 68.904 21.109 ;
     RECT  45.6 17.699 45.912 21.349 ;
     RECT  2.4 19.427 2.856 21.397 ;
     RECT  52.992 20.243 53.16 21.397 ;
     RECT  29.4 19.571 29.928 21.493 ;
     RECT  31.584 19.909 33.816 21.493 ;
     RECT  61.8 18.179 63.096 21.587 ;
     RECT  2.4 21.397 3.192 21.733 ;
     RECT  4.272 20.291 22.632 21.733 ;
     RECT  45.6 21.349 46.776 21.829 ;
     RECT  52.992 21.397 53.928 22.019 ;
     RECT  34.8 20.341 40.728 22.069 ;
     RECT  56.16 20.483 56.712 22.117 ;
     RECT  44.448 17.699 44.472 22.165 ;
     RECT  51 20.243 51.312 22.165 ;
     RECT  66.72 19.427 67.656 22.211 ;
     RECT  68.88 21.109 69.48 22.213 ;
     RECT  2.4 21.733 22.632 22.403 ;
     RECT  115.8 10.693 121.512 22.403 ;
     RECT  117.144 22.403 121.512 27.011 ;
     RECT  117.144 27.011 119.784 27.395 ;
     RECT  1.104 27.061 1.128 29.269 ;
     RECT  2.4 22.403 22.584 29.269 ;
     RECT  117.144 27.395 119.352 31.427 ;
     RECT  118.608 31.427 119.352 31.811 ;
     RECT  118.656 31.811 119.352 32.291 ;
     RECT  117.144 31.427 117.336 32.389 ;
     RECT  117.144 32.389 117.432 32.579 ;
     RECT  119.232 32.291 119.352 32.963 ;
     RECT  119.328 32.963 119.352 33.059 ;
     RECT  117.144 32.579 117.24 63.528 ;
     RECT  26.448 18.275 26.472 63.781 ;
     RECT  29.4 21.493 33.816 64.019 ;
     RECT  29.4 64.019 33.48 64.115 ;
     RECT  26.208 63.781 26.472 64.259 ;
     RECT  34.8 22.069 41.064 64.499 ;
     RECT  34.8 64.499 36.6 64.547 ;
     RECT  1.104 29.269 22.584 64.789 ;
     RECT  24 17.459 24.312 64.789 ;
     RECT  33.024 64.115 33.48 65.027 ;
     RECT  38.352 64.499 41.064 65.027 ;
     RECT  43.872 22.165 44.472 65.027 ;
     RECT  34.8 64.547 36.072 65.075 ;
     RECT  34.8 65.075 35.88 65.123 ;
     RECT  42.576 20.437 42.792 65.221 ;
     RECT  67.2 22.211 67.656 65.267 ;
     RECT  42.576 65.221 42.84 65.269 ;
     RECT  38.352 65.027 38.376 65.459 ;
     RECT  33.456 65.027 33.48 65.507 ;
     RECT  1.104 64.789 24.312 65.603 ;
     RECT  26.208 64.259 26.232 65.701 ;
     RECT  43.872 65.027 43.896 65.747 ;
     RECT  25.968 65.701 26.232 65.749 ;
     RECT  50.688 22.165 51.312 65.795 ;
     RECT  64.08 22.165 64.104 65.939 ;
     RECT  45.6 21.829 47.016 66.035 ;
     RECT  3.84 65.603 24.312 66.085 ;
     RECT  61.8 21.587 62.112 66.085 ;
     RECT  53.136 22.019 53.928 66.133 ;
     RECT  59.472 19.909 59.496 66.467 ;
     RECT  60.576 18.179 60.6 66.467 ;
     RECT  3.84 66.085 24.408 66.517 ;
     RECT  36.72 66.277 36.744 66.755 ;
     RECT  38.016 66.085 38.04 66.755 ;
     RECT  48.768 21.877 48.792 66.755 ;
     RECT  64.896 66.661 64.92 66.805 ;
     RECT  64.896 66.805 65.352 66.853 ;
     RECT  67.2 65.267 67.512 66.901 ;
     RECT  29.4 64.115 31.656 66.947 ;
     RECT  51 65.795 51.312 67.141 ;
     RECT  56.16 22.117 57.096 67.141 ;
     RECT  33.168 66.901 33.192 67.189 ;
     RECT  53.136 66.133 54.648 67.237 ;
     RECT  64.896 66.853 65.496 67.237 ;
     RECT  66.48 66.901 67.512 67.237 ;
     RECT  25.968 65.749 26.712 67.283 ;
     RECT  46.992 66.035 47.016 67.283 ;
     RECT  68.88 22.213 69.528 67.283 ;
     RECT  48.48 67.189 48.504 67.333 ;
     RECT  39.744 65.027 41.064 67.379 ;
     RECT  27.792 21.589 27.816 67.381 ;
     RECT  29.4 66.947 29.832 67.381 ;
     RECT  45.6 66.035 45.912 67.381 ;
     RECT  60.48 67.189 60.504 67.381 ;
     RECT  51 67.141 51.912 67.429 ;
     RECT  53.136 67.237 54.696 67.429 ;
     RECT  59.712 67.381 60.504 67.429 ;
     RECT  61.8 66.085 62.232 67.429 ;
     RECT  63.264 66.997 63.288 67.429 ;
     RECT  1.104 65.603 2.856 67.477 ;
     RECT  3.84 66.517 24.504 67.477 ;
     RECT  48.432 67.333 48.504 67.477 ;
     RECT  25.968 67.283 26.616 67.621 ;
     RECT  61.8 67.429 63.288 67.669 ;
     RECT  49.824 66.661 49.848 67.765 ;
     RECT  51 67.429 54.696 67.765 ;
     RECT  27.792 67.381 29.832 67.907 ;
     RECT  56.16 67.141 57.576 67.909 ;
     RECT  61.8 67.669 63.336 67.909 ;
     RECT  49.824 67.765 54.984 67.957 ;
     RECT  56.16 67.909 58.056 67.957 ;
     RECT  59.28 67.429 60.504 67.957 ;
     RECT  47.952 67.477 48.504 68.005 ;
     RECT  37.68 67.813 37.704 68.053 ;
     RECT  1.104 67.477 24.504 68.101 ;
     RECT  25.824 67.621 26.616 68.101 ;
     RECT  61.8 67.909 63.384 68.101 ;
     RECT  64.416 67.237 67.512 68.101 ;
     RECT  28.416 67.907 29.832 68.197 ;
     RECT  30.864 66.947 31.656 68.197 ;
     RECT  61.8 68.101 67.512 68.243 ;
     RECT  32.928 67.189 33.192 68.245 ;
     RECT  1.104 68.101 26.616 68.339 ;
     RECT  42.528 65.269 42.84 68.341 ;
     RECT  63.264 68.243 67.512 68.437 ;
     RECT  68.88 67.283 68.904 68.437 ;
     RECT  37.632 68.053 37.704 68.533 ;
     RECT  25.824 68.339 26.616 68.581 ;
     RECT  1.104 68.339 24.504 68.675 ;
     RECT  37.056 68.533 37.704 68.677 ;
     RECT  25.824 68.581 27.288 68.723 ;
     RECT  37.008 68.677 37.704 68.821 ;
     RECT  37.008 68.821 37.752 68.917 ;
     RECT  38.736 68.581 38.76 68.917 ;
     RECT  39.744 67.379 40.512 68.917 ;
     RECT  41.712 68.341 42.84 68.917 ;
     RECT  39.744 68.917 42.84 69.011 ;
     RECT  32.928 68.245 33.48 69.205 ;
     RECT  37.008 68.917 38.76 69.205 ;
     RECT  63.264 68.437 68.904 69.205 ;
     RECT  36.288 69.205 38.76 69.253 ;
     RECT  63.264 69.205 68.952 69.395 ;
     RECT  32.88 69.205 33.48 69.493 ;
     RECT  25.824 68.723 26.616 69.541 ;
     RECT  28.416 68.197 31.656 69.733 ;
     RECT  42.528 69.011 42.84 69.781 ;
     RECT  42.528 69.781 43.464 69.923 ;
     RECT  32.88 69.493 33.528 69.973 ;
     RECT  34.8 65.123 35.112 69.973 ;
     RECT  47.952 68.005 48.744 69.973 ;
     RECT  28.368 69.733 31.656 70.069 ;
     RECT  40.08 69.011 41.016 70.163 ;
     RECT  32.88 69.973 35.112 70.213 ;
     RECT  36.288 69.253 39 70.213 ;
     RECT  32.88 70.213 39 70.403 ;
     RECT  3.84 68.675 24.504 70.501 ;
     RECT  25.536 69.541 26.616 70.501 ;
     RECT  47.904 69.973 48.744 70.501 ;
     RECT  47.808 70.501 48.792 70.643 ;
     RECT  42.528 69.923 42.84 70.789 ;
     RECT  3.84 70.501 26.616 71.123 ;
     RECT  32.88 70.403 35.304 71.221 ;
     RECT  47.856 70.643 48.792 71.269 ;
     RECT  49.824 67.957 60.504 71.269 ;
     RECT  28.224 70.069 31.656 71.315 ;
     RECT  63.264 69.395 68.424 71.315 ;
     RECT  12.432 71.123 26.616 71.365 ;
     RECT  32.736 71.221 35.304 71.411 ;
     RECT  34.8 71.411 35.304 71.461 ;
     RECT  36.288 70.403 39 71.461 ;
     RECT  47.856 71.269 60.504 71.557 ;
     RECT  61.8 68.243 62.112 71.557 ;
     RECT  47.856 71.557 62.112 71.795 ;
     RECT  12.432 71.365 27.144 71.797 ;
     RECT  28.224 71.315 31.08 71.797 ;
     RECT  40.08 70.163 40.512 71.797 ;
     RECT  47.856 71.795 60.504 71.843 ;
     RECT  32.736 71.411 33.624 71.845 ;
     RECT  63.264 71.315 65.736 71.939 ;
     RECT  42.144 70.789 42.84 71.941 ;
     RECT  54.144 71.843 60.504 71.987 ;
     RECT  63.264 71.939 65.688 71.989 ;
     RECT  61.68 71.795 62.112 72.229 ;
     RECT  63.216 71.989 65.688 72.229 ;
     RECT  32.4 71.845 33.624 72.325 ;
     RECT  70.32 70.069 70.344 72.419 ;
     RECT  47.856 71.843 52.344 72.467 ;
     RECT  57.888 71.987 60.504 72.467 ;
     RECT  40.032 71.797 40.512 72.709 ;
     RECT  42.144 71.941 42.936 72.709 ;
     RECT  54.144 71.987 56.712 72.805 ;
     RECT  32.208 72.325 33.624 72.947 ;
     RECT  61.68 72.229 65.688 72.995 ;
     RECT  67.2 71.315 68.424 72.995 ;
     RECT  34.8 71.461 39 72.997 ;
     RECT  40.032 72.709 42.936 72.997 ;
     RECT  34.8 72.997 42.936 73.043 ;
     RECT  61.8 72.995 65.688 73.091 ;
     RECT  57.888 72.467 60.12 73.235 ;
     RECT  45.6 67.381 46.728 73.237 ;
     RECT  47.856 72.467 48.696 73.237 ;
     RECT  57.888 73.235 58.584 73.283 ;
     RECT  34.8 73.043 41.544 73.427 ;
     RECT  49.824 72.467 52.344 73.429 ;
     RECT  53.616 72.805 56.712 73.429 ;
     RECT  59.712 73.235 60.12 73.571 ;
     RECT  63.36 73.091 65.688 73.571 ;
     RECT  45.6 73.237 48.696 73.619 ;
     RECT  12.432 71.797 31.08 73.715 ;
     RECT  34.8 73.427 41.16 73.715 ;
     RECT  34.8 73.715 37.992 73.763 ;
     RECT  61.8 73.091 62.28 73.811 ;
     RECT  49.824 73.429 56.712 73.859 ;
     RECT  39.312 73.715 41.16 73.907 ;
     RECT  45.6 73.619 48.648 73.907 ;
     RECT  50.16 73.859 56.712 73.955 ;
     RECT  50.16 73.955 54.216 74.051 ;
     RECT  63.744 73.571 65.688 74.051 ;
     RECT  64.464 74.051 65.688 74.099 ;
     RECT  59.808 73.571 60.12 74.147 ;
     RECT  28.416 73.715 31.08 74.243 ;
     RECT  64.464 74.099 65.592 74.243 ;
     RECT  1.104 68.675 2.856 74.339 ;
     RECT  45.6 73.907 47.448 74.339 ;
     RECT  34.8 73.763 37.656 74.387 ;
     RECT  37.632 74.387 37.656 74.483 ;
     RECT  61.8 73.811 62.112 74.533 ;
     RECT  48.432 73.907 48.648 74.579 ;
     RECT  34.8 74.387 36.312 74.627 ;
     RECT  39.312 73.907 41.016 74.627 ;
     RECT  64.464 74.243 65.448 74.675 ;
     RECT  55.44 73.955 56.712 74.677 ;
     RECT  57.888 73.283 58.152 74.677 ;
     RECT  46.944 74.339 47.448 74.723 ;
     RECT  64.464 74.675 64.968 74.723 ;
     RECT  12.432 73.715 27.144 74.725 ;
     RECT  28.416 74.243 29.712 74.725 ;
     RECT  32.4 72.947 33.624 74.771 ;
     RECT  47.424 74.723 47.448 74.771 ;
     RECT  50.16 74.051 52.728 74.771 ;
     RECT  34.8 74.627 35.592 74.867 ;
     RECT  50.256 74.771 52.728 74.867 ;
     RECT  39.312 74.627 40.92 74.915 ;
     RECT  48.432 74.579 48.6 74.915 ;
     RECT  55.44 74.677 58.152 74.915 ;
     RECT  54.192 74.051 54.216 74.917 ;
     RECT  55.44 74.915 57.288 74.917 ;
     RECT  64.464 74.723 64.488 74.963 ;
     RECT  39.312 74.915 40.512 75.011 ;
     RECT  54.192 74.917 57.288 75.107 ;
     RECT  3.84 71.123 11.448 75.109 ;
     RECT  12.432 74.725 29.712 75.109 ;
     RECT  3.84 75.109 29.712 75.155 ;
     RECT  50.256 74.867 51.312 75.155 ;
     RECT  55.44 75.107 57.288 75.155 ;
     RECT  52.32 74.867 52.728 75.203 ;
     RECT  59.808 74.147 59.832 75.203 ;
     RECT  67.2 72.995 67.656 75.203 ;
     RECT  56.4 75.155 57.288 75.251 ;
     RECT  61.536 74.533 62.112 75.251 ;
     RECT  9.984 75.155 29.712 75.349 ;
     RECT  9.984 75.349 29.832 75.443 ;
     RECT  3.84 75.155 8.904 75.491 ;
     RECT  12.432 75.443 29.832 75.491 ;
     RECT  6.72 75.491 8.904 75.539 ;
     RECT  6.72 75.539 8.52 75.683 ;
     RECT  6.72 75.683 8.112 75.731 ;
     RECT  54.192 75.107 54.216 75.875 ;
     RECT  52.704 75.203 52.728 75.923 ;
     RECT  1.68 74.339 2.856 75.971 ;
     RECT  44.448 75.109 44.472 75.971 ;
     RECT  48.432 74.915 48.456 75.971 ;
     RECT  3.84 75.491 5.448 76.451 ;
     RECT  1.68 75.971 2.712 76.499 ;
     RECT  5.184 76.451 5.448 76.499 ;
     RECT  30.864 74.243 31.08 76.547 ;
     RECT  12.432 75.491 29.712 76.549 ;
     RECT  30.864 76.547 31.032 76.549 ;
     RECT  40.2 75.011 40.512 76.741 ;
     RECT  9.984 75.443 11.448 76.787 ;
     RECT  40.2 76.741 40.824 76.789 ;
     RECT  38.928 76.597 38.952 76.933 ;
     RECT  42.528 73.043 42.936 76.979 ;
     RECT  10.128 76.787 11.448 77.075 ;
     RECT  7.8 75.731 8.112 77.077 ;
     RECT  37.344 77.125 37.368 77.269 ;
     RECT  37.2 77.269 37.368 77.317 ;
     RECT  38.496 76.933 38.952 77.317 ;
     RECT  6.72 75.731 6.744 77.603 ;
     RECT  12.432 76.549 31.032 77.603 ;
     RECT  32.736 74.771 33.624 77.605 ;
     RECT  37.2 77.317 38.952 77.653 ;
     RECT  40.2 76.789 41.112 77.653 ;
     RECT  5.184 76.499 5.208 77.891 ;
     RECT  10.848 77.075 11.448 78.131 ;
     RECT  42.528 76.979 42.84 78.373 ;
     RECT  7.8 77.077 8.808 78.659 ;
     RECT  37.2 77.653 41.112 79.141 ;
     RECT  42.096 78.373 42.84 79.141 ;
     RECT  32.448 77.605 33.624 79.237 ;
     RECT  12.432 77.603 24.456 79.331 ;
     RECT  34.8 74.867 35.112 79.429 ;
     RECT  32.304 79.237 33.624 79.477 ;
     RECT  34.8 79.429 35.352 79.477 ;
     RECT  11.424 78.131 11.448 79.523 ;
     RECT  37.2 79.141 42.84 79.765 ;
     RECT  25.632 77.603 31.032 80.005 ;
     RECT  36.768 79.765 42.84 80.101 ;
     RECT  32.304 79.477 35.352 80.341 ;
     RECT  25.632 80.005 31.176 80.581 ;
     RECT  32.16 80.341 35.352 80.581 ;
     RECT  25.632 80.581 35.352 80.773 ;
     RECT  36.624 80.101 42.84 80.773 ;
     RECT  25.632 80.773 42.84 81.493 ;
     RECT  12.432 79.331 24.408 82.211 ;
     RECT  12.432 82.211 24.312 82.451 ;
     RECT  3.84 76.451 3.96 82.499 ;
     RECT  12.432 82.451 18.912 82.979 ;
     RECT  20.208 82.451 24.312 83.027 ;
     RECT  12.528 82.979 18.912 83.363 ;
     RECT  17.424 83.363 18.912 83.603 ;
     RECT  20.4 83.027 24.312 83.891 ;
     RECT  12.528 83.363 16.392 84.131 ;
     RECT  2.4 76.499 2.712 84.249 ;
     RECT  7.8 78.659 8.112 84.249 ;
     RECT  12.528 84.131 13.512 84.249 ;
     RECT  17.52 83.603 18.912 84.249 ;
     RECT  45.6 74.339 45.912 84.249 ;
     RECT  51 75.155 51.312 84.249 ;
     RECT  56.4 75.251 56.712 84.249 ;
     RECT  61.8 75.251 62.112 84.249 ;
     RECT  67.2 75.203 67.512 84.249 ;
     RECT  72.6 17.267 72.912 84.249 ;
     RECT  78 17.555 78.312 84.249 ;
     RECT  83.4 19.331 83.712 84.249 ;
     RECT  88.8 15.971 89.112 84.249 ;
     RECT  94.2 19.763 94.512 84.249 ;
     RECT  99.6 13.043 99.912 84.249 ;
     RECT  105 2.151 105.312 84.249 ;
     RECT  110.4 2.151 110.712 84.249 ;
     RECT  115.8 22.403 116.112 84.249 ;
     RECT  121.2 27.011 121.512 84.249 ;
     RECT  126.6 2.151 126.912 84.249 ;
     RECT  132 2.151 132.312 84.249 ;
     RECT  137.4 2.151 137.712 84.249 ;
     RECT  2.4 84.249 2.52 84.263 ;
     RECT  7.8 84.249 7.92 84.263 ;
     RECT  12.528 84.249 13.32 84.263 ;
     RECT  17.52 84.249 18.72 84.263 ;
     RECT  45.6 84.249 45.72 84.263 ;
     RECT  51 84.249 51.12 84.263 ;
     RECT  56.4 84.249 56.52 84.263 ;
     RECT  61.8 84.249 61.92 84.263 ;
     RECT  67.2 84.249 67.32 84.263 ;
     RECT  72.6 84.249 72.72 84.263 ;
     RECT  78 84.249 78.12 84.263 ;
     RECT  83.4 84.249 83.52 84.263 ;
     RECT  88.8 84.249 88.92 84.263 ;
     RECT  94.2 84.249 94.32 84.263 ;
     RECT  99.6 84.249 99.72 84.263 ;
     RECT  105 84.249 105.12 84.263 ;
     RECT  110.4 84.249 110.52 84.263 ;
     RECT  115.8 84.249 115.92 84.263 ;
     RECT  121.2 84.249 121.32 84.263 ;
     RECT  126.6 84.249 126.72 84.263 ;
     RECT  132 84.249 132.12 84.263 ;
     RECT  137.4 84.249 137.52 84.263 ;
     RECT  14.784 84.131 16.392 84.371 ;
     RECT  15.168 84.371 16.392 84.563 ;
     RECT  12.528 84.263 12.552 84.611 ;
     RECT  3.84 82.499 3.864 84.659 ;
     RECT  20.832 83.891 24.312 84.755 ;
     RECT  20.832 84.755 23.064 84.803 ;
     RECT  22.368 84.803 23.064 84.851 ;
     RECT  25.536 81.493 42.84 85.093 ;
     RECT  25.392 85.093 42.84 85.141 ;
     RECT  17.52 84.263 17.64 85.235 ;
     RECT  15.168 84.563 15.768 85.283 ;
     RECT  17.616 85.235 17.64 85.331 ;
     RECT  20.832 84.803 21.384 85.379 ;
     RECT  20.832 85.379 21.24 85.427 ;
     RECT  22.368 84.851 22.728 86.051 ;
     RECT  21.216 85.427 21.24 86.147 ;
     RECT  15.168 85.283 15.192 86.195 ;
     RECT  24.528 85.141 42.84 86.224 ;
     RECT  22.704 86.051 22.728 86.243 ;
     RECT  41.256 0.467 42.24 1.427 ;
     RECT  42.552 0.803 43.824 2.339 ;
     RECT  47.88 1.235 49.152 1.331 ;
     RECT  47.88 1.331 49.296 2.437 ;
     RECT  41.112 1.427 42.24 1.859 ;
     RECT  26.712 1.763 27.984 2.243 ;
     RECT  52.344 1.763 53.328 2.291 ;
     RECT  67.752 1.763 67.896 1.813 ;
     RECT  66.864 1.811 67.152 1.859 ;
     RECT  67.752 1.813 68.928 1.955 ;
     RECT  41.112 1.859 42.384 2.725 ;
     RECT  66.864 1.859 67.2 3.061 ;
     RECT  33.768 1.907 34.8 2.291 ;
     RECT  26.568 2.243 27.984 2.291 ;
     RECT  26.448 2.291 26.472 3.253 ;
     RECT  33.576 2.291 34.8 3.349 ;
     RECT  51.48 2.291 53.328 2.579 ;
     RECT  42.552 2.339 45.024 2.483 ;
     RECT  47.976 2.437 49.296 2.675 ;
     RECT  42.552 2.483 45.408 2.629 ;
     RECT  59.976 2.531 60.96 2.819 ;
     RECT  51.312 2.579 53.328 2.963 ;
     RECT  42.552 2.629 43.68 2.677 ;
     RECT  43.704 2.629 45.408 3.541 ;
     RECT  47.736 2.675 49.296 2.725 ;
     RECT  41.256 2.725 42.384 3.491 ;
     RECT  47.736 2.725 48.912 3.011 ;
     RECT  49.032 2.819 50.016 2.867 ;
     RECT  48.936 2.867 50.16 3.011 ;
     RECT  51.312 2.963 53.856 3.107 ;
     RECT  57.528 2.963 58.8 4.067 ;
     RECT  13.512 3.013 14.832 3.877 ;
     RECT  14.856 3.013 16.224 4.693 ;
     RECT  51.312 3.107 53.904 3.301 ;
     RECT  51.312 3.301 52.512 5.795 ;
     RECT  52.536 3.301 53.904 4.117 ;
     RECT  22.584 3.349 24 5.269 ;
     RECT  37.8 3.395 38.784 3.731 ;
     RECT  41.064 3.491 42.384 5.317 ;
     RECT  43.704 3.541 44.736 3.589 ;
     RECT  37.8 3.731 38.88 4.019 ;
     RECT  43.464 3.731 44.736 3.875 ;
     RECT  43.176 3.875 44.736 3.923 ;
     RECT  13.512 3.877 14.592 4.357 ;
     RECT  43.176 3.923 45.024 4.835 ;
     RECT  37.656 4.019 38.88 5.221 ;
     RECT  58.824 4.019 59.808 4.067 ;
     RECT  67.512 4.019 67.752 5.077 ;
     RECT  58.824 4.067 59.952 4.115 ;
     RECT  26.808 4.069 28.128 4.451 ;
     RECT  52.536 4.117 53.664 4.259 ;
     RECT  62.112 4.117 63.456 4.307 ;
     RECT  52.536 4.259 54.336 4.261 ;
     RECT  52.92 4.261 54.336 4.595 ;
     RECT  62.112 4.307 63.144 4.645 ;
     RECT  118.824 4.405 119.856 4.453 ;
     RECT  26.472 4.451 28.128 4.789 ;
     RECT  20.52 4.501 21.936 4.645 ;
     RECT  24.312 4.549 25.536 4.739 ;
     RECT  39.096 4.691 40.2 5.843 ;
     RECT  14.856 4.693 15.84 5.701 ;
     RECT  26.472 4.789 27.888 5.027 ;
     RECT  44.64 4.835 45.024 4.885 ;
     RECT  16.248 4.981 17.568 5.221 ;
     RECT  17.592 4.981 18.6 6.325 ;
     RECT  31.752 5.171 33.024 5.747 ;
     RECT  37.8 5.221 38.88 5.363 ;
     RECT  22.824 5.269 24 5.603 ;
     RECT  41.304 5.317 42.384 5.459 ;
     RECT  37.656 5.363 38.88 6.805 ;
     RECT  41.064 5.459 42.384 5.509 ;
     RECT  41.064 5.509 42.096 5.747 ;
     RECT  22.632 5.603 24 6.853 ;
     RECT  46.104 5.699 47.136 5.747 ;
     RECT  29.928 5.795 30.024 6.901 ;
     RECT  38.904 5.843 40.2 9.397 ;
     RECT  55.128 6.323 56.208 9.061 ;
     RECT  76.968 6.373 78 6.709 ;
     RECT  87.672 6.661 88.8 6.803 ;
     RECT  78.888 6.709 79.92 6.899 ;
     RECT  87.24 6.803 88.8 7.813 ;
     RECT  70.968 6.805 72.432 8.629 ;
     RECT  89.112 6.805 90.192 7.667 ;
     RECT  22.824 6.853 24 7.667 ;
     RECT  76.968 6.899 78 7.379 ;
     RECT  78.744 6.899 79.92 7.235 ;
     RECT  86.928 6.995 87.216 7.237 ;
     RECT  117.048 7.093 118.032 10.693 ;
     RECT  85.896 7.237 87.216 7.667 ;
     RECT  76.872 7.379 78 8.341 ;
     RECT  52.896 7.571 52.992 8.677 ;
     RECT  64.992 7.571 65.016 7.957 ;
     RECT  22.728 7.667 24 9.013 ;
     RECT  85.872 7.667 87.216 7.957 ;
     RECT  87.384 7.813 88.8 7.955 ;
     RECT  83.712 7.859 83.928 7.957 ;
     RECT  64.992 7.957 65.808 8.677 ;
     RECT  65.832 7.957 67.2 8.965 ;
     RECT  83.712 7.957 84.768 13.379 ;
     RECT  84.792 7.957 87.216 8.533 ;
     RECT  76.92 8.341 78 8.437 ;
     RECT  76.968 8.437 78 8.821 ;
     RECT  84.792 8.533 86.448 8.675 ;
     RECT  84.792 8.675 87.072 8.869 ;
     RECT  51.48 8.677 52.992 9.157 ;
     RECT  64.992 8.677 65.712 8.773 ;
     RECT  70.968 8.771 72.384 9.395 ;
     RECT  63.768 8.773 65.712 8.917 ;
     RECT  84.792 8.869 85.968 10.789 ;
     RECT  85.992 8.869 87.072 9.347 ;
     RECT  63.768 8.917 65.232 8.963 ;
     RECT  63.624 8.963 65.232 9.059 ;
     RECT  53.304 8.965 54.576 12.035 ;
     RECT  65.928 8.965 67.2 9.203 ;
     RECT  76.92 9.011 77.904 10.307 ;
     RECT  22.728 9.013 23.904 12.851 ;
     RECT  26.472 9.059 26.808 9.925 ;
     RECT  64.944 9.059 65.232 9.733 ;
     RECT  51.48 9.157 52.896 9.397 ;
     RECT  65.832 9.203 67.2 12.517 ;
     RECT  85.992 9.347 87.216 9.731 ;
     RECT  39 9.397 40.2 10.883 ;
     RECT  51.864 9.397 52.896 10.213 ;
     RECT  5.688 9.637 6.96 10.307 ;
     RECT  55.128 9.731 56.208 12.709 ;
     RECT  40.512 9.827 41.064 10.309 ;
     RECT  25.128 9.925 26.448 10.259 ;
     RECT  26.472 9.925 28.224 10.501 ;
     RECT  28.248 9.925 29.4 9.973 ;
     RECT  44.136 9.973 45.6 10.117 ;
     RECT  24.312 10.259 26.448 11.413 ;
     RECT  43.8 10.259 44.976 10.355 ;
     RECT  6.768 10.307 6.96 11.269 ;
     RECT  40.512 10.309 41.808 11.125 ;
     RECT  44.448 10.355 44.976 11.653 ;
     RECT  26.472 10.501 27.552 11.939 ;
     RECT  48.48 10.595 48.504 11.317 ;
     RECT  89.544 10.597 90.72 10.883 ;
     RECT  38.808 10.883 40.2 13.093 ;
     RECT  41.304 11.171 41.832 11.317 ;
     RECT  41.304 11.317 42.72 13.331 ;
     RECT  48.48 11.317 48.96 11.413 ;
     RECT  25.128 11.413 26.448 11.555 ;
     RECT  45.912 11.413 47.424 11.699 ;
     RECT  47.448 11.413 48.96 11.699 ;
     RECT  97.416 11.413 98.88 13.043 ;
     RECT  91.32 11.461 92.736 12.517 ;
     RECT  92.76 11.461 94.08 11.893 ;
     RECT  24.552 11.555 26.448 12.613 ;
     RECT  45.912 11.699 46.056 12.133 ;
     RECT  84.984 11.795 85.968 12.371 ;
     RECT  26.472 11.939 28.416 12.901 ;
     RECT  67.656 12.227 67.704 12.565 ;
     RECT  76.536 12.229 77.904 12.419 ;
     RECT  30.792 12.277 31.776 12.419 ;
     RECT  31.8 12.277 33.024 12.419 ;
     RECT  76.344 12.419 77.904 12.517 ;
     RECT  92.952 12.419 94.08 13.429 ;
     RECT  76.344 12.517 77.472 13.043 ;
     RECT  91.464 12.517 92.736 12.853 ;
     RECT  67.656 12.565 68.928 12.707 ;
     RECT  25.224 12.613 26.448 12.803 ;
     RECT  22.632 12.851 23.904 16.261 ;
     RECT  91.464 12.853 92.544 13.525 ;
     RECT  26.472 12.901 28.272 12.949 ;
     RECT  26.472 12.949 27.744 14.579 ;
     RECT  76.248 13.043 77.472 13.091 ;
     RECT  97.416 13.043 99.6 13.141 ;
     RECT  38.904 13.093 40.2 14.389 ;
     RECT  97.416 13.141 98.4 13.523 ;
     RECT  98.424 13.141 99.6 13.523 ;
     RECT  94.512 13.331 95.496 13.621 ;
     RECT  91.464 13.525 92.496 14.533 ;
     RECT  53.304 13.621 54.768 14.101 ;
     RECT  69.96 13.621 71.28 14.291 ;
     RECT  71.304 13.621 72.6 14.339 ;
     RECT  94.512 13.621 95.712 13.763 ;
     RECT  63.096 13.715 63.24 14.965 ;
     RECT  75.792 13.715 75.84 14.533 ;
     RECT  51.312 14.099 52.992 15.301 ;
     RECT  43.032 14.101 44.448 14.243 ;
     RECT  53.688 14.101 54.768 14.243 ;
     RECT  72.912 14.101 74.064 15.061 ;
     RECT  42.72 14.147 42.768 15.157 ;
     RECT  42.84 14.243 44.448 14.389 ;
     RECT  53.304 14.243 54.768 14.773 ;
     RECT  78.312 14.291 79.296 15.349 ;
     RECT  2.712 14.339 2.952 14.773 ;
     RECT  71.376 14.339 72.6 14.533 ;
     RECT  38.904 14.389 40.08 15.251 ;
     RECT  42.84 14.389 44.304 14.531 ;
     RECT  60.6 14.389 61.632 14.531 ;
     RECT  42.84 14.531 44.448 15.253 ;
     RECT  60.6 14.531 61.8 16.645 ;
     RECT  71.4 14.533 72.6 14.675 ;
     RECT  74.76 14.533 75.84 14.675 ;
     RECT  26.472 14.579 27.792 15.013 ;
     RECT  74.088 14.675 75.84 14.677 ;
     RECT  49.752 14.677 50.88 14.819 ;
     RECT  74.088 14.677 75.072 15.107 ;
     RECT  91.464 14.723 92.736 15.203 ;
     RECT  2.712 14.773 4.032 15.349 ;
     RECT  53.304 14.773 54.48 14.867 ;
     RECT  49.728 14.819 50.88 14.869 ;
     RECT  53.16 14.867 54.48 16.259 ;
     RECT  49.728 14.869 50.832 15.349 ;
     RECT  26.808 15.013 27.792 15.155 ;
     RECT  75.096 15.059 76.224 19.283 ;
     RECT  73.56 15.107 75.072 17.173 ;
     RECT  26.472 15.155 27.792 16.501 ;
     RECT  41.256 15.157 42.768 15.491 ;
     RECT  91.464 15.203 94.08 15.925 ;
     RECT  38.904 15.251 40.2 17.125 ;
     RECT  43.272 15.253 44.448 15.395 ;
     RECT  51.432 15.301 52.992 15.493 ;
     RECT  2.856 15.349 4.032 16.501 ;
     RECT  5.016 15.349 6.144 16.789 ;
     RECT  49.56 15.349 50.832 16.259 ;
     RECT  82.152 15.349 83.28 15.827 ;
     RECT  42.84 15.395 44.448 16.549 ;
     RECT  45.912 15.397 47.328 16.259 ;
     RECT  63.816 15.397 64.944 15.443 ;
     RECT  63.24 15.443 64.944 16.405 ;
     RECT  26.352 15.635 26.448 17.077 ;
     RECT  82.152 15.827 83.4 16.259 ;
     RECT  67.656 15.925 68.976 16.405 ;
     RECT  83.712 15.925 84.72 17.219 ;
     RECT  89.112 15.925 90.624 16.259 ;
     RECT  91.464 15.925 92.448 16.069 ;
     RECT  92.472 15.925 94.08 16.693 ;
     RECT  84.744 16.165 85.968 16.979 ;
     RECT  45.912 16.259 46.008 16.981 ;
     RECT  50.688 16.259 50.832 16.453 ;
     RECT  53.16 16.259 54.672 17.171 ;
     RECT  63.24 16.405 64.416 16.597 ;
     RECT  50.688 16.453 50.784 17.605 ;
     RECT  26.472 16.501 27.504 18.851 ;
     RECT  57.288 16.547 57.384 17.701 ;
     RECT  42.84 16.549 43.824 16.693 ;
     RECT  63.096 16.787 64.272 17.987 ;
     RECT  33.816 16.883 34.8 17.893 ;
     RECT  68.04 16.883 69.072 17.123 ;
     RECT  72.096 16.883 72.48 17.221 ;
     RECT  92.904 16.883 94.08 16.931 ;
     RECT  92.904 16.931 94.2 18.323 ;
     RECT  84.744 16.979 86.112 17.219 ;
     RECT  25.128 17.077 26.448 17.267 ;
     RECT  68.04 17.123 69.312 18.419 ;
     RECT  38.904 17.125 39.984 17.267 ;
     RECT  73.56 17.173 74.88 17.219 ;
     RECT  71.064 17.221 72.48 17.267 ;
     RECT  24.312 17.267 26.448 17.605 ;
     RECT  38.904 17.267 40.2 20.341 ;
     RECT  40.728 17.267 41.016 18.565 ;
     RECT  71.064 17.267 72.6 18.181 ;
     RECT  22.824 17.315 23.904 17.363 ;
     RECT  64.968 17.315 65.952 17.411 ;
     RECT  22.728 17.363 23.904 17.459 ;
     RECT  64.584 17.411 65.952 18.083 ;
     RECT  69.336 17.411 70.56 18.419 ;
     RECT  22.728 17.459 24 18.661 ;
     RECT  24.312 17.605 25.728 18.275 ;
     RECT  44.472 17.699 45.6 65.027 ;
     RECT  91.464 17.891 92.448 18.275 ;
     RECT  63.096 17.987 64.368 18.083 ;
     RECT  3.816 18.035 5.232 19.427 ;
     RECT  63.096 18.083 65.952 18.469 ;
     RECT  33.816 18.179 34.8 64.019 ;
     RECT  60.6 18.179 61.8 66.467 ;
     RECT  71.208 18.181 72.6 19.427 ;
     RECT  92.472 18.323 94.2 18.949 ;
     RECT  57.288 18.371 57.816 18.565 ;
     RECT  70.416 18.419 70.56 18.421 ;
     RECT  63.096 18.469 65.712 18.805 ;
     RECT  40.728 18.565 42.24 19.427 ;
     RECT  57.288 18.565 58.464 19.523 ;
     RECT  22.824 18.661 24 18.803 ;
     RECT  22.776 18.803 24 19.957 ;
     RECT  63.096 18.805 64.608 19.091 ;
     RECT  64.632 18.805 65.712 19.091 ;
     RECT  92.472 18.949 93.504 19.187 ;
     RECT  92.472 19.187 94.2 19.525 ;
     RECT  2.856 19.427 5.232 19.717 ;
     RECT  42.576 19.427 42.768 20.437 ;
     RECT  65.736 19.427 66.72 20.003 ;
     RECT  93.144 19.525 94.2 19.667 ;
     RECT  55.128 19.667 56.16 20.339 ;
     RECT  2.856 19.717 4.272 21.397 ;
     RECT  31.608 19.861 33.024 19.909 ;
     RECT  59.496 19.909 60.576 66.467 ;
     RECT  22.92 19.957 24 20.147 ;
     RECT  22.824 20.147 24 20.291 ;
     RECT  67.656 20.245 68.88 65.267 ;
     RECT  22.632 20.291 24 22.403 ;
     RECT  3.192 21.397 4.272 21.733 ;
     RECT  26.472 21.589 27.792 64.259 ;
     RECT  41.064 22.069 42.576 65.269 ;
     RECT  42.792 22.165 43.872 65.221 ;
     RECT  22.584 22.403 24 64.789 ;
     RECT  116.112 22.403 117.144 63.528 ;
     RECT  119.784 27.011 121.2 27.395 ;
     RECT  1.128 27.061 2.4 29.269 ;
     RECT  117.336 31.427 118.608 31.811 ;
     RECT  117.336 31.811 118.656 32.291 ;
     RECT  117.336 32.291 117.432 32.389 ;
     RECT  33.48 64.019 34.8 65.507 ;
     RECT  31.656 64.115 33.024 65.027 ;
     RECT  26.232 64.259 27.792 65.749 ;
     RECT  38.376 65.027 39.744 65.459 ;
     RECT  42.84 65.221 43.872 65.747 ;
     RECT  67.512 65.267 68.88 68.437 ;
     RECT  41.064 65.269 42.528 67.379 ;
     RECT  2.856 65.603 3.84 67.477 ;
     RECT  26.712 65.749 27.792 67.283 ;
     RECT  50.688 65.795 51 66.661 ;
     RECT  64.08 65.939 64.104 66.661 ;
     RECT  45.912 66.035 46.992 67.283 ;
     RECT  54.648 66.133 56.16 67.237 ;
     RECT  36.744 66.277 38.016 66.755 ;
     RECT  59.472 66.467 61.8 67.189 ;
     RECT  24.504 66.517 25.968 67.621 ;
     RECT  48.792 66.661 49.824 66.755 ;
     RECT  49.848 66.661 51 67.765 ;
     RECT  64.08 66.661 64.896 66.997 ;
     RECT  37.632 66.755 37.704 67.813 ;
     RECT  48.768 66.755 49.824 67.189 ;
     RECT  31.656 66.901 33.168 67.189 ;
     RECT  65.496 66.901 66.48 67.237 ;
     RECT  29.832 66.947 30.864 68.197 ;
     RECT  62.232 66.997 63.264 67.429 ;
     RECT  63.288 66.997 64.896 67.237 ;
     RECT  51.912 67.141 53.136 67.429 ;
     RECT  31.656 67.189 32.928 69.205 ;
     RECT  47.016 67.189 48.48 67.283 ;
     RECT  48.504 67.189 49.824 68.005 ;
     RECT  59.472 67.189 60.48 67.381 ;
     RECT  60.504 67.189 61.8 71.557 ;
     RECT  54.696 67.237 56.16 67.765 ;
     RECT  63.288 67.237 64.416 67.669 ;
     RECT  26.616 67.283 27.792 67.907 ;
     RECT  45.912 67.283 48.48 67.333 ;
     RECT  45.912 67.333 48.432 67.381 ;
     RECT  40.512 67.379 42.528 68.341 ;
     RECT  46.728 67.381 48.432 67.477 ;
     RECT  59.472 67.381 59.712 67.429 ;
     RECT  46.728 67.477 47.952 69.973 ;
     RECT  24.504 67.621 25.824 68.101 ;
     RECT  63.336 67.669 64.416 67.909 ;
     RECT  54.984 67.765 56.16 67.957 ;
     RECT  37.632 67.813 37.68 68.053 ;
     RECT  26.616 67.907 28.416 68.581 ;
     RECT  58.056 67.909 59.28 67.957 ;
     RECT  63.384 67.909 64.416 68.101 ;
     RECT  48.744 68.005 49.824 70.501 ;
     RECT  62.112 68.243 63.264 71.989 ;
     RECT  33.48 68.245 34.8 69.493 ;
     RECT  24.504 68.339 25.824 69.541 ;
     RECT  40.512 68.341 41.712 68.917 ;
     RECT  27.288 68.581 28.416 68.723 ;
     RECT  37.704 68.581 38.736 68.821 ;
     RECT  38.76 68.581 39.744 69.011 ;
     RECT  2.856 68.675 3.84 75.971 ;
     RECT  28.224 68.723 28.416 69.733 ;
     RECT  37.752 68.821 38.736 68.917 ;
     RECT  38.76 69.011 40.08 69.253 ;
     RECT  41.016 69.011 42.528 70.163 ;
     RECT  31.656 69.205 32.88 71.221 ;
     RECT  35.112 69.205 36.288 70.213 ;
     RECT  39 69.253 40.08 71.797 ;
     RECT  33.528 69.493 34.8 69.973 ;
     RECT  24.504 69.541 25.536 70.501 ;
     RECT  28.224 69.733 28.368 70.069 ;
     RECT  46.728 69.973 47.904 70.501 ;
     RECT  42.144 70.163 42.528 70.789 ;
     RECT  35.304 70.403 36.288 71.461 ;
     RECT  46.728 70.501 47.808 70.643 ;
     RECT  48.792 70.501 49.824 71.269 ;
     RECT  46.728 70.643 47.856 73.237 ;
     RECT  11.448 71.123 12.432 75.109 ;
     RECT  31.656 71.221 32.736 71.315 ;
     RECT  31.08 71.315 32.736 71.845 ;
     RECT  65.736 71.315 67.2 71.939 ;
     RECT  27.144 71.365 28.224 71.797 ;
     RECT  33.624 71.411 34.8 79.477 ;
     RECT  60.504 71.795 61.68 72.467 ;
     RECT  39 71.797 40.032 72.997 ;
     RECT  52.344 71.843 54.144 72.805 ;
     RECT  31.08 71.845 32.4 72.325 ;
     RECT  65.688 71.939 67.2 74.099 ;
     RECT  56.712 71.987 57.888 74.677 ;
     RECT  62.112 71.989 63.216 72.229 ;
     RECT  31.08 72.325 32.208 72.947 ;
     RECT  48.696 72.467 49.824 73.619 ;
     RECT  52.344 72.805 53.616 73.429 ;
     RECT  31.08 72.947 32.4 74.771 ;
     RECT  41.544 73.043 42.528 73.427 ;
     RECT  62.28 73.091 63.36 73.571 ;
     RECT  58.584 73.235 59.712 73.283 ;
     RECT  41.16 73.427 42.528 73.907 ;
     RECT  62.28 73.571 63.744 73.811 ;
     RECT  48.648 73.619 49.824 73.859 ;
     RECT  27.144 73.715 28.416 74.725 ;
     RECT  37.992 73.715 39.312 73.763 ;
     RECT  48.648 73.859 50.16 74.579 ;
     RECT  41.016 73.907 42.528 74.627 ;
     RECT  47.448 73.907 48.432 74.771 ;
     RECT  54.216 73.955 55.44 74.917 ;
     RECT  52.728 74.051 54.192 75.875 ;
     RECT  29.712 74.243 30.864 75.349 ;
     RECT  45.912 74.339 46.944 74.723 ;
     RECT  36.312 74.387 37.632 74.483 ;
     RECT  45.912 74.723 47.424 74.771 ;
     RECT  51.312 74.867 52.32 75.203 ;
     RECT  54.216 75.107 55.44 75.155 ;
     RECT  42.936 75.109 44.448 75.971 ;
     RECT  44.472 75.109 45.6 75.971 ;
     RECT  8.904 75.155 9.984 75.539 ;
     RECT  51.312 75.203 52.704 75.923 ;
     RECT  29.832 75.349 30.864 75.491 ;
     RECT  11.448 75.443 12.432 79.523 ;
     RECT  5.448 75.491 6.72 76.499 ;
     RECT  29.712 75.491 30.864 76.549 ;
     RECT  8.52 75.539 9.984 75.683 ;
     RECT  8.112 75.683 9.984 76.787 ;
     RECT  6.744 75.731 7.8 77.603 ;
     RECT  2.712 75.971 3.84 84.249 ;
     RECT  3.96 76.451 5.184 77.891 ;
     RECT  5.208 76.499 6.72 77.603 ;
     RECT  31.032 76.547 31.08 77.605 ;
     RECT  38.952 76.597 40.2 77.653 ;
     RECT  8.112 76.787 10.128 77.075 ;
     RECT  41.112 76.789 42.528 78.373 ;
     RECT  8.112 77.075 8.808 77.077 ;
     RECT  37.368 77.125 38.496 77.317 ;
     RECT  24.456 77.603 25.632 79.331 ;
     RECT  31.032 77.605 32.448 79.237 ;
     RECT  41.112 78.373 42.096 79.141 ;
     RECT  31.032 79.237 32.304 80.005 ;
     RECT  24.408 79.331 25.632 81.493 ;
     RECT  35.352 79.765 36.768 80.101 ;
     RECT  31.176 80.005 32.304 80.341 ;
     RECT  35.352 80.101 36.624 80.773 ;
     RECT  31.176 80.341 32.16 80.581 ;
     RECT  24.408 81.493 25.536 82.211 ;
     RECT  24.312 82.211 25.536 84.755 ;
     RECT  18.912 82.451 20.208 83.027 ;
     RECT  18.912 83.027 20.4 83.891 ;
     RECT  16.392 83.363 17.424 83.603 ;
     RECT  16.392 83.603 17.52 84.563 ;
     RECT  13.512 84.131 14.784 84.249 ;
     RECT  2.52 84.249 3.84 84.263 ;
     RECT  13.32 84.249 14.784 84.263 ;
     RECT  23.064 84.755 25.536 84.851 ;
     RECT  21.384 84.803 22.368 85.379 ;
     RECT  24.528 84.851 25.536 85.093 ;
     RECT  24.528 85.093 25.392 85.141 ;
     RECT  21.24 85.379 22.368 86.051 ;
     RECT  21.24 86.051 22.704 86.147 ;
  END
END ot_s81_pq_qb_bankx_native
END LIBRARY
